VERSION 5.8 ;
BUSBITCHARS "[]" ;
DIVIDERCHAR "/" ;
UNITS
    DATABASE MICRONS 1000 ;
END UNITS

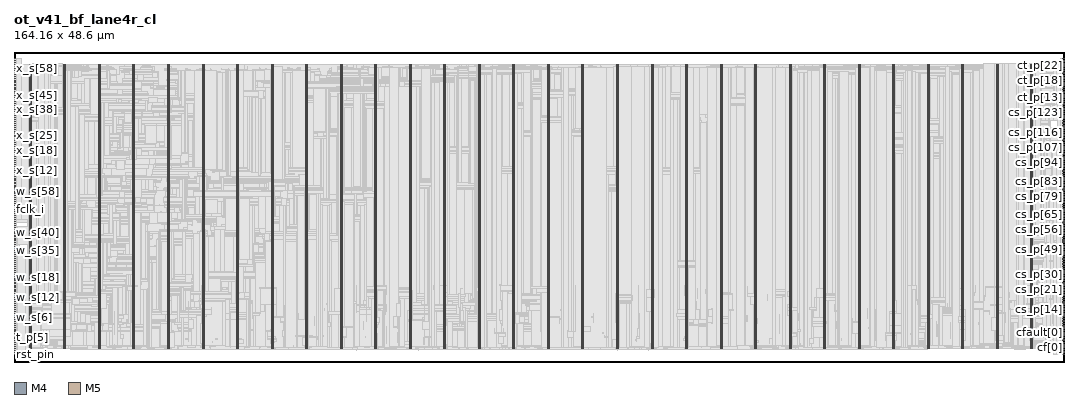
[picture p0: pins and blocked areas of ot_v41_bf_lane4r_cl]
MACRO ot_v41_bf_lane4r_cl
  FOREIGN ot_v41_bf_lane4r_cl 0 0 ;
  CLASS BLOCK ;
  SIZE 164.16 BY 48.6 ;
  PIN cf[0]
    DIRECTION OUTPUT ;
    USE SIGNAL ;
    PORT
      LAYER M4 ;
        RECT  163.968 2.208 164.16 2.232 ;
    END
  END cf[0]
  PIN cf[1]
    DIRECTION OUTPUT ;
    USE SIGNAL ;
    PORT
      LAYER M4 ;
        RECT  163.968 2.496 164.16 2.52 ;
    END
  END cf[1]
  PIN cf[2]
    DIRECTION OUTPUT ;
    USE SIGNAL ;
    PORT
      LAYER M4 ;
        RECT  163.968 2.784 164.16 2.808 ;
    END
  END cf[2]
  PIN cf[3]
    DIRECTION OUTPUT ;
    USE SIGNAL ;
    PORT
      LAYER M4 ;
        RECT  163.968 3.024 164.16 3.048 ;
    END
  END cf[3]
  PIN cfault[0]
    DIRECTION OUTPUT ;
    USE SIGNAL ;
    PORT
      LAYER M4 ;
        RECT  163.968 3.312 164.16 3.336 ;
    END
  END cfault[0]
  PIN cfault[1]
    DIRECTION OUTPUT ;
    USE SIGNAL ;
    PORT
      LAYER M4 ;
        RECT  163.968 3.552 164.16 3.576 ;
    END
  END cfault[1]
  PIN cfault[2]
    DIRECTION OUTPUT ;
    USE SIGNAL ;
    PORT
      LAYER M4 ;
        RECT  163.968 3.84 164.16 3.864 ;
    END
  END cfault[2]
  PIN cfault[3]
    DIRECTION OUTPUT ;
    USE SIGNAL ;
    PORT
      LAYER M4 ;
        RECT  163.968 4.128 164.16 4.152 ;
    END
  END cfault[3]
  PIN cs_p[0]
    DIRECTION OUTPUT ;
    USE SIGNAL ;
    PORT
      LAYER M4 ;
        RECT  163.968 4.368 164.16 4.392 ;
    END
  END cs_p[0]
  PIN cs_p[100]
    DIRECTION OUTPUT ;
    USE SIGNAL ;
    PORT
      LAYER M4 ;
        RECT  163.968 31.584 164.16 31.608 ;
    END
  END cs_p[100]
  PIN cs_p[101]
    DIRECTION OUTPUT ;
    USE SIGNAL ;
    PORT
      LAYER M4 ;
        RECT  163.968 31.872 164.16 31.896 ;
    END
  END cs_p[101]
  PIN cs_p[102]
    DIRECTION OUTPUT ;
    USE SIGNAL ;
    PORT
      LAYER M4 ;
        RECT  163.968 32.112 164.16 32.136 ;
    END
  END cs_p[102]
  PIN cs_p[103]
    DIRECTION OUTPUT ;
    USE SIGNAL ;
    PORT
      LAYER M4 ;
        RECT  163.968 32.4 164.16 32.424 ;
    END
  END cs_p[103]
  PIN cs_p[104]
    DIRECTION OUTPUT ;
    USE SIGNAL ;
    PORT
      LAYER M4 ;
        RECT  163.968 32.64 164.16 32.664 ;
    END
  END cs_p[104]
  PIN cs_p[105]
    DIRECTION OUTPUT ;
    USE SIGNAL ;
    PORT
      LAYER M4 ;
        RECT  163.968 32.928 164.16 32.952 ;
    END
  END cs_p[105]
  PIN cs_p[106]
    DIRECTION OUTPUT ;
    USE SIGNAL ;
    PORT
      LAYER M4 ;
        RECT  163.968 33.216 164.16 33.24 ;
    END
  END cs_p[106]
  PIN cs_p[107]
    DIRECTION OUTPUT ;
    USE SIGNAL ;
    PORT
      LAYER M4 ;
        RECT  163.968 33.456 164.16 33.48 ;
    END
  END cs_p[107]
  PIN cs_p[108]
    DIRECTION OUTPUT ;
    USE SIGNAL ;
    PORT
      LAYER M4 ;
        RECT  163.968 33.744 164.16 33.768 ;
    END
  END cs_p[108]
  PIN cs_p[109]
    DIRECTION OUTPUT ;
    USE SIGNAL ;
    PORT
      LAYER M4 ;
        RECT  163.968 34.032 164.16 34.056 ;
    END
  END cs_p[109]
  PIN cs_p[10]
    DIRECTION OUTPUT ;
    USE SIGNAL ;
    PORT
      LAYER M4 ;
        RECT  163.968 7.056 164.16 7.08 ;
    END
  END cs_p[10]
  PIN cs_p[110]
    DIRECTION OUTPUT ;
    USE SIGNAL ;
    PORT
      LAYER M4 ;
        RECT  163.968 34.272 164.16 34.296 ;
    END
  END cs_p[110]
  PIN cs_p[111]
    DIRECTION OUTPUT ;
    USE SIGNAL ;
    PORT
      LAYER M4 ;
        RECT  163.968 34.56 164.16 34.584 ;
    END
  END cs_p[111]
  PIN cs_p[112]
    DIRECTION OUTPUT ;
    USE SIGNAL ;
    PORT
      LAYER M4 ;
        RECT  163.968 34.8 164.16 34.824 ;
    END
  END cs_p[112]
  PIN cs_p[113]
    DIRECTION OUTPUT ;
    USE SIGNAL ;
    PORT
      LAYER M4 ;
        RECT  163.968 35.088 164.16 35.112 ;
    END
  END cs_p[113]
  PIN cs_p[114]
    DIRECTION OUTPUT ;
    USE SIGNAL ;
    PORT
      LAYER M4 ;
        RECT  163.968 35.376 164.16 35.4 ;
    END
  END cs_p[114]
  PIN cs_p[115]
    DIRECTION OUTPUT ;
    USE SIGNAL ;
    PORT
      LAYER M4 ;
        RECT  163.968 35.616 164.16 35.64 ;
    END
  END cs_p[115]
  PIN cs_p[116]
    DIRECTION OUTPUT ;
    USE SIGNAL ;
    PORT
      LAYER M4 ;
        RECT  163.968 35.904 164.16 35.928 ;
    END
  END cs_p[116]
  PIN cs_p[117]
    DIRECTION OUTPUT ;
    USE SIGNAL ;
    PORT
      LAYER M4 ;
        RECT  163.968 36.144 164.16 36.168 ;
    END
  END cs_p[117]
  PIN cs_p[118]
    DIRECTION OUTPUT ;
    USE SIGNAL ;
    PORT
      LAYER M4 ;
        RECT  163.968 36.432 164.16 36.456 ;
    END
  END cs_p[118]
  PIN cs_p[119]
    DIRECTION OUTPUT ;
    USE SIGNAL ;
    PORT
      LAYER M4 ;
        RECT  163.968 36.72 164.16 36.744 ;
    END
  END cs_p[119]
  PIN cs_p[11]
    DIRECTION OUTPUT ;
    USE SIGNAL ;
    PORT
      LAYER M4 ;
        RECT  163.968 7.344 164.16 7.368 ;
    END
  END cs_p[11]
  PIN cs_p[120]
    DIRECTION OUTPUT ;
    USE SIGNAL ;
    PORT
      LAYER M4 ;
        RECT  163.968 36.96 164.16 36.984 ;
    END
  END cs_p[120]
  PIN cs_p[121]
    DIRECTION OUTPUT ;
    USE SIGNAL ;
    PORT
      LAYER M4 ;
        RECT  163.968 37.248 164.16 37.272 ;
    END
  END cs_p[121]
  PIN cs_p[122]
    DIRECTION OUTPUT ;
    USE SIGNAL ;
    PORT
      LAYER M4 ;
        RECT  163.968 37.488 164.16 37.512 ;
    END
  END cs_p[122]
  PIN cs_p[123]
    DIRECTION OUTPUT ;
    USE SIGNAL ;
    PORT
      LAYER M4 ;
        RECT  163.968 37.776 164.16 37.8 ;
    END
  END cs_p[123]
  PIN cs_p[124]
    DIRECTION OUTPUT ;
    USE SIGNAL ;
    PORT
      LAYER M4 ;
        RECT  163.968 38.064 164.16 38.088 ;
    END
  END cs_p[124]
  PIN cs_p[125]
    DIRECTION OUTPUT ;
    USE SIGNAL ;
    PORT
      LAYER M4 ;
        RECT  163.968 38.304 164.16 38.328 ;
    END
  END cs_p[125]
  PIN cs_p[126]
    DIRECTION OUTPUT ;
    USE SIGNAL ;
    PORT
      LAYER M4 ;
        RECT  163.968 38.592 164.16 38.616 ;
    END
  END cs_p[126]
  PIN cs_p[127]
    DIRECTION OUTPUT ;
    USE SIGNAL ;
    PORT
      LAYER M4 ;
        RECT  163.968 38.88 164.16 38.904 ;
    END
  END cs_p[127]
  PIN cs_p[12]
    DIRECTION OUTPUT ;
    USE SIGNAL ;
    PORT
      LAYER M4 ;
        RECT  163.968 7.632 164.16 7.656 ;
    END
  END cs_p[12]
  PIN cs_p[13]
    DIRECTION OUTPUT ;
    USE SIGNAL ;
    PORT
      LAYER M4 ;
        RECT  163.968 7.872 164.16 7.896 ;
    END
  END cs_p[13]
  PIN cs_p[14]
    DIRECTION OUTPUT ;
    USE SIGNAL ;
    PORT
      LAYER M4 ;
        RECT  163.968 8.16 164.16 8.184 ;
    END
  END cs_p[14]
  PIN cs_p[15]
    DIRECTION OUTPUT ;
    USE SIGNAL ;
    PORT
      LAYER M4 ;
        RECT  163.968 8.4 164.16 8.424 ;
    END
  END cs_p[15]
  PIN cs_p[16]
    DIRECTION OUTPUT ;
    USE SIGNAL ;
    PORT
      LAYER M4 ;
        RECT  163.968 8.688 164.16 8.712 ;
    END
  END cs_p[16]
  PIN cs_p[17]
    DIRECTION OUTPUT ;
    USE SIGNAL ;
    PORT
      LAYER M4 ;
        RECT  163.968 8.976 164.16 9 ;
    END
  END cs_p[17]
  PIN cs_p[18]
    DIRECTION OUTPUT ;
    USE SIGNAL ;
    PORT
      LAYER M4 ;
        RECT  163.968 9.216 164.16 9.24 ;
    END
  END cs_p[18]
  PIN cs_p[19]
    DIRECTION OUTPUT ;
    USE SIGNAL ;
    PORT
      LAYER M4 ;
        RECT  163.968 9.504 164.16 9.528 ;
    END
  END cs_p[19]
  PIN cs_p[1]
    DIRECTION OUTPUT ;
    USE SIGNAL ;
    PORT
      LAYER M4 ;
        RECT  163.968 4.656 164.16 4.68 ;
    END
  END cs_p[1]
  PIN cs_p[20]
    DIRECTION OUTPUT ;
    USE SIGNAL ;
    PORT
      LAYER M4 ;
        RECT  163.968 9.744 164.16 9.768 ;
    END
  END cs_p[20]
  PIN cs_p[21]
    DIRECTION OUTPUT ;
    USE SIGNAL ;
    PORT
      LAYER M4 ;
        RECT  163.968 10.032 164.16 10.056 ;
    END
  END cs_p[21]
  PIN cs_p[22]
    DIRECTION OUTPUT ;
    USE SIGNAL ;
    PORT
      LAYER M4 ;
        RECT  163.968 10.32 164.16 10.344 ;
    END
  END cs_p[22]
  PIN cs_p[23]
    DIRECTION OUTPUT ;
    USE SIGNAL ;
    PORT
      LAYER M4 ;
        RECT  163.968 10.56 164.16 10.584 ;
    END
  END cs_p[23]
  PIN cs_p[24]
    DIRECTION OUTPUT ;
    USE SIGNAL ;
    PORT
      LAYER M4 ;
        RECT  163.968 10.848 164.16 10.872 ;
    END
  END cs_p[24]
  PIN cs_p[25]
    DIRECTION OUTPUT ;
    USE SIGNAL ;
    PORT
      LAYER M4 ;
        RECT  163.968 11.136 164.16 11.16 ;
    END
  END cs_p[25]
  PIN cs_p[26]
    DIRECTION OUTPUT ;
    USE SIGNAL ;
    PORT
      LAYER M4 ;
        RECT  163.968 11.376 164.16 11.4 ;
    END
  END cs_p[26]
  PIN cs_p[27]
    DIRECTION OUTPUT ;
    USE SIGNAL ;
    PORT
      LAYER M4 ;
        RECT  163.968 11.664 164.16 11.688 ;
    END
  END cs_p[27]
  PIN cs_p[28]
    DIRECTION OUTPUT ;
    USE SIGNAL ;
    PORT
      LAYER M4 ;
        RECT  163.968 11.904 164.16 11.928 ;
    END
  END cs_p[28]
  PIN cs_p[29]
    DIRECTION OUTPUT ;
    USE SIGNAL ;
    PORT
      LAYER M4 ;
        RECT  163.968 12.192 164.16 12.216 ;
    END
  END cs_p[29]
  PIN cs_p[2]
    DIRECTION OUTPUT ;
    USE SIGNAL ;
    PORT
      LAYER M4 ;
        RECT  163.968 4.896 164.16 4.92 ;
    END
  END cs_p[2]
  PIN cs_p[30]
    DIRECTION OUTPUT ;
    USE SIGNAL ;
    PORT
      LAYER M4 ;
        RECT  163.968 12.48 164.16 12.504 ;
    END
  END cs_p[30]
  PIN cs_p[31]
    DIRECTION OUTPUT ;
    USE SIGNAL ;
    PORT
      LAYER M4 ;
        RECT  163.968 12.72 164.16 12.744 ;
    END
  END cs_p[31]
  PIN cs_p[32]
    DIRECTION OUTPUT ;
    USE SIGNAL ;
    PORT
      LAYER M4 ;
        RECT  163.968 13.008 164.16 13.032 ;
    END
  END cs_p[32]
  PIN cs_p[33]
    DIRECTION OUTPUT ;
    USE SIGNAL ;
    PORT
      LAYER M4 ;
        RECT  163.968 13.248 164.16 13.272 ;
    END
  END cs_p[33]
  PIN cs_p[34]
    DIRECTION OUTPUT ;
    USE SIGNAL ;
    PORT
      LAYER M4 ;
        RECT  163.968 13.536 164.16 13.56 ;
    END
  END cs_p[34]
  PIN cs_p[35]
    DIRECTION OUTPUT ;
    USE SIGNAL ;
    PORT
      LAYER M4 ;
        RECT  163.968 13.824 164.16 13.848 ;
    END
  END cs_p[35]
  PIN cs_p[36]
    DIRECTION OUTPUT ;
    USE SIGNAL ;
    PORT
      LAYER M4 ;
        RECT  163.968 14.064 164.16 14.088 ;
    END
  END cs_p[36]
  PIN cs_p[37]
    DIRECTION OUTPUT ;
    USE SIGNAL ;
    PORT
      LAYER M4 ;
        RECT  163.968 14.352 164.16 14.376 ;
    END
  END cs_p[37]
  PIN cs_p[38]
    DIRECTION OUTPUT ;
    USE SIGNAL ;
    PORT
      LAYER M4 ;
        RECT  163.968 14.592 164.16 14.616 ;
    END
  END cs_p[38]
  PIN cs_p[39]
    DIRECTION OUTPUT ;
    USE SIGNAL ;
    PORT
      LAYER M4 ;
        RECT  163.968 14.88 164.16 14.904 ;
    END
  END cs_p[39]
  PIN cs_p[3]
    DIRECTION OUTPUT ;
    USE SIGNAL ;
    PORT
      LAYER M4 ;
        RECT  163.968 5.184 164.16 5.208 ;
    END
  END cs_p[3]
  PIN cs_p[40]
    DIRECTION OUTPUT ;
    USE SIGNAL ;
    PORT
      LAYER M4 ;
        RECT  163.968 15.168 164.16 15.192 ;
    END
  END cs_p[40]
  PIN cs_p[41]
    DIRECTION OUTPUT ;
    USE SIGNAL ;
    PORT
      LAYER M4 ;
        RECT  163.968 15.408 164.16 15.432 ;
    END
  END cs_p[41]
  PIN cs_p[42]
    DIRECTION OUTPUT ;
    USE SIGNAL ;
    PORT
      LAYER M4 ;
        RECT  163.968 15.696 164.16 15.72 ;
    END
  END cs_p[42]
  PIN cs_p[43]
    DIRECTION OUTPUT ;
    USE SIGNAL ;
    PORT
      LAYER M4 ;
        RECT  163.968 15.984 164.16 16.008 ;
    END
  END cs_p[43]
  PIN cs_p[44]
    DIRECTION OUTPUT ;
    USE SIGNAL ;
    PORT
      LAYER M4 ;
        RECT  163.968 16.224 164.16 16.248 ;
    END
  END cs_p[44]
  PIN cs_p[45]
    DIRECTION OUTPUT ;
    USE SIGNAL ;
    PORT
      LAYER M4 ;
        RECT  163.968 16.512 164.16 16.536 ;
    END
  END cs_p[45]
  PIN cs_p[46]
    DIRECTION OUTPUT ;
    USE SIGNAL ;
    PORT
      LAYER M4 ;
        RECT  163.968 16.752 164.16 16.776 ;
    END
  END cs_p[46]
  PIN cs_p[47]
    DIRECTION OUTPUT ;
    USE SIGNAL ;
    PORT
      LAYER M4 ;
        RECT  163.968 17.04 164.16 17.064 ;
    END
  END cs_p[47]
  PIN cs_p[48]
    DIRECTION OUTPUT ;
    USE SIGNAL ;
    PORT
      LAYER M4 ;
        RECT  163.968 17.328 164.16 17.352 ;
    END
  END cs_p[48]
  PIN cs_p[49]
    DIRECTION OUTPUT ;
    USE SIGNAL ;
    PORT
      LAYER M4 ;
        RECT  163.968 17.568 164.16 17.592 ;
    END
  END cs_p[49]
  PIN cs_p[4]
    DIRECTION OUTPUT ;
    USE SIGNAL ;
    PORT
      LAYER M4 ;
        RECT  163.968 5.472 164.16 5.496 ;
    END
  END cs_p[4]
  PIN cs_p[50]
    DIRECTION OUTPUT ;
    USE SIGNAL ;
    PORT
      LAYER M4 ;
        RECT  163.968 17.856 164.16 17.88 ;
    END
  END cs_p[50]
  PIN cs_p[51]
    DIRECTION OUTPUT ;
    USE SIGNAL ;
    PORT
      LAYER M4 ;
        RECT  163.968 18.096 164.16 18.12 ;
    END
  END cs_p[51]
  PIN cs_p[52]
    DIRECTION OUTPUT ;
    USE SIGNAL ;
    PORT
      LAYER M4 ;
        RECT  163.968 18.384 164.16 18.408 ;
    END
  END cs_p[52]
  PIN cs_p[53]
    DIRECTION OUTPUT ;
    USE SIGNAL ;
    PORT
      LAYER M4 ;
        RECT  163.968 18.672 164.16 18.696 ;
    END
  END cs_p[53]
  PIN cs_p[54]
    DIRECTION OUTPUT ;
    USE SIGNAL ;
    PORT
      LAYER M4 ;
        RECT  163.968 18.912 164.16 18.936 ;
    END
  END cs_p[54]
  PIN cs_p[55]
    DIRECTION OUTPUT ;
    USE SIGNAL ;
    PORT
      LAYER M4 ;
        RECT  163.968 19.2 164.16 19.224 ;
    END
  END cs_p[55]
  PIN cs_p[56]
    DIRECTION OUTPUT ;
    USE SIGNAL ;
    PORT
      LAYER M4 ;
        RECT  163.968 19.44 164.16 19.464 ;
    END
  END cs_p[56]
  PIN cs_p[57]
    DIRECTION OUTPUT ;
    USE SIGNAL ;
    PORT
      LAYER M4 ;
        RECT  163.968 19.728 164.16 19.752 ;
    END
  END cs_p[57]
  PIN cs_p[58]
    DIRECTION OUTPUT ;
    USE SIGNAL ;
    PORT
      LAYER M4 ;
        RECT  163.968 20.016 164.16 20.04 ;
    END
  END cs_p[58]
  PIN cs_p[59]
    DIRECTION OUTPUT ;
    USE SIGNAL ;
    PORT
      LAYER M4 ;
        RECT  163.968 20.256 164.16 20.28 ;
    END
  END cs_p[59]
  PIN cs_p[5]
    DIRECTION OUTPUT ;
    USE SIGNAL ;
    PORT
      LAYER M4 ;
        RECT  163.968 5.712 164.16 5.736 ;
    END
  END cs_p[5]
  PIN cs_p[60]
    DIRECTION OUTPUT ;
    USE SIGNAL ;
    PORT
      LAYER M4 ;
        RECT  163.968 20.544 164.16 20.568 ;
    END
  END cs_p[60]
  PIN cs_p[61]
    DIRECTION OUTPUT ;
    USE SIGNAL ;
    PORT
      LAYER M4 ;
        RECT  163.968 20.832 164.16 20.856 ;
    END
  END cs_p[61]
  PIN cs_p[62]
    DIRECTION OUTPUT ;
    USE SIGNAL ;
    PORT
      LAYER M4 ;
        RECT  163.968 21.072 164.16 21.096 ;
    END
  END cs_p[62]
  PIN cs_p[63]
    DIRECTION OUTPUT ;
    USE SIGNAL ;
    PORT
      LAYER M4 ;
        RECT  163.968 21.36 164.16 21.384 ;
    END
  END cs_p[63]
  PIN cs_p[64]
    DIRECTION OUTPUT ;
    USE SIGNAL ;
    PORT
      LAYER M4 ;
        RECT  163.968 21.6 164.16 21.624 ;
    END
  END cs_p[64]
  PIN cs_p[65]
    DIRECTION OUTPUT ;
    USE SIGNAL ;
    PORT
      LAYER M4 ;
        RECT  163.968 21.888 164.16 21.912 ;
    END
  END cs_p[65]
  PIN cs_p[66]
    DIRECTION OUTPUT ;
    USE SIGNAL ;
    PORT
      LAYER M4 ;
        RECT  163.968 22.176 164.16 22.2 ;
    END
  END cs_p[66]
  PIN cs_p[67]
    DIRECTION OUTPUT ;
    USE SIGNAL ;
    PORT
      LAYER M4 ;
        RECT  163.968 22.416 164.16 22.44 ;
    END
  END cs_p[67]
  PIN cs_p[68]
    DIRECTION OUTPUT ;
    USE SIGNAL ;
    PORT
      LAYER M4 ;
        RECT  163.968 22.704 164.16 22.728 ;
    END
  END cs_p[68]
  PIN cs_p[69]
    DIRECTION OUTPUT ;
    USE SIGNAL ;
    PORT
      LAYER M4 ;
        RECT  163.968 22.944 164.16 22.968 ;
    END
  END cs_p[69]
  PIN cs_p[6]
    DIRECTION OUTPUT ;
    USE SIGNAL ;
    PORT
      LAYER M4 ;
        RECT  163.968 6 164.16 6.024 ;
    END
  END cs_p[6]
  PIN cs_p[70]
    DIRECTION OUTPUT ;
    USE SIGNAL ;
    PORT
      LAYER M4 ;
        RECT  163.968 23.232 164.16 23.256 ;
    END
  END cs_p[70]
  PIN cs_p[71]
    DIRECTION OUTPUT ;
    USE SIGNAL ;
    PORT
      LAYER M4 ;
        RECT  163.968 23.52 164.16 23.544 ;
    END
  END cs_p[71]
  PIN cs_p[72]
    DIRECTION OUTPUT ;
    USE SIGNAL ;
    PORT
      LAYER M4 ;
        RECT  163.968 23.76 164.16 23.784 ;
    END
  END cs_p[72]
  PIN cs_p[73]
    DIRECTION OUTPUT ;
    USE SIGNAL ;
    PORT
      LAYER M4 ;
        RECT  163.968 24.048 164.16 24.072 ;
    END
  END cs_p[73]
  PIN cs_p[74]
    DIRECTION OUTPUT ;
    USE SIGNAL ;
    PORT
      LAYER M4 ;
        RECT  163.968 24.576 164.16 24.6 ;
    END
  END cs_p[74]
  PIN cs_p[75]
    DIRECTION OUTPUT ;
    USE SIGNAL ;
    PORT
      LAYER M4 ;
        RECT  163.968 24.864 164.16 24.888 ;
    END
  END cs_p[75]
  PIN cs_p[76]
    DIRECTION OUTPUT ;
    USE SIGNAL ;
    PORT
      LAYER M4 ;
        RECT  163.968 25.104 164.16 25.128 ;
    END
  END cs_p[76]
  PIN cs_p[77]
    DIRECTION OUTPUT ;
    USE SIGNAL ;
    PORT
      LAYER M4 ;
        RECT  163.968 25.392 164.16 25.416 ;
    END
  END cs_p[77]
  PIN cs_p[78]
    DIRECTION OUTPUT ;
    USE SIGNAL ;
    PORT
      LAYER M4 ;
        RECT  163.968 25.68 164.16 25.704 ;
    END
  END cs_p[78]
  PIN cs_p[79]
    DIRECTION OUTPUT ;
    USE SIGNAL ;
    PORT
      LAYER M4 ;
        RECT  163.968 25.92 164.16 25.944 ;
    END
  END cs_p[79]
  PIN cs_p[7]
    DIRECTION OUTPUT ;
    USE SIGNAL ;
    PORT
      LAYER M4 ;
        RECT  163.968 6.288 164.16 6.312 ;
    END
  END cs_p[7]
  PIN cs_p[80]
    DIRECTION OUTPUT ;
    USE SIGNAL ;
    PORT
      LAYER M4 ;
        RECT  163.968 26.208 164.16 26.232 ;
    END
  END cs_p[80]
  PIN cs_p[81]
    DIRECTION OUTPUT ;
    USE SIGNAL ;
    PORT
      LAYER M4 ;
        RECT  163.968 26.448 164.16 26.472 ;
    END
  END cs_p[81]
  PIN cs_p[82]
    DIRECTION OUTPUT ;
    USE SIGNAL ;
    PORT
      LAYER M4 ;
        RECT  163.968 26.736 164.16 26.76 ;
    END
  END cs_p[82]
  PIN cs_p[83]
    DIRECTION OUTPUT ;
    USE SIGNAL ;
    PORT
      LAYER M4 ;
        RECT  163.968 27.024 164.16 27.048 ;
    END
  END cs_p[83]
  PIN cs_p[84]
    DIRECTION OUTPUT ;
    USE SIGNAL ;
    PORT
      LAYER M4 ;
        RECT  163.968 27.264 164.16 27.288 ;
    END
  END cs_p[84]
  PIN cs_p[85]
    DIRECTION OUTPUT ;
    USE SIGNAL ;
    PORT
      LAYER M4 ;
        RECT  163.968 27.552 164.16 27.576 ;
    END
  END cs_p[85]
  PIN cs_p[86]
    DIRECTION OUTPUT ;
    USE SIGNAL ;
    PORT
      LAYER M4 ;
        RECT  163.968 27.792 164.16 27.816 ;
    END
  END cs_p[86]
  PIN cs_p[87]
    DIRECTION OUTPUT ;
    USE SIGNAL ;
    PORT
      LAYER M4 ;
        RECT  163.968 28.08 164.16 28.104 ;
    END
  END cs_p[87]
  PIN cs_p[88]
    DIRECTION OUTPUT ;
    USE SIGNAL ;
    PORT
      LAYER M4 ;
        RECT  163.968 28.368 164.16 28.392 ;
    END
  END cs_p[88]
  PIN cs_p[89]
    DIRECTION OUTPUT ;
    USE SIGNAL ;
    PORT
      LAYER M4 ;
        RECT  163.968 28.608 164.16 28.632 ;
    END
  END cs_p[89]
  PIN cs_p[8]
    DIRECTION OUTPUT ;
    USE SIGNAL ;
    PORT
      LAYER M4 ;
        RECT  163.968 6.528 164.16 6.552 ;
    END
  END cs_p[8]
  PIN cs_p[90]
    DIRECTION OUTPUT ;
    USE SIGNAL ;
    PORT
      LAYER M4 ;
        RECT  163.968 28.896 164.16 28.92 ;
    END
  END cs_p[90]
  PIN cs_p[91]
    DIRECTION OUTPUT ;
    USE SIGNAL ;
    PORT
      LAYER M4 ;
        RECT  163.968 29.184 164.16 29.208 ;
    END
  END cs_p[91]
  PIN cs_p[92]
    DIRECTION OUTPUT ;
    USE SIGNAL ;
    PORT
      LAYER M4 ;
        RECT  163.968 29.424 164.16 29.448 ;
    END
  END cs_p[92]
  PIN cs_p[93]
    DIRECTION OUTPUT ;
    USE SIGNAL ;
    PORT
      LAYER M4 ;
        RECT  163.968 29.712 164.16 29.736 ;
    END
  END cs_p[93]
  PIN cs_p[94]
    DIRECTION OUTPUT ;
    USE SIGNAL ;
    PORT
      LAYER M4 ;
        RECT  163.968 29.952 164.16 29.976 ;
    END
  END cs_p[94]
  PIN cs_p[95]
    DIRECTION OUTPUT ;
    USE SIGNAL ;
    PORT
      LAYER M4 ;
        RECT  163.968 30.24 164.16 30.264 ;
    END
  END cs_p[95]
  PIN cs_p[96]
    DIRECTION OUTPUT ;
    USE SIGNAL ;
    PORT
      LAYER M4 ;
        RECT  163.968 30.528 164.16 30.552 ;
    END
  END cs_p[96]
  PIN cs_p[97]
    DIRECTION OUTPUT ;
    USE SIGNAL ;
    PORT
      LAYER M4 ;
        RECT  163.968 30.768 164.16 30.792 ;
    END
  END cs_p[97]
  PIN cs_p[98]
    DIRECTION OUTPUT ;
    USE SIGNAL ;
    PORT
      LAYER M4 ;
        RECT  163.968 31.056 164.16 31.08 ;
    END
  END cs_p[98]
  PIN cs_p[99]
    DIRECTION OUTPUT ;
    USE SIGNAL ;
    PORT
      LAYER M4 ;
        RECT  163.968 31.296 164.16 31.32 ;
    END
  END cs_p[99]
  PIN cs_p[9]
    DIRECTION OUTPUT ;
    USE SIGNAL ;
    PORT
      LAYER M4 ;
        RECT  163.968 6.816 164.16 6.84 ;
    END
  END cs_p[9]
  PIN ct_p[0]
    DIRECTION OUTPUT ;
    USE SIGNAL ;
    PORT
      LAYER M4 ;
        RECT  163.968 39.12 164.16 39.144 ;
    END
  END ct_p[0]
  PIN ct_p[10]
    DIRECTION OUTPUT ;
    USE SIGNAL ;
    PORT
      LAYER M4 ;
        RECT  163.968 41.808 164.16 41.832 ;
    END
  END ct_p[10]
  PIN ct_p[11]
    DIRECTION OUTPUT ;
    USE SIGNAL ;
    PORT
      LAYER M4 ;
        RECT  163.968 42.096 164.16 42.12 ;
    END
  END ct_p[11]
  PIN ct_p[12]
    DIRECTION OUTPUT ;
    USE SIGNAL ;
    PORT
      LAYER M4 ;
        RECT  163.968 42.336 164.16 42.36 ;
    END
  END ct_p[12]
  PIN ct_p[13]
    DIRECTION OUTPUT ;
    USE SIGNAL ;
    PORT
      LAYER M4 ;
        RECT  163.968 42.624 164.16 42.648 ;
    END
  END ct_p[13]
  PIN ct_p[14]
    DIRECTION OUTPUT ;
    USE SIGNAL ;
    PORT
      LAYER M4 ;
        RECT  163.968 42.912 164.16 42.936 ;
    END
  END ct_p[14]
  PIN ct_p[15]
    DIRECTION OUTPUT ;
    USE SIGNAL ;
    PORT
      LAYER M4 ;
        RECT  163.968 43.152 164.16 43.176 ;
    END
  END ct_p[15]
  PIN ct_p[16]
    DIRECTION OUTPUT ;
    USE SIGNAL ;
    PORT
      LAYER M4 ;
        RECT  163.968 43.44 164.16 43.464 ;
    END
  END ct_p[16]
  PIN ct_p[17]
    DIRECTION OUTPUT ;
    USE SIGNAL ;
    PORT
      LAYER M4 ;
        RECT  163.968 43.728 164.16 43.752 ;
    END
  END ct_p[17]
  PIN ct_p[18]
    DIRECTION OUTPUT ;
    USE SIGNAL ;
    PORT
      LAYER M4 ;
        RECT  163.968 43.968 164.16 43.992 ;
    END
  END ct_p[18]
  PIN ct_p[19]
    DIRECTION OUTPUT ;
    USE SIGNAL ;
    PORT
      LAYER M4 ;
        RECT  163.968 44.256 164.16 44.28 ;
    END
  END ct_p[19]
  PIN ct_p[1]
    DIRECTION OUTPUT ;
    USE SIGNAL ;
    PORT
      LAYER M4 ;
        RECT  163.968 39.408 164.16 39.432 ;
    END
  END ct_p[1]
  PIN ct_p[20]
    DIRECTION OUTPUT ;
    USE SIGNAL ;
    PORT
      LAYER M4 ;
        RECT  163.968 44.496 164.16 44.52 ;
    END
  END ct_p[20]
  PIN ct_p[21]
    DIRECTION OUTPUT ;
    USE SIGNAL ;
    PORT
      LAYER M4 ;
        RECT  163.968 44.784 164.16 44.808 ;
    END
  END ct_p[21]
  PIN ct_p[22]
    DIRECTION OUTPUT ;
    USE SIGNAL ;
    PORT
      LAYER M4 ;
        RECT  163.968 45.072 164.16 45.096 ;
    END
  END ct_p[22]
  PIN ct_p[23]
    DIRECTION OUTPUT ;
    USE SIGNAL ;
    PORT
      LAYER M4 ;
        RECT  163.968 45.312 164.16 45.336 ;
    END
  END ct_p[23]
  PIN ct_p[24]
    DIRECTION OUTPUT ;
    USE SIGNAL ;
    PORT
      LAYER M4 ;
        RECT  163.968 45.6 164.16 45.624 ;
    END
  END ct_p[24]
  PIN ct_p[25]
    DIRECTION OUTPUT ;
    USE SIGNAL ;
    PORT
      LAYER M4 ;
        RECT  163.968 45.84 164.16 45.864 ;
    END
  END ct_p[25]
  PIN ct_p[26]
    DIRECTION OUTPUT ;
    USE SIGNAL ;
    PORT
      LAYER M4 ;
        RECT  163.968 46.128 164.16 46.152 ;
    END
  END ct_p[26]
  PIN ct_p[27]
    DIRECTION OUTPUT ;
    USE SIGNAL ;
    PORT
      LAYER M4 ;
        RECT  163.968 46.416 164.16 46.44 ;
    END
  END ct_p[27]
  PIN ct_p[28]
    DIRECTION OUTPUT ;
    USE SIGNAL ;
    PORT
      LAYER M4 ;
        RECT  163.968 46.656 164.16 46.68 ;
    END
  END ct_p[28]
  PIN ct_p[29]
    DIRECTION OUTPUT ;
    USE SIGNAL ;
    PORT
      LAYER M4 ;
        RECT  163.968 46.944 164.16 46.968 ;
    END
  END ct_p[29]
  PIN ct_p[2]
    DIRECTION OUTPUT ;
    USE SIGNAL ;
    PORT
      LAYER M4 ;
        RECT  163.968 39.648 164.16 39.672 ;
    END
  END ct_p[2]
  PIN ct_p[30]
    DIRECTION OUTPUT ;
    USE SIGNAL ;
    PORT
      LAYER M4 ;
        RECT  163.968 47.184 164.16 47.208 ;
    END
  END ct_p[30]
  PIN ct_p[31]
    DIRECTION OUTPUT ;
    USE SIGNAL ;
    PORT
      LAYER M4 ;
        RECT  163.968 47.472 164.16 47.496 ;
    END
  END ct_p[31]
  PIN ct_p[3]
    DIRECTION OUTPUT ;
    USE SIGNAL ;
    PORT
      LAYER M4 ;
        RECT  163.968 39.936 164.16 39.96 ;
    END
  END ct_p[3]
  PIN ct_p[4]
    DIRECTION OUTPUT ;
    USE SIGNAL ;
    PORT
      LAYER M4 ;
        RECT  163.968 40.224 164.16 40.248 ;
    END
  END ct_p[4]
  PIN ct_p[5]
    DIRECTION OUTPUT ;
    USE SIGNAL ;
    PORT
      LAYER M4 ;
        RECT  163.968 40.464 164.16 40.488 ;
    END
  END ct_p[5]
  PIN ct_p[6]
    DIRECTION OUTPUT ;
    USE SIGNAL ;
    PORT
      LAYER M4 ;
        RECT  163.968 40.752 164.16 40.776 ;
    END
  END ct_p[6]
  PIN ct_p[7]
    DIRECTION OUTPUT ;
    USE SIGNAL ;
    PORT
      LAYER M4 ;
        RECT  163.968 40.992 164.16 41.016 ;
    END
  END ct_p[7]
  PIN ct_p[8]
    DIRECTION OUTPUT ;
    USE SIGNAL ;
    PORT
      LAYER M4 ;
        RECT  163.968 41.28 164.16 41.304 ;
    END
  END ct_p[8]
  PIN ct_p[9]
    DIRECTION OUTPUT ;
    USE SIGNAL ;
    PORT
      LAYER M4 ;
        RECT  163.968 41.568 164.16 41.592 ;
    END
  END ct_p[9]
  PIN cv[0]
    DIRECTION OUTPUT ;
    USE SIGNAL ;
    PORT
      LAYER M4 ;
        RECT  163.968 1.152 164.16 1.176 ;
    END
  END cv[0]
  PIN cv[1]
    DIRECTION OUTPUT ;
    USE SIGNAL ;
    PORT
      LAYER M4 ;
        RECT  163.968 1.44 164.16 1.464 ;
    END
  END cv[1]
  PIN cv[2]
    DIRECTION OUTPUT ;
    USE SIGNAL ;
    PORT
      LAYER M4 ;
        RECT  163.968 1.68 164.16 1.704 ;
    END
  END cv[2]
  PIN cv[3]
    DIRECTION OUTPUT ;
    USE SIGNAL ;
    PORT
      LAYER M4 ;
        RECT  163.968 1.968 164.16 1.992 ;
    END
  END cv[3]
  PIN fclk
    DIRECTION INPUT ;
    USE SIGNAL ;
    PORT
      LAYER M4 ;
        RECT  0 24.144 0.192 24.168 ;
    END
  END fclk
  PIN fclk_i
    DIRECTION INPUT ;
    USE SIGNAL ;
    PORT
      LAYER M4 ;
        RECT  0 23.856 0.192 23.88 ;
    END
  END fclk_i
  PIN fclk_o
    DIRECTION INPUT ;
    USE SIGNAL ;
    PORT
      LAYER M4 ;
        RECT  163.968 24.336 164.16 24.36 ;
    END
  END fclk_o
  PIN rst_pin
    DIRECTION INPUT ;
    USE SIGNAL ;
    PORT
      LAYER M4 ;
        RECT  0 1.152 0.192 1.176 ;
    END
  END rst_pin
  PIN t_p[0]
    DIRECTION INPUT ;
    USE SIGNAL ;
    PORT
      LAYER M4 ;
        RECT  0 2.112 0.192 2.136 ;
    END
  END t_p[0]
  PIN t_p[10]
    DIRECTION INPUT ;
    USE SIGNAL ;
    PORT
      LAYER M4 ;
        RECT  0 5.328 0.192 5.352 ;
    END
  END t_p[10]
  PIN t_p[11]
    DIRECTION INPUT ;
    USE SIGNAL ;
    PORT
      LAYER M4 ;
        RECT  0 5.664 0.192 5.688 ;
    END
  END t_p[11]
  PIN t_p[12]
    DIRECTION INPUT ;
    USE SIGNAL ;
    PORT
      LAYER M4 ;
        RECT  0 5.952 0.192 5.976 ;
    END
  END t_p[12]
  PIN t_p[1]
    DIRECTION INPUT ;
    USE SIGNAL ;
    PORT
      LAYER M4 ;
        RECT  0 2.448 0.192 2.472 ;
    END
  END t_p[1]
  PIN t_p[2]
    DIRECTION INPUT ;
    USE SIGNAL ;
    PORT
      LAYER M4 ;
        RECT  0 2.784 0.192 2.808 ;
    END
  END t_p[2]
  PIN t_p[3]
    DIRECTION INPUT ;
    USE SIGNAL ;
    PORT
      LAYER M4 ;
        RECT  0 3.072 0.192 3.096 ;
    END
  END t_p[3]
  PIN t_p[4]
    DIRECTION INPUT ;
    USE SIGNAL ;
    PORT
      LAYER M4 ;
        RECT  0 3.408 0.192 3.432 ;
    END
  END t_p[4]
  PIN t_p[5]
    DIRECTION INPUT ;
    USE SIGNAL ;
    PORT
      LAYER M4 ;
        RECT  0 3.744 0.192 3.768 ;
    END
  END t_p[5]
  PIN t_p[6]
    DIRECTION INPUT ;
    USE SIGNAL ;
    PORT
      LAYER M4 ;
        RECT  0 4.032 0.192 4.056 ;
    END
  END t_p[6]
  PIN t_p[7]
    DIRECTION INPUT ;
    USE SIGNAL ;
    PORT
      LAYER M4 ;
        RECT  0 4.368 0.192 4.392 ;
    END
  END t_p[7]
  PIN t_p[8]
    DIRECTION INPUT ;
    USE SIGNAL ;
    PORT
      LAYER M4 ;
        RECT  0 4.704 0.192 4.728 ;
    END
  END t_p[8]
  PIN t_p[9]
    DIRECTION INPUT ;
    USE SIGNAL ;
    PORT
      LAYER M4 ;
        RECT  0 4.992 0.192 5.016 ;
    END
  END t_p[9]
  PIN v_s
    DIRECTION INPUT ;
    USE SIGNAL ;
    PORT
      LAYER M4 ;
        RECT  0 1.824 0.192 1.848 ;
    END
  END v_s
  PIN w_s[0]
    DIRECTION INPUT ;
    USE SIGNAL ;
    PORT
      LAYER M4 ;
        RECT  0 6.288 0.192 6.312 ;
    END
  END w_s[0]
  PIN w_s[10]
    DIRECTION INPUT ;
    USE SIGNAL ;
    PORT
      LAYER M4 ;
        RECT  0 9.456 0.192 9.48 ;
    END
  END w_s[10]
  PIN w_s[11]
    DIRECTION INPUT ;
    USE SIGNAL ;
    PORT
      LAYER M4 ;
        RECT  0 9.792 0.192 9.816 ;
    END
  END w_s[11]
  PIN w_s[12]
    DIRECTION INPUT ;
    USE SIGNAL ;
    PORT
      LAYER M4 ;
        RECT  0 10.128 0.192 10.152 ;
    END
  END w_s[12]
  PIN w_s[13]
    DIRECTION INPUT ;
    USE SIGNAL ;
    PORT
      LAYER M4 ;
        RECT  0 10.416 0.192 10.44 ;
    END
  END w_s[13]
  PIN w_s[14]
    DIRECTION INPUT ;
    USE SIGNAL ;
    PORT
      LAYER M4 ;
        RECT  0 10.752 0.192 10.776 ;
    END
  END w_s[14]
  PIN w_s[15]
    DIRECTION INPUT ;
    USE SIGNAL ;
    PORT
      LAYER M4 ;
        RECT  0 11.088 0.192 11.112 ;
    END
  END w_s[15]
  PIN w_s[16]
    DIRECTION INPUT ;
    USE SIGNAL ;
    PORT
      LAYER M4 ;
        RECT  0 11.376 0.192 11.4 ;
    END
  END w_s[16]
  PIN w_s[17]
    DIRECTION INPUT ;
    USE SIGNAL ;
    PORT
      LAYER M4 ;
        RECT  0 11.712 0.192 11.736 ;
    END
  END w_s[17]
  PIN w_s[18]
    DIRECTION INPUT ;
    USE SIGNAL ;
    PORT
      LAYER M4 ;
        RECT  0 12 0.192 12.024 ;
    END
  END w_s[18]
  PIN w_s[19]
    DIRECTION INPUT ;
    USE SIGNAL ;
    PORT
      LAYER M4 ;
        RECT  0 12.336 0.192 12.36 ;
    END
  END w_s[19]
  PIN w_s[1]
    DIRECTION INPUT ;
    USE SIGNAL ;
    PORT
      LAYER M4 ;
        RECT  0 6.576 0.192 6.6 ;
    END
  END w_s[1]
  PIN w_s[20]
    DIRECTION INPUT ;
    USE SIGNAL ;
    PORT
      LAYER M4 ;
        RECT  0 12.672 0.192 12.696 ;
    END
  END w_s[20]
  PIN w_s[21]
    DIRECTION INPUT ;
    USE SIGNAL ;
    PORT
      LAYER M4 ;
        RECT  0 12.96 0.192 12.984 ;
    END
  END w_s[21]
  PIN w_s[22]
    DIRECTION INPUT ;
    USE SIGNAL ;
    PORT
      LAYER M4 ;
        RECT  0 13.296 0.192 13.32 ;
    END
  END w_s[22]
  PIN w_s[23]
    DIRECTION INPUT ;
    USE SIGNAL ;
    PORT
      LAYER M4 ;
        RECT  0 13.632 0.192 13.656 ;
    END
  END w_s[23]
  PIN w_s[24]
    DIRECTION INPUT ;
    USE SIGNAL ;
    PORT
      LAYER M4 ;
        RECT  0 13.92 0.192 13.944 ;
    END
  END w_s[24]
  PIN w_s[25]
    DIRECTION INPUT ;
    USE SIGNAL ;
    PORT
      LAYER M4 ;
        RECT  0 14.256 0.192 14.28 ;
    END
  END w_s[25]
  PIN w_s[26]
    DIRECTION INPUT ;
    USE SIGNAL ;
    PORT
      LAYER M4 ;
        RECT  0 14.592 0.192 14.616 ;
    END
  END w_s[26]
  PIN w_s[27]
    DIRECTION INPUT ;
    USE SIGNAL ;
    PORT
      LAYER M4 ;
        RECT  0 14.88 0.192 14.904 ;
    END
  END w_s[27]
  PIN w_s[28]
    DIRECTION INPUT ;
    USE SIGNAL ;
    PORT
      LAYER M4 ;
        RECT  0 15.216 0.192 15.24 ;
    END
  END w_s[28]
  PIN w_s[29]
    DIRECTION INPUT ;
    USE SIGNAL ;
    PORT
      LAYER M4 ;
        RECT  0 15.552 0.192 15.576 ;
    END
  END w_s[29]
  PIN w_s[2]
    DIRECTION INPUT ;
    USE SIGNAL ;
    PORT
      LAYER M4 ;
        RECT  0 6.912 0.192 6.936 ;
    END
  END w_s[2]
  PIN w_s[30]
    DIRECTION INPUT ;
    USE SIGNAL ;
    PORT
      LAYER M4 ;
        RECT  0 15.84 0.192 15.864 ;
    END
  END w_s[30]
  PIN w_s[31]
    DIRECTION INPUT ;
    USE SIGNAL ;
    PORT
      LAYER M4 ;
        RECT  0 16.176 0.192 16.2 ;
    END
  END w_s[31]
  PIN w_s[32]
    DIRECTION INPUT ;
    USE SIGNAL ;
    PORT
      LAYER M4 ;
        RECT  0 16.512 0.192 16.536 ;
    END
  END w_s[32]
  PIN w_s[33]
    DIRECTION INPUT ;
    USE SIGNAL ;
    PORT
      LAYER M4 ;
        RECT  0 16.8 0.192 16.824 ;
    END
  END w_s[33]
  PIN w_s[34]
    DIRECTION INPUT ;
    USE SIGNAL ;
    PORT
      LAYER M4 ;
        RECT  0 17.136 0.192 17.16 ;
    END
  END w_s[34]
  PIN w_s[35]
    DIRECTION INPUT ;
    USE SIGNAL ;
    PORT
      LAYER M4 ;
        RECT  0 17.472 0.192 17.496 ;
    END
  END w_s[35]
  PIN w_s[36]
    DIRECTION INPUT ;
    USE SIGNAL ;
    PORT
      LAYER M4 ;
        RECT  0 17.76 0.192 17.784 ;
    END
  END w_s[36]
  PIN w_s[37]
    DIRECTION INPUT ;
    USE SIGNAL ;
    PORT
      LAYER M4 ;
        RECT  0 18.096 0.192 18.12 ;
    END
  END w_s[37]
  PIN w_s[38]
    DIRECTION INPUT ;
    USE SIGNAL ;
    PORT
      LAYER M4 ;
        RECT  0 18.384 0.192 18.408 ;
    END
  END w_s[38]
  PIN w_s[39]
    DIRECTION INPUT ;
    USE SIGNAL ;
    PORT
      LAYER M4 ;
        RECT  0 18.72 0.192 18.744 ;
    END
  END w_s[39]
  PIN w_s[3]
    DIRECTION INPUT ;
    USE SIGNAL ;
    PORT
      LAYER M4 ;
        RECT  0 7.248 0.192 7.272 ;
    END
  END w_s[3]
  PIN w_s[40]
    DIRECTION INPUT ;
    USE SIGNAL ;
    PORT
      LAYER M4 ;
        RECT  0 19.056 0.192 19.08 ;
    END
  END w_s[40]
  PIN w_s[41]
    DIRECTION INPUT ;
    USE SIGNAL ;
    PORT
      LAYER M4 ;
        RECT  0 19.344 0.192 19.368 ;
    END
  END w_s[41]
  PIN w_s[42]
    DIRECTION INPUT ;
    USE SIGNAL ;
    PORT
      LAYER M4 ;
        RECT  0 19.68 0.192 19.704 ;
    END
  END w_s[42]
  PIN w_s[43]
    DIRECTION INPUT ;
    USE SIGNAL ;
    PORT
      LAYER M4 ;
        RECT  0 20.016 0.192 20.04 ;
    END
  END w_s[43]
  PIN w_s[44]
    DIRECTION INPUT ;
    USE SIGNAL ;
    PORT
      LAYER M4 ;
        RECT  0 20.304 0.192 20.328 ;
    END
  END w_s[44]
  PIN w_s[45]
    DIRECTION INPUT ;
    USE SIGNAL ;
    PORT
      LAYER M4 ;
        RECT  0 20.64 0.192 20.664 ;
    END
  END w_s[45]
  PIN w_s[46]
    DIRECTION INPUT ;
    USE SIGNAL ;
    PORT
      LAYER M4 ;
        RECT  0 20.976 0.192 21 ;
    END
  END w_s[46]
  PIN w_s[47]
    DIRECTION INPUT ;
    USE SIGNAL ;
    PORT
      LAYER M4 ;
        RECT  0 21.264 0.192 21.288 ;
    END
  END w_s[47]
  PIN w_s[48]
    DIRECTION INPUT ;
    USE SIGNAL ;
    PORT
      LAYER M4 ;
        RECT  0 21.6 0.192 21.624 ;
    END
  END w_s[48]
  PIN w_s[49]
    DIRECTION INPUT ;
    USE SIGNAL ;
    PORT
      LAYER M4 ;
        RECT  0 21.936 0.192 21.96 ;
    END
  END w_s[49]
  PIN w_s[4]
    DIRECTION INPUT ;
    USE SIGNAL ;
    PORT
      LAYER M4 ;
        RECT  0 7.536 0.192 7.56 ;
    END
  END w_s[4]
  PIN w_s[50]
    DIRECTION INPUT ;
    USE SIGNAL ;
    PORT
      LAYER M4 ;
        RECT  0 22.224 0.192 22.248 ;
    END
  END w_s[50]
  PIN w_s[51]
    DIRECTION INPUT ;
    USE SIGNAL ;
    PORT
      LAYER M4 ;
        RECT  0 22.56 0.192 22.584 ;
    END
  END w_s[51]
  PIN w_s[52]
    DIRECTION INPUT ;
    USE SIGNAL ;
    PORT
      LAYER M4 ;
        RECT  0 22.896 0.192 22.92 ;
    END
  END w_s[52]
  PIN w_s[53]
    DIRECTION INPUT ;
    USE SIGNAL ;
    PORT
      LAYER M4 ;
        RECT  0 23.184 0.192 23.208 ;
    END
  END w_s[53]
  PIN w_s[54]
    DIRECTION INPUT ;
    USE SIGNAL ;
    PORT
      LAYER M4 ;
        RECT  0 23.52 0.192 23.544 ;
    END
  END w_s[54]
  PIN w_s[55]
    DIRECTION INPUT ;
    USE SIGNAL ;
    PORT
      LAYER M4 ;
        RECT  0 24.48 0.192 24.504 ;
    END
  END w_s[55]
  PIN w_s[56]
    DIRECTION INPUT ;
    USE SIGNAL ;
    PORT
      LAYER M4 ;
        RECT  0 24.768 0.192 24.792 ;
    END
  END w_s[56]
  PIN w_s[57]
    DIRECTION INPUT ;
    USE SIGNAL ;
    PORT
      LAYER M4 ;
        RECT  0 25.104 0.192 25.128 ;
    END
  END w_s[57]
  PIN w_s[58]
    DIRECTION INPUT ;
    USE SIGNAL ;
    PORT
      LAYER M4 ;
        RECT  0 25.44 0.192 25.464 ;
    END
  END w_s[58]
  PIN w_s[59]
    DIRECTION INPUT ;
    USE SIGNAL ;
    PORT
      LAYER M4 ;
        RECT  0 25.728 0.192 25.752 ;
    END
  END w_s[59]
  PIN w_s[5]
    DIRECTION INPUT ;
    USE SIGNAL ;
    PORT
      LAYER M4 ;
        RECT  0 7.872 0.192 7.896 ;
    END
  END w_s[5]
  PIN w_s[60]
    DIRECTION INPUT ;
    USE SIGNAL ;
    PORT
      LAYER M4 ;
        RECT  0 26.064 0.192 26.088 ;
    END
  END w_s[60]
  PIN w_s[61]
    DIRECTION INPUT ;
    USE SIGNAL ;
    PORT
      LAYER M4 ;
        RECT  0 26.4 0.192 26.424 ;
    END
  END w_s[61]
  PIN w_s[62]
    DIRECTION INPUT ;
    USE SIGNAL ;
    PORT
      LAYER M4 ;
        RECT  0 26.688 0.192 26.712 ;
    END
  END w_s[62]
  PIN w_s[63]
    DIRECTION INPUT ;
    USE SIGNAL ;
    PORT
      LAYER M4 ;
        RECT  0 27.024 0.192 27.048 ;
    END
  END w_s[63]
  PIN w_s[6]
    DIRECTION INPUT ;
    USE SIGNAL ;
    PORT
      LAYER M4 ;
        RECT  0 8.208 0.192 8.232 ;
    END
  END w_s[6]
  PIN w_s[7]
    DIRECTION INPUT ;
    USE SIGNAL ;
    PORT
      LAYER M4 ;
        RECT  0 8.496 0.192 8.52 ;
    END
  END w_s[7]
  PIN w_s[8]
    DIRECTION INPUT ;
    USE SIGNAL ;
    PORT
      LAYER M4 ;
        RECT  0 8.832 0.192 8.856 ;
    END
  END w_s[8]
  PIN w_s[9]
    DIRECTION INPUT ;
    USE SIGNAL ;
    PORT
      LAYER M4 ;
        RECT  0 9.168 0.192 9.192 ;
    END
  END w_s[9]
  PIN x_s[0]
    DIRECTION INPUT ;
    USE SIGNAL ;
    PORT
      LAYER M4 ;
        RECT  0 27.36 0.192 27.384 ;
    END
  END x_s[0]
  PIN x_s[10]
    DIRECTION INPUT ;
    USE SIGNAL ;
    PORT
      LAYER M4 ;
        RECT  0 30.528 0.192 30.552 ;
    END
  END x_s[10]
  PIN x_s[11]
    DIRECTION INPUT ;
    USE SIGNAL ;
    PORT
      LAYER M4 ;
        RECT  0 30.864 0.192 30.888 ;
    END
  END x_s[11]
  PIN x_s[12]
    DIRECTION INPUT ;
    USE SIGNAL ;
    PORT
      LAYER M4 ;
        RECT  0 31.152 0.192 31.176 ;
    END
  END x_s[12]
  PIN x_s[13]
    DIRECTION INPUT ;
    USE SIGNAL ;
    PORT
      LAYER M4 ;
        RECT  0 31.488 0.192 31.512 ;
    END
  END x_s[13]
  PIN x_s[14]
    DIRECTION INPUT ;
    USE SIGNAL ;
    PORT
      LAYER M4 ;
        RECT  0 31.824 0.192 31.848 ;
    END
  END x_s[14]
  PIN x_s[15]
    DIRECTION INPUT ;
    USE SIGNAL ;
    PORT
      LAYER M4 ;
        RECT  0 32.112 0.192 32.136 ;
    END
  END x_s[15]
  PIN x_s[16]
    DIRECTION INPUT ;
    USE SIGNAL ;
    PORT
      LAYER M4 ;
        RECT  0 32.448 0.192 32.472 ;
    END
  END x_s[16]
  PIN x_s[17]
    DIRECTION INPUT ;
    USE SIGNAL ;
    PORT
      LAYER M4 ;
        RECT  0 32.784 0.192 32.808 ;
    END
  END x_s[17]
  PIN x_s[18]
    DIRECTION INPUT ;
    USE SIGNAL ;
    PORT
      LAYER M4 ;
        RECT  0 33.072 0.192 33.096 ;
    END
  END x_s[18]
  PIN x_s[19]
    DIRECTION INPUT ;
    USE SIGNAL ;
    PORT
      LAYER M4 ;
        RECT  0 33.408 0.192 33.432 ;
    END
  END x_s[19]
  PIN x_s[1]
    DIRECTION INPUT ;
    USE SIGNAL ;
    PORT
      LAYER M4 ;
        RECT  0 27.648 0.192 27.672 ;
    END
  END x_s[1]
  PIN x_s[20]
    DIRECTION INPUT ;
    USE SIGNAL ;
    PORT
      LAYER M4 ;
        RECT  0 33.744 0.192 33.768 ;
    END
  END x_s[20]
  PIN x_s[21]
    DIRECTION INPUT ;
    USE SIGNAL ;
    PORT
      LAYER M4 ;
        RECT  0 34.032 0.192 34.056 ;
    END
  END x_s[21]
  PIN x_s[22]
    DIRECTION INPUT ;
    USE SIGNAL ;
    PORT
      LAYER M4 ;
        RECT  0 34.368 0.192 34.392 ;
    END
  END x_s[22]
  PIN x_s[23]
    DIRECTION INPUT ;
    USE SIGNAL ;
    PORT
      LAYER M4 ;
        RECT  0 34.704 0.192 34.728 ;
    END
  END x_s[23]
  PIN x_s[24]
    DIRECTION INPUT ;
    USE SIGNAL ;
    PORT
      LAYER M4 ;
        RECT  0 34.992 0.192 35.016 ;
    END
  END x_s[24]
  PIN x_s[25]
    DIRECTION INPUT ;
    USE SIGNAL ;
    PORT
      LAYER M4 ;
        RECT  0 35.328 0.192 35.352 ;
    END
  END x_s[25]
  PIN x_s[26]
    DIRECTION INPUT ;
    USE SIGNAL ;
    PORT
      LAYER M4 ;
        RECT  0 35.664 0.192 35.688 ;
    END
  END x_s[26]
  PIN x_s[27]
    DIRECTION INPUT ;
    USE SIGNAL ;
    PORT
      LAYER M4 ;
        RECT  0 35.952 0.192 35.976 ;
    END
  END x_s[27]
  PIN x_s[28]
    DIRECTION INPUT ;
    USE SIGNAL ;
    PORT
      LAYER M4 ;
        RECT  0 36.288 0.192 36.312 ;
    END
  END x_s[28]
  PIN x_s[29]
    DIRECTION INPUT ;
    USE SIGNAL ;
    PORT
      LAYER M4 ;
        RECT  0 36.624 0.192 36.648 ;
    END
  END x_s[29]
  PIN x_s[2]
    DIRECTION INPUT ;
    USE SIGNAL ;
    PORT
      LAYER M4 ;
        RECT  0 27.984 0.192 28.008 ;
    END
  END x_s[2]
  PIN x_s[30]
    DIRECTION INPUT ;
    USE SIGNAL ;
    PORT
      LAYER M4 ;
        RECT  0 36.912 0.192 36.936 ;
    END
  END x_s[30]
  PIN x_s[31]
    DIRECTION INPUT ;
    USE SIGNAL ;
    PORT
      LAYER M4 ;
        RECT  0 37.248 0.192 37.272 ;
    END
  END x_s[31]
  PIN x_s[32]
    DIRECTION INPUT ;
    USE SIGNAL ;
    PORT
      LAYER M4 ;
        RECT  0 37.536 0.192 37.56 ;
    END
  END x_s[32]
  PIN x_s[33]
    DIRECTION INPUT ;
    USE SIGNAL ;
    PORT
      LAYER M4 ;
        RECT  0 37.872 0.192 37.896 ;
    END
  END x_s[33]
  PIN x_s[34]
    DIRECTION INPUT ;
    USE SIGNAL ;
    PORT
      LAYER M4 ;
        RECT  0 38.208 0.192 38.232 ;
    END
  END x_s[34]
  PIN x_s[35]
    DIRECTION INPUT ;
    USE SIGNAL ;
    PORT
      LAYER M4 ;
        RECT  0 38.496 0.192 38.52 ;
    END
  END x_s[35]
  PIN x_s[36]
    DIRECTION INPUT ;
    USE SIGNAL ;
    PORT
      LAYER M4 ;
        RECT  0 38.832 0.192 38.856 ;
    END
  END x_s[36]
  PIN x_s[37]
    DIRECTION INPUT ;
    USE SIGNAL ;
    PORT
      LAYER M4 ;
        RECT  0 39.168 0.192 39.192 ;
    END
  END x_s[37]
  PIN x_s[38]
    DIRECTION INPUT ;
    USE SIGNAL ;
    PORT
      LAYER M4 ;
        RECT  0 39.456 0.192 39.48 ;
    END
  END x_s[38]
  PIN x_s[39]
    DIRECTION INPUT ;
    USE SIGNAL ;
    PORT
      LAYER M4 ;
        RECT  0 39.792 0.192 39.816 ;
    END
  END x_s[39]
  PIN x_s[3]
    DIRECTION INPUT ;
    USE SIGNAL ;
    PORT
      LAYER M4 ;
        RECT  0 28.32 0.192 28.344 ;
    END
  END x_s[3]
  PIN x_s[40]
    DIRECTION INPUT ;
    USE SIGNAL ;
    PORT
      LAYER M4 ;
        RECT  0 40.128 0.192 40.152 ;
    END
  END x_s[40]
  PIN x_s[41]
    DIRECTION INPUT ;
    USE SIGNAL ;
    PORT
      LAYER M4 ;
        RECT  0 40.416 0.192 40.44 ;
    END
  END x_s[41]
  PIN x_s[42]
    DIRECTION INPUT ;
    USE SIGNAL ;
    PORT
      LAYER M4 ;
        RECT  0 40.752 0.192 40.776 ;
    END
  END x_s[42]
  PIN x_s[43]
    DIRECTION INPUT ;
    USE SIGNAL ;
    PORT
      LAYER M4 ;
        RECT  0 41.088 0.192 41.112 ;
    END
  END x_s[43]
  PIN x_s[44]
    DIRECTION INPUT ;
    USE SIGNAL ;
    PORT
      LAYER M4 ;
        RECT  0 41.376 0.192 41.4 ;
    END
  END x_s[44]
  PIN x_s[45]
    DIRECTION INPUT ;
    USE SIGNAL ;
    PORT
      LAYER M4 ;
        RECT  0 41.712 0.192 41.736 ;
    END
  END x_s[45]
  PIN x_s[46]
    DIRECTION INPUT ;
    USE SIGNAL ;
    PORT
      LAYER M4 ;
        RECT  0 42.048 0.192 42.072 ;
    END
  END x_s[46]
  PIN x_s[47]
    DIRECTION INPUT ;
    USE SIGNAL ;
    PORT
      LAYER M4 ;
        RECT  0 42.336 0.192 42.36 ;
    END
  END x_s[47]
  PIN x_s[48]
    DIRECTION INPUT ;
    USE SIGNAL ;
    PORT
      LAYER M4 ;
        RECT  0 42.672 0.192 42.696 ;
    END
  END x_s[48]
  PIN x_s[49]
    DIRECTION INPUT ;
    USE SIGNAL ;
    PORT
      LAYER M4 ;
        RECT  0 42.96 0.192 42.984 ;
    END
  END x_s[49]
  PIN x_s[4]
    DIRECTION INPUT ;
    USE SIGNAL ;
    PORT
      LAYER M4 ;
        RECT  0 28.608 0.192 28.632 ;
    END
  END x_s[4]
  PIN x_s[50]
    DIRECTION INPUT ;
    USE SIGNAL ;
    PORT
      LAYER M4 ;
        RECT  0 43.296 0.192 43.32 ;
    END
  END x_s[50]
  PIN x_s[51]
    DIRECTION INPUT ;
    USE SIGNAL ;
    PORT
      LAYER M4 ;
        RECT  0 43.632 0.192 43.656 ;
    END
  END x_s[51]
  PIN x_s[52]
    DIRECTION INPUT ;
    USE SIGNAL ;
    PORT
      LAYER M4 ;
        RECT  0 43.92 0.192 43.944 ;
    END
  END x_s[52]
  PIN x_s[53]
    DIRECTION INPUT ;
    USE SIGNAL ;
    PORT
      LAYER M4 ;
        RECT  0 44.256 0.192 44.28 ;
    END
  END x_s[53]
  PIN x_s[54]
    DIRECTION INPUT ;
    USE SIGNAL ;
    PORT
      LAYER M4 ;
        RECT  0 44.592 0.192 44.616 ;
    END
  END x_s[54]
  PIN x_s[55]
    DIRECTION INPUT ;
    USE SIGNAL ;
    PORT
      LAYER M4 ;
        RECT  0 44.88 0.192 44.904 ;
    END
  END x_s[55]
  PIN x_s[56]
    DIRECTION INPUT ;
    USE SIGNAL ;
    PORT
      LAYER M4 ;
        RECT  0 45.216 0.192 45.24 ;
    END
  END x_s[56]
  PIN x_s[57]
    DIRECTION INPUT ;
    USE SIGNAL ;
    PORT
      LAYER M4 ;
        RECT  0 45.552 0.192 45.576 ;
    END
  END x_s[57]
  PIN x_s[58]
    DIRECTION INPUT ;
    USE SIGNAL ;
    PORT
      LAYER M4 ;
        RECT  0 45.84 0.192 45.864 ;
    END
  END x_s[58]
  PIN x_s[59]
    DIRECTION INPUT ;
    USE SIGNAL ;
    PORT
      LAYER M4 ;
        RECT  0 46.176 0.192 46.2 ;
    END
  END x_s[59]
  PIN x_s[5]
    DIRECTION INPUT ;
    USE SIGNAL ;
    PORT
      LAYER M4 ;
        RECT  0 28.944 0.192 28.968 ;
    END
  END x_s[5]
  PIN x_s[60]
    DIRECTION INPUT ;
    USE SIGNAL ;
    PORT
      LAYER M4 ;
        RECT  0 46.512 0.192 46.536 ;
    END
  END x_s[60]
  PIN x_s[61]
    DIRECTION INPUT ;
    USE SIGNAL ;
    PORT
      LAYER M4 ;
        RECT  0 46.8 0.192 46.824 ;
    END
  END x_s[61]
  PIN x_s[62]
    DIRECTION INPUT ;
    USE SIGNAL ;
    PORT
      LAYER M4 ;
        RECT  0 47.136 0.192 47.16 ;
    END
  END x_s[62]
  PIN x_s[63]
    DIRECTION INPUT ;
    USE SIGNAL ;
    PORT
      LAYER M4 ;
        RECT  0 47.472 0.192 47.496 ;
    END
  END x_s[63]
  PIN x_s[6]
    DIRECTION INPUT ;
    USE SIGNAL ;
    PORT
      LAYER M4 ;
        RECT  0 29.28 0.192 29.304 ;
    END
  END x_s[6]
  PIN x_s[7]
    DIRECTION INPUT ;
    USE SIGNAL ;
    PORT
      LAYER M4 ;
        RECT  0 29.568 0.192 29.592 ;
    END
  END x_s[7]
  PIN x_s[8]
    DIRECTION INPUT ;
    USE SIGNAL ;
    PORT
      LAYER M4 ;
        RECT  0 29.904 0.192 29.928 ;
    END
  END x_s[8]
  PIN x_s[9]
    DIRECTION INPUT ;
    USE SIGNAL ;
    PORT
      LAYER M4 ;
        RECT  0 30.24 0.192 30.264 ;
    END
  END x_s[9]
  PIN ze_d
    DIRECTION INPUT ;
    USE SIGNAL ;
    PORT
      LAYER M4 ;
        RECT  0 1.488 0.192 1.512 ;
    END
  END ze_d
  PIN VSS
    DIRECTION INOUT ;
    USE GROUND ;
    PORT
      LAYER M5 ;
        RECT  159 2.137 159.12 46.463 ;
        RECT  153.6 2.137 153.72 46.463 ;
        RECT  148.2 2.137 148.32 46.463 ;
        RECT  142.8 2.137 142.92 46.463 ;
        RECT  137.4 2.137 137.52 46.463 ;
        RECT  132 2.137 132.12 46.463 ;
        RECT  126.6 2.137 126.72 46.463 ;
        RECT  121.2 2.137 121.32 46.463 ;
        RECT  115.8 2.137 115.92 46.463 ;
        RECT  110.4 2.137 110.52 46.463 ;
        RECT  105 2.137 105.12 46.463 ;
        RECT  99.6 2.137 99.72 46.463 ;
        RECT  94.2 2.137 94.32 46.463 ;
        RECT  88.8 2.137 88.92 46.463 ;
        RECT  83.4 2.137 83.52 46.463 ;
        RECT  78 2.137 78.12 46.463 ;
        RECT  72.6 2.137 72.72 46.463 ;
        RECT  67.2 2.137 67.32 46.463 ;
        RECT  61.8 2.137 61.92 46.463 ;
        RECT  56.4 2.137 56.52 46.463 ;
        RECT  51 2.137 51.12 46.463 ;
        RECT  45.6 2.137 45.72 46.463 ;
        RECT  40.2 2.137 40.32 46.463 ;
        RECT  34.8 2.137 34.92 46.463 ;
        RECT  29.4 2.137 29.52 46.463 ;
        RECT  24 2.137 24.12 46.463 ;
        RECT  18.6 2.137 18.72 46.463 ;
        RECT  13.2 2.137 13.32 46.463 ;
        RECT  7.8 2.137 7.92 46.463 ;
        RECT  2.4 2.137 2.52 46.463 ;
    END
  END VSS
  PIN VDD
    DIRECTION INOUT ;
    USE POWER ;
    PORT
      LAYER M5 ;
        RECT  159.192 2.151 159.312 46.449 ;
        RECT  153.792 2.151 153.912 46.449 ;
        RECT  148.392 2.151 148.512 46.449 ;
        RECT  142.992 2.151 143.112 46.449 ;
        RECT  137.592 2.151 137.712 46.449 ;
        RECT  132.192 2.151 132.312 46.449 ;
        RECT  126.792 2.151 126.912 46.449 ;
        RECT  121.392 2.151 121.512 46.449 ;
        RECT  115.992 2.151 116.112 46.449 ;
        RECT  110.592 2.151 110.712 46.449 ;
        RECT  105.192 2.151 105.312 46.449 ;
        RECT  99.792 2.151 99.912 46.449 ;
        RECT  94.392 2.151 94.512 46.449 ;
        RECT  88.992 2.151 89.112 46.449 ;
        RECT  83.592 2.151 83.712 46.449 ;
        RECT  78.192 2.151 78.312 46.449 ;
        RECT  72.792 2.151 72.912 46.449 ;
        RECT  67.392 2.151 67.512 46.449 ;
        RECT  61.992 2.151 62.112 46.449 ;
        RECT  56.592 2.151 56.712 46.449 ;
        RECT  51.192 2.151 51.312 46.449 ;
        RECT  45.792 2.151 45.912 46.449 ;
        RECT  40.392 2.151 40.512 46.449 ;
        RECT  34.992 2.151 35.112 46.449 ;
        RECT  29.592 2.151 29.712 46.449 ;
        RECT  24.192 2.151 24.312 46.449 ;
        RECT  18.792 2.151 18.912 46.449 ;
        RECT  13.392 2.151 13.512 46.449 ;
        RECT  7.992 2.151 8.112 46.449 ;
        RECT  2.592 2.151 2.712 46.449 ;
    END
  END VDD
  OBS
    LAYER RVTN ;
     RECT  2.16 2.16 162 2.295 ;
     RECT  2.16 2.565 162 2.835 ;
     RECT  2.16 3.105 162 3.375 ;
     RECT  2.16 3.645 162 3.915 ;
     RECT  2.16 4.185 162 4.455 ;
     RECT  2.16 4.725 162 4.995 ;
     RECT  2.16 5.265 162 5.535 ;
     RECT  2.16 5.805 162 6.075 ;
     RECT  2.16 6.345 162 6.615 ;
     RECT  2.16 6.885 162 7.155 ;
     RECT  2.16 7.425 162 7.695 ;
     RECT  2.16 7.965 162 8.235 ;
     RECT  2.16 8.505 162 8.775 ;
     RECT  2.16 9.045 162 9.315 ;
     RECT  2.16 9.585 162 9.855 ;
     RECT  2.16 10.125 162 10.395 ;
     RECT  2.16 10.665 162 10.935 ;
     RECT  2.16 11.205 162 11.475 ;
     RECT  2.16 11.745 162 12.015 ;
     RECT  2.16 12.285 162 12.555 ;
     RECT  2.16 12.825 162 13.095 ;
     RECT  2.16 13.365 162 13.635 ;
     RECT  2.16 13.905 162 14.175 ;
     RECT  2.16 14.445 162 14.715 ;
     RECT  2.16 14.985 162 15.255 ;
     RECT  2.16 15.525 162 15.795 ;
     RECT  2.16 16.065 162 16.335 ;
     RECT  2.16 16.605 162 16.875 ;
     RECT  2.16 17.145 162 17.415 ;
     RECT  2.16 17.685 162 17.955 ;
     RECT  2.16 18.225 162 18.495 ;
     RECT  2.16 18.765 162 19.035 ;
     RECT  2.16 19.305 162 19.575 ;
     RECT  2.16 19.845 162 20.115 ;
     RECT  2.16 20.385 162 20.655 ;
     RECT  2.16 20.925 162 21.195 ;
     RECT  2.16 21.465 162 21.735 ;
     RECT  2.16 22.005 162 22.275 ;
     RECT  2.16 22.545 162 22.815 ;
     RECT  2.16 23.085 162 23.355 ;
     RECT  2.16 23.625 162 23.895 ;
     RECT  2.16 24.165 162 24.435 ;
     RECT  2.16 24.705 162 24.975 ;
     RECT  2.16 25.245 162 25.515 ;
     RECT  2.16 25.785 162 26.055 ;
     RECT  2.16 26.325 162 26.595 ;
     RECT  2.16 26.865 162 27.135 ;
     RECT  2.16 27.405 162 27.675 ;
     RECT  2.16 27.945 162 28.215 ;
     RECT  2.16 28.485 162 28.755 ;
     RECT  2.16 29.025 162 29.295 ;
     RECT  2.16 29.565 162 29.835 ;
     RECT  2.16 30.105 162 30.375 ;
     RECT  2.16 30.645 162 30.915 ;
     RECT  2.16 31.185 162 31.455 ;
     RECT  2.16 31.725 162 31.995 ;
     RECT  2.16 32.265 162 32.535 ;
     RECT  2.16 32.805 162 33.075 ;
     RECT  2.16 33.345 162 33.615 ;
     RECT  2.16 33.885 162 34.155 ;
     RECT  2.16 34.425 162 34.695 ;
     RECT  2.16 34.965 162 35.235 ;
     RECT  2.16 35.505 162 35.775 ;
     RECT  2.16 36.045 162 36.315 ;
     RECT  2.16 36.585 162 36.855 ;
     RECT  2.16 37.125 162 37.395 ;
     RECT  2.16 37.665 162 37.935 ;
     RECT  2.16 38.205 162 38.475 ;
     RECT  2.16 38.745 162 39.015 ;
     RECT  2.16 39.285 162 39.555 ;
     RECT  2.16 39.825 162 40.095 ;
     RECT  2.16 40.365 162 40.635 ;
     RECT  2.16 40.905 162 41.175 ;
     RECT  2.16 41.445 162 41.715 ;
     RECT  2.16 41.985 162 42.255 ;
     RECT  2.16 42.525 162 42.795 ;
     RECT  2.16 43.065 162 43.335 ;
     RECT  2.16 43.605 162 43.875 ;
     RECT  2.16 44.145 162 44.415 ;
     RECT  2.16 44.685 162 44.955 ;
     RECT  2.16 45.225 162 45.495 ;
     RECT  2.16 45.765 162 46.035 ;
     RECT  2.16 46.305 162 46.44 ;
    LAYER RVTP ;
     RECT  2.16 2.295 162 2.565 ;
     RECT  2.16 2.835 162 3.105 ;
     RECT  2.16 3.375 162 3.645 ;
     RECT  2.16 3.915 162 4.185 ;
     RECT  2.16 4.455 162 4.725 ;
     RECT  2.16 4.995 162 5.265 ;
     RECT  2.16 5.535 162 5.805 ;
     RECT  2.16 6.075 162 6.345 ;
     RECT  2.16 6.615 162 6.885 ;
     RECT  2.16 7.155 162 7.425 ;
     RECT  2.16 7.695 162 7.965 ;
     RECT  2.16 8.235 162 8.505 ;
     RECT  2.16 8.775 162 9.045 ;
     RECT  2.16 9.315 162 9.585 ;
     RECT  2.16 9.855 162 10.125 ;
     RECT  2.16 10.395 162 10.665 ;
     RECT  2.16 10.935 162 11.205 ;
     RECT  2.16 11.475 162 11.745 ;
     RECT  2.16 12.015 162 12.285 ;
     RECT  2.16 12.555 162 12.825 ;
     RECT  2.16 13.095 162 13.365 ;
     RECT  2.16 13.635 162 13.905 ;
     RECT  2.16 14.175 162 14.445 ;
     RECT  2.16 14.715 162 14.985 ;
     RECT  2.16 15.255 162 15.525 ;
     RECT  2.16 15.795 162 16.065 ;
     RECT  2.16 16.335 162 16.605 ;
     RECT  2.16 16.875 162 17.145 ;
     RECT  2.16 17.415 162 17.685 ;
     RECT  2.16 17.955 162 18.225 ;
     RECT  2.16 18.495 162 18.765 ;
     RECT  2.16 19.035 162 19.305 ;
     RECT  2.16 19.575 162 19.845 ;
     RECT  2.16 20.115 162 20.385 ;
     RECT  2.16 20.655 162 20.925 ;
     RECT  2.16 21.195 162 21.465 ;
     RECT  2.16 21.735 162 22.005 ;
     RECT  2.16 22.275 162 22.545 ;
     RECT  2.16 22.815 162 23.085 ;
     RECT  2.16 23.355 162 23.625 ;
     RECT  2.16 23.895 162 24.165 ;
     RECT  2.16 24.435 162 24.705 ;
     RECT  2.16 24.975 162 25.245 ;
     RECT  2.16 25.515 162 25.785 ;
     RECT  2.16 26.055 162 26.325 ;
     RECT  2.16 26.595 162 26.865 ;
     RECT  2.16 27.135 162 27.405 ;
     RECT  2.16 27.675 162 27.945 ;
     RECT  2.16 28.215 162 28.485 ;
     RECT  2.16 28.755 162 29.025 ;
     RECT  2.16 29.295 162 29.565 ;
     RECT  2.16 29.835 162 30.105 ;
     RECT  2.16 30.375 162 30.645 ;
     RECT  2.16 30.915 162 31.185 ;
     RECT  2.16 31.455 162 31.725 ;
     RECT  2.16 31.995 162 32.265 ;
     RECT  2.16 32.535 162 32.805 ;
     RECT  2.16 33.075 162 33.345 ;
     RECT  2.16 33.615 162 33.885 ;
     RECT  2.16 34.155 162 34.425 ;
     RECT  2.16 34.695 162 34.965 ;
     RECT  2.16 35.235 162 35.505 ;
     RECT  2.16 35.775 162 36.045 ;
     RECT  2.16 36.315 162 36.585 ;
     RECT  2.16 36.855 162 37.125 ;
     RECT  2.16 37.395 162 37.665 ;
     RECT  2.16 37.935 162 38.205 ;
     RECT  2.16 38.475 162 38.745 ;
     RECT  2.16 39.015 162 39.285 ;
     RECT  2.16 39.555 162 39.825 ;
     RECT  2.16 40.095 162 40.365 ;
     RECT  2.16 40.635 162 40.905 ;
     RECT  2.16 41.175 162 41.445 ;
     RECT  2.16 41.715 162 41.985 ;
     RECT  2.16 42.255 162 42.525 ;
     RECT  2.16 42.795 162 43.065 ;
     RECT  2.16 43.335 162 43.605 ;
     RECT  2.16 43.875 162 44.145 ;
     RECT  2.16 44.415 162 44.685 ;
     RECT  2.16 44.955 162 45.225 ;
     RECT  2.16 45.495 162 45.765 ;
     RECT  2.16 46.035 162 46.305 ;
    LAYER M1 ;
     RECT  2.16 2.151 162 46.449 ;
    LAYER M2 ;
     RECT  0.211 20.052 0.247 20.07 ;
     RECT  0.211 25.524 0.247 25.542 ;
     RECT  0.211 46.35 0.247 46.368 ;
     RECT  0.247 16.11 0.283 16.128 ;
     RECT  0.211 21.744 0.283 21.762 ;
     RECT  0.211 22.626 0.283 23.148 ;
     RECT  0.283 21.744 0.311 23.148 ;
     RECT  0.283 15.732 0.499 16.128 ;
     RECT  0.499 15.732 0.535 16.668 ;
     RECT  0.247 38.52 0.535 38.538 ;
     RECT  0.211 39.87 0.535 39.888 ;
     RECT  0.535 15.732 0.823 16.794 ;
     RECT  0.535 43.812 1.147 43.83 ;
     RECT  0.247 46.242 1.147 46.368 ;
     RECT  1.147 43.416 1.175 43.83 ;
     RECT  0.247 2.61 1.723 2.628 ;
     RECT  1.723 2.232 2.16 2.628 ;
     RECT  0.211 4.392 2.16 4.41 ;
     RECT  0.211 6.822 2.16 6.84 ;
     RECT  0.535 7.902 2.16 7.92 ;
     RECT  0.535 9.054 2.16 9.072 ;
     RECT  0.211 11.79 2.16 13.05 ;
     RECT  0.211 14.76 2.16 14.778 ;
     RECT  0.823 15.732 2.16 16.83 ;
     RECT  0.211 18.738 2.16 18.756 ;
     RECT  0.247 19.854 2.16 20.07 ;
     RECT  0.311 21.744 2.16 22.23 ;
     RECT  0.311 23.13 2.16 23.148 ;
     RECT  0.211 24.102 2.16 24.12 ;
     RECT  0.247 25.29 2.16 25.542 ;
     RECT  0.535 27.342 2.16 27.36 ;
     RECT  0.535 38.178 2.16 38.538 ;
     RECT  0.535 39.294 2.16 39.888 ;
     RECT  2.155 41.922 2.16 41.94 ;
     RECT  1.175 43.416 2.16 43.434 ;
     RECT  1.147 45.702 2.16 46.368 ;
     RECT  2.16 2.151 2.767 46.449 ;
     RECT  2.767 2.151 2.839 46.494 ;
     RECT  2.839 2.151 4.747 46.602 ;
     RECT  4.747 2.07 7.655 46.602 ;
     RECT  7.655 2.07 8.527 46.449 ;
     RECT  8.527 2.07 8.887 46.494 ;
     RECT  8.887 1.926 8.951 46.494 ;
     RECT  8.951 1.926 10.859 46.449 ;
     RECT  10.859 1.998 36.067 46.449 ;
     RECT  36.067 1.926 53.563 46.449 ;
     RECT  53.563 1.881 62.815 46.449 ;
     RECT  62.815 1.881 62.923 46.494 ;
     RECT  62.923 1.881 63.203 46.566 ;
     RECT  63.203 1.962 64.147 46.566 ;
     RECT  64.147 1.926 66.479 46.566 ;
     RECT  66.479 1.926 69.683 46.53 ;
     RECT  69.683 1.962 71.051 46.53 ;
     RECT  71.051 1.962 73.175 46.494 ;
     RECT  73.175 1.998 73.607 46.494 ;
     RECT  73.607 1.998 76.387 46.449 ;
     RECT  76.387 1.998 76.891 46.494 ;
     RECT  76.891 1.998 77.351 46.53 ;
     RECT  77.351 1.998 77.459 46.494 ;
     RECT  77.459 1.998 78.475 46.449 ;
     RECT  78.475 1.962 89.887 46.449 ;
     RECT  89.887 1.962 91.651 46.494 ;
     RECT  91.651 1.926 94.027 46.494 ;
     RECT  94.027 1.926 94.387 46.53 ;
     RECT  94.387 1.881 99.275 46.53 ;
     RECT  99.275 1.926 99.599 46.53 ;
     RECT  99.599 1.998 100.399 46.53 ;
     RECT  100.399 1.962 102.119 46.566 ;
     RECT  102.119 1.998 108.959 46.566 ;
     RECT  108.959 1.998 113.071 46.449 ;
     RECT  113.071 1.962 119.507 46.449 ;
     RECT  119.507 1.998 122.107 46.449 ;
     RECT  122.107 1.962 122.639 46.449 ;
     RECT  122.639 1.998 124.843 46.449 ;
     RECT  124.843 1.926 132.791 46.449 ;
     RECT  132.791 1.998 135.391 46.449 ;
     RECT  135.391 1.998 135.815 46.494 ;
     RECT  135.815 1.998 138.235 46.449 ;
     RECT  138.235 1.926 142.763 46.449 ;
     RECT  142.763 2.034 148.531 46.449 ;
     RECT  148.531 2.034 149.647 46.494 ;
     RECT  149.647 2.034 154.607 46.566 ;
     RECT  154.607 2.034 156.487 46.494 ;
     RECT  156.487 1.998 157.711 46.494 ;
     RECT  157.711 1.998 158.063 46.53 ;
     RECT  158.063 2.07 158.603 46.53 ;
     RECT  158.603 2.07 160.799 46.494 ;
     RECT  160.799 2.106 161.447 46.494 ;
     RECT  161.447 2.106 162 46.449 ;
     RECT  162 37.746 162.419 41.202 ;
     RECT  162 2.106 162.455 21.222 ;
     RECT  162 24.75 162.455 26.784 ;
     RECT  162.455 2.106 162.491 3.33 ;
     RECT  162.455 4.086 162.491 8.19 ;
     RECT  162.455 8.982 162.491 13.662 ;
     RECT  162.455 14.886 162.491 20.034 ;
     RECT  162.455 21.096 162.491 21.222 ;
     RECT  162 22.086 162.491 23.184 ;
     RECT  162 30.006 162.491 30.564 ;
     RECT  162 31.356 162.491 32.994 ;
     RECT  162.419 38.016 162.491 41.202 ;
     RECT  162 42.03 162.491 42.714 ;
     RECT  162.491 4.194 162.527 4.212 ;
     RECT  162.491 21.204 162.527 21.222 ;
     RECT  162.491 42.534 162.527 42.714 ;
     RECT  162 43.776 162.527 46.224 ;
     RECT  162.491 2.196 162.563 3.024 ;
     RECT  162.563 2.196 162.599 2.214 ;
     RECT  162.563 3.006 163.031 3.024 ;
     RECT  162.491 17.316 163.031 20.034 ;
     RECT  162 27.576 163.031 29.214 ;
     RECT  162.455 26.568 163.067 26.784 ;
     RECT  163.031 28.026 163.067 29.214 ;
     RECT  162.491 38.016 163.067 40.356 ;
     RECT  162 33.93 163.139 36.684 ;
     RECT  162.527 42.534 163.571 42.552 ;
     RECT  162.491 10.476 163.607 10.494 ;
     RECT  162.491 11.556 163.607 12.618 ;
     RECT  162.491 13.644 163.607 13.662 ;
     RECT  162.491 15.156 163.607 15.174 ;
     RECT  163.031 17.496 163.607 17.514 ;
     RECT  163.031 18.504 163.607 18.522 ;
     RECT  163.031 20.016 163.607 20.034 ;
     RECT  162.491 22.086 163.607 23.004 ;
     RECT  162.455 24.75 163.607 25.614 ;
     RECT  163.067 26.568 163.607 26.586 ;
     RECT  162.491 30.456 163.607 30.474 ;
     RECT  162.491 31.356 163.607 32.364 ;
     RECT  163.139 33.93 163.607 35.064 ;
     RECT  163.139 36.054 163.607 36.684 ;
     RECT  163.067 38.106 163.607 40.356 ;
     RECT  162.527 43.776 163.607 46.026 ;
     RECT  163.607 24.75 163.643 25.074 ;
     RECT  163.067 28.026 163.643 28.044 ;
     RECT  163.067 29.196 163.643 29.214 ;
     RECT  163.607 32.346 163.643 32.364 ;
     RECT  163.607 36.054 163.643 36.378 ;
     RECT  163.607 39.726 163.643 39.744 ;
     RECT  163.607 43.776 163.643 44.064 ;
     RECT  163.607 22.788 163.679 23.004 ;
     RECT  163.607 33.93 163.679 33.948 ;
     RECT  163.607 34.776 163.679 35.064 ;
     RECT  163.643 36.36 163.679 36.378 ;
     RECT  163.643 44.046 163.679 44.064 ;
     RECT  163.607 38.106 163.715 38.772 ;
     RECT  163.607 44.856 163.715 45.558 ;
     RECT  163.679 34.776 163.751 34.794 ;
     RECT  163.715 45.54 163.751 45.558 ;
     RECT  163.651 46.512 163.751 46.53 ;
     RECT  163.679 22.788 163.967 22.806 ;
     RECT  163.715 38.142 164.003 38.772 ;
    LAYER M3 ;
     RECT  162.504 1.147 162.522 1.435 ;
     RECT  1.728 1.147 1.746 1.483 ;
     RECT  162.504 1.435 162.558 1.675 ;
     RECT  1.728 1.483 2.322 1.819 ;
     RECT  99.252 1.876 99.27 1.921 ;
     RECT  53.568 1.876 53.586 1.957 ;
     RECT  99.252 1.921 99.594 1.957 ;
     RECT  124.848 1.921 124.866 1.957 ;
     RECT  162.468 1.675 162.558 1.963 ;
     RECT  52.92 1.957 53.586 1.993 ;
     RECT  63.18 1.876 63.198 1.993 ;
     RECT  94.392 1.876 94.41 1.993 ;
     RECT  10.836 1.921 10.854 2.029 ;
     RECT  119.484 1.957 119.502 2.029 ;
     RECT  142.74 1.921 142.758 2.029 ;
     RECT  156.492 1.993 156.51 2.029 ;
     RECT  58.392 1.921 59.382 2.065 ;
     RECT  69.66 1.921 69.678 2.065 ;
     RECT  81.828 2.029 81.846 2.065 ;
     RECT  102.096 1.957 102.114 2.065 ;
     RECT  131.94 1.957 131.958 2.065 ;
     RECT  132.768 1.921 132.786 2.065 ;
     RECT  158.04 1.993 158.058 2.065 ;
     RECT  8.892 1.921 8.91 2.101 ;
     RECT  9.648 2.029 11.466 2.101 ;
     RECT  19.836 2.065 19.854 2.101 ;
     RECT  20.88 2.065 20.898 2.101 ;
     RECT  38.304 2.065 38.322 2.101 ;
     RECT  63.108 1.993 63.198 2.101 ;
     RECT  74.412 2.065 74.43 2.101 ;
     RECT  75.96 2.065 75.978 2.101 ;
     RECT  99.18 1.957 99.594 2.101 ;
     RECT  100.404 1.957 100.422 2.101 ;
     RECT  116.604 2.029 116.622 2.101 ;
     RECT  118.62 2.029 118.638 2.101 ;
     RECT  119.412 2.029 119.502 2.101 ;
     RECT  138.24 1.921 138.258 2.101 ;
     RECT  140.112 1.993 140.13 2.101 ;
     RECT  156.42 2.029 156.51 2.101 ;
     RECT  157.536 2.065 158.058 2.101 ;
     RECT  160.776 2.065 160.794 2.101 ;
     RECT  1.728 1.819 2.574 2.107 ;
     RECT  19.116 2.101 19.854 2.143 ;
     RECT  23.508 2.101 23.742 2.143 ;
     RECT  24.588 2.029 24.606 2.143 ;
     RECT  40.788 2.101 40.806 2.143 ;
     RECT  46.152 2.065 46.17 2.143 ;
     RECT  57.024 2.101 57.042 2.143 ;
     RECT  61.344 2.065 61.362 2.143 ;
     RECT  67.68 2.101 67.698 2.143 ;
     RECT  73.152 1.957 73.17 2.143 ;
     RECT  78.48 1.957 78.498 2.143 ;
     RECT  94.392 1.993 94.482 2.143 ;
     RECT  104.832 2.101 104.85 2.143 ;
     RECT  115.164 2.101 115.794 2.143 ;
     RECT  116.604 2.101 116.874 2.143 ;
     RECT  120.564 2.101 120.582 2.143 ;
     RECT  137.556 2.101 138.438 2.143 ;
     RECT  142.344 2.029 142.758 2.143 ;
     RECT  159.588 2.101 159.606 2.143 ;
     RECT  15.408 2.101 15.858 2.191 ;
     RECT  20.88 2.101 21.906 2.191 ;
     RECT  30.744 2.029 30.762 2.191 ;
     RECT  42.912 2.101 42.93 2.191 ;
     RECT  57.96 2.065 59.85 2.191 ;
     RECT  61.344 2.143 61.905 2.191 ;
     RECT  69.516 2.065 69.678 2.191 ;
     RECT  70.812 2.029 70.83 2.191 ;
     RECT  78.015 2.143 78.498 2.191 ;
     RECT  91.656 1.921 91.674 2.191 ;
     RECT  94.215 2.143 94.482 2.191 ;
     RECT  97.02 1.993 97.038 2.191 ;
     RECT  97.812 1.921 98.046 2.191 ;
     RECT  98.964 2.101 100.422 2.191 ;
     RECT  115.164 2.143 116.874 2.191 ;
     RECT  124.848 1.957 124.902 2.191 ;
     RECT  126.615 2.143 126.705 2.191 ;
     RECT  128.916 2.101 129.366 2.191 ;
     RECT  135.936 2.101 135.954 2.191 ;
     RECT  137.415 2.143 138.438 2.191 ;
     RECT  148.215 2.143 148.305 2.191 ;
     RECT  95.976 1.921 96.102 2.203 ;
     RECT  124.308 2.191 124.902 2.203 ;
     RECT  162.468 1.963 162.594 2.203 ;
     RECT  8.892 2.101 11.466 2.219 ;
     RECT  118.62 2.101 119.502 2.219 ;
     RECT  1.152 2.107 2.574 2.227 ;
     RECT  4.752 2.065 4.77 2.227 ;
     RECT  14.724 2.191 15.858 2.227 ;
     RECT  16.776 2.191 16.794 2.227 ;
     RECT  20.88 2.191 22.302 2.227 ;
     RECT  29.415 2.143 29.505 2.227 ;
     RECT  40.215 2.143 40.806 2.227 ;
     RECT  42.912 2.191 43.11 2.227 ;
     RECT  64.152 1.921 64.17 2.227 ;
     RECT  67.215 2.143 67.698 2.227 ;
     RECT  93.672 2.191 94.482 2.227 ;
     RECT  95.724 2.203 96.174 2.227 ;
     RECT  128.916 2.191 130.374 2.227 ;
     RECT  131.94 2.065 132.786 2.227 ;
     RECT  135.144 2.191 135.162 2.227 ;
     RECT  135.936 2.191 136.026 2.227 ;
     RECT  139.86 2.101 140.13 2.227 ;
     RECT  142.344 2.143 142.905 2.227 ;
     RECT  145.764 2.191 145.782 2.227 ;
     RECT  146.664 2.191 146.682 2.227 ;
     RECT  148.215 2.191 148.842 2.227 ;
     RECT  4.752 2.227 5.022 2.251 ;
     RECT  6.3 2.227 6.318 2.251 ;
     RECT  23.508 2.143 24.606 2.251 ;
     RECT  57.96 2.191 61.905 2.251 ;
     RECT  74.304 2.101 74.43 2.251 ;
     RECT  77.328 2.191 78.498 2.251 ;
     RECT  93.672 2.227 96.174 2.251 ;
     RECT  97.02 2.191 100.422 2.251 ;
     RECT  104.832 2.143 105.105 2.251 ;
     RECT  126.615 2.191 127.746 2.251 ;
     RECT  131.94 2.227 133.182 2.251 ;
     RECT  135.144 2.227 136.458 2.251 ;
     RECT  137.415 2.191 138.582 2.251 ;
     RECT  139.86 2.227 140.238 2.251 ;
     RECT  156.42 2.101 158.058 2.251 ;
     RECT  1.152 2.227 3.15 2.255 ;
     RECT  4.5 2.251 5.022 2.263 ;
     RECT  6.3 2.251 6.57 2.263 ;
     RECT  8.892 2.219 11.43 2.263 ;
     RECT  13.215 2.143 13.305 2.263 ;
     RECT  18.615 2.143 19.854 2.263 ;
     RECT  20.88 2.227 22.59 2.263 ;
     RECT  23.508 2.251 24.714 2.263 ;
     RECT  28.332 2.191 28.35 2.263 ;
     RECT  44.172 2.227 44.262 2.263 ;
     RECT  45.615 2.143 46.17 2.263 ;
     RECT  55.368 2.227 55.386 2.263 ;
     RECT  63.972 2.227 64.242 2.263 ;
     RECT  65.484 2.065 65.502 2.263 ;
     RECT  66.276 2.101 66.294 2.263 ;
     RECT  77.184 2.251 78.534 2.263 ;
     RECT  79.884 2.101 79.902 2.263 ;
     RECT  86.688 2.227 86.706 2.263 ;
     RECT  93.492 2.251 96.174 2.263 ;
     RECT  97.02 2.251 100.746 2.263 ;
     RECT  101.556 2.065 102.114 2.263 ;
     RECT  103.068 2.227 103.086 2.263 ;
     RECT  104.796 2.251 105.498 2.263 ;
     RECT  115.164 2.191 117.414 2.263 ;
     RECT  118.62 2.219 119.286 2.263 ;
     RECT  120.564 2.143 121.305 2.263 ;
     RECT  122.112 1.957 122.634 2.263 ;
     RECT  125.892 2.251 127.746 2.263 ;
     RECT  128.664 2.227 130.95 2.263 ;
     RECT  131.688 2.251 133.182 2.263 ;
     RECT  134.1 2.191 134.118 2.263 ;
     RECT  134.856 2.251 136.458 2.263 ;
     RECT  137.415 2.251 138.762 2.263 ;
     RECT  151.668 2.191 151.686 2.263 ;
     RECT  1.152 2.255 1.17 2.285 ;
     RECT  20.808 2.263 24.714 2.291 ;
     RECT  20.808 2.291 24.606 2.293 ;
     RECT  74.052 2.251 74.43 2.293 ;
     RECT  110.415 2.143 110.505 2.293 ;
     RECT  4.5 2.263 5.166 2.299 ;
     RECT  7.815 2.143 7.905 2.299 ;
     RECT  36.072 1.921 36.09 2.299 ;
     RECT  38.304 2.101 38.358 2.299 ;
     RECT  39.888 2.227 40.806 2.299 ;
     RECT  42.912 2.227 43.326 2.299 ;
     RECT  44.172 2.263 46.17 2.299 ;
     RECT  52.92 1.993 53.694 2.299 ;
     RECT  56.415 2.143 57.042 2.299 ;
     RECT  57.96 2.251 62.01 2.299 ;
     RECT  63.036 2.101 63.198 2.299 ;
     RECT  63.972 2.263 66.294 2.299 ;
     RECT  70.524 2.191 70.83 2.299 ;
     RECT  72.615 2.143 73.17 2.299 ;
     RECT  75.888 2.101 75.978 2.299 ;
     RECT  76.716 2.263 78.534 2.299 ;
     RECT  79.884 2.263 80.55 2.299 ;
     RECT  81.828 2.065 82.602 2.299 ;
     RECT  86.688 2.263 87.426 2.299 ;
     RECT  88.815 2.143 88.905 2.299 ;
     RECT  90 2.191 90.018 2.299 ;
     RECT  90.792 2.263 90.81 2.299 ;
     RECT  93.492 2.263 100.746 2.299 ;
     RECT  109.404 2.191 109.422 2.299 ;
     RECT  110.415 2.293 110.574 2.299 ;
     RECT  123.588 2.203 124.902 2.299 ;
     RECT  125.892 2.263 134.118 2.299 ;
     RECT  150.408 2.065 150.426 2.299 ;
     RECT  151.596 2.263 151.686 2.299 ;
     RECT  153.615 2.143 153.705 2.299 ;
     RECT  156.24 2.251 158.058 2.299 ;
     RECT  159.015 2.143 159.606 2.299 ;
     RECT  2.304 2.255 3.15 2.335 ;
     RECT  4.392 2.299 5.166 2.335 ;
     RECT  7.524 2.299 7.905 2.335 ;
     RECT  14.724 2.227 16.794 2.335 ;
     RECT  18.615 2.263 19.962 2.335 ;
     RECT  25.632 2.101 25.65 2.335 ;
     RECT  27.756 2.263 28.35 2.335 ;
     RECT  42.876 2.299 46.17 2.335 ;
     RECT  49.032 2.299 49.05 2.335 ;
     RECT  52.632 2.299 53.694 2.335 ;
     RECT  63.036 2.299 66.294 2.335 ;
     RECT  68.616 2.191 69.678 2.335 ;
     RECT  70.524 2.299 71.118 2.335 ;
     RECT  72.504 2.299 73.17 2.335 ;
     RECT  74.052 2.293 75.042 2.335 ;
     RECT  75.888 2.299 78.534 2.335 ;
     RECT  79.38 2.299 80.55 2.335 ;
     RECT  81.504 2.299 82.602 2.335 ;
     RECT  83.415 2.143 83.505 2.335 ;
     RECT  85.14 2.299 85.374 2.335 ;
     RECT  86.688 2.299 87.642 2.335 ;
     RECT  88.815 2.299 89.154 2.335 ;
     RECT  108.828 2.299 110.754 2.335 ;
     RECT  144.54 2.191 144.558 2.335 ;
     RECT  156.096 2.299 158.058 2.335 ;
     RECT  158.832 2.299 160.002 2.335 ;
     RECT  160.776 2.101 161.55 2.335 ;
     RECT  36.072 2.299 36.846 2.347 ;
     RECT  42.876 2.335 46.53 2.347 ;
     RECT  113.076 1.957 113.094 2.347 ;
     RECT  6.228 2.263 6.57 2.371 ;
     RECT  7.416 2.335 7.905 2.371 ;
     RECT  14.616 2.335 16.83 2.371 ;
     RECT  17.748 2.029 17.766 2.371 ;
     RECT  18.504 2.335 19.962 2.371 ;
     RECT  20.772 2.293 24.606 2.371 ;
     RECT  25.632 2.335 25.794 2.371 ;
     RECT  29.124 2.227 29.505 2.371 ;
     RECT  30.492 2.191 30.762 2.371 ;
     RECT  34.815 2.143 34.905 2.371 ;
     RECT  36.072 2.347 37.062 2.371 ;
     RECT  38.304 2.299 38.574 2.371 ;
     RECT  42.876 2.347 47.214 2.371 ;
     RECT  63.036 2.335 66.33 2.371 ;
     RECT  67.176 2.227 67.698 2.371 ;
     RECT  68.616 2.335 71.118 2.371 ;
     RECT  72.36 2.335 73.17 2.371 ;
     RECT  74.052 2.335 78.534 2.371 ;
     RECT  79.308 2.335 80.55 2.371 ;
     RECT  81.324 2.335 83.79 2.371 ;
     RECT  84.888 2.335 85.374 2.371 ;
     RECT  86.688 2.335 89.154 2.371 ;
     RECT  104.472 2.263 105.498 2.371 ;
     RECT  108.828 2.335 110.826 2.371 ;
     RECT  112.896 2.347 113.094 2.371 ;
     RECT  115.164 2.263 119.286 2.371 ;
     RECT  120.564 2.263 122.634 2.371 ;
     RECT  123.444 2.299 134.118 2.371 ;
     RECT  134.856 2.263 138.762 2.371 ;
     RECT  139.644 2.251 140.238 2.371 ;
     RECT  141.336 2.227 141.354 2.371 ;
     RECT  142.128 2.227 142.905 2.371 ;
     RECT  145.764 2.227 146.682 2.371 ;
     RECT  147.996 2.227 149.382 2.371 ;
     RECT  150.408 2.299 151.686 2.371 ;
     RECT  152.568 2.299 154.458 2.371 ;
     RECT  155.952 2.335 161.55 2.371 ;
     RECT  42.552 2.371 47.214 2.395 ;
     RECT  74.052 2.371 85.446 2.395 ;
     RECT  86.364 2.371 89.154 2.395 ;
     RECT  162.432 2.203 162.594 2.399 ;
     RECT  6.12 2.371 7.905 2.413 ;
     RECT  12.348 2.263 13.305 2.413 ;
     RECT  29.088 2.371 29.505 2.413 ;
     RECT  51.015 2.143 51.105 2.413 ;
     RECT  51.84 2.335 53.694 2.413 ;
     RECT  56.415 2.299 62.01 2.413 ;
     RECT  123.444 2.371 142.905 2.413 ;
     RECT  14.616 2.371 17.766 2.443 ;
     RECT  30.492 2.371 30.906 2.461 ;
     RECT  34.815 2.371 37.062 2.461 ;
     RECT  38.304 2.371 38.754 2.461 ;
     RECT  39.564 2.299 41.094 2.461 ;
     RECT  42.3 2.395 47.214 2.461 ;
     RECT  74.052 2.395 89.154 2.461 ;
     RECT  90 2.299 90.81 2.461 ;
     RECT  93.024 2.299 100.746 2.461 ;
     RECT  101.556 2.263 103.23 2.461 ;
     RECT  104.112 2.371 106.182 2.461 ;
     RECT  107.424 2.299 107.442 2.461 ;
     RECT  108.828 2.371 113.094 2.461 ;
     RECT  120.024 2.371 122.634 2.461 ;
     RECT  123.444 2.413 143.097 2.461 ;
     RECT  145.512 2.371 146.682 2.488 ;
     RECT  18.504 2.371 24.606 2.489 ;
     RECT  63 2.371 73.17 2.491 ;
     RECT  74.052 2.461 90.81 2.491 ;
     RECT  14.508 2.443 17.766 2.497 ;
     RECT  18.504 2.489 24.57 2.497 ;
     RECT  91.656 2.191 92.142 2.497 ;
     RECT  92.988 2.461 106.182 2.497 ;
     RECT  2.304 2.335 5.166 2.525 ;
     RECT  30.492 2.461 31.554 2.533 ;
     RECT  49.032 2.335 49.158 2.533 ;
     RECT  91.656 2.497 106.182 2.533 ;
     RECT  107.424 2.461 113.094 2.533 ;
     RECT  114.948 2.371 119.286 2.533 ;
     RECT  147.996 2.371 151.686 2.533 ;
     RECT  152.568 2.371 161.55 2.533 ;
     RECT  2.34 2.525 5.166 2.539 ;
     RECT  6.12 2.413 8.097 2.539 ;
     RECT  33.084 2.491 33.102 2.539 ;
     RECT  33.876 2.299 33.894 2.539 ;
     RECT  63 2.491 90.81 2.539 ;
     RECT  91.656 2.533 113.094 2.539 ;
     RECT  14.508 2.497 24.57 2.561 ;
     RECT  34.815 2.461 37.53 2.569 ;
     RECT  38.304 2.461 41.094 2.569 ;
     RECT  54.864 2.263 55.566 2.569 ;
     RECT  56.415 2.413 62.097 2.569 ;
     RECT  147.996 2.533 161.55 2.569 ;
     RECT  0.216 2.443 0.234 2.573 ;
     RECT  54.864 2.569 62.097 2.587 ;
     RECT  63 2.539 113.094 2.597 ;
     RECT  14.508 2.561 19.926 2.605 ;
     RECT  25.632 2.371 26.298 2.605 ;
     RECT  30.492 2.533 31.914 2.605 ;
     RECT  33.084 2.539 33.894 2.605 ;
     RECT  34.815 2.569 41.094 2.605 ;
     RECT  54.864 2.587 62.19 2.605 ;
     RECT  145.512 2.488 146.718 2.605 ;
     RECT  147.996 2.569 161.586 2.635 ;
     RECT  25.38 2.605 26.298 2.641 ;
     RECT  27.072 2.335 28.35 2.641 ;
     RECT  29.088 2.413 29.697 2.641 ;
     RECT  104.076 2.597 113.094 2.641 ;
     RECT  120.024 2.461 143.19 2.641 ;
     RECT  144.54 2.335 144.594 2.641 ;
     RECT  145.368 2.605 146.718 2.641 ;
     RECT  147.924 2.635 161.586 2.641 ;
     RECT  147.708 2.641 161.586 2.669 ;
     RECT  12.348 2.413 13.497 2.731 ;
     RECT  14.328 2.605 19.926 2.731 ;
     RECT  34.632 2.605 41.094 2.731 ;
     RECT  48.42 2.533 49.158 2.731 ;
     RECT  8.82 2.263 11.43 2.759 ;
     RECT  54.684 2.605 62.19 2.767 ;
     RECT  120.024 2.641 143.622 2.767 ;
     RECT  144.504 2.641 144.594 2.767 ;
     RECT  145.368 2.641 146.862 2.767 ;
     RECT  162.468 2.399 162.594 2.779 ;
     RECT  12.348 2.731 19.926 2.795 ;
     RECT  2.34 2.539 8.097 2.803 ;
     RECT  8.82 2.759 11.322 2.803 ;
     RECT  48.42 2.731 49.194 2.803 ;
     RECT  51.015 2.413 53.694 2.803 ;
     RECT  30.492 2.605 33.894 2.827 ;
     RECT  34.632 2.731 41.166 2.827 ;
     RECT  120.024 2.767 146.862 2.827 ;
     RECT  147.708 2.669 161.262 2.827 ;
     RECT  30.492 2.827 41.166 2.839 ;
     RECT  2.34 2.803 11.322 2.867 ;
     RECT  30.492 2.839 41.31 2.875 ;
     RECT  42.156 2.461 47.286 2.875 ;
     RECT  48.42 2.803 49.338 2.875 ;
     RECT  50.796 2.803 53.694 2.875 ;
     RECT  54.432 2.767 62.19 2.875 ;
     RECT  12.348 2.795 17.226 2.903 ;
     RECT  20.808 2.561 24.57 2.903 ;
     RECT  104.076 2.641 113.382 2.911 ;
     RECT  114.804 2.533 119.286 2.911 ;
     RECT  42.156 2.875 49.338 2.923 ;
     RECT  30.492 2.875 41.418 2.971 ;
     RECT  42.156 2.923 49.374 2.971 ;
     RECT  30.492 2.971 49.374 3.001 ;
     RECT  104.076 2.911 113.418 3.001 ;
     RECT  114.732 2.911 119.286 3.001 ;
     RECT  30.492 3.001 49.554 3.019 ;
     RECT  50.796 2.875 62.19 3.019 ;
     RECT  162.468 2.779 163.026 3.029 ;
     RECT  30.492 3.019 62.19 3.073 ;
     RECT  63 2.597 103.23 3.073 ;
     RECT  0.252 2.605 0.27 3.101 ;
     RECT  104.076 3.001 119.286 3.115 ;
     RECT  120.024 2.827 161.262 3.115 ;
     RECT  104.076 3.115 161.262 3.137 ;
     RECT  25.38 2.641 29.697 3.181 ;
     RECT  30.492 3.073 103.23 3.181 ;
     RECT  20.808 2.903 24.354 3.335 ;
     RECT  25.38 3.181 103.23 3.335 ;
     RECT  18.54 2.795 19.926 3.343 ;
     RECT  104.076 3.137 161.19 3.343 ;
     RECT  104.04 3.343 161.19 3.355 ;
     RECT  25.38 3.335 87.354 3.371 ;
     RECT  88.164 3.335 103.23 3.379 ;
     RECT  104.004 3.355 161.19 3.379 ;
     RECT  18.54 3.343 19.962 3.403 ;
     RECT  12.348 2.903 16.866 3.451 ;
     RECT  18.54 3.403 20.394 3.533 ;
     RECT  162.468 3.029 162.486 3.541 ;
     RECT  25.38 3.371 53.154 3.547 ;
     RECT  162.432 3.541 162.486 3.581 ;
     RECT  25.308 3.547 53.154 3.605 ;
     RECT  12.276 3.451 16.866 3.683 ;
     RECT  18.54 3.533 20.142 3.685 ;
     RECT  12.348 3.683 16.866 3.721 ;
     RECT  17.928 3.685 20.142 3.721 ;
     RECT  88.164 3.379 161.19 3.773 ;
     RECT  88.164 3.773 118.818 3.839 ;
     RECT  2.34 2.867 10.998 3.847 ;
     RECT  25.38 3.605 53.154 3.917 ;
     RECT  54.216 3.371 87.354 3.947 ;
     RECT  2.34 3.847 11.394 3.965 ;
     RECT  21.276 3.335 24.354 3.991 ;
     RECT  25.38 3.917 28.494 4.019 ;
     RECT  69.444 3.947 87.354 4.081 ;
     RECT  162.468 3.581 162.486 4.108 ;
     RECT  25.38 4.019 28.458 4.109 ;
     RECT  21.276 3.991 24.462 4.117 ;
     RECT  54.216 3.947 68.526 4.123 ;
     RECT  69.444 4.081 87.426 4.216 ;
     RECT  88.164 3.839 102.222 4.216 ;
     RECT  29.415 3.917 53.082 4.217 ;
     RECT  162.468 4.108 162.522 4.217 ;
     RECT  21.24 4.117 24.462 4.289 ;
     RECT  102.96 3.839 118.818 4.289 ;
     RECT  2.34 3.965 8.694 4.363 ;
     RECT  21.528 4.289 24.462 4.379 ;
     RECT  102.96 4.289 106.578 4.415 ;
     RECT  119.592 3.773 161.19 4.415 ;
     RECT  9.432 3.965 11.394 4.423 ;
     RECT  12.348 3.721 20.142 4.423 ;
     RECT  2.304 4.363 8.694 4.487 ;
     RECT  9.432 4.423 20.142 4.495 ;
     RECT  107.712 4.289 118.818 4.531 ;
     RECT  119.592 4.415 160.542 4.531 ;
     RECT  161.316 4.495 161.334 4.531 ;
     RECT  9.432 4.495 20.79 4.541 ;
     RECT  54.072 4.123 68.526 4.559 ;
     RECT  21.996 4.379 24.462 4.603 ;
     RECT  56.304 4.559 58.734 4.649 ;
     RECT  161.316 4.531 161.478 4.651 ;
     RECT  162.468 4.217 162.486 4.651 ;
     RECT  59.472 4.559 68.526 4.699 ;
     RECT  69.444 4.216 102.222 4.699 ;
     RECT  0.216 3.739 0.234 4.733 ;
     RECT  161.316 4.651 162.486 4.757 ;
     RECT  2.415 4.487 8.694 4.765 ;
     RECT  9.432 4.541 20.466 4.765 ;
     RECT  48.312 4.217 53.082 4.765 ;
     RECT  2.415 4.765 20.466 4.829 ;
     RECT  25.776 4.109 28.458 4.891 ;
     RECT  29.415 4.217 47.574 4.891 ;
     RECT  21.996 4.603 24.966 4.919 ;
     RECT  2.415 4.829 11.43 4.955 ;
     RECT  12.168 4.829 20.466 4.955 ;
     RECT  48.312 4.765 53.118 4.987 ;
     RECT  54.072 4.559 55.458 4.987 ;
     RECT  48.312 4.987 55.458 5.027 ;
     RECT  9.684 4.955 11.43 5.063 ;
     RECT  59.472 4.699 102.222 5.071 ;
     RECT  103.536 4.415 106.578 5.071 ;
     RECT  107.712 4.531 160.542 5.071 ;
     RECT  161.316 4.757 161.406 5.099 ;
     RECT  21.996 4.919 24.678 5.131 ;
     RECT  25.776 4.891 47.574 5.161 ;
     RECT  48.312 5.027 52.182 5.161 ;
     RECT  25.776 5.161 52.182 5.197 ;
     RECT  25.524 5.197 52.182 5.213 ;
     RECT  39.024 5.213 52.182 5.297 ;
     RECT  2.415 4.955 8.874 5.305 ;
     RECT  53.028 5.027 55.458 5.305 ;
     RECT  56.34 4.649 58.734 5.305 ;
     RECT  59.472 5.071 102.69 5.305 ;
     RECT  103.536 5.071 160.542 5.305 ;
     RECT  2.376 5.305 8.874 5.323 ;
     RECT  14.796 4.955 20.466 5.333 ;
     RECT  17.568 5.333 20.466 5.341 ;
     RECT  21.636 5.131 24.678 5.341 ;
     RECT  53.028 5.305 55.494 5.341 ;
     RECT  25.524 5.213 38.286 5.453 ;
     RECT  14.796 5.333 16.506 5.459 ;
     RECT  17.568 5.341 24.678 5.495 ;
     RECT  56.34 5.305 102.69 5.495 ;
     RECT  103.536 5.305 161.19 5.495 ;
     RECT  40.176 5.297 52.182 5.531 ;
     RECT  53.028 5.341 55.566 5.611 ;
     RECT  56.34 5.495 69.282 5.611 ;
     RECT  0.216 5.563 0.234 5.693 ;
     RECT  12.168 4.955 13.914 5.701 ;
     RECT  103.536 5.495 160.938 5.729 ;
     RECT  25.524 5.453 38.25 5.845 ;
     RECT  40.215 5.531 52.182 5.845 ;
     RECT  53.028 5.611 69.282 5.845 ;
     RECT  70.02 5.495 102.69 5.845 ;
     RECT  103.536 5.729 160.866 5.845 ;
     RECT  2.304 5.323 8.874 5.881 ;
     RECT  9.792 5.063 11.43 5.881 ;
     RECT  12.168 5.701 13.986 5.881 ;
     RECT  70.02 5.845 160.866 5.909 ;
     RECT  162.468 4.757 162.486 5.971 ;
     RECT  17.568 5.495 24.39 5.999 ;
     RECT  106.956 5.909 160.866 5.999 ;
     RECT  2.304 5.881 13.986 6.007 ;
     RECT  14.796 5.459 16.47 6.007 ;
     RECT  70.02 5.909 106.218 6.071 ;
     RECT  79.02 6.071 106.218 6.143 ;
     RECT  2.304 6.007 16.47 6.277 ;
     RECT  2.304 6.277 16.794 6.305 ;
     RECT  40.215 5.845 69.282 6.313 ;
     RECT  70.02 6.071 78.297 6.313 ;
     RECT  39.024 5.297 39.042 6.379 ;
     RECT  17.604 5.999 24.39 6.385 ;
     RECT  25.164 5.845 38.25 6.385 ;
     RECT  39.024 6.379 39.222 6.421 ;
     RECT  17.604 6.385 38.25 6.539 ;
     RECT  162.432 5.971 162.486 6.557 ;
     RECT  17.604 6.539 34.074 6.575 ;
     RECT  79.812 6.143 106.218 6.575 ;
     RECT  34.815 6.539 38.25 6.691 ;
     RECT  39.024 6.421 39.402 6.691 ;
     RECT  79.812 6.575 102.546 6.701 ;
     RECT  17.856 6.575 34.074 6.719 ;
     RECT  103.32 6.575 106.218 6.763 ;
     RECT  106.956 5.999 160.758 6.763 ;
     RECT  2.376 6.305 16.794 6.817 ;
     RECT  34.815 6.691 39.402 6.817 ;
     RECT  40.215 6.313 78.297 6.817 ;
     RECT  96.264 6.701 102.546 6.845 ;
     RECT  0.216 6.817 0.234 6.941 ;
     RECT  96.804 6.845 102.546 6.989 ;
     RECT  103.32 6.763 160.758 7.079 ;
     RECT  79.02 6.143 79.038 7.123 ;
     RECT  79.812 6.701 95.526 7.123 ;
     RECT  34.815 6.817 78.297 7.187 ;
     RECT  79.02 7.123 95.526 7.232 ;
     RECT  2.376 6.817 17.046 7.243 ;
     RECT  103.32 7.079 160.686 7.259 ;
     RECT  162.468 6.557 162.486 7.321 ;
     RECT  2.304 7.243 17.046 7.387 ;
     RECT  2.304 7.387 17.118 7.393 ;
     RECT  17.856 6.719 33.858 7.393 ;
     RECT  60.876 7.187 78.297 7.393 ;
     RECT  79.02 7.232 95.49 7.393 ;
     RECT  34.815 7.187 60.102 7.421 ;
     RECT  34.815 7.421 49.878 7.501 ;
     RECT  60.876 7.393 95.49 7.529 ;
     RECT  96.984 6.989 102.546 7.627 ;
     RECT  103.32 7.259 160.506 7.627 ;
     RECT  71.964 7.529 95.49 7.727 ;
     RECT  2.304 7.393 33.858 7.763 ;
     RECT  71.964 7.727 81.198 7.763 ;
     RECT  82.26 7.727 95.49 7.763 ;
     RECT  2.34 7.763 33.858 7.771 ;
     RECT  34.776 7.501 49.878 7.771 ;
     RECT  96.984 7.627 160.506 7.771 ;
     RECT  71.964 7.763 80.622 7.853 ;
     RECT  96.948 7.771 160.506 7.853 ;
     RECT  72.036 7.853 80.622 7.889 ;
     RECT  2.34 7.771 49.878 7.901 ;
     RECT  72.144 7.889 80.622 7.925 ;
     RECT  58.104 7.421 60.102 8.041 ;
     RECT  60.876 7.529 71.226 8.041 ;
     RECT  96.948 7.853 155.898 8.041 ;
     RECT  156.744 7.853 160.506 8.041 ;
     RECT  82.332 7.763 95.49 8.059 ;
     RECT  2.415 7.901 49.878 8.159 ;
     RECT  28.476 8.159 49.878 8.167 ;
     RECT  50.652 7.421 57.294 8.167 ;
     RECT  82.332 8.059 95.778 8.167 ;
     RECT  96.912 8.041 155.898 8.167 ;
     RECT  28.476 8.167 57.294 8.195 ;
     RECT  162.432 7.321 162.486 8.195 ;
     RECT  82.332 8.167 155.898 8.267 ;
     RECT  56.376 8.195 57.294 8.311 ;
     RECT  58.104 8.041 71.226 8.311 ;
     RECT  82.332 8.267 155.718 8.339 ;
     RECT  2.415 8.159 27.738 8.429 ;
     RECT  82.332 8.339 155.574 8.429 ;
     RECT  28.476 8.195 55.602 8.477 ;
     RECT  72.216 7.925 80.622 8.671 ;
     RECT  28.476 8.477 28.494 8.699 ;
     RECT  72.18 8.671 80.622 8.707 ;
     RECT  72.108 8.707 80.622 8.743 ;
     RECT  2.415 8.429 20.682 8.807 ;
     RECT  2.415 8.807 9.198 8.827 ;
     RECT  56.376 8.311 71.298 8.851 ;
     RECT  72.036 8.743 80.622 8.851 ;
     RECT  156.744 8.041 160.938 8.851 ;
     RECT  162.432 8.195 162.45 8.879 ;
     RECT  2.304 8.827 9.198 9.005 ;
     RECT  21.42 8.429 27.738 9.049 ;
     RECT  156.744 8.851 161.37 9.085 ;
     RECT  0.54 7.897 0.558 9.197 ;
     RECT  10.188 8.807 20.682 9.239 ;
     RECT  156.744 9.085 161.586 9.239 ;
     RECT  12.24 9.239 20.682 9.247 ;
     RECT  21.42 9.049 27.954 9.247 ;
     RECT  56.376 8.851 80.622 9.275 ;
     RECT  156.744 9.239 161.01 9.275 ;
     RECT  29.376 8.477 55.602 9.283 ;
     RECT  56.376 9.275 70.398 9.283 ;
     RECT  82.476 8.429 155.574 9.283 ;
     RECT  82.476 9.283 155.754 9.355 ;
     RECT  12.24 9.247 27.954 9.499 ;
     RECT  82.476 9.355 155.898 9.509 ;
     RECT  71.28 9.275 80.622 9.517 ;
     RECT  81.648 9.391 81.666 9.517 ;
     RECT  71.28 9.517 81.666 9.545 ;
     RECT  12.24 9.499 28.134 9.581 ;
     RECT  29.376 9.283 70.398 9.589 ;
     RECT  92.88 9.509 155.898 9.589 ;
     RECT  156.744 9.275 160.146 9.589 ;
     RECT  18.324 9.581 28.134 9.653 ;
     RECT  18.324 9.653 20.178 9.689 ;
     RECT  20.952 9.653 28.134 9.689 ;
     RECT  28.908 9.589 70.398 9.689 ;
     RECT  162.468 8.971 162.486 9.739 ;
     RECT  18.324 9.689 20.106 9.779 ;
     RECT  161.892 9.739 162.486 9.779 ;
     RECT  71.388 9.545 81.666 9.787 ;
     RECT  82.476 9.509 92.142 9.787 ;
     RECT  21.096 9.689 28.134 9.815 ;
     RECT  161.892 9.779 162.45 9.887 ;
     RECT  2.412 9.005 9.198 9.895 ;
     RECT  10.188 9.239 11.502 9.895 ;
     RECT  29.016 9.689 70.398 9.959 ;
     RECT  160.992 9.275 161.01 10.049 ;
     RECT  2.412 9.895 11.502 10.057 ;
     RECT  2.304 10.057 11.502 10.093 ;
     RECT  12.24 9.581 17.478 10.093 ;
     RECT  92.88 9.589 160.146 10.129 ;
     RECT  160.956 10.093 160.974 10.129 ;
     RECT  36.036 9.959 70.398 10.291 ;
     RECT  92.88 10.129 160.974 10.319 ;
     RECT  71.388 9.787 92.142 10.327 ;
     RECT  92.88 10.319 160.866 10.327 ;
     RECT  71.388 10.327 160.866 10.355 ;
     RECT  2.304 10.093 17.478 10.363 ;
     RECT  18.324 9.779 20.07 10.363 ;
     RECT  2.304 10.363 20.07 10.561 ;
     RECT  21.096 9.815 27.99 10.561 ;
     RECT  29.016 9.959 35.154 10.561 ;
     RECT  162.432 9.887 162.45 10.589 ;
     RECT  71.388 10.355 160.362 10.625 ;
     RECT  2.304 10.561 35.154 10.741 ;
     RECT  36.036 10.291 70.614 10.843 ;
     RECT  71.388 10.625 94.914 10.843 ;
     RECT  95.688 10.625 160.362 10.967 ;
     RECT  2.304 10.741 35.262 11.011 ;
     RECT  36.036 10.843 94.914 11.011 ;
     RECT  2.304 11.011 94.914 11.021 ;
     RECT  2.304 11.021 27.99 11.171 ;
     RECT  20.772 11.171 27.99 11.273 ;
     RECT  29.088 11.021 94.914 11.273 ;
     RECT  95.724 10.967 160.362 11.281 ;
     RECT  2.304 11.171 19.782 11.435 ;
     RECT  33.264 11.273 94.914 11.471 ;
     RECT  95.724 11.281 161.19 11.471 ;
     RECT  47.916 11.471 94.914 11.507 ;
     RECT  131.904 11.471 161.19 11.543 ;
     RECT  20.916 11.273 27.99 11.549 ;
     RECT  131.94 11.543 161.19 11.551 ;
     RECT  33.264 11.471 47.106 11.579 ;
     RECT  131.94 11.551 161.262 11.579 ;
     RECT  131.976 11.579 161.262 11.659 ;
     RECT  162.468 10.843 162.486 11.659 ;
     RECT  131.976 11.659 162.486 11.669 ;
     RECT  161.064 11.669 161.082 11.705 ;
     RECT  20.952 11.549 27.99 11.749 ;
     RECT  53.028 11.507 94.914 11.749 ;
     RECT  95.724 11.471 131.166 11.749 ;
     RECT  29.088 11.273 32.526 11.785 ;
     RECT  161.892 11.669 162.486 11.849 ;
     RECT  2.376 11.435 19.782 11.939 ;
     RECT  162.468 11.849 162.486 11.939 ;
     RECT  2.415 11.939 19.782 12.091 ;
     RECT  53.028 11.749 131.166 12.209 ;
     RECT  20.952 11.749 28.026 12.253 ;
     RECT  29.016 11.785 32.526 12.253 ;
     RECT  47.916 11.507 52.218 12.28 ;
     RECT  53.028 12.209 95.454 12.28 ;
     RECT  33.552 11.579 47.106 12.289 ;
     RECT  33.552 12.289 47.178 12.361 ;
     RECT  47.916 12.28 95.454 12.361 ;
     RECT  20.952 12.253 32.526 12.389 ;
     RECT  131.976 11.669 159.966 12.451 ;
     RECT  27.828 12.389 32.526 12.487 ;
     RECT  33.552 12.361 95.454 12.487 ;
     RECT  2.415 12.091 19.89 12.523 ;
     RECT  96.228 12.209 131.166 12.523 ;
     RECT  131.94 12.451 160.362 12.523 ;
     RECT  96.228 12.523 160.686 12.557 ;
     RECT  20.952 12.389 26.766 12.559 ;
     RECT  2.415 12.523 19.962 12.595 ;
     RECT  20.772 12.559 26.766 12.595 ;
     RECT  156.024 12.557 160.686 12.595 ;
     RECT  27.828 12.487 95.454 12.623 ;
     RECT  163.584 10.315 163.602 12.623 ;
     RECT  27.828 12.623 53.046 12.845 ;
     RECT  2.415 12.595 26.766 12.901 ;
     RECT  2.376 12.901 26.766 12.955 ;
     RECT  53.82 12.623 95.454 12.991 ;
     RECT  96.228 12.557 155.286 12.991 ;
     RECT  53.82 12.991 155.286 13.019 ;
     RECT  156.024 12.595 161.154 13.063 ;
     RECT  27.828 12.845 53.01 13.091 ;
     RECT  27.936 13.091 52.902 13.289 ;
     RECT  156.024 13.063 161.442 13.289 ;
     RECT  162.468 12.715 162.486 13.289 ;
     RECT  53.928 13.019 155.286 13.297 ;
     RECT  156.024 13.289 160.974 13.297 ;
     RECT  0.216 11.785 0.234 13.325 ;
     RECT  27.936 13.289 52.686 13.325 ;
     RECT  2.304 12.955 26.766 13.369 ;
     RECT  2.304 13.369 26.802 13.433 ;
     RECT  2.304 13.433 20.898 13.559 ;
     RECT  53.928 13.297 160.974 13.559 ;
     RECT  163.584 13.531 163.602 13.667 ;
     RECT  53.928 13.559 160.794 13.709 ;
     RECT  20.088 13.559 20.898 13.829 ;
     RECT  21.672 13.433 26.802 13.853 ;
     RECT  25.56 13.853 26.802 13.945 ;
     RECT  27.936 13.325 52.65 13.945 ;
     RECT  21.672 13.853 24.822 14.099 ;
     RECT  25.56 13.945 52.65 14.099 ;
     RECT  25.56 14.099 26.874 14.135 ;
     RECT  54.072 13.709 160.794 14.135 ;
     RECT  2.304 13.559 19.134 14.341 ;
     RECT  20.088 13.829 20.862 14.341 ;
     RECT  27.612 14.099 52.65 14.341 ;
     RECT  155.916 14.135 160.794 14.369 ;
     RECT  27.612 14.341 52.83 14.413 ;
     RECT  155.916 14.369 160.218 14.441 ;
     RECT  2.304 14.341 20.862 14.483 ;
     RECT  27.612 14.413 53.154 14.485 ;
     RECT  54.072 14.135 155.178 14.485 ;
     RECT  2.304 14.483 20.754 14.513 ;
     RECT  27.612 14.485 155.178 14.513 ;
     RECT  2.304 14.513 20.682 14.521 ;
     RECT  2.268 14.521 20.682 14.621 ;
     RECT  2.304 14.621 20.682 14.639 ;
     RECT  27.612 14.513 155.106 14.639 ;
     RECT  162.432 13.819 162.45 14.639 ;
     RECT  21.672 14.099 24.786 14.675 ;
     RECT  27.612 14.639 155.07 14.765 ;
     RECT  21.672 14.675 24.297 14.791 ;
     RECT  25.848 14.135 26.874 14.881 ;
     RECT  27.612 14.765 155.034 14.881 ;
     RECT  0.216 14.755 0.234 14.909 ;
     RECT  25.812 14.881 155.034 14.909 ;
     RECT  25.812 14.909 102.366 14.917 ;
     RECT  25.56 14.917 102.366 14.953 ;
     RECT  103.176 14.909 155.034 15.017 ;
     RECT  163.584 15.151 163.602 15.197 ;
     RECT  21.492 14.791 24.297 15.215 ;
     RECT  25.524 14.953 102.366 15.287 ;
     RECT  25.524 15.287 36.558 15.295 ;
     RECT  156.204 14.441 160.218 15.295 ;
     RECT  2.304 14.639 20.646 15.359 ;
     RECT  156.204 15.295 160.794 15.403 ;
     RECT  11.916 15.359 20.646 15.421 ;
     RECT  21.492 15.215 21.546 15.421 ;
     RECT  22.284 15.215 24.297 15.421 ;
     RECT  25.344 15.295 36.558 15.421 ;
     RECT  11.916 15.421 21.546 15.593 ;
     RECT  156.096 15.403 160.794 15.691 ;
     RECT  162.468 14.875 162.486 15.691 ;
     RECT  156.096 15.691 161.01 15.727 ;
     RECT  103.176 15.017 154.962 15.763 ;
     RECT  155.88 15.727 161.01 15.763 ;
     RECT  161.892 15.691 162.486 15.827 ;
     RECT  37.332 15.287 102.366 15.871 ;
     RECT  103.176 15.763 161.01 15.871 ;
     RECT  16.02 15.593 21.546 16.033 ;
     RECT  22.284 15.421 36.558 16.033 ;
     RECT  0.288 15.727 0.306 16.105 ;
     RECT  2.304 15.359 10.818 16.105 ;
     RECT  16.02 16.033 36.558 16.133 ;
     RECT  2.304 16.105 11.142 16.141 ;
     RECT  11.916 15.593 14.994 16.141 ;
     RECT  0.252 16.105 0.306 16.171 ;
     RECT  16.128 16.133 36.558 16.219 ;
     RECT  37.332 15.871 161.01 16.219 ;
     RECT  16.128 16.219 161.01 16.267 ;
     RECT  0.216 16.171 0.306 16.349 ;
     RECT  16.128 16.267 161.046 16.375 ;
     RECT  2.304 16.141 14.994 16.411 ;
     RECT  16.128 16.375 161.298 16.529 ;
     RECT  16.128 16.529 161.046 16.565 ;
     RECT  0.252 16.349 0.306 16.645 ;
     RECT  0.252 16.645 0.522 16.771 ;
     RECT  16.128 16.565 155.178 16.799 ;
     RECT  162.468 15.827 162.486 16.799 ;
     RECT  0.252 16.771 0.558 16.807 ;
     RECT  16.128 16.799 37.53 16.829 ;
     RECT  2.304 16.411 15.246 16.915 ;
     RECT  16.128 16.829 37.494 16.915 ;
     RECT  2.304 16.915 37.494 16.943 ;
     RECT  155.916 16.565 161.046 17.069 ;
     RECT  21.996 16.943 37.494 17.105 ;
     RECT  38.268 16.799 155.178 17.105 ;
     RECT  26.028 17.105 37.494 17.141 ;
     RECT  0.252 16.807 0.846 17.165 ;
     RECT  163.584 17.035 163.602 17.311 ;
     RECT  163.008 17.311 163.602 17.563 ;
     RECT  162.432 17.563 163.602 17.609 ;
     RECT  40.032 17.105 155.178 17.645 ;
     RECT  92.16 17.645 155.178 17.653 ;
     RECT  155.916 17.069 161.01 17.653 ;
     RECT  26.028 17.141 37.422 17.681 ;
     RECT  21.996 17.105 25.11 17.725 ;
     RECT  21.888 17.725 25.11 17.761 ;
     RECT  2.304 16.943 20.97 17.851 ;
     RECT  21.816 17.761 25.11 17.851 ;
     RECT  38.268 17.105 39.258 17.851 ;
     RECT  2.304 17.851 25.182 17.915 ;
     RECT  21.888 17.915 25.182 17.923 ;
     RECT  92.16 17.653 161.01 17.951 ;
     RECT  21.888 17.923 25.254 17.959 ;
     RECT  26.028 17.681 32.994 17.959 ;
     RECT  21.888 17.959 32.994 17.996 ;
     RECT  2.304 17.915 21.114 18.029 ;
     RECT  38.268 17.851 39.294 18.059 ;
     RECT  2.304 18.029 21.078 18.149 ;
     RECT  21.924 17.996 32.994 18.149 ;
     RECT  40.032 17.645 91.17 18.149 ;
     RECT  22.248 18.149 32.994 18.221 ;
     RECT  33.732 17.681 37.422 18.301 ;
     RECT  38.268 18.059 39.15 18.301 ;
     RECT  2.304 18.149 11.07 18.379 ;
     RECT  33.732 18.301 39.15 18.419 ;
     RECT  22.428 18.221 32.994 18.427 ;
     RECT  33.732 18.419 38.214 18.427 ;
     RECT  40.032 18.149 40.842 18.455 ;
     RECT  163.008 17.609 163.602 18.527 ;
     RECT  41.796 18.149 91.17 18.535 ;
     RECT  92.16 17.951 119.394 18.535 ;
     RECT  120.24 17.951 161.01 18.571 ;
     RECT  161.784 18.535 161.802 18.571 ;
     RECT  40.032 18.455 40.662 18.661 ;
     RECT  163.008 18.527 163.026 18.667 ;
     RECT  120.24 18.571 161.802 18.689 ;
     RECT  2.268 18.379 11.07 18.697 ;
     RECT  41.796 18.535 119.394 18.715 ;
     RECT  120.24 18.689 161.154 18.715 ;
     RECT  22.428 18.427 38.214 18.725 ;
     RECT  0.288 17.165 0.846 18.733 ;
     RECT  2.196 18.697 11.07 18.749 ;
     RECT  41.796 18.715 161.154 18.803 ;
     RECT  38.988 18.419 39.15 18.811 ;
     RECT  39.924 18.661 40.662 18.811 ;
     RECT  22.428 18.725 37.818 18.833 ;
     RECT  11.808 18.149 21.078 18.859 ;
     RECT  2.268 18.749 11.07 18.931 ;
     RECT  11.808 18.859 21.186 18.931 ;
     RECT  38.988 18.811 40.662 18.995 ;
     RECT  162.684 18.667 163.026 19.067 ;
     RECT  22.428 18.833 37.782 19.099 ;
     RECT  22.356 19.099 37.782 19.139 ;
     RECT  39.924 18.995 40.662 19.195 ;
     RECT  41.796 18.803 130.518 19.195 ;
     RECT  2.268 18.931 21.186 19.201 ;
     RECT  131.436 18.803 161.154 19.229 ;
     RECT  22.428 19.139 37.782 19.265 ;
     RECT  22.572 19.265 37.782 19.337 ;
     RECT  2.268 19.201 21.438 19.381 ;
     RECT  38.988 18.995 39.114 19.381 ;
     RECT  22.608 19.337 37.782 19.627 ;
     RECT  163.008 19.067 163.026 19.769 ;
     RECT  2.268 19.381 21.618 19.805 ;
     RECT  22.608 19.627 38.178 19.841 ;
     RECT  39.924 19.195 130.518 19.849 ;
     RECT  131.436 19.229 161.082 19.849 ;
     RECT  30.924 19.841 38.178 19.921 ;
     RECT  38.916 19.381 39.114 19.921 ;
     RECT  0.216 18.733 0.846 20.045 ;
     RECT  163.584 20.005 163.602 20.045 ;
     RECT  30.924 19.921 39.114 20.047 ;
     RECT  39.924 19.849 161.082 20.047 ;
     RECT  30.924 20.047 161.082 20.075 ;
     RECT  22.608 19.841 30.186 20.141 ;
     RECT  22.716 20.141 30.186 20.147 ;
     RECT  39.276 20.075 161.082 20.147 ;
     RECT  2.304 19.805 21.618 20.299 ;
     RECT  30.924 20.075 38.502 20.309 ;
     RECT  104.724 20.147 161.082 20.333 ;
     RECT  2.304 20.299 21.69 20.345 ;
     RECT  22.716 20.147 27.918 20.381 ;
     RECT  2.304 20.345 21.618 20.387 ;
     RECT  2.304 20.387 21.474 20.453 ;
     RECT  28.656 20.147 30.186 20.453 ;
     RECT  39.276 20.147 103.986 20.477 ;
     RECT  22.716 20.381 27.882 20.489 ;
     RECT  29.088 20.453 30.186 20.489 ;
     RECT  27.864 20.489 27.882 20.579 ;
     RECT  29.376 20.489 30.186 20.579 ;
     RECT  162.432 20.251 162.45 20.579 ;
     RECT  30.924 20.309 38.358 20.587 ;
     RECT  29.376 20.579 30.006 20.621 ;
     RECT  29.376 20.621 29.862 20.651 ;
     RECT  22.716 20.489 27.09 20.687 ;
     RECT  23.508 20.687 27.09 20.759 ;
     RECT  39.276 20.477 92.322 20.885 ;
     RECT  93.132 20.477 103.986 20.893 ;
     RECT  104.724 20.333 145.782 20.893 ;
     RECT  39.276 20.885 92.286 20.957 ;
     RECT  39.276 20.957 92.25 20.971 ;
     RECT  26.568 20.759 27.09 20.993 ;
     RECT  162.468 20.827 162.486 21.067 ;
     RECT  93.132 20.893 145.782 21.091 ;
     RECT  146.52 20.333 161.082 21.091 ;
     RECT  30.78 20.587 38.358 21.119 ;
     RECT  0.216 20.045 0.27 21.211 ;
     RECT  162.468 21.067 162.522 21.227 ;
     RECT  32.508 21.119 38.358 21.235 ;
     RECT  39.204 20.971 92.25 21.235 ;
     RECT  29.376 20.651 29.697 21.271 ;
     RECT  27.072 20.993 27.09 21.505 ;
     RECT  27.828 21.361 27.846 21.505 ;
     RECT  30.78 21.119 31.734 21.505 ;
     RECT  32.508 21.235 92.25 21.533 ;
     RECT  2.304 20.453 20.826 21.541 ;
     RECT  23.508 20.759 25.794 21.541 ;
     RECT  29.34 21.271 29.697 21.541 ;
     RECT  30.6 21.505 31.734 21.541 ;
     RECT  93.132 21.091 161.082 21.541 ;
     RECT  161.892 21.355 161.91 21.541 ;
     RECT  33.048 21.533 92.25 21.569 ;
     RECT  2.304 21.541 21.006 21.631 ;
     RECT  2.304 21.631 21.69 21.643 ;
     RECT  23.076 21.541 25.794 21.643 ;
     RECT  2.304 21.643 25.794 21.703 ;
     RECT  33.084 21.569 92.25 21.739 ;
     RECT  93.132 21.541 161.91 21.739 ;
     RECT  29.34 21.541 31.734 21.811 ;
     RECT  28.656 21.811 31.734 21.929 ;
     RECT  2.304 21.703 26.046 21.937 ;
     RECT  27.072 21.505 27.846 21.937 ;
     RECT  33.084 21.739 161.91 22.001 ;
     RECT  2.304 21.937 27.846 22.157 ;
     RECT  28.656 21.929 31.626 22.171 ;
     RECT  2.376 22.157 27.846 22.199 ;
     RECT  33.084 22.001 161.658 22.235 ;
     RECT  25.092 22.199 27.846 22.279 ;
     RECT  28.584 22.171 31.626 22.279 ;
     RECT  2.376 22.199 24.354 22.505 ;
     RECT  25.092 22.279 31.626 22.505 ;
     RECT  33.084 22.235 37.314 22.549 ;
     RECT  162.468 22.411 162.486 22.549 ;
     RECT  163.584 22.081 163.602 22.549 ;
     RECT  32.58 22.549 37.314 22.577 ;
     RECT  2.376 22.505 24.297 22.649 ;
     RECT  32.58 22.577 33.966 22.711 ;
     RECT  25.092 22.505 25.362 22.733 ;
     RECT  39.492 22.235 161.658 22.733 ;
     RECT  39.528 22.733 161.658 22.739 ;
     RECT  25.092 22.733 25.29 22.775 ;
     RECT  26.1 22.505 31.626 22.775 ;
     RECT  22.644 22.649 24.297 22.781 ;
     RECT  25.092 22.775 25.254 22.781 ;
     RECT  162.468 22.549 163.602 22.783 ;
     RECT  25.092 22.781 25.218 22.811 ;
     RECT  38.088 22.235 38.718 22.811 ;
     RECT  39.528 22.739 86.202 22.811 ;
     RECT  30.816 22.775 31.626 22.819 ;
     RECT  32.436 22.711 33.966 22.819 ;
     RECT  86.94 22.739 161.658 22.855 ;
     RECT  162.468 22.783 163.962 22.855 ;
     RECT  40.215 22.811 86.202 22.883 ;
     RECT  42.012 22.883 86.202 22.919 ;
     RECT  0.216 21.211 0.306 23.035 ;
     RECT  23.724 22.781 24.297 23.045 ;
     RECT  42.084 22.919 86.202 23.045 ;
     RECT  42.12 23.045 86.202 23.081 ;
     RECT  86.94 22.855 163.962 23.081 ;
     RECT  42.264 23.081 86.202 23.117 ;
     RECT  34.704 22.577 37.314 23.161 ;
     RECT  38.088 22.811 38.538 23.161 ;
     RECT  34.704 23.161 38.538 23.189 ;
     RECT  87.012 23.081 163.962 23.189 ;
     RECT  0.216 23.035 0.342 23.213 ;
     RECT  2.376 22.649 21.906 23.227 ;
     RECT  26.1 22.775 29.898 23.227 ;
     RECT  163.044 23.189 163.962 23.261 ;
     RECT  2.304 23.227 21.906 23.279 ;
     RECT  22.824 22.781 22.986 23.279 ;
     RECT  30.816 22.819 33.966 23.323 ;
     RECT  34.704 23.189 38.466 23.323 ;
     RECT  30.816 23.323 38.466 23.423 ;
     RECT  22.968 23.279 22.986 23.549 ;
     RECT  40.215 22.883 41.238 23.549 ;
     RECT  163.584 23.261 163.962 23.549 ;
     RECT  42.264 23.117 71.586 23.585 ;
     RECT  87.012 23.189 162.162 23.585 ;
     RECT  2.415 23.279 21.906 23.657 ;
     RECT  40.215 23.549 41.166 23.657 ;
     RECT  26.028 23.227 29.898 23.665 ;
     RECT  25.92 23.665 29.898 23.701 ;
     RECT  87.012 23.585 143.097 23.741 ;
     RECT  25.92 23.701 30.042 23.827 ;
     RECT  23.868 23.045 24.297 23.899 ;
     RECT  25.092 22.811 25.11 23.899 ;
     RECT  72.36 23.117 86.202 23.899 ;
     RECT  87.012 23.741 104.058 23.899 ;
     RECT  40.215 23.657 41.13 23.935 ;
     RECT  31.104 23.423 38.466 23.971 ;
     RECT  31.104 23.971 38.754 24.043 ;
     RECT  42.372 23.585 71.586 24.061 ;
     RECT  72.36 23.899 104.058 24.061 ;
     RECT  163.656 23.549 163.962 24.077 ;
     RECT  2.415 23.657 20.862 24.089 ;
     RECT  42.372 24.061 104.058 24.089 ;
     RECT  23.868 23.899 25.11 24.097 ;
     RECT  2.415 24.089 12.006 24.133 ;
     RECT  31.104 24.043 38.826 24.133 ;
     RECT  39.636 23.935 41.13 24.133 ;
     RECT  2.376 24.133 12.006 24.169 ;
     RECT  23.58 24.097 25.11 24.169 ;
     RECT  25.92 23.827 30.186 24.169 ;
     RECT  2.304 24.169 12.006 24.197 ;
     RECT  23.58 24.169 30.186 24.205 ;
     RECT  31.104 24.133 41.13 24.205 ;
     RECT  2.304 24.197 11.43 24.379 ;
     RECT  12.744 24.089 20.862 24.379 ;
     RECT  104.904 23.741 143.097 24.427 ;
     RECT  143.82 23.585 162.162 24.427 ;
     RECT  2.196 24.379 11.43 24.431 ;
     RECT  12.744 24.379 20.934 24.439 ;
     RECT  21.744 23.657 21.906 24.439 ;
     RECT  23.58 24.205 41.13 24.475 ;
     RECT  2.196 24.431 11.286 24.509 ;
     RECT  12.744 24.439 21.906 24.509 ;
     RECT  42.66 24.089 104.058 24.511 ;
     RECT  104.904 24.427 162.162 24.511 ;
     RECT  163.656 24.077 163.674 24.571 ;
     RECT  22.68 24.511 22.698 24.629 ;
     RECT  23.508 24.475 41.13 24.637 ;
     RECT  2.268 24.509 11.286 24.797 ;
     RECT  12.744 24.509 20.718 24.809 ;
     RECT  12.744 24.809 16.29 24.899 ;
     RECT  17.208 24.809 20.718 24.935 ;
     RECT  23.508 24.637 41.778 24.943 ;
     RECT  42.66 24.511 162.162 24.943 ;
     RECT  23.436 24.943 41.778 25.141 ;
     RECT  42.624 24.943 162.162 25.241 ;
     RECT  12.744 24.899 16.146 25.249 ;
     RECT  0.216 23.213 0.234 25.285 ;
     RECT  2.304 24.797 11.286 25.285 ;
     RECT  12.312 25.249 16.146 25.285 ;
     RECT  42.624 25.241 67.59 25.439 ;
     RECT  21.744 24.509 21.906 25.447 ;
     RECT  19.836 24.935 20.718 25.519 ;
     RECT  21.744 25.447 21.978 25.519 ;
     RECT  163.584 24.571 163.674 25.619 ;
     RECT  2.304 25.285 16.146 25.627 ;
     RECT  17.208 24.935 19.062 25.627 ;
     RECT  2.304 25.627 19.062 25.661 ;
     RECT  17.352 25.661 19.062 25.675 ;
     RECT  19.836 25.519 21.978 25.675 ;
     RECT  23.364 25.141 41.778 25.717 ;
     RECT  23.364 25.717 42.03 25.745 ;
     RECT  23.508 25.745 42.03 25.757 ;
     RECT  23.508 25.757 41.634 25.853 ;
     RECT  68.364 25.241 162.162 25.915 ;
     RECT  65.412 25.439 67.59 26.023 ;
     RECT  68.364 25.915 162.45 26.023 ;
     RECT  65.412 26.023 162.45 26.087 ;
     RECT  0.216 25.285 0.27 26.093 ;
     RECT  134.244 26.087 162.45 26.123 ;
     RECT  17.352 25.675 21.978 26.131 ;
     RECT  2.304 25.661 16.542 26.249 ;
     RECT  134.352 26.123 162.45 26.249 ;
     RECT  42.768 25.439 64.53 26.365 ;
     RECT  65.412 26.087 133.47 26.365 ;
     RECT  0.252 26.093 0.27 26.429 ;
     RECT  163.62 25.619 163.674 26.477 ;
     RECT  17.352 26.131 22.122 26.563 ;
     RECT  23.616 25.853 41.634 26.627 ;
     RECT  2.34 26.249 16.542 26.671 ;
     RECT  17.352 26.563 22.266 26.671 ;
     RECT  41.58 26.627 41.634 26.671 ;
     RECT  134.82 26.249 162.45 26.731 ;
     RECT  41.58 26.671 41.994 26.761 ;
     RECT  42.768 26.365 133.47 26.761 ;
     RECT  134.82 26.731 162.486 26.761 ;
     RECT  163.584 26.563 163.602 26.761 ;
     RECT  2.34 26.671 22.266 26.933 ;
     RECT  23.616 26.627 40.806 26.941 ;
     RECT  41.58 26.761 133.47 26.941 ;
     RECT  21.096 26.933 22.266 26.957 ;
     RECT  2.34 26.933 20.358 27.019 ;
     RECT  41.58 26.941 134.082 27.031 ;
     RECT  134.82 26.761 163.602 27.031 ;
     RECT  41.58 27.031 163.602 27.053 ;
     RECT  23.436 26.941 40.806 27.059 ;
     RECT  23.58 27.059 40.806 27.167 ;
     RECT  21.276 26.957 22.266 27.211 ;
     RECT  31.176 27.167 40.806 27.239 ;
     RECT  41.58 27.053 163.062 27.293 ;
     RECT  21.276 27.211 22.662 27.329 ;
     RECT  23.58 27.167 30.366 27.329 ;
     RECT  39.24 27.239 40.806 27.329 ;
     RECT  2.268 27.019 20.358 27.337 ;
     RECT  40.215 27.329 40.806 27.355 ;
     RECT  41.58 27.293 163.026 27.355 ;
     RECT  21.276 27.329 22.266 27.389 ;
     RECT  2.232 27.337 20.358 27.437 ;
     RECT  40.215 27.355 163.026 27.599 ;
     RECT  2.268 27.437 20.358 27.635 ;
     RECT  2.268 27.635 16.722 27.905 ;
     RECT  17.532 27.635 20.358 27.913 ;
     RECT  23.94 27.329 30.366 27.985 ;
     RECT  31.176 27.239 38.358 27.985 ;
     RECT  39.24 27.329 39.474 27.985 ;
     RECT  0.54 27.337 0.558 28.013 ;
     RECT  21.276 27.389 22.158 28.111 ;
     RECT  23.94 27.985 39.474 28.123 ;
     RECT  40.215 27.599 162.486 28.123 ;
     RECT  23.94 28.123 162.486 28.147 ;
     RECT  17.532 27.913 20.502 28.267 ;
     RECT  17.532 28.267 20.538 28.291 ;
     RECT  21.276 28.111 22.878 28.291 ;
     RECT  23.868 28.147 162.486 28.319 ;
     RECT  163.62 28.021 163.638 28.363 ;
     RECT  17.532 28.291 22.878 28.381 ;
     RECT  23.868 28.319 31.302 28.409 ;
     RECT  32.04 28.319 162.486 28.409 ;
     RECT  32.112 28.409 162.486 28.412 ;
     RECT  32.148 28.412 162.486 28.481 ;
     RECT  32.184 28.481 162.486 28.637 ;
     RECT  23.868 28.409 30.726 28.715 ;
     RECT  163.584 28.363 163.638 28.723 ;
     RECT  0.216 28.603 0.234 28.733 ;
     RECT  2.304 27.905 16.722 28.831 ;
     RECT  17.532 28.381 23.058 28.831 ;
     RECT  23.868 28.715 27.45 28.831 ;
     RECT  28.26 28.715 30.726 28.859 ;
     RECT  2.304 28.831 27.45 28.949 ;
     RECT  32.184 28.637 162.198 28.949 ;
     RECT  2.304 28.949 20.646 28.985 ;
     RECT  21.456 28.949 27.45 28.985 ;
     RECT  28.296 28.859 30.726 29.021 ;
     RECT  28.692 29.021 30.726 29.057 ;
     RECT  28.692 29.057 30.294 29.093 ;
     RECT  2.34 28.985 20.646 29.129 ;
     RECT  15.048 29.129 20.646 29.219 ;
     RECT  21.456 28.985 27.27 29.255 ;
     RECT  2.34 29.129 14.13 29.399 ;
     RECT  28.692 29.093 30.078 29.489 ;
     RECT  80.46 28.949 162.198 29.707 ;
     RECT  163.044 28.723 163.638 29.707 ;
     RECT  31.032 29.641 31.302 29.767 ;
     RECT  32.184 28.949 79.722 29.767 ;
     RECT  2.34 29.399 13.842 29.794 ;
     RECT  21.672 29.255 27.27 29.803 ;
     RECT  28.692 29.489 29.934 29.803 ;
     RECT  31.032 29.767 79.722 29.875 ;
     RECT  80.46 29.707 163.638 29.875 ;
     RECT  31.032 29.875 163.638 29.981 ;
     RECT  31.032 29.981 162.486 30.001 ;
     RECT  21.672 29.803 29.934 30.029 ;
     RECT  15.192 29.219 20.646 30.181 ;
     RECT  2.304 29.794 13.842 30.235 ;
     RECT  14.796 30.181 21.078 30.235 ;
     RECT  30.672 30.001 162.486 30.299 ;
     RECT  21.852 30.029 29.934 30.343 ;
     RECT  30.672 30.299 38.898 30.343 ;
     RECT  163.584 29.981 163.638 30.479 ;
     RECT  39.672 30.299 162.486 30.569 ;
     RECT  163.62 30.479 163.638 30.763 ;
     RECT  2.304 30.235 21.078 30.811 ;
     RECT  21.852 30.343 38.898 30.811 ;
     RECT  2.304 30.811 38.898 30.875 ;
     RECT  163.62 30.763 163.962 30.893 ;
     RECT  2.304 30.875 21.186 30.911 ;
     RECT  21.96 30.875 38.898 31.109 ;
     RECT  26.82 31.109 38.898 31.117 ;
     RECT  39.672 30.569 162.198 31.117 ;
     RECT  26.82 31.117 162.198 31.415 ;
     RECT  32.256 31.415 162.198 31.451 ;
     RECT  106.884 31.451 162.198 31.579 ;
     RECT  2.304 30.911 21.114 31.801 ;
     RECT  2.304 31.801 21.258 31.891 ;
     RECT  22.176 31.109 26.046 31.891 ;
     RECT  32.256 31.451 106.146 31.919 ;
     RECT  27.252 31.415 31.518 32.161 ;
     RECT  32.256 31.919 51.678 32.161 ;
     RECT  106.884 31.579 162.522 32.161 ;
     RECT  163.584 31.291 163.602 32.161 ;
     RECT  52.452 31.919 106.146 32.197 ;
     RECT  106.884 32.161 163.602 32.197 ;
     RECT  52.452 32.197 163.602 32.237 ;
     RECT  2.304 31.891 26.046 32.296 ;
     RECT  107.028 32.237 163.602 32.341 ;
     RECT  0.216 31.723 0.234 32.477 ;
     RECT  52.452 32.237 106.038 32.495 ;
     RECT  2.304 32.296 26.154 32.503 ;
     RECT  2.304 32.503 26.19 32.539 ;
     RECT  2.304 32.539 26.298 32.575 ;
     RECT  27.252 32.161 51.678 32.575 ;
     RECT  107.028 32.341 163.638 32.669 ;
     RECT  2.304 32.575 51.678 32.729 ;
     RECT  15.768 32.729 51.678 32.881 ;
     RECT  15.768 32.881 51.894 32.909 ;
     RECT  52.776 32.495 106.038 32.971 ;
     RECT  17.856 32.909 51.894 32.999 ;
     RECT  107.028 32.669 162.486 32.999 ;
     RECT  52.776 32.971 106.182 33.043 ;
     RECT  107.028 32.999 161.874 33.043 ;
     RECT  15.768 32.909 17.046 33.053 ;
     RECT  2.304 32.729 14.886 33.403 ;
     RECT  17.964 32.999 51.894 33.499 ;
     RECT  52.776 33.043 161.874 33.499 ;
     RECT  17.964 33.499 161.874 33.539 ;
     RECT  15.876 33.053 17.046 33.575 ;
     RECT  22.824 33.539 161.874 33.683 ;
     RECT  2.268 33.403 14.886 33.781 ;
     RECT  22.824 33.683 161.802 33.809 ;
     RECT  163.584 32.669 163.638 33.925 ;
     RECT  16.164 33.575 17.046 33.961 ;
     RECT  17.964 33.539 22.05 33.961 ;
     RECT  163.584 33.925 163.674 33.961 ;
     RECT  2.268 33.781 15.426 34.027 ;
     RECT  163.044 33.961 163.674 34.301 ;
     RECT  16.164 33.961 22.05 34.321 ;
     RECT  22.824 33.809 124.146 34.321 ;
     RECT  2.232 34.027 15.426 34.457 ;
     RECT  0.216 33.739 0.234 34.493 ;
     RECT  2.268 34.457 15.426 34.501 ;
     RECT  16.164 34.321 124.146 34.501 ;
     RECT  124.884 33.809 161.802 34.501 ;
     RECT  124.884 34.501 162.486 34.589 ;
     RECT  2.268 34.501 124.146 34.591 ;
     RECT  124.884 34.589 161.874 34.591 ;
     RECT  2.268 34.591 161.874 34.655 ;
     RECT  163.584 34.301 163.674 34.771 ;
     RECT  2.268 34.655 112.122 34.925 ;
     RECT  113.04 34.655 161.874 34.997 ;
     RECT  2.268 34.925 29.697 35.033 ;
     RECT  113.328 34.997 161.874 35.159 ;
     RECT  30.564 34.925 112.122 35.195 ;
     RECT  48.348 35.195 112.122 35.401 ;
     RECT  163.584 34.771 163.746 35.545 ;
     RECT  2.304 35.033 29.697 35.573 ;
     RECT  163.116 35.545 163.746 35.581 ;
     RECT  163.044 35.581 163.746 35.645 ;
     RECT  30.564 35.195 47.466 35.671 ;
     RECT  16.74 35.573 29.697 35.707 ;
     RECT  30.456 35.671 47.466 35.707 ;
     RECT  0.216 35.323 0.234 35.837 ;
     RECT  16.74 35.707 47.466 35.879 ;
     RECT  30.96 35.879 47.466 35.941 ;
     RECT  48.348 35.401 112.266 35.941 ;
     RECT  113.328 35.159 161.802 35.941 ;
     RECT  2.304 35.573 16.002 35.947 ;
     RECT  30.96 35.941 112.266 36.113 ;
     RECT  37.944 36.113 112.266 36.239 ;
     RECT  113.112 35.941 161.802 36.247 ;
     RECT  113.004 36.247 161.802 36.283 ;
     RECT  163.044 35.645 163.674 36.283 ;
     RECT  37.944 36.239 87.678 36.311 ;
     RECT  2.268 35.947 16.002 36.391 ;
     RECT  16.74 35.879 30.042 36.391 ;
     RECT  113.004 36.283 163.674 36.461 ;
     RECT  88.416 36.239 112.266 36.481 ;
     RECT  113.004 36.461 161.874 36.481 ;
     RECT  2.268 36.391 30.042 36.661 ;
     RECT  30.96 36.113 37.206 36.661 ;
     RECT  163.044 36.461 163.674 36.749 ;
     RECT  2.268 36.661 37.206 36.931 ;
     RECT  163.116 36.749 163.674 36.989 ;
     RECT  38.196 36.311 87.678 37.093 ;
     RECT  88.416 36.481 161.874 37.093 ;
     RECT  163.584 36.989 163.674 37.277 ;
     RECT  38.196 37.093 161.874 37.355 ;
     RECT  2.268 36.931 37.422 37.363 ;
     RECT  38.196 37.355 107.514 37.363 ;
     RECT  0.216 37.243 0.234 37.373 ;
     RECT  2.268 37.363 107.514 37.733 ;
     RECT  108.396 37.355 161.874 37.741 ;
     RECT  108.396 37.741 162.414 38.011 ;
     RECT  163.62 37.277 163.674 38.011 ;
     RECT  108.396 38.011 163.674 38.092 ;
     RECT  108.396 38.092 163.71 38.137 ;
     RECT  2.268 37.733 107.406 38.173 ;
     RECT  2.232 38.173 107.406 38.201 ;
     RECT  108.396 38.137 163.998 38.245 ;
     RECT  2.232 38.201 107.154 38.273 ;
     RECT  2.268 38.273 107.154 38.399 ;
     RECT  0.54 38.173 0.558 38.515 ;
     RECT  0.252 38.515 0.558 38.525 ;
     RECT  22.68 38.399 107.154 38.543 ;
     RECT  108.144 38.245 163.998 38.621 ;
     RECT  163.584 38.621 163.998 38.777 ;
     RECT  108.144 38.621 162.486 38.813 ;
     RECT  2.268 38.399 21.834 38.861 ;
     RECT  103.176 38.543 107.154 38.947 ;
     RECT  108.144 38.813 113.31 38.947 ;
     RECT  114.084 38.813 162.486 38.975 ;
     RECT  114.084 38.975 161.658 39.011 ;
     RECT  162.432 38.975 162.486 39.011 ;
     RECT  114.12 39.011 161.658 39.047 ;
     RECT  114.12 39.047 161.586 39.083 ;
     RECT  162.468 39.011 162.486 39.149 ;
     RECT  2.376 38.861 21.834 39.181 ;
     RECT  22.68 38.543 102.258 39.181 ;
     RECT  2.376 39.181 102.258 39.245 ;
     RECT  0.252 38.525 0.27 39.289 ;
     RECT  28.512 39.245 102.258 39.289 ;
     RECT  103.176 38.947 113.31 39.289 ;
     RECT  2.376 39.245 27.738 39.341 ;
     RECT  0.252 39.289 0.558 39.451 ;
     RECT  2.376 39.341 20.826 39.479 ;
     RECT  28.512 39.289 113.31 39.479 ;
     RECT  30.528 39.479 113.31 39.533 ;
     RECT  38.376 39.533 113.31 39.581 ;
     RECT  30.528 39.533 37.35 39.749 ;
     RECT  21.564 39.341 27.738 39.821 ;
     RECT  114.156 39.083 161.586 39.865 ;
     RECT  38.376 39.581 38.934 39.893 ;
     RECT  21.564 39.821 25.11 39.917 ;
     RECT  163.584 38.777 163.926 39.965 ;
     RECT  30.528 39.749 37.098 40.019 ;
     RECT  21.564 39.917 24.786 40.055 ;
     RECT  2.376 39.479 20.79 40.063 ;
     RECT  25.848 39.821 27.738 40.099 ;
     RECT  28.512 39.479 29.697 40.099 ;
     RECT  32.112 40.019 37.098 40.127 ;
     RECT  0.216 39.451 0.558 40.157 ;
     RECT  34.236 40.127 37.098 40.163 ;
     RECT  39.924 39.581 113.31 40.171 ;
     RECT  114.156 39.865 161.766 40.171 ;
     RECT  39.924 40.171 161.874 40.219 ;
     RECT  162.72 39.631 162.738 40.219 ;
     RECT  25.848 40.099 29.697 40.261 ;
     RECT  30.528 40.019 31.374 40.261 ;
     RECT  32.112 40.127 33.246 40.325 ;
     RECT  39.924 40.219 162.738 40.397 ;
     RECT  2.34 40.063 20.79 40.405 ;
     RECT  38.772 39.893 38.934 40.441 ;
     RECT  39.924 40.397 90.162 40.441 ;
     RECT  163.584 39.965 163.638 40.493 ;
     RECT  34.74 40.163 37.098 40.567 ;
     RECT  32.256 40.325 33.246 40.829 ;
     RECT  25.848 40.261 31.374 40.909 ;
     RECT  38.772 40.441 90.162 40.937 ;
     RECT  2.34 40.405 20.97 40.945 ;
     RECT  25.668 40.909 31.374 41.071 ;
     RECT  32.256 40.829 32.994 41.071 ;
     RECT  21.708 40.055 24.786 41.107 ;
     RECT  25.668 41.071 32.994 41.107 ;
     RECT  0.216 40.157 0.234 41.213 ;
     RECT  2.268 40.945 20.97 41.215 ;
     RECT  21.708 41.107 32.994 41.215 ;
     RECT  38.988 40.937 90.162 41.227 ;
     RECT  90.936 40.397 162.738 41.227 ;
     RECT  34.74 40.567 37.89 41.251 ;
     RECT  38.988 41.227 162.738 41.405 ;
     RECT  34.74 41.251 38.214 41.485 ;
     RECT  38.988 41.405 62.097 41.513 ;
     RECT  34.416 41.485 38.214 41.521 ;
     RECT  2.268 41.215 32.994 41.639 ;
     RECT  2.268 41.639 24.426 41.675 ;
     RECT  2.268 41.675 21.078 41.707 ;
     RECT  62.856 41.405 162.738 41.789 ;
     RECT  2.16 41.707 21.078 41.819 ;
     RECT  163.584 40.493 163.602 41.837 ;
     RECT  16.92 41.819 21.078 41.909 ;
     RECT  2.16 41.819 16.182 41.945 ;
     RECT  25.2 41.639 32.994 42.025 ;
     RECT  16.92 41.909 20.934 42.215 ;
     RECT  62.856 41.789 117.45 42.215 ;
     RECT  16.92 42.215 20.466 42.251 ;
     RECT  38.988 41.513 57.258 42.259 ;
     RECT  58.104 41.513 62.097 42.259 ;
     RECT  62.856 42.215 117.342 42.259 ;
     RECT  25.2 42.025 33.462 42.295 ;
     RECT  34.236 41.521 38.214 42.295 ;
     RECT  38.988 42.259 117.342 42.421 ;
     RECT  38.952 42.421 117.342 42.557 ;
     RECT  25.2 42.295 38.214 42.571 ;
     RECT  38.952 42.557 57.33 42.571 ;
     RECT  58.104 42.557 117.342 42.593 ;
     RECT  2.304 41.945 16.182 42.601 ;
     RECT  16.92 42.251 19.998 42.601 ;
     RECT  21.816 41.675 24.297 42.601 ;
     RECT  25.2 42.571 57.33 42.601 ;
     RECT  21.816 42.601 57.33 42.691 ;
     RECT  21.348 42.691 57.33 42.719 ;
     RECT  118.188 41.789 162.738 42.719 ;
     RECT  21.348 42.719 57.294 42.863 ;
     RECT  38.88 42.863 57.294 42.899 ;
     RECT  38.952 42.899 57.294 42.989 ;
     RECT  58.14 42.593 117.342 43.025 ;
     RECT  0.216 42.955 0.234 43.085 ;
     RECT  58.14 43.025 113.346 43.133 ;
     RECT  114.264 43.025 117.342 43.141 ;
     RECT  118.188 42.719 161.946 43.141 ;
     RECT  114.264 43.141 161.946 43.181 ;
     RECT  21.348 42.863 37.998 43.259 ;
     RECT  2.304 42.601 19.998 43.267 ;
     RECT  2.304 43.267 20.358 43.291 ;
     RECT  21.348 43.259 22.878 43.291 ;
     RECT  21.312 43.291 22.878 43.295 ;
     RECT  61.092 43.133 113.346 43.367 ;
     RECT  162.72 42.719 162.738 43.469 ;
     RECT  2.196 43.291 20.358 43.501 ;
     RECT  21.312 43.295 22.662 43.501 ;
     RECT  2.196 43.501 22.662 43.529 ;
     RECT  114.264 43.181 161.73 43.529 ;
     RECT  2.196 43.529 16.182 43.565 ;
     RECT  39.024 42.989 57.294 43.573 ;
     RECT  58.14 43.133 60.318 43.573 ;
     RECT  16.92 43.529 22.662 43.601 ;
     RECT  61.092 43.367 87.246 43.613 ;
     RECT  88.164 43.367 113.346 43.709 ;
     RECT  39.024 43.573 60.318 43.771 ;
     RECT  163.548 42.529 163.566 43.771 ;
     RECT  2.268 43.565 16.182 43.799 ;
     RECT  17.028 43.601 22.662 43.799 ;
     RECT  109.512 43.709 113.346 43.799 ;
     RECT  1.152 43.411 1.17 43.807 ;
     RECT  109.656 43.799 113.346 43.807 ;
     RECT  114.264 43.529 161.694 43.807 ;
     RECT  0.54 43.807 1.17 43.835 ;
     RECT  2.268 43.799 16.038 43.835 ;
     RECT  109.656 43.807 161.694 43.835 ;
     RECT  24.015 43.259 37.998 43.843 ;
     RECT  38.736 43.771 60.318 43.843 ;
     RECT  163.548 43.771 163.638 43.843 ;
     RECT  24.015 43.843 60.318 43.879 ;
     RECT  61.092 43.613 87.21 43.879 ;
     RECT  163.044 43.843 163.638 43.997 ;
     RECT  163.584 43.997 163.638 44.041 ;
     RECT  17.028 43.799 22.518 44.069 ;
     RECT  24.015 43.879 87.21 44.077 ;
     RECT  23.868 44.077 87.21 44.141 ;
     RECT  88.164 43.709 108.774 44.177 ;
     RECT  23.868 44.141 27.774 44.213 ;
     RECT  23.94 44.213 27.774 44.222 ;
     RECT  109.728 43.835 161.694 44.249 ;
     RECT  163.584 44.041 163.674 44.285 ;
     RECT  17.028 44.069 19.386 44.339 ;
     RECT  28.512 44.141 87.21 44.339 ;
     RECT  97.992 44.177 108.774 44.339 ;
     RECT  119.124 44.249 161.694 44.347 ;
     RECT  28.512 44.339 32.49 44.411 ;
     RECT  33.444 44.339 87.21 44.429 ;
     RECT  20.232 44.069 22.518 44.477 ;
     RECT  39.528 44.429 87.21 44.491 ;
     RECT  88.164 44.177 97.254 44.491 ;
     RECT  106.884 44.339 108.774 44.581 ;
     RECT  109.728 44.249 118.35 44.581 ;
     RECT  39.528 44.491 97.254 44.717 ;
     RECT  22.5 44.477 22.518 44.725 ;
     RECT  2.268 43.835 16.002 44.761 ;
     RECT  119.124 44.347 161.766 44.761 ;
     RECT  162.504 44.491 162.522 44.761 ;
     RECT  39.528 44.717 48.042 44.789 ;
     RECT  39.528 44.789 48.006 44.813 ;
     RECT  163.62 44.285 163.674 44.851 ;
     RECT  0.54 43.835 0.558 44.875 ;
     RECT  23.94 44.222 27.738 44.879 ;
     RECT  45.615 44.813 48.006 44.879 ;
     RECT  20.232 44.477 21.69 44.923 ;
     RECT  26.676 44.879 27.738 44.951 ;
     RECT  28.512 44.411 32.31 44.987 ;
     RECT  17.244 44.339 19.386 44.995 ;
     RECT  20.124 44.923 21.69 44.995 ;
     RECT  0.216 44.875 0.558 45.005 ;
     RECT  2.268 44.761 16.038 45.005 ;
     RECT  23.94 44.879 25.902 45.023 ;
     RECT  106.884 44.581 118.35 45.031 ;
     RECT  119.124 44.761 162.522 45.031 ;
     RECT  23.94 45.023 25.83 45.053 ;
     RECT  48.96 44.717 97.254 45.121 ;
     RECT  97.992 44.339 106.038 45.121 ;
     RECT  106.884 45.031 162.522 45.121 ;
     RECT  48.96 45.121 162.522 45.149 ;
     RECT  26.784 44.951 27.738 45.157 ;
     RECT  28.512 44.987 32.238 45.157 ;
     RECT  33.444 44.429 38.754 45.163 ;
     RECT  163.62 44.851 163.71 45.193 ;
     RECT  26.784 45.157 32.238 45.197 ;
     RECT  49.032 45.149 162.522 45.221 ;
     RECT  28.512 45.197 32.238 45.257 ;
     RECT  39.528 44.813 44.838 45.257 ;
     RECT  50.328 45.221 162.522 45.257 ;
     RECT  17.244 44.995 21.69 45.265 ;
     RECT  33.084 45.163 38.754 45.265 ;
     RECT  28.584 45.257 32.238 45.293 ;
     RECT  16.74 45.265 21.69 45.301 ;
     RECT  22.5 44.725 22.662 45.301 ;
     RECT  16.74 45.301 22.662 45.419 ;
     RECT  23.94 45.053 25.542 45.419 ;
     RECT  45.615 44.879 47.898 45.419 ;
     RECT  49.032 45.221 49.59 45.455 ;
     RECT  16.74 45.419 22.014 45.491 ;
     RECT  30.744 45.293 32.238 45.491 ;
     RECT  23.94 45.419 25.506 45.527 ;
     RECT  33.084 45.265 39.438 45.527 ;
     RECT  40.215 45.257 44.838 45.535 ;
     RECT  163.584 45.193 163.71 45.535 ;
     RECT  30.744 45.491 31.626 45.581 ;
     RECT  40.215 45.535 44.874 45.581 ;
     RECT  23.94 45.527 25.434 45.595 ;
     RECT  30.744 45.581 30.978 45.599 ;
     RECT  33.084 45.527 36.486 45.599 ;
     RECT  37.224 45.527 39.438 45.599 ;
     RECT  49.212 45.455 49.59 45.599 ;
     RECT  23.616 45.595 25.434 45.689 ;
     RECT  26.784 45.197 27.594 45.689 ;
     RECT  28.584 45.293 30.006 45.689 ;
     RECT  34.524 45.599 36.486 45.689 ;
     RECT  37.296 45.599 39.438 45.689 ;
     RECT  50.58 45.257 162.486 45.689 ;
     RECT  0.54 45.005 0.558 45.697 ;
     RECT  28.584 45.689 29.79 45.725 ;
     RECT  30.744 45.599 30.87 45.725 ;
     RECT  33.084 45.599 33.678 45.725 ;
     RECT  34.524 45.689 35.586 45.725 ;
     RECT  37.62 45.689 39.438 45.725 ;
     RECT  40.215 45.581 44.838 45.725 ;
     RECT  45.615 45.419 47.754 45.725 ;
     RECT  85.032 45.689 162.486 45.725 ;
     RECT  33.084 45.725 33.57 45.733 ;
     RECT  28.584 45.725 29.754 45.761 ;
     RECT  32.364 45.733 33.57 45.761 ;
     RECT  40.215 45.725 43.47 45.761 ;
     RECT  96.084 45.725 110.754 45.761 ;
     RECT  23.616 45.689 25.398 45.769 ;
     RECT  2.268 45.005 15.966 45.797 ;
     RECT  16.74 45.491 21.69 45.797 ;
     RECT  29.016 45.761 29.754 45.797 ;
     RECT  33.48 45.761 33.57 45.797 ;
     RECT  34.524 45.725 35.298 45.797 ;
     RECT  38.232 45.725 38.502 45.797 ;
     RECT  39.24 45.725 39.438 45.797 ;
     RECT  45.615 45.725 46.386 45.797 ;
     RECT  104.94 45.761 110.754 45.797 ;
     RECT  23.508 45.769 25.398 45.833 ;
     RECT  26.784 45.689 27.054 45.833 ;
     RECT  33.552 45.797 33.57 45.833 ;
     RECT  42.804 45.761 43.47 45.833 ;
     RECT  44.208 45.725 44.838 45.833 ;
     RECT  49.32 45.599 49.59 45.833 ;
     RECT  111.78 45.725 162.486 45.833 ;
     RECT  2.268 45.797 15.75 45.869 ;
     RECT  23.508 45.833 24.75 45.869 ;
     RECT  29.016 45.797 29.697 45.869 ;
     RECT  30.744 45.725 30.762 45.869 ;
     RECT  32.364 45.761 32.382 45.869 ;
     RECT  38.376 45.797 38.466 45.869 ;
     RECT  47.52 45.725 47.754 45.869 ;
     RECT  50.58 45.689 68.058 45.869 ;
     RECT  118.692 45.833 120.222 45.869 ;
     RECT  16.74 45.797 18.897 45.931 ;
     RECT  2.304 45.869 15.75 45.959 ;
     RECT  23.76 45.869 24.642 45.959 ;
     RECT  34.524 45.797 35.097 45.959 ;
     RECT  39.348 45.797 39.438 45.959 ;
     RECT  42.804 45.833 43.038 45.959 ;
     RECT  47.736 45.869 47.754 45.959 ;
     RECT  54.252 45.869 68.058 45.959 ;
     RECT  68.832 45.689 84.186 45.959 ;
     RECT  104.94 45.797 110.697 45.959 ;
     RECT  111.78 45.833 117.918 45.959 ;
     RECT  118.692 45.869 119.286 45.959 ;
     RECT  120.024 45.869 120.222 45.959 ;
     RECT  121.14 45.833 162.486 45.959 ;
     RECT  13.215 45.959 15.606 45.995 ;
     RECT  19.728 45.797 21.69 45.995 ;
     RECT  45.615 45.797 46.278 45.995 ;
     RECT  49.572 45.833 49.59 45.995 ;
     RECT  54.252 45.959 66.474 45.995 ;
     RECT  68.832 45.959 84.078 45.995 ;
     RECT  85.032 45.725 95.346 45.995 ;
     RECT  104.976 45.959 110.697 45.995 ;
     RECT  111.78 45.959 117.774 45.995 ;
     RECT  119.016 45.959 119.286 45.995 ;
     RECT  122.796 45.959 156.978 45.995 ;
     RECT  111.852 45.995 117.198 46.013 ;
     RECT  2.304 45.959 11.862 46.031 ;
     RECT  38.376 45.869 38.394 46.031 ;
     RECT  40.215 45.761 41.994 46.031 ;
     RECT  42.804 45.959 43.002 46.031 ;
     RECT  44.316 45.833 44.838 46.031 ;
     RECT  54.252 45.995 62.097 46.031 ;
     RECT  74.448 45.995 84.078 46.031 ;
     RECT  85.032 45.995 92.682 46.031 ;
     RECT  93.456 45.995 95.094 46.031 ;
     RECT  96.084 45.761 104.202 46.031 ;
     RECT  104.976 45.995 105.498 46.031 ;
     RECT  106.38 45.995 110.697 46.031 ;
     RECT  111.852 46.013 114.822 46.031 ;
     RECT  92.664 46.031 92.682 46.061 ;
     RECT  93.492 46.031 95.094 46.061 ;
     RECT  50.58 45.869 53.046 46.067 ;
     RECT  54.324 46.031 62.097 46.067 ;
     RECT  86.148 46.031 91.89 46.067 ;
     RECT  93.528 46.061 95.094 46.067 ;
     RECT  96.084 46.031 98.658 46.067 ;
     RECT  99.576 46.031 104.202 46.067 ;
     RECT  115.815 46.013 117.198 46.067 ;
     RECT  2.304 46.031 11.718 46.103 ;
     RECT  42.804 46.031 42.822 46.103 ;
     RECT  44.316 46.031 44.334 46.103 ;
     RECT  54.324 46.067 59.166 46.103 ;
     RECT  60.12 46.067 60.462 46.103 ;
     RECT  85.032 46.031 85.122 46.103 ;
     RECT  86.436 46.067 89.097 46.103 ;
     RECT  96.228 46.067 98.658 46.103 ;
     RECT  106.38 46.031 106.398 46.103 ;
     RECT  107.64 46.031 110.697 46.103 ;
     RECT  112.284 46.031 113.958 46.103 ;
     RECT  114.732 46.031 114.822 46.103 ;
     RECT  117.18 46.067 117.198 46.103 ;
     RECT  56.415 46.103 59.166 46.109 ;
     RECT  60.3 46.103 60.318 46.109 ;
     RECT  99.576 46.067 103.266 46.109 ;
     RECT  108.288 46.103 110.697 46.109 ;
     RECT  162.468 45.959 162.486 46.123 ;
     RECT  2.304 46.103 11.682 46.139 ;
     RECT  36.468 45.689 36.486 46.139 ;
     RECT  54.324 46.103 55.602 46.139 ;
     RECT  57.672 46.109 59.166 46.139 ;
     RECT  61.272 46.067 62.097 46.139 ;
     RECT  62.82 45.995 66.474 46.139 ;
     RECT  67.215 45.959 67.842 46.139 ;
     RECT  74.448 46.031 82.494 46.139 ;
     RECT  88.2 46.103 89.097 46.139 ;
     RECT  89.892 46.067 91.098 46.139 ;
     RECT  91.872 46.067 91.89 46.139 ;
     RECT  99.615 46.109 103.266 46.139 ;
     RECT  104.004 46.067 104.202 46.139 ;
     RECT  108.324 46.109 110.697 46.139 ;
     RECT  112.752 46.103 113.886 46.139 ;
     RECT  115.815 46.067 116.406 46.139 ;
     RECT  119.16 45.995 119.286 46.139 ;
     RECT  120.204 45.959 120.222 46.139 ;
     RECT  122.796 45.995 156.906 46.139 ;
     RECT  157.716 45.959 161.622 46.139 ;
     RECT  162.468 46.123 162.522 46.139 ;
     RECT  41.472 46.031 41.994 46.157 ;
     RECT  93.708 46.067 95.094 46.157 ;
     RECT  96.408 46.103 98.658 46.157 ;
     RECT  99.615 46.139 101.862 46.157 ;
     RECT  16.524 45.931 18.897 46.187 ;
     RECT  29.415 45.869 29.697 46.187 ;
     RECT  34.815 45.959 35.097 46.187 ;
     RECT  40.215 46.031 40.497 46.187 ;
     RECT  45.615 45.995 45.897 46.187 ;
     RECT  56.415 46.109 56.697 46.187 ;
     RECT  61.815 46.139 62.097 46.187 ;
     RECT  67.215 46.139 67.497 46.187 ;
     RECT  88.776 46.139 89.097 46.187 ;
     RECT  94.032 46.157 94.497 46.187 ;
     RECT  108.936 46.139 110.697 46.187 ;
     RECT  115.815 46.139 116.097 46.187 ;
     RECT  0.54 45.697 1.17 46.205 ;
     RECT  19.908 45.995 21.69 46.219 ;
     RECT  2.304 46.139 10.602 46.229 ;
     RECT  13.215 45.995 15.282 46.229 ;
     RECT  16.524 46.187 18.705 46.229 ;
     RECT  19.908 46.219 21.978 46.229 ;
     RECT  24.015 45.959 24.642 46.229 ;
     RECT  50.58 46.067 52.074 46.229 ;
     RECT  54.648 46.139 55.602 46.229 ;
     RECT  64.404 46.139 66.474 46.229 ;
     RECT  69.372 45.995 71.046 46.229 ;
     RECT  80.712 46.139 82.386 46.229 ;
     RECT  83.268 46.031 84.078 46.229 ;
     RECT  85.104 46.103 85.122 46.229 ;
     RECT  96.408 46.157 97.974 46.229 ;
     RECT  99.615 46.157 101.466 46.229 ;
     RECT  102.672 46.139 103.266 46.229 ;
     RECT  105.015 46.031 105.498 46.229 ;
     RECT  112.752 46.139 112.77 46.229 ;
     RECT  121.215 45.959 122.058 46.229 ;
     RECT  122.796 46.139 133.974 46.229 ;
     RECT  134.892 46.139 143.514 46.229 ;
     RECT  144.432 46.139 156.906 46.229 ;
     RECT  162.504 46.139 162.522 46.229 ;
     RECT  157.716 46.139 161.442 46.253 ;
     RECT  2.304 46.229 3.438 46.265 ;
     RECT  4.212 46.229 10.602 46.265 ;
     RECT  14.4 46.229 14.886 46.265 ;
     RECT  16.524 46.229 17.766 46.265 ;
     RECT  20.088 46.229 21.978 46.265 ;
     RECT  50.58 46.229 51.105 46.265 ;
     RECT  51.84 46.229 52.074 46.265 ;
     RECT  58.464 46.139 58.734 46.265 ;
     RECT  74.448 46.139 79.902 46.265 ;
     RECT  80.712 46.229 82.242 46.265 ;
     RECT  124.308 46.229 124.326 46.265 ;
     RECT  125.172 46.229 133.974 46.265 ;
     RECT  134.892 46.229 137.505 46.265 ;
     RECT  138.528 46.229 140.67 46.265 ;
     RECT  141.444 46.229 143.154 46.265 ;
     RECT  145.872 46.229 156.726 46.265 ;
     RECT  4.212 46.265 4.986 46.301 ;
     RECT  5.94 46.265 10.602 46.301 ;
     RECT  11.376 46.139 11.682 46.301 ;
     RECT  20.124 46.265 21.402 46.301 ;
     RECT  54.648 46.229 54.666 46.301 ;
     RECT  58.5 46.265 58.734 46.301 ;
     RECT  64.98 46.229 66.474 46.301 ;
     RECT  72 45.995 73.602 46.301 ;
     RECT  75.708 46.265 79.902 46.301 ;
     RECT  96.408 46.229 96.426 46.301 ;
     RECT  97.452 46.229 97.47 46.301 ;
     RECT  108.936 46.187 110.505 46.301 ;
     RECT  125.964 46.265 126.954 46.301 ;
     RECT  129.636 46.265 132.966 46.301 ;
     RECT  138.528 46.265 138.942 46.301 ;
     RECT  141.516 46.265 143.154 46.301 ;
     RECT  147.132 46.265 156.726 46.301 ;
     RECT  17.244 46.265 17.262 46.337 ;
     RECT  20.124 46.301 21.366 46.337 ;
     RECT  52.056 46.265 52.074 46.337 ;
     RECT  74.736 46.265 74.79 46.337 ;
     RECT  79.416 46.301 79.794 46.337 ;
     RECT  80.712 46.265 81.882 46.337 ;
     RECT  99.615 46.229 100.854 46.337 ;
     RECT  108.936 46.301 109.458 46.337 ;
     RECT  129.996 46.301 132.822 46.337 ;
     RECT  139.716 46.265 140.454 46.337 ;
     RECT  147.132 46.301 153.774 46.337 ;
     RECT  160.02 46.253 161.442 46.337 ;
     RECT  0.252 46.237 0.27 46.345 ;
     RECT  2.304 46.265 3.402 46.373 ;
     RECT  10.584 46.301 10.602 46.373 ;
     RECT  14.4 46.265 14.814 46.373 ;
     RECT  18.576 46.229 18.705 46.373 ;
     RECT  53.028 46.067 53.046 46.373 ;
     RECT  66.132 46.301 66.474 46.373 ;
     RECT  72.18 46.301 73.602 46.373 ;
     RECT  75.708 46.301 78.426 46.373 ;
     RECT  79.776 46.337 79.794 46.373 ;
     RECT  80.712 46.337 81.45 46.373 ;
     RECT  88.776 46.187 88.905 46.373 ;
     RECT  104.184 46.139 104.202 46.373 ;
     RECT  121.215 46.229 121.59 46.373 ;
     RECT  129.996 46.337 132.39 46.373 ;
     RECT  133.92 46.265 133.938 46.373 ;
     RECT  134.892 46.265 136.242 46.373 ;
     RECT  141.516 46.301 142.038 46.373 ;
     RECT  142.815 46.301 143.154 46.373 ;
     RECT  145.944 46.265 145.962 46.373 ;
     RECT  153.54 46.337 153.774 46.373 ;
     RECT  156.708 46.301 156.726 46.373 ;
     RECT  2.304 46.373 3.258 46.409 ;
     RECT  4.392 46.301 4.986 46.409 ;
     RECT  7.632 46.301 9.342 46.409 ;
     RECT  14.58 46.373 14.598 46.409 ;
     RECT  20.772 46.337 21.366 46.409 ;
     RECT  58.716 46.301 58.734 46.409 ;
     RECT  62.82 46.139 63.018 46.409 ;
     RECT  72.615 46.373 73.602 46.409 ;
     RECT  74.772 46.337 74.79 46.409 ;
     RECT  75.708 46.373 78.105 46.409 ;
     RECT  89.892 46.139 90.414 46.409 ;
     RECT  103.104 46.229 103.23 46.409 ;
     RECT  123.552 46.229 123.57 46.409 ;
     RECT  129.996 46.373 130.446 46.409 ;
     RECT  132.015 46.373 132.39 46.409 ;
     RECT  135.396 46.373 136.242 46.409 ;
     RECT  138.924 46.301 138.942 46.409 ;
     RECT  140.436 46.337 140.454 46.409 ;
     RECT  141.516 46.373 141.534 46.409 ;
     RECT  147.132 46.337 152.622 46.409 ;
     RECT  153.54 46.373 153.705 46.409 ;
     RECT  154.512 46.301 155.034 46.409 ;
     RECT  157.716 46.253 159.105 46.409 ;
     RECT  160.236 46.337 161.442 46.409 ;
     RECT  7.632 46.409 8.946 46.457 ;
     RECT  13.215 46.229 13.305 46.457 ;
     RECT  18.615 46.373 18.705 46.457 ;
     RECT  24.015 46.229 24.105 46.457 ;
     RECT  29.415 46.187 29.505 46.457 ;
     RECT  34.815 46.187 34.905 46.457 ;
     RECT  40.215 46.187 40.305 46.457 ;
     RECT  45.615 46.187 45.705 46.457 ;
     RECT  51.015 46.265 51.105 46.457 ;
     RECT  56.415 46.187 56.505 46.457 ;
     RECT  61.815 46.187 61.905 46.457 ;
     RECT  67.215 46.187 67.305 46.457 ;
     RECT  72.615 46.409 72.705 46.457 ;
     RECT  76.392 46.409 78.105 46.457 ;
     RECT  83.415 46.229 83.505 46.457 ;
     RECT  88.815 46.373 88.905 46.457 ;
     RECT  94.032 46.187 94.305 46.457 ;
     RECT  99.615 46.337 100.422 46.457 ;
     RECT  105.015 46.229 105.462 46.457 ;
     RECT  110.415 46.301 110.505 46.457 ;
     RECT  115.815 46.187 115.905 46.457 ;
     RECT  121.215 46.373 121.305 46.457 ;
     RECT  126.615 46.301 126.705 46.457 ;
     RECT  132.015 46.409 132.105 46.457 ;
     RECT  137.415 46.265 137.505 46.457 ;
     RECT  142.815 46.373 142.905 46.457 ;
     RECT  148.215 46.409 148.554 46.457 ;
     RECT  153.576 46.409 153.705 46.457 ;
     RECT  158.58 46.409 159.105 46.457 ;
     RECT  5.94 46.301 6.57 46.499 ;
     RECT  8.532 46.457 8.946 46.499 ;
     RECT  62.82 46.409 62.946 46.499 ;
     RECT  66.384 46.373 66.474 46.499 ;
     RECT  69.948 46.229 69.966 46.499 ;
     RECT  70.74 46.229 71.046 46.499 ;
     RECT  73.584 46.409 73.602 46.499 ;
     RECT  76.392 46.457 77.454 46.499 ;
     RECT  89.892 46.409 89.91 46.499 ;
     RECT  105.444 46.457 105.462 46.499 ;
     RECT  135.396 46.409 135.81 46.499 ;
     RECT  148.536 46.457 148.554 46.499 ;
     RECT  151.632 46.409 152.622 46.499 ;
     RECT  153.576 46.457 153.594 46.499 ;
     RECT  154.512 46.409 154.602 46.499 ;
     RECT  160.416 46.409 161.442 46.499 ;
     RECT  64.98 46.301 64.998 46.535 ;
     RECT  71.028 46.499 71.046 46.535 ;
     RECT  76.896 46.499 77.346 46.535 ;
     RECT  94.032 46.457 94.05 46.535 ;
     RECT  103.212 46.409 103.23 46.535 ;
     RECT  157.716 46.409 157.734 46.535 ;
     RECT  158.58 46.457 158.598 46.535 ;
     RECT  163.584 45.535 163.746 46.535 ;
     RECT  2.304 46.409 2.862 46.541 ;
     RECT  62.928 46.499 62.946 46.571 ;
     RECT  66.456 46.499 66.474 46.571 ;
     RECT  100.404 46.457 100.422 46.571 ;
     RECT  108.936 46.337 108.954 46.571 ;
     RECT  149.652 46.409 150.498 46.571 ;
     RECT  154.584 46.499 154.602 46.571 ;
     RECT  2.844 46.541 2.862 46.607 ;
     RECT  7.632 46.457 7.65 46.607 ;
     RECT  151.632 46.499 151.65 46.685 ;
     RECT  0.216 46.345 0.27 46.829 ;
     RECT  0.252 46.829 0.27 47.165 ;
     RECT  163.584 46.535 163.71 47.213 ;
     RECT  1.152 46.205 1.17 47.501 ;
     RECT  163.584 47.213 163.602 47.501 ;
    LAYER M4 ;
     RECT  0.156 1.152 0.317 47.496 ;
     RECT  0.317 1.152 0.569 21.24 ;
     RECT  0.317 22.224 1.181 47.496 ;
     RECT  0.569 1.152 1.757 16.824 ;
     RECT  0.569 18.384 2.252 21.24 ;
     RECT  1.181 22.224 2.252 46.536 ;
     RECT  1.757 1.488 2.333 16.824 ;
     RECT  2.252 18.384 2.333 46.536 ;
     RECT  2.333 18.384 2.365 46.452 ;
     RECT  2.333 1.824 2.408 16.824 ;
     RECT  2.365 18.144 2.408 46.452 ;
     RECT  2.408 1.824 2.512 46.452 ;
     RECT  2.512 1.824 2.585 46.182 ;
     RECT  2.585 2.256 2.704 46.182 ;
     RECT  2.704 8.496 3.443 37.608 ;
     RECT  2.704 39.072 3.701 45.96 ;
     RECT  3.443 9.12 3.841 37.608 ;
     RECT  3.701 39.072 3.841 45.912 ;
     RECT  2.704 2.256 4.201 7.416 ;
     RECT  4.201 2.256 4.493 7.896 ;
     RECT  3.841 9.12 4.709 45.912 ;
     RECT  4.493 2.256 5.033 7.464 ;
     RECT  4.709 9.168 5.321 45.912 ;
     RECT  5.033 2.544 5.497 7.464 ;
     RECT  5.497 2.544 5.501 7.848 ;
     RECT  5.321 9.936 5.692 45.912 ;
     RECT  5.501 2.832 6.181 7.848 ;
     RECT  5.692 9.936 6.325 43.608 ;
     RECT  6.181 2.832 6.469 7.992 ;
     RECT  6.469 2.64 6.524 7.992 ;
     RECT  6.325 9.12 6.565 43.608 ;
     RECT  6.524 2.256 6.577 7.992 ;
     RECT  6.565 8.976 6.577 43.608 ;
     RECT  6.577 2.256 6.611 43.608 ;
     RECT  6.611 2.64 6.833 43.608 ;
     RECT  5.692 44.88 6.901 45.912 ;
     RECT  6.833 39.744 7.513 43.608 ;
     RECT  6.901 44.736 7.513 46.2 ;
     RECT  6.833 2.64 7.808 38.712 ;
     RECT  7.513 39.744 7.808 46.2 ;
     RECT  7.808 2.148 7.912 46.452 ;
     RECT  7.912 2.418 8.104 46.182 ;
     RECT  8.104 6.288 8.381 45.576 ;
     RECT  8.381 6.288 8.435 23.928 ;
     RECT  8.435 10.992 8.531 23.928 ;
     RECT  8.381 25.056 8.885 45.576 ;
     RECT  8.885 41.088 8.921 45.576 ;
     RECT  8.921 41.184 8.957 45.576 ;
     RECT  8.435 6.288 9.065 9.864 ;
     RECT  8.531 10.992 9.065 23.88 ;
     RECT  8.104 2.64 9.133 4.776 ;
     RECT  8.957 44.544 9.205 45.576 ;
     RECT  9.065 18.192 9.209 23.88 ;
     RECT  9.209 18.24 9.281 23.88 ;
     RECT  9.065 10.992 9.317 17.064 ;
     RECT  9.065 6.288 9.461 9 ;
     RECT  9.205 44.544 9.533 45.624 ;
     RECT  9.281 18.72 9.569 23.88 ;
     RECT  9.317 10.992 9.601 15.624 ;
     RECT  9.601 10.848 9.637 15.624 ;
     RECT  9.569 20.736 9.673 23.88 ;
     RECT  8.885 25.056 9.673 39.912 ;
     RECT  9.637 10.224 9.785 15.624 ;
     RECT  8.957 41.184 9.889 43.56 ;
     RECT  9.461 6.288 9.925 7.848 ;
     RECT  9.533 44.544 10.037 45.528 ;
     RECT  9.673 20.736 10.115 39.912 ;
     RECT  9.785 10.848 10.145 15.624 ;
     RECT  10.115 20.736 10.145 39.048 ;
     RECT  9.317 16.848 10.213 17.064 ;
     RECT  10.145 20.736 10.289 38.712 ;
     RECT  10.289 20.736 10.361 25.128 ;
     RECT  9.925 6.144 10.433 7.848 ;
     RECT  10.361 24.816 10.541 25.128 ;
     RECT  10.037 44.592 10.541 45.528 ;
     RECT  9.889 41.04 10.549 43.56 ;
     RECT  9.461 8.976 10.573 9 ;
     RECT  10.145 10.848 10.577 15.384 ;
     RECT  9.569 18.72 10.645 19.416 ;
     RECT  10.361 20.736 10.645 23.784 ;
     RECT  10.577 10.848 10.685 15.336 ;
     RECT  10.541 25.104 10.721 25.128 ;
     RECT  10.213 16.848 10.748 17.736 ;
     RECT  9.133 2.592 10.825 4.776 ;
     RECT  10.573 8.88 10.901 9 ;
     RECT  10.289 26.16 10.973 38.712 ;
     RECT  10.645 18.72 11.045 23.784 ;
     RECT  10.973 30.048 11.075 38.712 ;
     RECT  10.549 40.368 11.077 43.56 ;
     RECT  10.748 16.8 11.081 17.736 ;
     RECT  11.075 30.048 11.081 37.656 ;
     RECT  11.081 16.8 11.113 17.112 ;
     RECT  10.433 6.144 11.173 7.656 ;
     RECT  10.825 2.544 11.269 4.776 ;
     RECT  11.173 6.048 11.269 7.656 ;
     RECT  11.269 2.544 11.356 7.656 ;
     RECT  10.541 45.36 11.513 45.528 ;
     RECT  10.973 26.16 11.549 28.776 ;
     RECT  11.081 30.096 11.585 37.656 ;
     RECT  11.113 16.56 11.657 17.112 ;
     RECT  11.513 45.456 11.693 45.528 ;
     RECT  11.356 6 11.729 7.656 ;
     RECT  11.077 40.368 11.797 44.328 ;
     RECT  11.729 6 11.939 7.512 ;
     RECT  11.075 38.688 11.941 38.712 ;
     RECT  11.797 39.744 11.941 44.328 ;
     RECT  10.685 12.576 12.035 14.712 ;
     RECT  11.693 45.504 12.053 45.528 ;
     RECT  10.901 8.976 12.085 9 ;
     RECT  11.045 19.92 12.161 23.784 ;
     RECT  12.161 22.656 12.197 23.784 ;
     RECT  10.685 10.848 12.409 11.448 ;
     RECT  11.356 2.544 12.517 4.776 ;
     RECT  11.939 6 12.517 6.168 ;
     RECT  11.585 30.912 12.553 37.656 ;
     RECT  12.409 10.848 12.661 11.496 ;
     RECT  12.035 12.576 12.661 13.08 ;
     RECT  12.661 10.848 12.757 13.08 ;
     RECT  12.757 10.752 12.769 13.08 ;
     RECT  11.549 26.208 12.769 28.776 ;
     RECT  12.769 26.208 12.913 28.824 ;
     RECT  11.045 18.72 12.949 18.744 ;
     RECT  12.035 14.208 13.021 14.712 ;
     RECT  13.021 14.208 13.052 15.384 ;
     RECT  11.657 16.896 13.052 17.112 ;
     RECT  12.769 10.32 13.057 13.08 ;
     RECT  13.052 14.208 13.057 17.112 ;
     RECT  11.939 7.488 13.093 7.512 ;
     RECT  13.057 10.32 13.093 17.112 ;
     RECT  12.949 18.096 13.093 18.744 ;
     RECT  12.085 8.736 13.129 9 ;
     RECT  12.913 25.68 13.165 28.824 ;
     RECT  12.517 2.544 13.208 6.168 ;
     RECT  13.093 7.488 13.208 7.656 ;
     RECT  13.129 8.736 13.208 9.288 ;
     RECT  13.093 10.32 13.208 18.744 ;
     RECT  12.161 19.92 13.208 21.528 ;
     RECT  12.197 22.656 13.208 23.352 ;
     RECT  13.165 25.68 13.208 29.64 ;
     RECT  12.553 30.864 13.208 37.656 ;
     RECT  11.941 38.688 13.208 44.328 ;
     RECT  13.208 2.148 13.312 46.452 ;
     RECT  13.312 2.418 13.504 46.182 ;
     RECT  13.504 6 13.619 10.056 ;
     RECT  13.504 26.016 13.667 40.584 ;
     RECT  13.504 11.376 13.817 18.744 ;
     RECT  13.667 26.016 13.889 28.92 ;
     RECT  13.817 12.96 13.997 18.744 ;
     RECT  13.504 19.968 13.997 21.672 ;
     RECT  13.667 30.24 14.069 40.584 ;
     RECT  14.069 32.208 14.105 40.584 ;
     RECT  13.889 26.736 14.141 28.92 ;
     RECT  14.141 26.736 14.284 28.776 ;
     RECT  13.817 11.376 14.321 11.976 ;
     RECT  13.997 13.632 14.435 18.744 ;
     RECT  14.069 30.24 14.465 30.984 ;
     RECT  13.504 2.64 14.497 4.776 ;
     RECT  14.321 11.424 14.531 11.976 ;
     RECT  13.504 44.4 14.533 45.48 ;
     RECT  14.284 26.784 14.537 28.776 ;
     RECT  14.537 26.784 14.573 28.296 ;
     RECT  14.435 14.832 14.579 18.744 ;
     RECT  13.504 23.328 14.641 23.88 ;
     RECT  13.504 42.768 14.641 43.368 ;
     RECT  14.533 44.4 14.641 45.96 ;
     RECT  14.641 23.136 14.677 23.88 ;
     RECT  14.641 42.768 14.681 45.96 ;
     RECT  14.105 38.16 14.717 40.584 ;
     RECT  13.619 6 14.785 9 ;
     RECT  13.997 20.064 14.785 21.672 ;
     RECT  14.497 2.448 14.861 4.776 ;
     RECT  14.435 13.632 14.861 13.848 ;
     RECT  14.785 5.808 14.893 9 ;
     RECT  13.619 10.032 14.893 10.056 ;
     RECT  14.105 32.208 14.897 37.032 ;
     RECT  14.785 20.064 14.929 21.96 ;
     RECT  14.681 42.768 14.969 45.528 ;
     RECT  14.929 20.064 15.001 22.008 ;
     RECT  14.677 23.136 15.001 24.648 ;
     RECT  14.969 43.296 15.005 45.528 ;
     RECT  14.579 16.512 15.041 18.744 ;
     RECT  14.897 32.208 15.041 34.488 ;
     RECT  14.893 5.808 15.073 10.056 ;
     RECT  15.041 33.024 15.077 34.488 ;
     RECT  15.005 43.296 15.077 45.144 ;
     RECT  14.573 26.784 15.113 27.48 ;
     RECT  15.077 44.976 15.113 45.144 ;
     RECT  15.073 5.808 15.181 10.296 ;
     RECT  14.465 30.816 15.289 30.984 ;
     RECT  14.861 2.544 15.325 4.776 ;
     RECT  15.181 5.808 15.325 10.392 ;
     RECT  14.897 35.664 15.349 37.032 ;
     RECT  14.717 38.16 15.349 39.288 ;
     RECT  15.325 2.544 15.361 10.392 ;
     RECT  14.531 11.424 15.361 11.688 ;
     RECT  15.001 20.064 15.437 24.648 ;
     RECT  15.349 35.664 15.545 39.288 ;
     RECT  15.041 18.432 15.613 18.744 ;
     RECT  15.437 20.064 15.613 22.2 ;
     RECT  15.037 12.768 15.617 12.792 ;
     RECT  15.289 30.816 15.793 31.512 ;
     RECT  15.437 23.328 15.797 24.648 ;
     RECT  13.504 41.712 15.833 41.736 ;
     RECT  14.579 14.832 15.901 15.288 ;
     RECT  15.793 30.624 15.937 31.512 ;
     RECT  15.545 35.664 16.013 38.424 ;
     RECT  14.717 40.512 16.021 40.584 ;
     RECT  15.901 14.832 16.049 15.384 ;
     RECT  15.613 18.432 16.049 22.2 ;
     RECT  15.937 30.576 16.081 31.512 ;
     RECT  15.797 23.328 16.085 23.88 ;
     RECT  15.077 43.296 16.093 43.416 ;
     RECT  15.361 2.544 16.121 11.688 ;
     RECT  15.077 33.024 16.121 33.48 ;
     RECT  16.121 5.808 16.157 11.688 ;
     RECT  15.041 16.512 16.157 17.448 ;
     RECT  16.069 25.296 16.157 25.32 ;
     RECT  16.013 37.152 16.265 38.424 ;
     RECT  16.021 40.512 16.265 41.256 ;
     RECT  16.157 5.904 16.373 11.688 ;
     RECT  16.121 33.36 16.46 33.48 ;
     RECT  15.077 34.464 16.46 34.488 ;
     RECT  16.46 33.36 16.501 34.488 ;
     RECT  16.013 35.664 16.501 35.928 ;
     RECT  15.113 44.976 16.501 45 ;
     RECT  16.501 44.976 16.547 45.96 ;
     RECT  16.049 19.584 16.549 22.2 ;
     RECT  16.085 23.328 16.549 23.352 ;
     RECT  16.501 33.36 16.589 35.928 ;
     RECT  16.549 19.584 16.595 23.352 ;
     RECT  16.589 33.456 16.661 35.928 ;
     RECT  15.113 26.832 16.789 27.48 ;
     RECT  16.789 26.832 16.835 28.968 ;
     RECT  16.265 40.512 16.841 41.016 ;
     RECT  16.835 28.272 16.981 28.968 ;
     RECT  16.373 7.392 17.017 11.688 ;
     RECT  16.661 33.552 17.017 35.928 ;
     RECT  16.265 37.152 17.017 37.944 ;
     RECT  14.861 13.824 17.021 13.848 ;
     RECT  16.373 5.904 17.075 6.168 ;
     RECT  16.873 38.928 17.089 38.952 ;
     RECT  17.017 33.552 17.093 37.944 ;
     RECT  16.547 45.6 17.129 45.96 ;
     RECT  16.157 16.944 17.161 17.448 ;
     RECT  17.093 33.552 17.165 36.456 ;
     RECT  16.513 25.632 17.237 25.656 ;
     RECT  17.089 38.928 17.237 39.048 ;
     RECT  17.093 37.44 17.269 37.944 ;
     RECT  17.237 38.928 17.269 38.952 ;
     RECT  16.081 30.096 17.273 31.512 ;
     RECT  17.269 37.44 17.309 38.952 ;
     RECT  17.197 24.528 17.341 24.552 ;
     RECT  16.981 28.272 17.413 29.112 ;
     RECT  17.273 30.96 17.417 31.512 ;
     RECT  17.017 7.392 17.449 11.736 ;
     RECT  17.341 12.72 17.449 12.744 ;
     RECT  17.161 16.8 17.449 17.448 ;
     RECT  16.049 18.432 17.449 18.456 ;
     RECT  17.413 28.272 17.453 29.64 ;
     RECT  17.449 7.392 17.593 12.744 ;
     RECT  16.049 14.832 17.593 15.288 ;
     RECT  16.595 22.8 17.701 23.352 ;
     RECT  17.341 24.384 17.701 24.552 ;
     RECT  17.075 6 17.881 6.168 ;
     RECT  17.593 7.392 17.881 13.704 ;
     RECT  16.841 40.512 17.881 40.584 ;
     RECT  16.595 19.584 17.941 21.528 ;
     RECT  17.701 22.752 17.941 24.552 ;
     RECT  17.941 19.584 17.989 24.552 ;
     RECT  17.129 45.6 17.989 45.624 ;
     RECT  17.165 33.552 18.025 35.448 ;
     RECT  17.881 40.512 18.061 40.92 ;
     RECT  17.449 16.8 18.085 18.456 ;
     RECT  17.989 19.536 18.085 24.552 ;
     RECT  17.521 31.728 18.133 31.944 ;
     RECT  16.121 2.544 18.169 4.776 ;
     RECT  17.881 6 18.169 13.704 ;
     RECT  16.835 26.832 18.181 27.096 ;
     RECT  17.453 28.272 18.181 28.488 ;
     RECT  18.133 31.728 18.325 32.376 ;
     RECT  18.025 33.504 18.325 35.448 ;
     RECT  17.309 37.44 18.373 38.856 ;
     RECT  17.989 45.024 18.529 45.624 ;
     RECT  18.169 2.544 18.608 13.704 ;
     RECT  17.593 14.784 18.608 15.288 ;
     RECT  18.085 16.8 18.608 24.552 ;
     RECT  18.181 26.832 18.608 28.488 ;
     RECT  17.453 29.616 18.608 29.64 ;
     RECT  18.325 31.728 18.608 35.448 ;
     RECT  18.373 37.44 18.608 39.096 ;
     RECT  18.061 40.416 18.608 40.92 ;
     RECT  16.093 43.296 18.608 43.368 ;
     RECT  18.529 45.024 18.608 46.008 ;
     RECT  18.608 2.148 18.712 46.452 ;
     RECT  18.712 2.418 18.904 46.182 ;
     RECT  18.904 31.728 19.109 33.384 ;
     RECT  18.904 34.464 19.427 37.992 ;
     RECT  18.904 40.56 19.427 41.016 ;
     RECT  19.427 40.752 19.475 41.016 ;
     RECT  18.904 5.808 19.757 23.352 ;
     RECT  19.757 5.808 19.793 11.784 ;
     RECT  19.757 12.768 19.829 23.352 ;
     RECT  19.829 13.056 19.865 23.352 ;
     RECT  19.109 32.208 19.865 33.384 ;
     RECT  19.475 40.848 19.868 41.016 ;
     RECT  18.904 24.384 19.909 24.504 ;
     RECT  19.427 35.712 19.933 37.992 ;
     RECT  18.904 39.216 19.933 39.288 ;
     RECT  18.904 42.768 19.937 43.896 ;
     RECT  18.904 25.68 19.955 28.488 ;
     RECT  19.868 40.848 19.955 41.256 ;
     RECT  19.937 43.152 19.973 43.896 ;
     RECT  19.933 35.712 20.003 39.288 ;
     RECT  20.003 38.16 20.017 39.288 ;
     RECT  18.904 2.64 20.245 4.776 ;
     RECT  19.793 5.808 20.245 11.4 ;
     RECT  19.427 34.464 20.424 34.488 ;
     RECT  20.003 35.712 20.477 37.128 ;
     RECT  19.865 13.056 20.483 21.816 ;
     RECT  20.424 34.176 20.485 34.488 ;
     RECT  20.477 35.712 20.485 37.032 ;
     RECT  20.017 39.216 20.545 39.288 ;
     RECT  19.955 40.848 20.545 40.872 ;
     RECT  19.955 26.928 20.617 28.488 ;
     RECT  20.245 2.64 20.761 11.4 ;
     RECT  20.483 13.056 20.869 20.424 ;
     RECT  20.761 2.304 20.905 11.4 ;
     RECT  20.545 39.216 20.915 40.872 ;
     RECT  19.909 24.384 20.945 24.648 ;
     RECT  20.915 39.216 20.956 39.336 ;
     RECT  20.905 2.304 21.049 11.544 ;
     RECT  20.869 12.768 21.049 20.424 ;
     RECT  19.865 32.208 21.049 32.856 ;
     RECT  20.915 40.608 21.049 40.872 ;
     RECT  20.617 26.928 21.085 28.536 ;
     RECT  20.017 38.16 21.125 38.184 ;
     RECT  20.483 21.648 21.193 21.816 ;
     RECT  19.865 22.8 21.193 23.352 ;
     RECT  21.049 2.304 21.197 20.424 ;
     RECT  21.197 2.304 21.233 18.024 ;
     RECT  21.197 19.824 21.233 20.424 ;
     RECT  20.956 39.216 21.233 39.24 ;
     RECT  21.233 2.304 21.449 15.576 ;
     RECT  21.449 6.144 21.557 15.576 ;
     RECT  21.557 7.728 21.629 15.576 ;
     RECT  20.945 24.432 21.773 24.648 ;
     RECT  19.973 43.152 21.781 43.32 ;
     RECT  21.781 42.768 21.797 43.32 ;
     RECT  21.085 26.832 21.827 28.536 ;
     RECT  21.049 32.208 21.836 33.096 ;
     RECT  21.827 28.464 21.845 28.536 ;
     RECT  21.797 42.768 21.881 43.944 ;
     RECT  21.836 32.208 21.923 33.144 ;
     RECT  21.481 45.6 21.925 45.624 ;
     RECT  21.925 45.6 21.971 46.248 ;
     RECT  21.971 46.224 22.012 46.248 ;
     RECT  21.781 30.432 22.165 30.456 ;
     RECT  21.629 8.16 22.201 15.576 ;
     RECT  21.233 16.56 22.201 18.024 ;
     RECT  21.923 32.208 22.211 33.096 ;
     RECT  20.485 34.176 22.229 37.032 ;
     RECT  22.201 8.16 22.237 18.024 ;
     RECT  21.881 42.768 22.259 43.176 ;
     RECT  21.827 26.832 22.277 27.384 ;
     RECT  21.845 28.464 22.277 28.488 ;
     RECT  22.193 44.448 22.277 44.472 ;
     RECT  22.229 34.176 22.307 37.08 ;
     RECT  22.307 34.464 22.313 37.08 ;
     RECT  22.237 8.16 22.345 18.216 ;
     RECT  22.259 42.768 22.349 43.128 ;
     RECT  21.193 21.648 22.385 23.352 ;
     RECT  21.049 40.608 22.493 41.352 ;
     RECT  22.211 33.072 22.529 33.096 ;
     RECT  22.345 8.16 22.597 19.128 ;
     RECT  21.233 20.112 22.597 20.424 ;
     RECT  22.597 8.16 22.777 20.424 ;
     RECT  21.449 2.304 22.817 5.16 ;
     RECT  22.817 2.544 22.844 5.16 ;
     RECT  21.557 6.144 22.844 6.264 ;
     RECT  22.777 7.92 22.889 20.424 ;
     RECT  22.889 19.776 22.957 20.424 ;
     RECT  22.889 7.92 22.988 18.792 ;
     RECT  22.313 34.464 23.461 36.936 ;
     RECT  22.493 40.608 23.497 41.256 ;
     RECT  22.349 43.104 23.516 43.128 ;
     RECT  22.844 2.544 24.008 6.264 ;
     RECT  22.988 7.392 24.008 18.792 ;
     RECT  22.957 19.776 24.008 20.472 ;
     RECT  22.385 21.744 24.008 23.352 ;
     RECT  21.773 24.432 24.008 24.456 ;
     RECT  22.277 26.832 24.008 26.856 ;
     RECT  22.165 30.432 24.008 30.648 ;
     RECT  23.461 33.552 24.008 36.936 ;
     RECT  23.785 37.968 24.008 37.992 ;
     RECT  21.625 39.072 24.008 39.096 ;
     RECT  23.497 40.08 24.008 41.256 ;
     RECT  23.516 42.624 24.008 43.128 ;
     RECT  23.557 45.6 24.008 45.624 ;
     RECT  24.008 2.148 24.112 46.452 ;
     RECT  24.112 2.256 24.304 46.182 ;
     RECT  24.304 26.112 24.419 27.912 ;
     RECT  24.304 39.024 24.419 41.4 ;
     RECT  24.304 28.992 24.509 29.016 ;
     RECT  24.304 31.728 24.515 37.992 ;
     RECT  24.419 41.232 24.545 41.4 ;
     RECT  24.304 7.44 24.563 10.392 ;
     RECT  24.304 21.984 24.563 23.352 ;
     RECT  24.563 7.44 24.581 10.344 ;
     RECT  24.304 12.48 24.581 20.424 ;
     RECT  24.419 39.024 24.581 40.152 ;
     RECT  24.515 31.728 24.611 36.936 ;
     RECT  24.304 30.192 24.652 30.744 ;
     RECT  24.304 2.256 24.689 6.264 ;
     RECT  24.419 26.112 24.761 27.144 ;
     RECT  24.581 13.008 25.013 20.424 ;
     RECT  25.013 13.008 25.036 18.168 ;
     RECT  24.689 2.256 25.091 4.776 ;
     RECT  24.515 37.968 25.121 37.992 ;
     RECT  24.581 39.888 25.121 40.152 ;
     RECT  24.689 6.144 25.297 6.264 ;
     RECT  24.304 43.776 25.297 44.088 ;
     RECT  24.761 26.112 25.369 27.096 ;
     RECT  25.297 6.144 25.585 6.84 ;
     RECT  24.581 7.968 25.585 10.344 ;
     RECT  25.297 43.536 25.585 44.088 ;
     RECT  24.563 22.464 25.621 23.352 ;
     RECT  24.545 41.376 25.621 41.4 ;
     RECT  25.585 42.672 25.621 44.088 ;
     RECT  25.621 41.376 25.693 44.088 ;
     RECT  24.304 45.552 25.693 45.576 ;
     RECT  25.405 28.56 25.729 28.584 ;
     RECT  25.369 25.728 25.945 27.096 ;
     RECT  25.729 28.464 25.945 28.584 ;
     RECT  25.585 6.144 25.949 10.344 ;
     RECT  25.949 8.016 25.957 10.344 ;
     RECT  25.801 11.616 25.957 11.64 ;
     RECT  25.693 41.376 26.017 45.576 ;
     RECT  24.652 30.432 26.101 30.744 ;
     RECT  25.091 2.64 26.125 4.776 ;
     RECT  25.949 6.144 26.125 6.984 ;
     RECT  25.957 8.016 26.125 11.64 ;
     RECT  24.611 32.304 26.125 36.936 ;
     RECT  25.765 38.784 26.125 38.808 ;
     RECT  25.121 39.984 26.125 40.152 ;
     RECT  26.017 41.328 26.125 45.576 ;
     RECT  26.125 32.304 26.165 38.808 ;
     RECT  26.101 30.336 26.188 31.08 ;
     RECT  25.621 22.224 26.197 23.352 ;
     RECT  24.304 24.336 26.197 24.36 ;
     RECT  26.125 8.016 26.237 11.784 ;
     RECT  26.197 22.224 26.269 24.36 ;
     RECT  25.036 13.632 26.341 18.168 ;
     RECT  25.013 19.248 26.341 20.424 ;
     RECT  26.269 22.224 26.341 24.648 ;
     RECT  25.945 25.728 26.341 28.584 ;
     RECT  26.125 2.64 26.489 6.984 ;
     RECT  26.237 8.016 26.525 11.64 ;
     RECT  26.165 32.688 26.629 38.808 ;
     RECT  26.125 39.984 26.629 45.576 ;
     RECT  26.341 22.224 26.701 28.68 ;
     RECT  26.525 8.016 26.777 11.16 ;
     RECT  26.341 13.632 26.777 20.424 ;
     RECT  26.701 22.224 26.813 28.728 ;
     RECT  26.629 32.688 26.849 45.576 ;
     RECT  26.813 22.224 26.885 28.68 ;
     RECT  26.885 23.088 26.957 28.68 ;
     RECT  26.957 25.824 27.065 28.68 ;
     RECT  26.849 32.688 27.065 40.44 ;
     RECT  26.957 23.088 27.137 24.552 ;
     RECT  27.065 27.888 27.137 28.632 ;
     RECT  27.137 23.088 27.173 24.36 ;
     RECT  27.065 32.688 27.241 37.704 ;
     RECT  26.188 30.336 27.301 30.456 ;
     RECT  27.301 30.336 27.317 31.416 ;
     RECT  27.173 23.088 27.353 24.168 ;
     RECT  26.777 20.4 27.389 20.424 ;
     RECT  26.777 8.448 27.605 11.16 ;
     RECT  26.489 2.64 27.74 4.776 ;
     RECT  27.74 2.64 27.743 5.112 ;
     RECT  26.489 6.144 27.743 6.984 ;
     RECT  26.777 13.632 27.745 19.272 ;
     RECT  27.605 10.992 27.781 11.16 ;
     RECT  27.781 10.992 27.853 11.688 ;
     RECT  27.317 30.432 27.961 31.416 ;
     RECT  27.241 32.496 27.961 37.704 ;
     RECT  27.961 30.432 28.033 37.704 ;
     RECT  27.065 38.784 28.033 40.44 ;
     RECT  27.065 25.824 28.073 26.904 ;
     RECT  27.745 13.632 28.105 19.368 ;
     RECT  27.853 10.992 28.141 11.976 ;
     RECT  28.105 13.632 28.141 20.088 ;
     RECT  27.605 8.448 28.145 9.528 ;
     RECT  27.353 23.136 28.177 24.168 ;
     RECT  28.033 30.432 28.177 40.44 ;
     RECT  26.849 41.952 28.177 45.576 ;
     RECT  28.073 25.824 28.249 25.848 ;
     RECT  28.177 23.136 28.393 24.456 ;
     RECT  28.249 25.776 28.393 25.848 ;
     RECT  27.743 2.64 28.465 6.984 ;
     RECT  27.137 27.888 28.501 27.912 ;
     RECT  28.285 28.992 28.501 29.016 ;
     RECT  28.145 8.448 29.036 9.384 ;
     RECT  28.141 10.992 29.077 20.088 ;
     RECT  28.393 23.136 29.077 25.848 ;
     RECT  28.073 26.832 29.077 26.904 ;
     RECT  28.501 27.888 29.077 29.016 ;
     RECT  29.036 8.352 29.269 9.384 ;
     RECT  28.465 2.64 29.329 7.32 ;
     RECT  29.269 8.352 29.329 9.624 ;
     RECT  29.329 2.64 29.408 9.624 ;
     RECT  29.077 10.992 29.408 20.424 ;
     RECT  29.257 21.984 29.408 22.008 ;
     RECT  29.077 23.04 29.408 25.848 ;
     RECT  29.077 26.832 29.408 29.016 ;
     RECT  28.177 30.432 29.408 45.576 ;
     RECT  29.408 2.148 29.512 46.452 ;
     RECT  29.512 2.418 29.704 46.182 ;
     RECT  29.704 21.648 29.873 22.008 ;
     RECT  29.704 23.136 29.873 25.464 ;
     RECT  29.704 10.992 30.017 20.616 ;
     RECT  29.704 26.784 30.161 29.016 ;
     RECT  30.161 26.832 30.305 29.016 ;
     RECT  30.017 10.992 30.413 19.656 ;
     RECT  30.305 28.176 30.413 29.016 ;
     RECT  30.413 28.176 30.521 28.776 ;
     RECT  29.873 21.648 30.949 21.816 ;
     RECT  30.949 21.216 31.241 21.816 ;
     RECT  30.413 14.16 31.273 19.656 ;
     RECT  31.241 21.216 31.273 21.24 ;
     RECT  31.273 14.16 31.349 21.24 ;
     RECT  29.704 30.096 31.637 45.576 ;
     RECT  29.873 23.232 31.817 25.464 ;
     RECT  31.637 30.096 31.817 45.48 ;
     RECT  30.521 28.176 32.137 28.2 ;
     RECT  32.137 28.176 32.245 28.44 ;
     RECT  30.413 10.992 32.249 13.08 ;
     RECT  31.349 14.16 32.317 20.664 ;
     RECT  30.305 26.832 32.425 27.144 ;
     RECT  32.245 28.176 32.425 28.776 ;
     RECT  32.249 10.992 32.429 12.648 ;
     RECT  31.817 23.232 32.497 25.032 ;
     RECT  29.704 2.64 32.605 9.384 ;
     RECT  31.817 30.096 32.605 45.192 ;
     RECT  32.425 26.832 32.753 28.776 ;
     RECT  32.497 22.848 32.821 25.032 ;
     RECT  32.317 14.16 32.897 20.76 ;
     RECT  32.821 22.8 32.965 25.512 ;
     RECT  32.605 2.64 33.013 9.48 ;
     RECT  32.897 20.592 33.037 20.76 ;
     RECT  33.013 2.64 33.073 9.768 ;
     RECT  33.037 20.592 33.073 21.144 ;
     RECT  32.965 22.752 33.073 25.512 ;
     RECT  32.605 30 33.073 45.192 ;
     RECT  33.073 30 33.217 45.288 ;
     RECT  33.217 30 33.289 45.48 ;
     RECT  33.289 29.088 33.397 45.48 ;
     RECT  33.397 29.088 33.505 45.528 ;
     RECT  32.429 11.664 33.613 12.648 ;
     RECT  33.073 2.496 33.653 9.768 ;
     RECT  33.653 2.496 33.779 7.704 ;
     RECT  33.505 29.088 33.797 45.576 ;
     RECT  33.653 9.072 34.009 9.768 ;
     RECT  33.613 10.944 34.009 12.648 ;
     RECT  32.897 14.16 34.333 19.56 ;
     RECT  34.009 9.072 34.693 12.648 ;
     RECT  33.073 20.592 34.729 25.512 ;
     RECT  32.753 26.832 34.729 27.624 ;
     RECT  34.693 9.072 34.765 12.744 ;
     RECT  34.333 13.92 34.765 19.56 ;
     RECT  33.779 2.496 34.808 6.696 ;
     RECT  33.779 7.68 34.808 7.704 ;
     RECT  34.765 9.072 34.808 19.56 ;
     RECT  34.729 20.592 34.808 27.624 ;
     RECT  34.189 28.752 34.808 28.776 ;
     RECT  33.797 29.856 34.808 45.576 ;
     RECT  34.808 2.148 34.912 46.452 ;
     RECT  34.912 2.418 35.104 46.182 ;
     RECT  35.104 30.048 35.165 45.576 ;
     RECT  35.104 15.984 35.309 27.912 ;
     RECT  35.309 26.832 35.813 27.912 ;
     RECT  35.165 30.336 35.885 45.576 ;
     RECT  35.104 10.944 35.891 14.952 ;
     RECT  35.885 42.432 35.957 45.576 ;
     RECT  35.891 10.944 36.169 13.08 ;
     RECT  35.891 14.16 36.205 14.952 ;
     RECT  35.813 26.832 36.353 27.144 ;
     RECT  35.104 2.496 36.421 6.696 ;
     RECT  35.104 7.68 36.421 9.72 ;
     RECT  35.885 30.336 36.529 41.448 ;
     RECT  36.421 2.496 36.637 9.72 ;
     RECT  36.353 26.832 36.641 26.952 ;
     RECT  36.637 2.496 36.817 9.768 ;
     RECT  36.169 10.848 36.817 13.08 ;
     RECT  35.309 15.984 36.821 25.512 ;
     RECT  36.529 30.144 36.889 41.448 ;
     RECT  36.817 2.496 37.033 13.08 ;
     RECT  36.889 29.808 37.141 41.448 ;
     RECT  36.821 25.488 37.249 25.512 ;
     RECT  35.957 42.432 37.249 45.528 ;
     RECT  37.141 29.616 37.289 41.448 ;
     RECT  36.821 15.984 37.331 24.456 ;
     RECT  37.249 42.432 37.397 45.576 ;
     RECT  36.205 14.16 37.429 15 ;
     RECT  37.331 15.984 37.429 17.16 ;
     RECT  37.429 14.16 37.541 17.16 ;
     RECT  37.541 14.16 37.577 16.008 ;
     RECT  37.331 18.48 37.577 24.456 ;
     RECT  37.577 19.632 37.649 24.456 ;
     RECT  37.033 2.352 37.681 13.08 ;
     RECT  37.577 14.16 37.681 15.48 ;
     RECT  37.289 29.616 37.724 41.4 ;
     RECT  37.397 42.432 37.793 45.528 ;
     RECT  37.724 29.568 38.149 41.4 ;
     RECT  37.649 20.88 38.221 24.456 ;
     RECT  37.249 25.488 38.221 25.848 ;
     RECT  38.149 29.184 38.225 41.4 ;
     RECT  38.225 29.184 38.513 41.16 ;
     RECT  38.513 29.472 38.621 41.16 ;
     RECT  36.641 26.928 38.761 26.952 ;
     RECT  37.541 17.04 38.941 17.16 ;
     RECT  37.577 18.48 38.941 18.504 ;
     RECT  37.649 19.632 38.945 19.656 ;
     RECT  38.941 17.04 38.977 18.504 ;
     RECT  38.977 17.04 39.229 18.84 ;
     RECT  37.793 44.064 39.229 45.528 ;
     RECT  38.221 20.88 39.265 25.848 ;
     RECT  38.621 29.664 39.301 41.16 ;
     RECT  37.793 42.432 39.301 42.84 ;
     RECT  37.681 2.352 39.329 15.48 ;
     RECT  39.229 16.608 39.329 18.84 ;
     RECT  38.761 26.832 39.409 26.952 ;
     RECT  39.409 26.832 39.74 27.192 ;
     RECT  39.301 29.664 40.129 42.84 ;
     RECT  39.229 44.064 40.129 45.768 ;
     RECT  39.329 2.352 40.208 18.84 ;
     RECT  39.265 20.4 40.208 25.848 ;
     RECT  39.74 26.832 40.208 28.152 ;
     RECT  40.129 29.52 40.208 45.768 ;
     RECT  40.208 2.148 40.312 46.452 ;
     RECT  40.312 2.304 40.504 46.182 ;
     RECT  40.504 22.752 40.673 27.384 ;
     RECT  40.673 22.752 40.889 25.8 ;
     RECT  40.889 25.488 41.213 25.8 ;
     RECT  40.504 20.4 41.533 21.672 ;
     RECT  40.889 22.752 41.533 24.456 ;
     RECT  40.504 28.464 42.005 46.152 ;
     RECT  41.213 25.488 42.041 25.752 ;
     RECT  40.504 2.304 42.133 19.224 ;
     RECT  41.533 20.4 42.133 24.456 ;
     RECT  42.005 28.464 42.221 45.336 ;
     RECT  42.221 28.464 42.293 33.288 ;
     RECT  40.673 26.832 42.373 27.384 ;
     RECT  42.133 2.304 42.412 24.456 ;
     RECT  42.293 29.184 42.437 33.288 ;
     RECT  42.221 34.272 42.437 45.336 ;
     RECT  42.412 20.016 42.617 24.456 ;
     RECT  42.373 26.832 42.757 27.912 ;
     RECT  42.757 26.736 42.841 27.912 ;
     RECT  42.617 20.016 42.869 20.04 ;
     RECT  42.437 29.376 42.905 33.288 ;
     RECT  42.617 21.168 43.081 24.456 ;
     RECT  42.041 25.488 43.081 25.512 ;
     RECT  43.081 21.168 43.121 25.512 ;
     RECT  42.905 30.384 43.261 33.288 ;
     RECT  42.437 34.272 43.261 45.24 ;
     RECT  42.841 26.736 43.468 27.864 ;
     RECT  43.261 30.384 43.549 45.24 ;
     RECT  43.121 21.504 43.621 25.512 ;
     RECT  43.468 26.736 43.621 27.672 ;
     RECT  42.905 29.376 43.841 29.4 ;
     RECT  43.621 21.504 43.907 27.672 ;
     RECT  42.412 2.304 44.197 18.792 ;
     RECT  43.907 21.504 44.197 26.088 ;
     RECT  44.197 2.304 44.341 20.184 ;
     RECT  44.197 21.456 44.341 26.088 ;
     RECT  44.413 28.944 44.588 29.352 ;
     RECT  43.907 27.648 44.629 27.672 ;
     RECT  44.588 28.656 44.629 29.352 ;
     RECT  44.341 2.304 45.493 26.088 ;
     RECT  45.493 2.304 45.608 26.664 ;
     RECT  44.629 27.648 45.608 29.352 ;
     RECT  43.549 30.384 45.608 45.576 ;
     RECT  45.608 2.148 45.712 46.452 ;
     RECT  45.712 2.304 45.904 46.182 ;
     RECT  45.904 2.304 46.001 19.08 ;
     RECT  45.904 20.4 46.019 26.376 ;
     RECT  46.019 20.64 46.253 26.376 ;
     RECT  45.904 43.92 46.289 45.576 ;
     RECT  45.904 27.648 46.876 40.632 ;
     RECT  46.876 36.096 46.897 40.632 ;
     RECT  45.904 41.712 46.897 42.744 ;
     RECT  46.289 43.92 46.973 45.24 ;
     RECT  46.973 43.92 47.027 45.144 ;
     RECT  46.001 2.352 47.324 19.08 ;
     RECT  46.253 20.64 47.324 26.232 ;
     RECT  47.324 2.352 47.329 26.232 ;
     RECT  47.329 2.352 47.545 26.28 ;
     RECT  47.027 43.92 47.837 44.76 ;
     RECT  46.876 27.648 47.852 34.872 ;
     RECT  47.545 2.352 47.945 26.328 ;
     RECT  47.852 27.312 48.037 34.872 ;
     RECT  47.945 2.352 48.275 24.552 ;
     RECT  47.945 25.584 48.337 26.328 ;
     RECT  48.037 27.312 48.337 34.92 ;
     RECT  46.897 36.096 48.769 42.744 ;
     RECT  48.337 25.584 48.805 34.92 ;
     RECT  48.769 36.096 48.805 42.792 ;
     RECT  47.837 44.4 48.809 44.76 ;
     RECT  48.275 2.352 49.021 24.504 ;
     RECT  48.805 25.584 49.133 42.792 ;
     RECT  49.021 2.304 49.313 24.504 ;
     RECT  49.133 25.584 49.313 42.744 ;
     RECT  49.313 25.584 49.349 35.208 ;
     RECT  49.313 20.112 49.381 24.504 ;
     RECT  49.313 36.528 49.457 41.976 ;
     RECT  48.809 44.448 49.465 44.76 ;
     RECT  49.381 20.112 49.561 24.6 ;
     RECT  49.465 44.736 49.561 44.76 ;
     RECT  49.313 2.304 49.565 18.936 ;
     RECT  49.561 20.112 50.461 24.936 ;
     RECT  50.461 19.776 50.485 24.936 ;
     RECT  49.349 26.208 50.485 35.208 ;
     RECT  49.457 36.528 50.533 41.448 ;
     RECT  50.485 19.776 50.605 35.208 ;
     RECT  50.533 36.528 50.605 42.024 ;
     RECT  49.565 2.304 50.677 18.792 ;
     RECT  50.605 19.776 50.677 42.024 ;
     RECT  50.677 2.304 51.008 42.024 ;
     RECT  50.497 43.056 51.008 43.08 ;
     RECT  49.561 44.736 51.008 44.904 ;
     RECT  51.008 2.148 51.112 46.452 ;
     RECT  51.112 2.304 51.304 46.182 ;
     RECT  51.304 26.208 51.581 42.024 ;
     RECT  51.581 26.208 51.689 39.768 ;
     RECT  51.304 2.304 51.725 25.128 ;
     RECT  51.581 40.896 52.013 42.024 ;
     RECT  51.689 26.208 52.741 26.232 ;
     RECT  51.689 27.312 52.741 39.768 ;
     RECT  52.741 26.208 52.801 39.768 ;
     RECT  52.801 26.208 52.828 39.816 ;
     RECT  51.725 2.304 53.017 24.6 ;
     RECT  53.017 2.304 53.021 24.984 ;
     RECT  52.828 27.312 53.053 39.816 ;
     RECT  53.053 27.312 53.093 39.912 ;
     RECT  53.093 27.504 53.125 39.912 ;
     RECT  52.013 41.184 53.125 42.024 ;
     RECT  53.021 2.352 53.161 24.984 ;
     RECT  52.828 26.208 53.161 26.28 ;
     RECT  53.161 2.352 53.201 26.28 ;
     RECT  53.201 23.088 53.561 26.28 ;
     RECT  53.561 23.088 53.669 24.984 ;
     RECT  51.304 45.696 53.881 45.72 ;
     RECT  53.881 44.928 54.061 45.72 ;
     RECT  53.201 2.352 54.083 22.008 ;
     RECT  54.061 44.352 54.101 45.72 ;
     RECT  54.083 8.544 54.169 22.008 ;
     RECT  53.669 23.088 54.169 24.504 ;
     RECT  53.125 27.504 54.205 42.024 ;
     RECT  51.304 43.056 54.205 43.32 ;
     RECT  54.101 44.352 54.205 44.376 ;
     RECT  53.561 26.256 54.457 26.28 ;
     RECT  54.205 27.36 54.457 42.024 ;
     RECT  54.101 45.696 54.529 45.72 ;
     RECT  54.457 26.256 54.565 42.024 ;
     RECT  54.205 43.056 54.569 44.376 ;
     RECT  54.565 25.632 54.605 42.024 ;
     RECT  54.529 45.696 54.709 46.008 ;
     RECT  54.169 8.544 54.757 24.504 ;
     RECT  54.605 26.64 54.857 42.024 ;
     RECT  54.857 26.64 54.965 39.864 ;
     RECT  54.757 8.544 55.033 24.648 ;
     RECT  54.605 25.632 55.033 25.656 ;
     RECT  55.033 8.544 55.073 25.656 ;
     RECT  54.857 40.848 55.109 42.024 ;
     RECT  54.965 26.64 55.145 39.624 ;
     RECT  54.709 45.696 55.249 46.056 ;
     RECT  55.249 45.648 55.357 46.056 ;
     RECT  55.073 8.544 55.361 10.248 ;
     RECT  54.083 2.352 55.897 7.464 ;
     RECT  55.361 8.544 55.897 9.864 ;
     RECT  55.145 27.216 56.113 39.624 ;
     RECT  54.569 43.056 56.113 43.56 ;
     RECT  55.073 11.232 56.149 25.656 ;
     RECT  56.113 43.056 56.149 43.752 ;
     RECT  56.149 43.056 56.329 43.848 ;
     RECT  55.897 2.352 56.408 9.864 ;
     RECT  56.149 10.992 56.408 25.656 ;
     RECT  56.113 26.64 56.408 39.624 ;
     RECT  55.109 41.184 56.408 42.024 ;
     RECT  56.329 43.056 56.408 43.896 ;
     RECT  55.357 44.88 56.408 46.056 ;
     RECT  56.408 2.148 56.512 46.452 ;
     RECT  56.512 2.352 56.704 46.182 ;
     RECT  56.704 40.704 56.909 46.104 ;
     RECT  56.909 44.16 57.449 46.104 ;
     RECT  56.704 2.352 57.661 7.992 ;
     RECT  57.661 2.304 57.733 7.992 ;
     RECT  56.704 9.024 57.733 39.624 ;
     RECT  57.733 2.304 57.949 39.624 ;
     RECT  56.909 40.704 57.949 43.08 ;
     RECT  57.949 2.304 58.669 43.08 ;
     RECT  57.449 44.592 58.669 46.104 ;
     RECT  58.669 2.304 58.709 46.104 ;
     RECT  58.709 2.352 60.113 46.104 ;
     RECT  60.113 11.664 60.149 46.104 ;
     RECT  60.113 2.352 60.293 10.296 ;
     RECT  60.149 44.352 60.329 46.104 ;
     RECT  60.329 44.352 60.473 46.008 ;
     RECT  60.473 44.496 60.797 46.008 ;
     RECT  60.293 2.352 61.009 9.912 ;
     RECT  60.797 44.496 61.441 45.96 ;
     RECT  61.441 44.448 61.549 45.96 ;
     RECT  61.009 2.256 61.808 9.912 ;
     RECT  60.149 11.664 61.808 43.08 ;
     RECT  61.549 44.064 61.808 45.96 ;
     RECT  61.808 2.148 61.912 46.452 ;
     RECT  61.912 2.256 62.021 46.182 ;
     RECT  62.021 2.352 62.104 46.182 ;
     RECT  62.104 9.312 62.201 43.08 ;
     RECT  62.201 9.312 62.993 43.032 ;
     RECT  62.993 10.704 63.389 43.032 ;
     RECT  63.389 10.704 63.425 27.336 ;
     RECT  63.389 28.368 63.461 43.032 ;
     RECT  63.461 28.512 63.569 43.032 ;
     RECT  62.993 9.312 63.709 9.624 ;
     RECT  63.569 28.656 63.781 43.032 ;
     RECT  62.104 44.064 63.781 45.96 ;
     RECT  63.709 8.976 64.249 9.624 ;
     RECT  63.425 10.704 64.249 27.192 ;
     RECT  64.249 8.976 64.645 27.192 ;
     RECT  62.104 2.352 64.861 7.416 ;
     RECT  64.645 8.784 64.861 27.192 ;
     RECT  64.861 2.352 64.897 27.192 ;
     RECT  63.781 28.656 65.189 45.96 ;
     RECT  64.897 2.352 65.221 27.384 ;
     RECT  65.189 28.656 65.221 43.656 ;
     RECT  65.189 44.784 65.477 45.96 ;
     RECT  65.477 44.784 65.513 45.816 ;
     RECT  65.221 2.352 65.729 43.656 ;
     RECT  65.513 44.88 65.945 45.816 ;
     RECT  65.729 2.352 65.981 7.944 ;
     RECT  65.729 8.976 66.565 43.656 ;
     RECT  65.981 2.352 67.208 4.776 ;
     RECT  65.981 5.856 67.208 7.944 ;
     RECT  66.565 8.976 67.208 43.896 ;
     RECT  65.945 44.88 67.208 45.768 ;
     RECT  67.208 2.148 67.312 46.452 ;
     RECT  67.312 2.256 67.504 46.182 ;
     RECT  67.504 2.256 67.529 7.224 ;
     RECT  67.529 2.256 67.619 6.792 ;
     RECT  67.619 2.352 67.781 6.792 ;
     RECT  67.504 9.024 67.811 43.656 ;
     RECT  67.504 44.832 67.853 44.904 ;
     RECT  67.811 10.608 68.147 43.656 ;
     RECT  67.811 9.024 68.501 9.528 ;
     RECT  67.781 2.352 68.537 6.312 ;
     RECT  68.147 33.648 68.929 43.656 ;
     RECT  67.853 44.832 68.929 44.856 ;
     RECT  68.147 10.608 69.217 32.616 ;
     RECT  68.929 33.648 69.217 44.856 ;
     RECT  68.497 7.44 69.253 7.464 ;
     RECT  68.501 9.024 69.253 9.048 ;
     RECT  69.217 10.608 69.257 44.856 ;
     RECT  68.537 2.352 69.325 4.872 ;
     RECT  69.257 28.08 69.349 44.856 ;
     RECT  69.349 28.08 69.361 45 ;
     RECT  69.361 28.08 69.436 45.864 ;
     RECT  68.537 6.048 69.649 6.312 ;
     RECT  69.253 7.44 69.649 9.048 ;
     RECT  69.649 6.048 69.781 9.048 ;
     RECT  69.436 28.08 69.941 44.376 ;
     RECT  69.781 6.048 70.049 9.096 ;
     RECT  70.049 6.048 70.157 9.048 ;
     RECT  69.257 10.608 70.373 26.952 ;
     RECT  69.325 2.304 70.441 4.872 ;
     RECT  70.157 6.048 70.517 8.52 ;
     RECT  70.441 2.304 70.549 4.92 ;
     RECT  70.517 6.048 70.549 8.328 ;
     RECT  70.549 2.304 70.589 8.328 ;
     RECT  70.589 2.304 70.841 7.992 ;
     RECT  69.436 45.6 70.873 45.864 ;
     RECT  70.841 2.304 70.877 6.744 ;
     RECT  70.877 2.304 70.949 6.6 ;
     RECT  70.873 45.6 70.981 46.248 ;
     RECT  69.941 33.648 71.017 44.376 ;
     RECT  70.981 45.408 71.017 46.248 ;
     RECT  69.941 28.08 71.053 32.616 ;
     RECT  71.017 33.648 71.129 46.248 ;
     RECT  71.053 27.984 71.197 32.616 ;
     RECT  71.129 33.648 71.197 44.376 ;
     RECT  71.197 27.984 71.309 44.376 ;
     RECT  70.373 10.704 71.701 26.952 ;
     RECT  70.841 7.968 71.953 7.992 ;
     RECT  71.953 7.392 72.025 7.992 ;
     RECT  71.701 9.888 72.061 26.952 ;
     RECT  71.309 27.984 72.061 43.944 ;
     RECT  72.025 7.392 72.205 8.856 ;
     RECT  72.061 9.888 72.205 43.944 ;
     RECT  71.129 45.408 72.241 46.248 ;
     RECT  72.205 7.392 72.277 43.944 ;
     RECT  72.241 44.928 72.277 46.248 ;
     RECT  70.949 2.304 72.421 6.312 ;
     RECT  72.277 7.392 72.421 46.248 ;
     RECT  72.421 2.304 72.608 46.248 ;
     RECT  72.608 2.148 72.712 46.452 ;
     RECT  72.712 2.256 72.904 46.248 ;
     RECT  72.904 46.224 73.571 46.248 ;
     RECT  72.904 2.256 73.577 44.952 ;
     RECT  73.577 2.256 73.901 44.904 ;
     RECT  73.901 2.256 74.099 6.552 ;
     RECT  73.901 7.632 74.653 44.904 ;
     RECT  74.653 7.632 74.732 45.048 ;
     RECT  74.653 46.032 74.732 46.056 ;
     RECT  74.732 7.632 74.801 46.056 ;
     RECT  74.099 2.304 75.373 6.552 ;
     RECT  74.801 7.632 75.373 45.96 ;
     RECT  75.373 2.304 75.413 45.96 ;
     RECT  75.413 2.304 76.169 44.952 ;
     RECT  76.169 2.544 76.205 44.952 ;
     RECT  76.205 30.624 76.349 44.952 ;
     RECT  76.205 2.544 77.173 29.544 ;
     RECT  75.413 45.936 77.281 45.96 ;
     RECT  76.349 30.624 77.509 44.904 ;
     RECT  77.173 2.256 77.885 29.544 ;
     RECT  77.509 30.624 77.885 44.952 ;
     RECT  77.885 2.256 78.008 44.952 ;
     RECT  77.281 45.936 78.008 46.2 ;
     RECT  78.008 2.148 78.112 46.452 ;
     RECT  78.112 2.256 78.304 46.182 ;
     RECT  78.304 2.256 78.545 6.024 ;
     RECT  78.545 2.448 78.689 6.024 ;
     RECT  78.304 7.728 78.689 45.048 ;
     RECT  78.689 40.56 79.405 45.048 ;
     RECT  78.689 7.728 79.409 39.576 ;
     RECT  79.409 10.704 79.661 39.576 ;
     RECT  78.689 2.544 79.669 6.024 ;
     RECT  79.661 36.24 79.693 39.576 ;
     RECT  79.405 40.56 79.693 45.288 ;
     RECT  79.429 46.272 79.913 46.296 ;
     RECT  79.409 7.728 80.051 9.144 ;
     RECT  79.669 6 80.413 6.024 ;
     RECT  80.051 7.728 80.413 8.04 ;
     RECT  79.693 36.24 80.701 45.288 ;
     RECT  79.661 10.704 80.773 35.256 ;
     RECT  79.669 2.544 80.845 4.776 ;
     RECT  80.413 6 80.845 8.04 ;
     RECT  80.773 10.56 80.953 35.256 ;
     RECT  80.701 36.24 80.953 46.2 ;
     RECT  80.953 10.56 80.957 46.2 ;
     RECT  80.957 43.872 80.963 46.2 ;
     RECT  80.957 10.56 81.065 42.696 ;
     RECT  80.963 43.872 81.209 45.768 ;
     RECT  81.209 44.304 82.172 45.768 ;
     RECT  82.172 44.304 82.259 46.248 ;
     RECT  80.051 9.024 82.309 9.144 ;
     RECT  81.065 10.56 82.309 41.064 ;
     RECT  82.309 9.024 82.317 41.064 ;
     RECT  81.065 42.144 82.465 42.696 ;
     RECT  80.845 2.544 82.501 8.04 ;
     RECT  82.317 9.024 82.501 37.464 ;
     RECT  82.317 38.544 82.501 41.064 ;
     RECT  82.465 42.144 82.501 43.128 ;
     RECT  82.501 2.544 82.537 37.464 ;
     RECT  82.501 38.544 82.537 43.128 ;
     RECT  82.259 44.304 82.537 45.768 ;
     RECT  82.537 2.304 83.408 37.464 ;
     RECT  82.537 38.544 83.408 45.768 ;
     RECT  83.408 2.148 83.512 46.452 ;
     RECT  83.512 2.304 83.704 46.182 ;
     RECT  83.704 42.24 83.801 46.104 ;
     RECT  83.801 42.528 83.837 46.104 ;
     RECT  83.837 42.528 84.457 45.048 ;
     RECT  83.704 38.448 84.949 41.208 ;
     RECT  84.457 42.528 85.453 45 ;
     RECT  83.704 2.304 85.597 37.464 ;
     RECT  84.949 38.448 85.597 41.4 ;
     RECT  85.453 42.48 85.669 45 ;
     RECT  83.837 46.08 85.669 46.104 ;
     RECT  85.597 2.304 85.849 41.4 ;
     RECT  85.669 42.48 85.849 46.104 ;
     RECT  85.849 2.304 86.645 46.104 ;
     RECT  86.645 42.768 86.753 46.104 ;
     RECT  86.645 2.304 87.113 41.736 ;
     RECT  87.113 2.304 87.473 35.352 ;
     RECT  87.113 36.336 87.473 41.736 ;
     RECT  87.473 2.304 87.491 35.256 ;
     RECT  87.473 36.576 87.829 41.736 ;
     RECT  86.753 42.816 87.829 46.104 ;
     RECT  87.491 2.352 88.808 35.256 ;
     RECT  87.829 36.576 88.808 46.104 ;
     RECT  88.808 2.148 88.912 46.452 ;
     RECT  88.912 2.304 89.104 46.182 ;
     RECT  89.104 2.304 92.693 46.104 ;
     RECT  92.693 2.304 92.981 29.304 ;
     RECT  92.981 2.304 93.481 26.616 ;
     RECT  92.693 30.624 93.697 46.104 ;
     RECT  92.981 27.696 93.985 29.304 ;
     RECT  93.481 2.256 94.208 26.616 ;
     RECT  93.985 27.696 94.208 29.64 ;
     RECT  93.697 30.624 94.208 46.152 ;
     RECT  94.208 2.148 94.312 46.452 ;
     RECT  94.312 2.304 94.504 46.182 ;
     RECT  94.504 2.304 94.673 9.336 ;
     RECT  94.673 2.304 95.713 9.144 ;
     RECT  95.713 2.208 96.185 9.144 ;
     RECT  94.504 10.56 96.572 46.152 ;
     RECT  96.185 2.352 96.613 9.144 ;
     RECT  96.572 10.32 96.613 46.152 ;
     RECT  96.613 2.352 98.557 46.152 ;
     RECT  98.557 2.304 99.316 46.152 ;
     RECT  99.316 2.256 99.608 46.152 ;
     RECT  99.608 2.148 99.712 46.452 ;
     RECT  99.712 2.256 99.904 46.182 ;
     RECT  99.904 2.256 100.757 46.104 ;
     RECT  100.757 2.352 101.405 46.104 ;
     RECT  101.405 30.384 101.833 46.104 ;
     RECT  101.833 30.384 102.613 46.152 ;
     RECT  101.405 2.352 102.625 29.304 ;
     RECT  102.613 30.384 102.625 46.248 ;
     RECT  102.625 2.352 102.701 46.248 ;
     RECT  102.701 42.144 102.803 46.248 ;
     RECT  102.701 2.352 103.057 40.968 ;
     RECT  103.057 2.256 103.781 40.968 ;
     RECT  103.781 2.256 103.997 14.808 ;
     RECT  103.781 15.792 104.029 40.968 ;
     RECT  104.029 15.792 104.209 41.016 ;
     RECT  102.803 42.144 104.209 46.152 ;
     RECT  103.997 2.256 105.008 14.76 ;
     RECT  104.209 15.792 105.008 46.152 ;
     RECT  105.008 2.148 105.112 46.452 ;
     RECT  105.112 2.256 105.304 46.182 ;
     RECT  105.304 2.256 105.473 14.76 ;
     RECT  105.473 2.256 105.509 5.64 ;
     RECT  105.304 15.84 106.193 46.104 ;
     RECT  105.473 6.624 106.477 14.76 ;
     RECT  106.193 15.84 106.477 29.4 ;
     RECT  105.509 2.352 106.949 5.64 ;
     RECT  106.193 30.384 107.201 46.104 ;
     RECT  106.477 6.624 107.269 29.4 ;
     RECT  107.201 30.384 107.269 37.464 ;
     RECT  107.269 6.624 108.229 37.464 ;
     RECT  106.949 2.352 108.241 5.592 ;
     RECT  108.229 6.624 108.241 37.56 ;
     RECT  108.241 2.352 108.493 37.56 ;
     RECT  107.201 38.688 108.493 46.104 ;
     RECT  108.493 2.352 109.861 46.104 ;
     RECT  109.861 2.304 110.408 46.104 ;
     RECT  110.408 2.148 110.512 46.452 ;
     RECT  110.512 2.304 110.585 46.182 ;
     RECT  110.585 2.352 110.704 46.182 ;
     RECT  110.704 2.352 111.692 6.024 ;
     RECT  110.704 7.104 111.692 46.104 ;
     RECT  111.692 2.352 112.025 46.104 ;
     RECT  112.025 41.328 112.205 46.104 ;
     RECT  112.025 2.352 112.925 40.104 ;
     RECT  112.205 41.376 112.997 46.104 ;
     RECT  112.925 2.64 114.145 40.104 ;
     RECT  112.997 41.952 114.145 46.104 ;
     RECT  114.145 41.712 114.325 46.104 ;
     RECT  114.145 2.64 114.428 40.152 ;
     RECT  114.325 41.232 114.428 46.104 ;
     RECT  114.428 2.64 115.621 46.104 ;
     RECT  115.621 2.448 115.808 46.104 ;
     RECT  115.808 2.148 115.912 46.452 ;
     RECT  115.912 2.418 116.104 46.182 ;
     RECT  116.104 2.64 118.573 46.104 ;
     RECT  118.573 2.544 119.045 46.104 ;
     RECT  119.045 2.544 120.193 10.152 ;
     RECT  120.193 2.544 120.589 10.2 ;
     RECT  119.045 11.28 120.589 46.104 ;
     RECT  120.589 2.544 121.208 46.104 ;
     RECT  121.208 2.148 121.312 46.452 ;
     RECT  121.312 2.418 121.504 46.182 ;
     RECT  121.504 2.64 121.781 46.104 ;
     RECT  121.781 2.64 122.429 45.576 ;
     RECT  122.429 2.64 122.885 45.288 ;
     RECT  122.885 2.544 123.433 45.288 ;
     RECT  123.433 2.352 123.577 45.288 ;
     RECT  123.577 2.208 124.117 45.288 ;
     RECT  124.117 2.208 124.697 45.576 ;
     RECT  124.697 2.304 125.881 45.576 ;
     RECT  125.881 2.256 126.608 46.008 ;
     RECT  126.608 2.148 126.712 46.452 ;
     RECT  126.712 2.256 126.904 46.182 ;
     RECT  126.904 10.656 127.145 46.008 ;
     RECT  126.904 2.256 127.253 9.624 ;
     RECT  127.253 2.352 127.289 9.624 ;
     RECT  127.145 10.656 127.901 45.432 ;
     RECT  127.289 2.64 128.365 9.624 ;
     RECT  127.901 10.656 128.365 44.376 ;
     RECT  128.365 2.64 128.797 44.376 ;
     RECT  128.797 2.256 128.977 44.376 ;
     RECT  127.901 45.408 128.977 45.432 ;
     RECT  128.977 2.256 129.017 45.432 ;
     RECT  129.017 2.544 130.529 45.432 ;
     RECT  130.529 2.544 130.921 45 ;
     RECT  130.921 2.256 131.557 45 ;
     RECT  131.209 46.032 131.557 46.056 ;
     RECT  131.557 2.256 132.008 46.056 ;
     RECT  132.008 2.148 132.112 46.452 ;
     RECT  132.112 2.418 132.304 46.182 ;
     RECT  132.304 2.592 133.765 46.056 ;
     RECT  133.765 2.496 133.945 46.056 ;
     RECT  133.945 2.496 134.531 46.2 ;
     RECT  134.531 2.496 134.845 45.576 ;
     RECT  134.845 2.256 136.361 45.576 ;
     RECT  136.361 2.256 137.408 45.192 ;
     RECT  137.041 46.224 137.408 46.248 ;
     RECT  137.408 2.148 137.512 46.452 ;
     RECT  137.512 2.352 137.704 46.248 ;
     RECT  137.704 2.352 137.801 32.76 ;
     RECT  137.704 40.128 137.843 46.248 ;
     RECT  137.843 40.128 137.873 45.672 ;
     RECT  137.873 45.168 137.945 45.672 ;
     RECT  137.801 2.352 138.733 32.664 ;
     RECT  137.704 35.808 138.764 38.808 ;
     RECT  137.873 40.128 138.764 43.944 ;
     RECT  137.704 34.08 139.021 34.776 ;
     RECT  138.764 35.808 139.045 43.944 ;
     RECT  137.945 45.168 139.045 45.192 ;
     RECT  139.021 33.648 139.057 34.776 ;
     RECT  139.045 35.808 139.057 45.192 ;
     RECT  138.733 2.256 139.093 32.664 ;
     RECT  139.057 33.648 139.093 45.192 ;
     RECT  139.093 2.256 139.381 45.192 ;
     RECT  139.381 2.256 139.673 45.624 ;
     RECT  139.673 2.544 140.245 45.624 ;
     RECT  140.245 2.544 140.249 46.2 ;
     RECT  140.249 2.64 140.329 46.2 ;
     RECT  140.329 2.64 140.537 45.624 ;
     RECT  140.537 2.64 140.969 45.384 ;
     RECT  140.969 2.64 141.401 45.192 ;
     RECT  141.401 2.64 141.437 4.536 ;
     RECT  141.401 5.52 141.581 45.192 ;
     RECT  141.437 2.64 141.793 2.664 ;
     RECT  141.581 5.52 141.797 45.048 ;
     RECT  141.793 2.592 142.405 2.664 ;
     RECT  141.437 3.696 142.405 4.536 ;
     RECT  142.405 2.592 142.513 4.536 ;
     RECT  141.797 5.52 142.513 6.12 ;
     RECT  142.513 2.592 142.808 6.12 ;
     RECT  141.797 7.2 142.808 45.048 ;
     RECT  142.808 2.148 142.912 46.452 ;
     RECT  142.912 2.418 143.104 46.182 ;
     RECT  143.104 2.592 143.201 35.208 ;
     RECT  143.201 2.64 143.26 35.208 ;
     RECT  143.104 45.936 143.267 45.96 ;
     RECT  143.104 38.112 143.273 44.472 ;
     RECT  143.26 2.64 143.525 9.096 ;
     RECT  143.26 10.128 143.705 35.208 ;
     RECT  143.705 10.128 143.741 34.104 ;
     RECT  143.273 38.112 144.457 44.328 ;
     RECT  143.705 35.184 144.493 35.208 ;
     RECT  143.104 36.24 144.493 37.128 ;
     RECT  143.525 2.64 144.533 9 ;
     RECT  144.533 2.64 144.641 8.952 ;
     RECT  144.493 35.184 144.673 37.128 ;
     RECT  144.457 38.112 144.673 44.568 ;
     RECT  144.493 45.936 144.709 45.96 ;
     RECT  143.741 10.128 144.745 31.752 ;
     RECT  143.741 32.736 144.745 34.104 ;
     RECT  144.745 10.128 144.853 34.104 ;
     RECT  144.641 2.64 145.181 8.712 ;
     RECT  144.853 10.128 145.249 34.2 ;
     RECT  144.673 35.184 145.249 44.568 ;
     RECT  145.181 8.496 145.681 8.712 ;
     RECT  145.249 10.128 145.681 44.568 ;
     RECT  144.709 45.936 145.681 46.152 ;
     RECT  145.681 8.496 146.333 46.152 ;
     RECT  146.333 8.496 146.513 45.48 ;
     RECT  146.513 8.496 146.549 45.336 ;
     RECT  146.549 8.496 146.621 45 ;
     RECT  145.181 2.64 146.689 7.224 ;
     RECT  146.689 2.496 146.725 7.224 ;
     RECT  146.621 8.496 146.725 44.904 ;
     RECT  146.725 2.496 147.769 44.904 ;
     RECT  147.517 45.936 147.769 45.96 ;
     RECT  147.769 2.496 148.208 45.96 ;
     RECT  148.208 2.148 148.312 46.452 ;
     RECT  148.312 2.4 148.504 46.182 ;
     RECT  148.504 2.4 149.537 45.288 ;
     RECT  149.537 2.592 149.893 45.288 ;
     RECT  149.893 2.592 150.005 45.624 ;
     RECT  150.005 9.408 150.937 45.624 ;
     RECT  150.005 2.592 150.977 8.28 ;
     RECT  150.977 2.88 151.513 8.28 ;
     RECT  150.937 9.408 151.513 45.816 ;
     RECT  151.513 2.88 151.621 45.816 ;
     RECT  151.621 2.88 153.241 46.68 ;
     RECT  153.241 2.832 153.608 46.68 ;
     RECT  153.608 2.148 153.712 46.68 ;
     RECT  153.712 2.352 154.469 46.68 ;
     RECT  154.469 2.832 154.829 46.68 ;
     RECT  154.829 2.976 155.549 46.68 ;
     RECT  155.549 2.976 155.729 8.28 ;
     RECT  155.729 2.976 155.977 6.12 ;
     RECT  155.977 2.784 156.181 6.12 ;
     RECT  156.181 2.256 156.269 6.12 ;
     RECT  155.729 7.344 156.733 8.28 ;
     RECT  155.549 9.6 156.733 46.68 ;
     RECT  156.269 2.592 156.949 6.12 ;
     RECT  156.949 2.592 157.021 6.168 ;
     RECT  156.733 7.344 157.021 46.68 ;
     RECT  157.021 2.592 157.813 46.68 ;
     RECT  157.813 2.4 157.82 46.68 ;
     RECT  157.82 2.256 157.907 46.68 ;
     RECT  157.907 2.4 159.008 46.68 ;
     RECT  159.008 2.148 159.112 46.68 ;
     RECT  159.112 2.418 159.304 46.68 ;
     RECT  159.304 3.024 159.365 10.152 ;
     RECT  159.365 3.888 159.443 10.152 ;
     RECT  159.304 16.896 159.443 46.68 ;
     RECT  159.443 16.896 159.617 18.6 ;
     RECT  159.443 8.976 159.653 10.152 ;
     RECT  159.443 19.824 159.689 46.68 ;
     RECT  159.653 8.976 159.724 9 ;
     RECT  159.443 3.888 159.725 7.992 ;
     RECT  159.617 16.896 159.725 17.208 ;
     RECT  159.725 7.104 159.761 7.992 ;
     RECT  159.304 11.136 159.797 14.184 ;
     RECT  159.797 12.48 159.833 14.184 ;
     RECT  159.761 7.104 159.869 7.128 ;
     RECT  159.725 3.888 159.905 6.12 ;
     RECT  159.833 12.48 159.941 12.792 ;
     RECT  159.797 11.136 159.977 11.4 ;
     RECT  159.905 6.096 160.013 6.12 ;
     RECT  159.653 10.128 160.013 10.152 ;
     RECT  159.905 3.888 160.193 5.064 ;
     RECT  159.833 14.16 160.229 14.184 ;
     RECT  160.193 5.04 160.373 5.064 ;
     RECT  159.689 20.448 160.409 46.68 ;
     RECT  160.409 20.448 160.481 40.104 ;
     RECT  160.481 20.448 160.595 36.84 ;
     RECT  160.481 37.824 160.595 40.104 ;
     RECT  159.304 15.36 160.597 15.48 ;
     RECT  160.595 20.448 160.625 36.552 ;
     RECT  159.725 16.896 160.643 17.16 ;
     RECT  160.597 15.36 160.661 15.528 ;
     RECT  160.409 41.136 160.661 46.68 ;
     RECT  160.661 15.504 160.684 15.528 ;
     RECT  160.643 17.136 160.697 17.16 ;
     RECT  160.625 20.544 160.697 36.552 ;
     RECT  160.193 3.888 160.769 3.912 ;
     RECT  159.977 11.376 160.769 11.4 ;
     RECT  160.661 42.768 160.769 46.68 ;
     RECT  160.697 20.544 160.805 20.568 ;
     RECT  159.617 18.24 160.877 18.6 ;
     RECT  160.697 21.6 160.877 36.552 ;
     RECT  160.661 41.136 160.913 41.592 ;
     RECT  160.877 21.6 160.949 34.824 ;
     RECT  160.877 18.432 160.985 18.6 ;
     RECT  159.941 12.768 161.057 12.792 ;
     RECT  160.949 29.088 161.129 34.824 ;
     RECT  161.129 31.344 161.165 34.824 ;
     RECT  161.165 31.392 161.171 34.824 ;
     RECT  161.129 29.088 161.267 30.312 ;
     RECT  160.769 42.768 161.309 43.944 ;
     RECT  160.595 37.824 161.315 38.76 ;
     RECT  160.949 21.6 161.381 28.104 ;
     RECT  161.309 42.912 161.381 43.944 ;
     RECT  160.769 45.12 161.381 46.68 ;
     RECT  160.985 18.576 161.453 18.6 ;
     RECT  161.381 23.184 161.453 28.104 ;
     RECT  160.595 40.08 161.453 40.104 ;
     RECT  161.171 31.872 161.489 34.824 ;
     RECT  161.381 42.912 161.489 43.896 ;
     RECT  161.489 31.872 161.597 34.248 ;
     RECT  160.913 41.568 161.629 41.592 ;
     RECT  160.877 35.904 161.669 36.552 ;
     RECT  161.669 36.432 161.797 36.552 ;
     RECT  161.315 37.824 161.797 38.664 ;
     RECT  161.453 23.712 161.813 28.104 ;
     RECT  161.597 34.224 161.813 34.248 ;
     RECT  161.381 21.6 161.881 22.2 ;
     RECT  161.797 36.432 161.885 38.664 ;
     RECT  161.813 23.712 161.891 26.808 ;
     RECT  161.885 37.488 161.891 38.664 ;
     RECT  161.605 40.368 161.953 40.488 ;
     RECT  161.629 41.568 161.953 41.64 ;
     RECT  161.267 29.136 162.169 30.312 ;
     RECT  161.597 31.872 162.169 33.24 ;
     RECT  161.881 9.744 162.421 9.768 ;
     RECT  161.881 21.36 162.421 22.2 ;
     RECT  161.813 27.792 162.421 28.104 ;
     RECT  162.169 29.136 162.421 33.24 ;
     RECT  162.421 2.208 162.457 2.232 ;
     RECT  162.421 3.552 162.457 3.576 ;
     RECT  161.881 4.656 162.457 4.68 ;
     RECT  162.421 6 162.457 8.712 ;
     RECT  162.421 9.744 162.457 10.584 ;
     RECT  161.881 11.664 162.457 11.688 ;
     RECT  162.421 13.824 162.457 14.616 ;
     RECT  161.881 15.696 162.457 15.72 ;
     RECT  162.421 17.568 162.457 17.592 ;
     RECT  162.421 20.256 162.457 22.2 ;
     RECT  161.891 23.712 162.457 26.76 ;
     RECT  161.891 37.776 162.457 38.664 ;
     RECT  161.953 40.368 162.457 41.64 ;
     RECT  161.489 42.912 162.457 43.176 ;
     RECT  161.381 45.792 162.457 46.68 ;
     RECT  162.457 1.68 162.493 17.592 ;
     RECT  162.457 44.784 162.493 46.68 ;
     RECT  162.457 40.224 162.709 43.176 ;
     RECT  162.493 1.152 162.997 17.592 ;
     RECT  162.673 18.672 162.997 18.696 ;
     RECT  162.457 20.256 162.997 26.76 ;
     RECT  162.421 27.792 162.997 33.24 ;
     RECT  162.997 1.152 163.033 33.24 ;
     RECT  162.457 34.56 163.033 34.584 ;
     RECT  161.885 36.432 163.033 36.456 ;
     RECT  162.709 40.224 163.033 43.464 ;
     RECT  162.493 44.496 163.033 46.68 ;
     RECT  163.033 35.904 163.105 36.744 ;
     RECT  162.457 37.776 163.105 39.144 ;
     RECT  163.033 1.152 163.573 34.584 ;
     RECT  163.105 35.904 163.573 39.144 ;
     RECT  163.033 40.224 163.573 46.68 ;
     RECT  163.573 1.152 163.98 47.496 ;
    LAYER M5 ;
     RECT  2.4 2.137 2.52 2.151 ;
     RECT  7.8 2.137 7.92 2.151 ;
     RECT  13.2 2.137 13.32 2.151 ;
     RECT  18.6 2.137 18.72 2.151 ;
     RECT  24 2.137 24.12 2.151 ;
     RECT  29.4 2.137 29.52 2.151 ;
     RECT  34.8 2.137 34.92 2.151 ;
     RECT  40.2 2.137 40.32 2.151 ;
     RECT  45.6 2.137 45.72 2.151 ;
     RECT  51 2.137 51.12 2.151 ;
     RECT  56.4 2.137 56.52 2.151 ;
     RECT  61.8 2.137 61.92 2.151 ;
     RECT  67.2 2.137 67.32 2.151 ;
     RECT  72.6 2.137 72.72 2.151 ;
     RECT  78 2.137 78.12 2.151 ;
     RECT  83.4 2.137 83.52 2.151 ;
     RECT  88.8 2.137 88.92 2.151 ;
     RECT  94.2 2.137 94.32 2.151 ;
     RECT  99.6 2.137 99.72 2.151 ;
     RECT  105 2.137 105.12 2.151 ;
     RECT  110.4 2.137 110.52 2.151 ;
     RECT  115.8 2.137 115.92 2.151 ;
     RECT  121.2 2.137 121.32 2.151 ;
     RECT  126.6 2.137 126.72 2.151 ;
     RECT  132 2.137 132.12 2.151 ;
     RECT  137.4 2.137 137.52 2.151 ;
     RECT  142.8 2.137 142.92 2.151 ;
     RECT  148.2 2.137 148.32 2.151 ;
     RECT  153.6 2.137 153.72 2.151 ;
     RECT  159 2.137 159.12 2.151 ;
     RECT  24 2.151 24.312 2.245 ;
     RECT  67.2 2.151 67.512 2.245 ;
     RECT  94.2 2.151 94.512 2.245 ;
     RECT  99.6 2.151 99.912 2.293 ;
     RECT  110.4 2.151 110.712 2.437 ;
     RECT  99.408 2.293 99.912 2.483 ;
     RECT  56.4 2.151 56.712 2.485 ;
     RECT  43.728 2.389 43.752 2.531 ;
     RECT  4.896 2.245 4.92 2.533 ;
     RECT  109.968 2.437 110.712 2.579 ;
     RECT  45.6 2.151 45.912 2.629 ;
     RECT  88.8 2.151 89.112 2.629 ;
     RECT  61.8 2.151 62.112 2.677 ;
     RECT  74.064 2.245 74.088 2.677 ;
     RECT  67.2 2.245 67.608 2.725 ;
     RECT  15.648 2.629 15.672 2.771 ;
     RECT  73.968 2.677 74.088 2.771 ;
     RECT  6.576 2.245 6.6 2.773 ;
     RECT  29.4 2.151 29.712 2.821 ;
     RECT  34.8 2.151 35.112 2.821 ;
     RECT  124.32 2.533 124.344 2.821 ;
     RECT  153.6 2.151 153.912 2.821 ;
     RECT  122.928 2.533 122.952 2.867 ;
     RECT  99.504 2.483 99.912 2.963 ;
     RECT  40.2 2.151 40.512 2.965 ;
     RECT  157.872 2.245 157.896 3.059 ;
     RECT  4.272 2.533 4.92 3.061 ;
     RECT  6.48 2.773 6.6 3.061 ;
     RECT  40.08 2.965 40.512 3.109 ;
     RECT  115.8 2.151 116.112 3.109 ;
     RECT  61.008 2.677 62.112 3.155 ;
     RECT  31.056 3.013 31.08 3.203 ;
     RECT  4.272 3.061 6.6 3.253 ;
     RECT  40.08 3.109 40.728 3.253 ;
     RECT  4.272 3.253 6.792 3.301 ;
     RECT  7.8 2.151 8.112 3.301 ;
     RECT  97.344 3.157 97.368 3.301 ;
     RECT  153.6 2.821 154.68 3.301 ;
     RECT  115.8 3.109 116.472 3.347 ;
     RECT  137.4 2.151 137.712 3.349 ;
     RECT  148.2 2.151 148.512 3.349 ;
     RECT  4.272 3.301 8.112 3.397 ;
     RECT  105 2.151 105.312 3.397 ;
     RECT  148.2 3.349 148.728 3.397 ;
     RECT  159 2.151 159.312 3.397 ;
     RECT  88.704 2.629 89.112 3.443 ;
     RECT  97.2 3.301 97.368 3.443 ;
     RECT  31.488 3.445 31.608 3.493 ;
     RECT  3.984 3.397 8.112 3.539 ;
     RECT  93.504 2.245 94.512 3.539 ;
     RECT  95.712 2.293 95.736 3.539 ;
     RECT  121.2 2.151 121.512 3.541 ;
     RECT  34.8 2.821 35.88 3.587 ;
     RECT  27.312 3.157 27.336 3.589 ;
     RECT  40.08 3.253 41.064 3.589 ;
     RECT  47.568 3.541 47.592 3.589 ;
     RECT  16.944 2.629 16.968 3.637 ;
     RECT  31.488 3.493 31.848 3.683 ;
     RECT  39.648 3.589 41.064 3.683 ;
     RECT  104.64 3.397 105.312 3.683 ;
     RECT  124.32 2.821 125.016 3.683 ;
     RECT  129.36 3.349 129.384 3.683 ;
     RECT  134.544 3.397 134.76 3.683 ;
     RECT  97.344 3.443 97.368 3.685 ;
     RECT  118.08 2.821 118.104 3.685 ;
     RECT  26.784 3.589 27.336 3.731 ;
     RECT  31.488 3.683 31.608 3.731 ;
     RECT  34.8 3.587 35.544 3.731 ;
     RECT  118.08 3.685 118.536 3.731 ;
     RECT  16.704 3.637 16.968 3.733 ;
     RECT  49.056 3.685 49.08 3.827 ;
     RECT  64.08 2.773 64.104 3.827 ;
     RECT  45.168 2.629 45.912 3.829 ;
     RECT  47.424 3.589 47.592 3.829 ;
     RECT  51 2.151 51.312 3.829 ;
     RECT  92.928 3.781 92.952 3.829 ;
     RECT  124.992 3.683 125.016 3.829 ;
     RECT  126.6 2.151 126.912 3.829 ;
     RECT  87.456 2.293 87.48 3.877 ;
     RECT  158.688 3.397 159.312 3.877 ;
     RECT  55.008 3.781 55.032 3.923 ;
     RECT  92.304 3.829 92.952 3.923 ;
     RECT  104.88 3.683 105.312 3.923 ;
     RECT  5.616 3.539 8.112 3.925 ;
     RECT  42.336 2.341 42.36 3.925 ;
     RECT  45.168 3.829 47.592 3.925 ;
     RECT  75.792 2.821 76.488 3.925 ;
     RECT  121.2 3.541 121.608 3.925 ;
     RECT  44.352 3.925 47.592 3.971 ;
     RECT  64.176 3.829 65.064 3.971 ;
     RECT  97.344 3.685 97.848 3.971 ;
     RECT  39.648 3.683 40.872 4.019 ;
     RECT  51 3.829 52.056 4.019 ;
     RECT  44.352 3.971 46.728 4.021 ;
     RECT  153.504 3.301 154.68 4.115 ;
     RECT  158.688 3.877 159.432 4.117 ;
     RECT  44.016 4.021 46.728 4.163 ;
     RECT  48.336 3.973 48.456 4.163 ;
     RECT  136.272 3.397 136.296 4.165 ;
     RECT  137.4 3.349 138.024 4.165 ;
     RECT  44.352 4.163 46.728 4.211 ;
     RECT  48.432 4.163 48.456 4.211 ;
     RECT  92.304 3.923 92.328 4.211 ;
     RECT  16.704 3.733 17.112 4.307 ;
     RECT  56.4 2.485 56.808 4.451 ;
     RECT  136.272 4.165 138.024 4.453 ;
     RECT  73.968 2.771 73.992 4.499 ;
     RECT  140.16 4.357 140.184 4.499 ;
     RECT  75.792 3.925 76.92 4.501 ;
     RECT  92.112 4.405 92.136 4.501 ;
     RECT  121.2 3.925 122.376 4.501 ;
     RECT  132 2.151 132.312 4.501 ;
     RECT  157.728 4.117 159.432 4.501 ;
     RECT  92.016 4.501 92.136 4.547 ;
     RECT  121.2 4.501 122.568 4.547 ;
     RECT  136.272 4.453 138.744 4.547 ;
     RECT  60 3.109 60.024 4.595 ;
     RECT  75.168 4.501 76.92 4.595 ;
     RECT  24 2.245 25.08 4.643 ;
     RECT  76.464 4.595 76.92 4.643 ;
     RECT  3.984 3.539 4.536 4.691 ;
     RECT  86.544 3.877 87.48 4.693 ;
     RECT  134.736 3.683 134.76 4.693 ;
     RECT  157.728 4.501 159.576 4.693 ;
     RECT  86.544 4.693 87.768 4.739 ;
     RECT  39.648 4.019 40.512 4.741 ;
     RECT  122.544 4.547 122.568 4.741 ;
     RECT  88.8 3.443 89.112 4.789 ;
     RECT  39.552 4.741 40.512 4.883 ;
     RECT  37.392 2.629 37.416 4.885 ;
     RECT  153.504 4.115 153.912 4.933 ;
     RECT  41.952 3.925 42.36 4.979 ;
     RECT  86.544 4.739 86.712 4.979 ;
     RECT  2.4 2.151 2.712 5.029 ;
     RECT  148.2 3.397 148.824 5.029 ;
     RECT  156.192 2.245 156.216 5.029 ;
     RECT  36.816 4.885 37.416 5.075 ;
     RECT  40.08 4.883 40.512 5.075 ;
     RECT  27.312 3.731 27.336 5.077 ;
     RECT  64.176 3.971 64.968 5.077 ;
     RECT  144.288 3.925 144.312 5.077 ;
     RECT  122.544 4.741 122.904 5.123 ;
     RECT  147.84 5.029 148.824 5.123 ;
     RECT  4.272 4.691 4.536 5.125 ;
     RECT  5.616 3.925 8.856 5.125 ;
     RECT  76.464 4.643 76.488 5.171 ;
     RECT  79.632 4.405 79.656 5.171 ;
     RECT  97.488 3.971 97.848 5.171 ;
     RECT  157.728 4.693 159.864 5.171 ;
     RECT  72.6 2.151 72.912 5.173 ;
     RECT  75.168 4.595 75.192 5.219 ;
     RECT  155.808 5.029 156.216 5.219 ;
     RECT  27.312 5.077 27.816 5.221 ;
     RECT  51 4.019 51.96 5.317 ;
     RECT  53.04 5.221 53.064 5.317 ;
     RECT  59.904 5.173 59.928 5.317 ;
     RECT  133.584 5.173 133.608 5.411 ;
     RECT  56.4 4.451 56.712 5.413 ;
     RECT  20.256 3.397 20.28 5.459 ;
     RECT  157.728 5.171 159.576 5.459 ;
     RECT  88.8 4.789 90.072 5.507 ;
     RECT  59.376 5.317 59.928 5.509 ;
     RECT  51 5.317 53.064 5.555 ;
     RECT  58.176 2.869 58.2 5.555 ;
     RECT  49.008 5.173 49.032 5.557 ;
     RECT  99.6 2.963 99.912 5.557 ;
     RECT  124.992 3.829 126.912 5.605 ;
     RECT  118.512 3.731 118.536 5.699 ;
     RECT  136.896 4.547 138.744 5.701 ;
     RECT  67.2 2.725 67.704 5.747 ;
     RECT  56.4 5.413 56.808 5.797 ;
     RECT  86.688 4.979 86.712 5.843 ;
     RECT  144.24 5.077 144.312 5.891 ;
     RECT  15.648 4.261 15.672 5.893 ;
     RECT  16.704 4.307 16.728 5.893 ;
     RECT  16.704 5.893 17.064 5.939 ;
     RECT  11.28 2.821 11.304 5.989 ;
     RECT  115.8 3.347 116.112 5.989 ;
     RECT  124.848 5.605 126.912 5.989 ;
     RECT  15.6 5.893 15.672 6.035 ;
     RECT  17.04 5.939 17.064 6.035 ;
     RECT  29.184 2.821 29.712 6.035 ;
     RECT  11.28 5.989 11.928 6.037 ;
     RECT  70.368 2.533 70.392 6.037 ;
     RECT  76.32 5.701 76.344 6.037 ;
     RECT  155.808 5.219 155.832 6.083 ;
     RECT  22.896 5.269 22.92 6.085 ;
     RECT  24 4.643 24.312 6.085 ;
     RECT  49.008 5.557 49.56 6.131 ;
     RECT  69.888 6.037 70.392 6.133 ;
     RECT  131.088 4.501 132.312 6.133 ;
     RECT  150.864 5.845 150.888 6.179 ;
     RECT  56.4 5.797 57 6.181 ;
     RECT  146.448 3.685 146.472 6.227 ;
     RECT  18.6 2.151 18.912 6.229 ;
     RECT  42.336 4.979 42.36 6.229 ;
     RECT  94.2 3.539 94.512 6.229 ;
     RECT  109.104 5.989 109.128 6.229 ;
     RECT  147.84 5.123 148.728 6.229 ;
     RECT  22.896 6.085 24.312 6.275 ;
     RECT  51 5.555 51.432 6.275 ;
     RECT  124.848 5.989 127.032 6.275 ;
     RECT  130.992 6.133 132.312 6.275 ;
     RECT  144.24 5.891 144.264 6.275 ;
     RECT  41.616 6.229 42.36 6.323 ;
     RECT  54.672 5.125 54.696 6.323 ;
     RECT  63.792 5.077 64.968 6.323 ;
     RECT  69.792 6.133 70.392 6.323 ;
     RECT  99.6 5.557 100.008 6.323 ;
     RECT  128.592 5.173 128.616 6.323 ;
     RECT  61.536 3.155 62.112 6.371 ;
     RECT  147.6 6.229 148.728 6.421 ;
     RECT  61.584 6.371 62.112 6.469 ;
     RECT  63.792 6.323 64.2 6.469 ;
     RECT  75.984 6.037 76.344 6.517 ;
     RECT  122.544 5.123 122.568 6.565 ;
     RECT  27.312 5.221 28.104 6.611 ;
     RECT  94.032 6.229 94.512 6.613 ;
     RECT  33.024 2.821 33.048 6.661 ;
     RECT  72.48 5.173 72.912 6.661 ;
     RECT  44.352 4.211 45.912 6.707 ;
     RECT  53.04 6.565 53.064 6.707 ;
     RECT  61.584 6.469 64.2 6.707 ;
     RECT  85.296 5.989 85.32 6.709 ;
     RECT  103.776 4.453 103.8 6.709 ;
     RECT  105 3.923 105.312 6.709 ;
     RECT  49.008 6.131 49.128 6.755 ;
     RECT  2.304 5.029 2.712 6.805 ;
     RECT  4.272 5.125 8.856 6.805 ;
     RECT  37.392 5.075 37.416 6.805 ;
     RECT  142.8 2.151 143.112 6.805 ;
     RECT  157.728 5.459 159.312 6.805 ;
     RECT  85.296 6.709 85.656 6.851 ;
     RECT  94.032 6.613 94.68 6.851 ;
     RECT  115.8 5.989 116.232 6.851 ;
     RECT  130.992 6.275 131.016 6.851 ;
     RECT  132 6.275 132.312 6.853 ;
     RECT  2.304 6.805 8.856 6.899 ;
     RECT  56.4 6.181 57.144 6.899 ;
     RECT  63.792 6.707 64.2 6.899 ;
     RECT  152.832 4.933 153.912 6.899 ;
     RECT  83.4 2.151 83.712 6.901 ;
     RECT  85.296 6.851 85.32 6.901 ;
     RECT  90.576 6.181 90.648 6.901 ;
     RECT  124.848 6.275 126.912 6.947 ;
     RECT  40.2 5.075 40.512 6.997 ;
     RECT  41.616 6.323 42.216 6.997 ;
     RECT  59.28 5.509 59.928 7.043 ;
     RECT  90.288 6.901 90.648 7.043 ;
     RECT  40.2 6.997 42.216 7.091 ;
     RECT  46.944 5.653 46.968 7.091 ;
     RECT  108.432 6.229 109.128 7.091 ;
     RECT  147.6 6.421 148.776 7.091 ;
     RECT  29.4 6.035 29.712 7.093 ;
     RECT  103.776 6.709 105.312 7.141 ;
     RECT  128.784 6.613 128.808 7.141 ;
     RECT  83.4 6.901 85.32 7.187 ;
     RECT  59.808 7.043 59.928 7.189 ;
     RECT  114.576 6.325 114.6 7.331 ;
     RECT  134.736 4.693 134.808 7.331 ;
     RECT  157.728 6.805 159.432 7.331 ;
     RECT  13.2 2.151 13.512 7.333 ;
     RECT  37.296 6.805 37.416 7.333 ;
     RECT  121.2 4.547 121.512 7.333 ;
     RECT  11.184 6.037 11.928 7.379 ;
     RECT  128.784 7.141 128.856 7.379 ;
     RECT  142.8 6.805 143.592 7.379 ;
     RECT  23.664 6.275 24.312 7.381 ;
     RECT  29.4 7.093 30.072 7.381 ;
     RECT  49.104 6.755 49.128 7.381 ;
     RECT  51 6.275 51.312 7.381 ;
     RECT  2.4 6.899 8.856 7.427 ;
     RECT  119.712 4.501 119.736 7.427 ;
     RECT  4.272 7.427 8.856 7.475 ;
     RECT  13.2 7.333 13.656 7.477 ;
     RECT  5.808 7.475 8.856 7.523 ;
     RECT  44.352 6.707 44.472 7.523 ;
     RECT  90.624 7.043 90.648 7.523 ;
     RECT  97.632 5.171 97.848 7.571 ;
     RECT  33.024 6.661 33.768 7.619 ;
     RECT  44.448 7.523 44.472 7.619 ;
     RECT  103.584 7.141 105.312 7.619 ;
     RECT  122.544 6.565 122.616 7.619 ;
     RECT  136.8 5.701 138.744 7.619 ;
     RECT  37.296 7.333 38.328 7.621 ;
     RECT  153.6 6.899 153.912 7.621 ;
     RECT  155.04 6.229 155.064 7.621 ;
     RECT  13.104 7.477 13.656 7.667 ;
     RECT  153.6 7.621 155.064 7.667 ;
     RECT  34.8 3.731 35.112 7.669 ;
     RECT  37.296 7.621 38.568 7.715 ;
     RECT  15.648 6.035 15.672 7.859 ;
     RECT  23.04 7.381 24.312 7.859 ;
     RECT  152.448 7.381 152.472 7.861 ;
     RECT  53.472 7.669 53.496 7.909 ;
     RECT  49.104 7.381 51.312 7.955 ;
     RECT  136.8 7.619 137.976 7.955 ;
     RECT  13.2 7.667 13.656 7.957 ;
     RECT  38.544 7.715 38.568 7.957 ;
     RECT  58.128 7.381 58.152 7.957 ;
     RECT  99.6 6.323 99.912 7.957 ;
     RECT  128.784 7.379 128.808 7.957 ;
     RECT  158.4 7.331 159.432 7.957 ;
     RECT  61.584 6.707 62.28 8.003 ;
     RECT  69.792 6.323 70.2 8.003 ;
     RECT  151.584 7.861 152.472 8.003 ;
     RECT  153.6 7.667 154.44 8.003 ;
     RECT  111.744 6.181 111.768 8.005 ;
     RECT  124.848 6.947 125.016 8.005 ;
     RECT  128.256 7.957 128.808 8.051 ;
     RECT  132 6.853 132.408 8.051 ;
     RECT  120.864 7.333 121.512 8.053 ;
     RECT  122.544 7.619 122.568 8.053 ;
     RECT  75.84 6.517 76.344 8.147 ;
     RECT  85.488 8.005 85.512 8.147 ;
     RECT  103.776 7.619 105.312 8.147 ;
     RECT  108.528 7.091 109.128 8.147 ;
     RECT  107.136 6.757 107.16 8.149 ;
     RECT  29.4 7.381 30.936 8.195 ;
     RECT  106.656 8.149 107.16 8.195 ;
     RECT  111.744 8.005 112.536 8.195 ;
     RECT  134.736 7.331 134.76 8.195 ;
     RECT  103.776 8.147 103.8 8.243 ;
     RECT  140.88 7.237 140.904 8.243 ;
     RECT  147.792 7.091 148.776 8.243 ;
     RECT  124.848 8.005 125.448 8.245 ;
     RECT  48.48 8.005 48.504 8.291 ;
     RECT  109.104 8.147 109.128 8.291 ;
     RECT  13.2 7.957 13.704 8.293 ;
     RECT  158.4 7.957 159.672 8.293 ;
     RECT  29.4 8.195 29.712 8.341 ;
     RECT  133.392 6.757 133.416 8.435 ;
     RECT  2.4 7.427 2.808 8.485 ;
     RECT  4.272 7.475 4.44 8.485 ;
     RECT  69.792 8.003 69.816 8.485 ;
     RECT  30.912 8.195 30.936 8.531 ;
     RECT  120.864 8.053 122.568 8.531 ;
     RECT  124.368 8.245 125.448 8.531 ;
     RECT  120.96 8.531 122.568 8.579 ;
     RECT  147.792 8.243 148.512 8.771 ;
     RECT  53.472 7.909 54.072 8.821 ;
     RECT  55.056 6.325 55.08 8.821 ;
     RECT  153.6 8.003 153.912 8.821 ;
     RECT  42.192 7.091 42.216 8.867 ;
     RECT  58.128 7.957 58.2 8.915 ;
     RECT  53.472 8.821 55.08 8.963 ;
     RECT  97.632 7.571 97.656 8.963 ;
     RECT  128.256 8.051 128.28 8.963 ;
     RECT  152.736 8.821 153.912 8.963 ;
     RECT  29.088 8.341 29.712 9.011 ;
     RECT  120.96 8.579 121.512 9.011 ;
     RECT  158.304 8.293 159.672 9.011 ;
     RECT  67.2 5.747 67.512 9.013 ;
     RECT  80.016 8.821 80.04 9.059 ;
     RECT  156.768 7.333 156.792 9.059 ;
     RECT  38.544 7.957 39.192 9.061 ;
     RECT  40.2 7.091 41.112 9.061 ;
     RECT  115.8 6.851 116.112 9.061 ;
     RECT  142.8 7.379 143.112 9.061 ;
     RECT  153.6 8.963 153.912 9.061 ;
     RECT  48.864 8.965 48.888 9.107 ;
     RECT  59.808 7.189 60.408 9.107 ;
     RECT  56.4 6.899 56.808 9.109 ;
     RECT  145.968 8.485 145.992 9.155 ;
     RECT  2.4 8.485 4.44 9.157 ;
     RECT  37.296 7.715 37.32 9.157 ;
     RECT  2.4 9.157 4.728 9.203 ;
     RECT  158.304 9.011 159.312 9.203 ;
     RECT  53.472 8.963 53.592 9.205 ;
     RECT  5.808 7.523 8.616 9.301 ;
     RECT  45.6 6.707 45.912 9.301 ;
     RECT  27.312 6.611 27.336 9.395 ;
     RECT  53.04 9.205 53.592 9.395 ;
     RECT  106.656 8.195 106.68 9.395 ;
     RECT  2.4 9.203 2.808 9.397 ;
     RECT  45.504 9.301 45.912 9.443 ;
     RECT  5.808 9.301 8.952 9.541 ;
     RECT  56.4 9.109 56.856 9.541 ;
     RECT  37.056 9.157 37.32 9.587 ;
     RECT  60.384 9.107 60.408 9.587 ;
     RECT  3.888 9.203 4.728 9.589 ;
     RECT  5.808 9.541 9 9.589 ;
     RECT  24 7.859 24.312 9.589 ;
     RECT  137.4 7.955 137.976 9.589 ;
     RECT  54.672 8.963 55.08 9.635 ;
     RECT  76.32 8.147 76.344 9.637 ;
     RECT  141.312 9.061 141.336 9.637 ;
     RECT  3.888 9.589 9 9.731 ;
     RECT  82.32 4.837 82.344 9.731 ;
     RECT  33.024 7.619 33.048 9.779 ;
     RECT  141.024 9.637 141.336 9.779 ;
     RECT  133.824 9.013 133.848 10.067 ;
     RECT  126.6 6.947 126.912 10.069 ;
     RECT  125.136 8.531 125.448 10.115 ;
     RECT  153.6 9.061 154.488 10.115 ;
     RECT  98.928 7.957 99.912 10.117 ;
     RECT  125.424 10.115 125.448 10.117 ;
     RECT  126.48 10.069 126.912 10.117 ;
     RECT  7.584 9.731 9 10.213 ;
     RECT  24 9.589 24.552 10.213 ;
     RECT  67.104 9.013 67.512 10.213 ;
     RECT  115.152 9.061 116.112 10.213 ;
     RECT  121.2 9.011 121.512 10.213 ;
     RECT  151.776 9.637 151.8 10.213 ;
     RECT  96.624 9.637 96.648 10.355 ;
     RECT  151.776 10.213 151.944 10.355 ;
     RECT  2.304 9.397 2.808 10.405 ;
     RECT  105 8.147 105.312 10.405 ;
     RECT  104.784 10.405 105.312 10.453 ;
     RECT  3.888 9.731 6.504 10.499 ;
     RECT  104.784 10.453 105.528 10.547 ;
     RECT  117.744 9.637 117.768 10.595 ;
     RECT  58.128 8.915 58.152 10.597 ;
     RECT  110.4 2.579 110.712 10.597 ;
     RECT  111.744 8.195 112.296 10.597 ;
     RECT  110.4 10.597 112.296 10.643 ;
     RECT  114.72 10.213 116.112 10.643 ;
     RECT  94.032 6.851 94.512 10.645 ;
     RECT  69.552 8.485 69.816 10.691 ;
     RECT  2.304 10.405 2.856 10.741 ;
     RECT  3.888 10.499 5.976 10.741 ;
     RECT  13.2 8.293 14.52 10.741 ;
     RECT  78 2.151 78.312 10.741 ;
     RECT  7.584 10.213 9.672 10.789 ;
     RECT  81.648 10.741 81.672 10.837 ;
     RECT  83.4 7.187 83.712 10.837 ;
     RECT  6.96 10.789 9.672 10.883 ;
     RECT  67.104 10.213 67.8 10.883 ;
     RECT  155.664 10.069 155.688 10.883 ;
     RECT  150.192 10.357 150.216 10.885 ;
     RECT  150.192 10.885 150.36 10.931 ;
     RECT  110.4 10.643 112.008 10.933 ;
     RECT  6.96 10.883 9 11.027 ;
     RECT  72.432 6.661 72.912 11.029 ;
     RECT  76.032 9.637 76.344 11.029 ;
     RECT  77.328 10.741 78.312 11.029 ;
     RECT  120.864 10.213 121.512 11.075 ;
     RECT  151.872 10.355 151.944 11.123 ;
     RECT  18.432 6.229 18.912 11.125 ;
     RECT  121.2 11.075 121.512 11.125 ;
     RECT  122.544 8.579 122.568 11.125 ;
     RECT  56.4 9.541 56.904 11.173 ;
     RECT  58.128 10.597 58.2 11.173 ;
     RECT  61.8 8.003 62.28 11.219 ;
     RECT  76.032 11.029 78.312 11.221 ;
     RECT  118.56 10.741 118.584 11.315 ;
     RECT  142.8 9.061 143.208 11.363 ;
     RECT  144.624 10.501 144.648 11.363 ;
     RECT  55.056 9.635 55.08 11.365 ;
     RECT  56.4 11.173 58.2 11.365 ;
     RECT  108.048 10.741 108.072 11.365 ;
     RECT  141.024 9.779 141.048 11.365 ;
     RECT  98.928 10.117 100.2 11.413 ;
     RECT  50.064 7.955 51.312 11.459 ;
     RECT  125.424 10.117 126.912 11.459 ;
     RECT  69.792 10.691 69.816 11.461 ;
     RECT  147.84 8.771 148.512 11.461 ;
     RECT  69.792 11.461 70.104 11.507 ;
     RECT  106.848 9.925 106.872 11.507 ;
     RECT  126.48 11.459 126.912 11.507 ;
     RECT  81.648 10.837 83.712 11.509 ;
     RECT  38.544 9.061 41.112 11.557 ;
     RECT  38.304 11.557 41.112 11.603 ;
     RECT  104.88 10.547 105.528 11.605 ;
     RECT  60.144 10.261 60.168 11.653 ;
     RECT  126.6 11.507 126.912 11.653 ;
     RECT  151.92 11.123 151.944 11.653 ;
     RECT  153.6 10.115 153.912 11.653 ;
     RECT  72.384 11.029 72.912 11.699 ;
     RECT  151.92 11.653 154.344 11.701 ;
     RECT  114.72 10.643 114.744 11.747 ;
     RECT  55.056 11.365 58.2 11.795 ;
     RECT  80.784 11.509 83.712 11.795 ;
     RECT  150.288 10.931 150.36 11.795 ;
     RECT  151.92 11.701 154.44 11.795 ;
     RECT  153.6 11.795 154.44 11.843 ;
     RECT  17.76 11.125 18.912 11.845 ;
     RECT  17.76 11.845 19.32 11.893 ;
     RECT  67.2 10.883 67.8 11.893 ;
     RECT  27.792 11.029 27.816 11.941 ;
     RECT  29.28 9.011 29.712 11.941 ;
     RECT  56.4 11.795 58.2 11.941 ;
     RECT  64.176 6.899 64.2 11.941 ;
     RECT  65.568 11.365 65.592 11.941 ;
     RECT  66.672 11.893 67.8 11.941 ;
     RECT  158.4 9.203 159.312 11.941 ;
     RECT  53.568 9.395 53.592 11.987 ;
     RECT  104.784 11.605 105.528 11.987 ;
     RECT  75.984 11.221 78.312 11.989 ;
     RECT  140.256 11.365 141.048 11.989 ;
     RECT  150.336 11.795 150.36 11.989 ;
     RECT  75.84 11.989 78.312 12.035 ;
     RECT  87.744 4.739 87.768 12.035 ;
     RECT  139.68 11.989 141.048 12.035 ;
     RECT  97.68 9.013 97.704 12.037 ;
     RECT  75.84 12.035 76.008 12.085 ;
     RECT  130.416 10.453 130.44 12.085 ;
     RECT  105 11.987 105.528 12.131 ;
     RECT  121.2 11.125 122.568 12.181 ;
     RECT  34.176 7.669 35.112 12.227 ;
     RECT  70.08 11.507 70.104 12.275 ;
     RECT  98.928 11.413 100.872 12.277 ;
     RECT  120.864 12.181 122.568 12.323 ;
     RECT  12.768 10.741 14.52 12.371 ;
     RECT  96.96 12.037 97.704 12.371 ;
     RECT  106.896 11.989 106.92 12.371 ;
     RECT  120.864 12.323 122.328 12.371 ;
     RECT  139.68 12.035 139.704 12.371 ;
     RECT  31.104 11.653 31.128 12.373 ;
     RECT  93.84 10.645 94.512 12.373 ;
     RECT  95.76 11.749 95.784 12.373 ;
     RECT  64.176 11.941 67.8 12.467 ;
     RECT  98.928 12.277 101.448 12.467 ;
     RECT  130.416 12.085 130.872 12.467 ;
     RECT  2.304 10.741 5.976 12.469 ;
     RECT  6.96 11.027 8.952 12.469 ;
     RECT  61.8 11.219 62.112 12.469 ;
     RECT  110.016 10.933 112.008 12.469 ;
     RECT  158.4 11.941 159.768 12.469 ;
     RECT  92.016 4.547 92.04 12.515 ;
     RECT  150.336 11.989 150.456 12.515 ;
     RECT  158.256 12.469 159.768 12.515 ;
     RECT  81.648 11.795 83.712 12.517 ;
     RECT  88.8 5.507 89.112 12.517 ;
     RECT  130.56 12.467 130.872 12.517 ;
     RECT  132 8.051 132.312 12.517 ;
     RECT  17.76 11.893 19.464 12.563 ;
     RECT  93.84 12.373 95.784 12.563 ;
     RECT  98.928 12.467 100.872 12.563 ;
     RECT  125.424 11.459 125.448 12.563 ;
     RECT  151.92 11.795 152.232 12.563 ;
     RECT  2.304 12.469 8.952 12.611 ;
     RECT  126.6 11.653 127.032 12.611 ;
     RECT  141.024 12.035 141.048 12.611 ;
     RECT  108.048 11.365 108.552 12.659 ;
     RECT  155.856 12.517 155.88 12.659 ;
     RECT  121.008 12.371 122.328 12.707 ;
     RECT  34.704 12.227 35.112 12.755 ;
     RECT  56.4 11.941 58.488 12.755 ;
     RECT  108.528 12.659 108.552 12.755 ;
     RECT  121.104 12.707 122.328 12.755 ;
     RECT  150.336 12.515 150.36 12.755 ;
     RECT  61.584 12.469 62.112 12.757 ;
     RECT  147.84 11.461 148.728 12.757 ;
     RECT  135.984 11.989 136.008 12.853 ;
     RECT  147.84 12.757 149.016 12.899 ;
     RECT  75.792 12.085 76.008 12.995 ;
     RECT  147.84 12.899 148.728 12.995 ;
     RECT  24 10.213 24.984 13.043 ;
     RECT  75.84 12.995 76.008 13.043 ;
     RECT  85.2 10.645 85.224 13.045 ;
     RECT  93.84 12.563 95.016 13.045 ;
     RECT  37.296 9.587 37.32 13.091 ;
     RECT  135.696 12.853 136.008 13.091 ;
     RECT  64.176 12.467 64.68 13.093 ;
     RECT  93.216 13.045 95.016 13.093 ;
     RECT  81.648 12.517 84.168 13.139 ;
     RECT  146.832 12.709 146.856 13.139 ;
     RECT  152.208 12.563 152.232 13.139 ;
     RECT  93.12 13.093 95.016 13.187 ;
     RECT  136.08 13.093 136.104 13.285 ;
     RECT  137.4 9.589 138.696 13.285 ;
     RECT  79.488 11.461 79.512 13.331 ;
     RECT  50.832 11.459 51.312 13.333 ;
     RECT  72.432 11.699 72.912 13.333 ;
     RECT  136.08 13.285 138.696 13.333 ;
     RECT  60.144 11.653 60.408 13.379 ;
     RECT  130.56 12.517 132.312 13.379 ;
     RECT  38.304 11.603 40.68 13.477 ;
     RECT  105 12.131 105.432 13.477 ;
     RECT  107.136 13.045 107.16 13.477 ;
     RECT  61.536 12.757 62.112 13.523 ;
     RECT  81.648 13.139 81.672 13.523 ;
     RECT  121.104 12.755 121.512 13.571 ;
     RECT  83.4 13.139 84.168 13.573 ;
     RECT  50.832 13.333 52.248 13.619 ;
     RECT  61.584 13.523 62.112 13.619 ;
     RECT  18.432 12.563 19.464 13.621 ;
     RECT  99.6 12.563 100.056 13.621 ;
     RECT  115.8 10.643 116.112 13.621 ;
     RECT  140.208 13.333 140.232 13.621 ;
     RECT  142.8 11.363 143.112 13.621 ;
     RECT  27.792 11.941 29.712 13.667 ;
     RECT  136.08 13.333 139.128 13.667 ;
     RECT  115.8 13.621 116.232 13.669 ;
     RECT  123.984 11.989 124.008 13.669 ;
     RECT  125.376 13.381 125.4 13.669 ;
     RECT  25.968 9.637 25.992 13.715 ;
     RECT  28.512 13.667 29.712 13.715 ;
     RECT  38.304 13.477 40.968 13.715 ;
     RECT  97.68 12.371 97.704 13.715 ;
     RECT  134.64 13.429 134.664 13.717 ;
     RECT  128.928 13.621 128.952 13.811 ;
     RECT  134.448 13.717 134.664 13.811 ;
     RECT  136.176 13.667 139.128 13.811 ;
     RECT  115.8 13.669 116.328 13.813 ;
     RECT  87.6 13.093 87.624 13.859 ;
     RECT  134.448 13.811 134.472 13.859 ;
     RECT  40.2 13.715 40.968 13.861 ;
     RECT  105 13.477 107.16 13.861 ;
     RECT  34.8 12.755 35.112 13.909 ;
     RECT  66.48 12.467 67.8 13.909 ;
     RECT  99.6 13.621 100.872 13.909 ;
     RECT  38.4 13.715 38.808 13.955 ;
     RECT  123.984 13.669 125.4 13.955 ;
     RECT  104.88 13.861 107.16 14.003 ;
     RECT  40.2 13.861 41.016 14.099 ;
     RECT  109.776 12.469 112.008 14.099 ;
     RECT  136.32 13.811 139.128 14.099 ;
     RECT  156.096 13.045 156.12 14.099 ;
     RECT  55.056 11.795 55.08 14.101 ;
     RECT  99.504 13.909 100.872 14.101 ;
     RECT  38.4 13.955 38.424 14.147 ;
     RECT  118.56 14.053 118.584 14.195 ;
     RECT  83.4 13.573 84.216 14.197 ;
     RECT  85.2 13.045 86.184 14.197 ;
     RECT  93.12 13.187 94.512 14.197 ;
     RECT  147.84 12.995 148.512 14.197 ;
     RECT  56.4 12.755 57.144 14.243 ;
     RECT  115.8 13.813 116.616 14.243 ;
     RECT  10.464 13.861 10.488 14.245 ;
     RECT  31.104 12.373 32.04 14.245 ;
     RECT  60.288 13.379 60.408 14.291 ;
     RECT  70.752 12.901 70.776 14.291 ;
     RECT  77.328 12.035 78.312 14.291 ;
     RECT  110.4 14.099 112.008 14.291 ;
     RECT  125.376 13.955 125.4 14.291 ;
     RECT  128.16 14.149 128.184 14.291 ;
     RECT  145.68 12.325 145.704 14.291 ;
     RECT  158.256 12.515 159.312 14.291 ;
     RECT  83.4 14.197 86.184 14.339 ;
     RECT  10.464 14.245 10.632 14.341 ;
     RECT  10.464 14.341 10.824 14.387 ;
     RECT  12 13.381 12.024 14.387 ;
     RECT  34.8 13.909 35.88 14.387 ;
     RECT  40.2 14.099 40.968 14.387 ;
     RECT  2.304 12.611 8.904 14.389 ;
     RECT  140.208 13.621 140.376 14.389 ;
     RECT  136.32 14.099 136.344 14.435 ;
     RECT  63.84 13.093 64.68 14.437 ;
     RECT  71.808 13.333 72.912 14.437 ;
     RECT  131.472 13.379 132.312 14.437 ;
     RECT  98.448 14.101 100.872 14.483 ;
     RECT  140.208 14.389 140.808 14.483 ;
     RECT  126.6 12.611 126.912 14.485 ;
     RECT  140.352 14.483 140.808 14.485 ;
     RECT  88.608 12.517 89.112 14.533 ;
     RECT  63.84 14.437 65.16 14.579 ;
     RECT  63.84 14.579 64.68 14.627 ;
     RECT  81.168 13.621 81.192 14.629 ;
     RECT  88.608 14.533 89.208 14.629 ;
     RECT  88.464 14.629 89.208 14.677 ;
     RECT  140.352 14.485 140.904 14.723 ;
     RECT  115.8 14.243 116.376 14.725 ;
     RECT  147.648 14.197 148.512 14.725 ;
     RECT  52.368 14.341 52.392 14.771 ;
     RECT  18.432 13.621 19.896 14.773 ;
     RECT  54.768 14.101 55.08 14.773 ;
     RECT  56.4 14.243 57.048 14.773 ;
     RECT  91.584 14.197 91.608 14.773 ;
     RECT  66.48 13.909 68.424 14.819 ;
     RECT  13.2 12.371 14.52 14.821 ;
     RECT  80.832 14.629 81.192 14.821 ;
     RECT  88.464 14.677 89.88 14.821 ;
     RECT  147.648 14.725 148.728 14.821 ;
     RECT  119.616 13.861 119.64 14.867 ;
     RECT  66.528 14.819 68.424 14.915 ;
     RECT  80.592 14.821 81.192 14.915 ;
     RECT  105 14.003 107.16 14.915 ;
     RECT  29.4 13.715 29.712 14.917 ;
     RECT  30.72 14.245 32.04 14.963 ;
     RECT  80.592 14.915 80.952 14.963 ;
     RECT  99.504 14.483 100.872 14.963 ;
     RECT  103.68 14.773 103.704 14.963 ;
     RECT  75.84 13.043 75.864 14.965 ;
     RECT  78 14.291 78.312 14.965 ;
     RECT  29.184 14.917 29.712 15.059 ;
     RECT  50.832 13.619 51.312 15.061 ;
     RECT  80.592 14.963 80.904 15.109 ;
     RECT  123.984 13.955 124.008 15.109 ;
     RECT  75.12 14.965 75.864 15.155 ;
     RECT  123.984 15.109 124.248 15.155 ;
     RECT  60.384 14.291 60.408 15.157 ;
     RECT  61.68 13.619 62.112 15.157 ;
     RECT  75.84 15.155 75.864 15.157 ;
     RECT  85.92 14.339 86.184 15.203 ;
     RECT  147.648 14.821 148.824 15.203 ;
     RECT  115.632 14.725 116.376 15.205 ;
     RECT  121.2 13.571 121.512 15.205 ;
     RECT  91.584 14.773 91.896 15.251 ;
     RECT  128.928 14.917 128.952 15.251 ;
     RECT  17.616 14.773 19.896 15.253 ;
     RECT  78 14.965 78.696 15.253 ;
     RECT  124.224 15.155 124.248 15.253 ;
     RECT  13.2 14.821 14.808 15.299 ;
     RECT  115.632 15.205 116.664 15.299 ;
     RECT  158.4 14.291 159.312 15.301 ;
     RECT  27.984 15.205 28.008 15.347 ;
     RECT  50.832 15.061 52.248 15.347 ;
     RECT  114.336 13.909 114.36 15.347 ;
     RECT  115.8 15.299 116.664 15.347 ;
     RECT  13.2 15.299 13.512 15.349 ;
     RECT  110.4 14.291 110.712 15.349 ;
     RECT  142.8 13.621 143.688 15.349 ;
     RECT  26.16 14.053 26.184 15.443 ;
     RECT  75.84 15.157 76.584 15.443 ;
     RECT  86.064 15.203 86.184 15.443 ;
     RECT  93.12 14.197 94.776 15.443 ;
     RECT  140.352 14.723 140.712 15.443 ;
     RECT  98.448 14.483 98.472 15.491 ;
     RECT  117.792 14.917 117.912 15.541 ;
     RECT  83.4 14.339 84.216 15.589 ;
     RECT  135.936 15.445 135.96 15.589 ;
     RECT  137.4 14.099 139.128 15.589 ;
     RECT  78 15.253 78.984 15.637 ;
     RECT  43.488 12.517 43.512 15.683 ;
     RECT  68.928 15.397 68.952 15.683 ;
     RECT  80.352 15.109 80.904 15.731 ;
     RECT  96.288 15.013 96.312 15.731 ;
     RECT  117.792 15.541 117.96 15.731 ;
     RECT  99.6 14.963 100.872 15.781 ;
     RECT  54.768 14.773 57.048 15.827 ;
     RECT  45.6 9.443 45.912 15.829 ;
     RECT  78 15.637 79.224 15.829 ;
     RECT  83.4 15.589 84.936 15.829 ;
     RECT  142.272 15.349 143.688 15.829 ;
     RECT  80.88 15.731 80.904 15.923 ;
     RECT  135.936 15.589 139.128 15.923 ;
     RECT  40.2 14.387 40.68 15.925 ;
     RECT  103.728 15.877 103.752 15.925 ;
     RECT  105 14.915 106.296 15.925 ;
     RECT  156.144 14.821 156.168 15.925 ;
     RECT  66.528 14.915 67.704 15.973 ;
     RECT  126.6 14.485 127.08 15.973 ;
     RECT  13.104 15.349 13.512 16.019 ;
     RECT  14.544 15.299 14.808 16.019 ;
     RECT  50.832 15.347 51.312 16.019 ;
     RECT  54.768 15.827 55.08 16.019 ;
     RECT  142.272 15.829 144.36 16.019 ;
     RECT  58.176 12.755 58.488 16.021 ;
     RECT  126.6 15.973 127.128 16.021 ;
     RECT  111.744 14.291 112.008 16.067 ;
     RECT  103.728 15.925 106.296 16.069 ;
     RECT  93.168 15.443 94.776 16.165 ;
     RECT  58.176 16.021 59.016 16.211 ;
     RECT  103.392 16.069 106.296 16.211 ;
     RECT  103.728 16.211 106.296 16.259 ;
     RECT  109.488 15.349 110.712 16.259 ;
     RECT  71.712 14.437 72.912 16.261 ;
     RECT  91.68 15.251 91.896 16.261 ;
     RECT  126.6 16.021 128.04 16.261 ;
     RECT  142.8 16.019 144.36 16.261 ;
     RECT  83.04 15.829 84.936 16.355 ;
     RECT  60.384 15.157 62.112 16.357 ;
     RECT  131.472 14.437 132.792 16.357 ;
     RECT  153.6 11.843 153.912 16.357 ;
     RECT  48.864 16.261 48.888 16.405 ;
     RECT  88.368 14.821 89.88 16.405 ;
     RECT  104.304 16.259 106.296 16.405 ;
     RECT  131.472 16.357 133.224 16.499 ;
     RECT  29.28 15.059 29.712 16.501 ;
     RECT  30.72 14.963 31.128 16.501 ;
     RECT  48.864 16.405 48.936 16.501 ;
     RECT  111.984 16.067 112.008 16.547 ;
     RECT  34.8 14.387 35.112 16.549 ;
     RECT  84.72 16.355 84.936 16.549 ;
     RECT  86.208 15.637 86.424 16.549 ;
     RECT  29.28 16.501 31.128 16.595 ;
     RECT  131.472 16.499 132.936 16.597 ;
     RECT  39.36 15.925 40.68 16.643 ;
     RECT  48.864 16.501 48.984 16.645 ;
     RECT  52.8 16.597 52.824 16.645 ;
     RECT  83.04 16.355 83.712 16.645 ;
     RECT  120.864 15.205 121.512 16.645 ;
     RECT  84.72 16.549 86.424 16.691 ;
     RECT  65.76 15.973 67.704 16.739 ;
     RECT  147.648 15.203 148.512 16.741 ;
     RECT  126.6 16.261 128.808 16.787 ;
     RECT  56.4 15.827 57.048 16.789 ;
     RECT  120.672 16.645 121.512 16.789 ;
     RECT  17.616 15.253 19.992 16.835 ;
     RECT  52.8 16.645 52.92 16.835 ;
     RECT  81.36 16.693 81.384 16.835 ;
     RECT  26.784 16.597 26.808 16.883 ;
     RECT  146.928 16.741 148.512 16.883 ;
     RECT  13.2 16.019 13.512 16.885 ;
     RECT  115.8 15.347 116.112 16.885 ;
     RECT  128.448 16.787 128.808 16.885 ;
     RECT  135.936 15.923 138.12 16.931 ;
     RECT  160.608 15.493 160.632 16.931 ;
     RECT  124.224 15.253 124.872 16.933 ;
     RECT  126.6 16.787 127.272 16.933 ;
     RECT  18.096 16.835 19.992 16.979 ;
     RECT  76.56 15.443 76.584 16.981 ;
     RECT  93.168 16.165 95.064 16.981 ;
     RECT  108.48 16.501 108.504 16.981 ;
     RECT  56.4 16.789 57.144 17.029 ;
     RECT  58.176 16.211 58.632 17.029 ;
     RECT  71.52 16.261 72.912 17.029 ;
     RECT  112.752 16.549 112.776 17.029 ;
     RECT  113.808 16.885 113.832 17.029 ;
     RECT  117.936 15.731 117.96 17.029 ;
     RECT  130.8 16.597 132.936 17.029 ;
     RECT  2.304 14.389 9.672 17.075 ;
     RECT  71.52 17.029 73.032 17.075 ;
     RECT  142.8 16.261 145.272 17.075 ;
     RECT  150.816 15.829 150.84 17.075 ;
     RECT  13.2 16.885 13.704 17.077 ;
     RECT  63.84 14.627 63.864 17.077 ;
     RECT  76.032 16.981 76.584 17.077 ;
     RECT  123.696 16.933 124.872 17.077 ;
     RECT  142.8 17.075 143.112 17.077 ;
     RECT  153.6 16.357 154.008 17.077 ;
     RECT  108.48 16.981 108.888 17.123 ;
     RECT  126.048 16.933 127.272 17.123 ;
     RECT  130.56 17.029 132.936 17.123 ;
     RECT  144.336 17.075 145.272 17.123 ;
     RECT  155.616 15.925 156.168 17.123 ;
     RECT  48.864 16.645 49.032 17.125 ;
     RECT  137.4 16.931 138.12 17.125 ;
     RECT  139.104 15.923 139.128 17.125 ;
     RECT  59.904 16.357 62.112 17.171 ;
     RECT  63.84 17.077 64.92 17.171 ;
     RECT  145.248 17.123 145.272 17.171 ;
     RECT  153.024 17.077 154.008 17.173 ;
     RECT  155.616 17.123 155.736 17.173 ;
     RECT  68.928 16.885 68.952 17.219 ;
     RECT  99.6 15.781 101.496 17.219 ;
     RECT  112.752 17.029 113.832 17.219 ;
     RECT  115.8 16.885 116.856 17.219 ;
     RECT  130.56 17.123 130.968 17.219 ;
     RECT  137.4 17.125 139.128 17.219 ;
     RECT  42.72 16.981 42.744 17.221 ;
     RECT  76.032 17.077 76.968 17.267 ;
     RECT  91.44 16.261 91.896 17.267 ;
     RECT  112.752 17.219 112.872 17.267 ;
     RECT  137.4 17.219 138.696 17.267 ;
     RECT  63.936 17.171 64.92 17.315 ;
     RECT  137.4 17.267 138.6 17.363 ;
     RECT  76.848 17.267 76.968 17.411 ;
     RECT  128.448 16.885 129.384 17.411 ;
     RECT  115.8 17.219 116.232 17.413 ;
     RECT  82.848 16.645 83.712 17.459 ;
     RECT  130.704 17.219 130.968 17.459 ;
     RECT  137.4 17.363 138.504 17.459 ;
     RECT  60.384 17.171 62.112 17.461 ;
     RECT  142.272 17.077 143.112 17.509 ;
     RECT  83.088 17.459 83.712 17.555 ;
     RECT  45.6 15.829 46.152 17.557 ;
     RECT  53.04 17.269 53.064 17.557 ;
     RECT  71.952 17.075 73.032 17.557 ;
     RECT  74.736 16.213 74.76 17.557 ;
     RECT  96.864 16.981 96.888 17.557 ;
     RECT  60.384 17.461 62.712 17.603 ;
     RECT  76.848 17.411 76.872 17.603 ;
     RECT  130.704 17.459 130.824 17.603 ;
     RECT  48.768 17.125 49.032 17.605 ;
     RECT  55.056 16.019 55.08 17.605 ;
     RECT  78 15.829 79.848 17.605 ;
     RECT  34.176 16.549 35.112 17.651 ;
     RECT  44.832 17.557 46.152 17.651 ;
     RECT  126.432 17.123 127.272 17.651 ;
     RECT  128.448 17.411 128.952 17.651 ;
     RECT  130.704 17.603 130.728 17.651 ;
     RECT  48.768 17.605 49.08 17.653 ;
     RECT  153.024 17.173 154.056 17.653 ;
     RECT  155.184 17.173 155.736 17.653 ;
     RECT  123.696 17.077 124.92 17.699 ;
     RECT  115.68 17.413 116.232 17.747 ;
     RECT  119.616 17.077 119.64 17.747 ;
     RECT  123.696 17.699 123.72 17.749 ;
     RECT  56.4 17.029 58.632 17.795 ;
     RECT  83.232 17.555 83.712 17.795 ;
     RECT  128.832 17.651 128.952 17.795 ;
     RECT  71.952 17.557 74.76 17.843 ;
     RECT  115.68 17.747 116.112 17.843 ;
     RECT  84.72 16.691 85.32 17.845 ;
     RECT  86.4 16.691 86.424 17.845 ;
     RECT  123.504 17.749 123.72 17.891 ;
     RECT  124.848 17.699 124.872 17.939 ;
     RECT  48.768 17.653 49.896 17.941 ;
     RECT  51 16.019 51.312 17.941 ;
     RECT  53.04 17.557 53.256 17.941 ;
     RECT  66.528 16.739 67.704 17.941 ;
     RECT  56.4 17.795 56.712 17.989 ;
     RECT  120.672 16.789 122.04 18.035 ;
     RECT  71.952 17.843 73.8 18.037 ;
     RECT  83.4 17.795 83.712 18.037 ;
     RECT  84.72 17.845 86.424 18.037 ;
     RECT  104.304 16.405 106.392 18.037 ;
     RECT  157.92 15.301 159.312 18.037 ;
     RECT  60.384 17.603 62.112 18.083 ;
     RECT  13.104 17.077 13.704 18.131 ;
     RECT  65.28 17.989 65.304 18.131 ;
     RECT  78 17.605 80.376 18.131 ;
     RECT  87.744 16.405 89.88 18.131 ;
     RECT  153.024 17.653 155.736 18.133 ;
     RECT  83.4 18.037 86.424 18.179 ;
     RECT  104.304 18.037 106.632 18.179 ;
     RECT  60.384 18.083 60.408 18.181 ;
     RECT  69.552 17.221 69.576 18.181 ;
     RECT  93.168 16.981 95.208 18.181 ;
     RECT  153.024 18.133 155.88 18.181 ;
     RECT  152.208 18.181 155.88 18.227 ;
     RECT  157.728 18.037 159.312 18.229 ;
     RECT  18.096 16.979 19.56 18.275 ;
     RECT  40.2 16.643 40.68 18.275 ;
     RECT  71.568 18.037 73.8 18.275 ;
     RECT  93.168 18.181 95.544 18.275 ;
     RECT  96.816 17.557 96.888 18.275 ;
     RECT  105 18.179 106.632 18.277 ;
     RECT  132 17.123 132.792 18.277 ;
     RECT  52.704 17.941 53.256 18.325 ;
     RECT  52.656 18.325 53.256 18.371 ;
     RECT  54.288 17.605 55.08 18.371 ;
     RECT  69.552 18.181 70.056 18.371 ;
     RECT  87.744 18.131 87.768 18.371 ;
     RECT  47.376 16.405 47.4 18.421 ;
     RECT  48.768 17.941 51.312 18.421 ;
     RECT  42.144 17.221 42.744 18.467 ;
     RECT  44.832 17.651 46.008 18.467 ;
     RECT  80.352 18.131 80.376 18.469 ;
     RECT  78 18.131 79.08 18.515 ;
     RECT  96.864 18.275 96.888 18.563 ;
     RECT  117.936 17.029 118.536 18.563 ;
     RECT  147.84 16.883 148.512 18.563 ;
     RECT  118.512 18.563 118.536 18.611 ;
     RECT  47.376 18.421 51.312 18.659 ;
     RECT  54.288 18.371 54.312 18.659 ;
     RECT  145.968 17.509 145.992 18.661 ;
     RECT  126.432 17.651 127.128 18.707 ;
     RECT  145.872 18.661 145.992 18.707 ;
     RECT  142.08 17.509 143.112 18.709 ;
     RECT  18.096 18.275 19.32 18.755 ;
     RECT  50.736 18.659 51.312 18.755 ;
     RECT  75.12 18.469 75.144 18.755 ;
     RECT  80.352 18.469 80.952 18.755 ;
     RECT  52.656 18.371 52.728 18.757 ;
     RECT  108.48 17.123 108.504 18.757 ;
     RECT  144.528 18.661 144.552 18.803 ;
     RECT  142.032 18.709 143.112 18.805 ;
     RECT  57.888 17.795 58.632 18.851 ;
     RECT  105 18.277 106.68 18.851 ;
     RECT  140.688 15.443 140.712 18.851 ;
     RECT  155.184 18.227 155.88 18.853 ;
     RECT  157.728 18.229 159.432 18.853 ;
     RECT  152.208 18.227 153.912 18.899 ;
     RECT  121.2 18.035 122.04 18.901 ;
     RECT  123.696 17.891 123.72 18.901 ;
     RECT  121.2 18.901 123.72 18.947 ;
     RECT  50.784 18.755 51.312 18.949 ;
     RECT  52.416 18.757 52.728 18.949 ;
     RECT  110.4 16.259 110.712 18.949 ;
     RECT  93.168 18.275 94.512 18.995 ;
     RECT  108.48 18.757 108.6 19.043 ;
     RECT  99.6 17.219 100.92 19.045 ;
     RECT  44.832 18.467 45.912 19.093 ;
     RECT  148.2 18.563 148.512 19.093 ;
     RECT  112.752 17.267 112.776 19.139 ;
     RECT  60.288 18.181 60.408 19.141 ;
     RECT  61.584 18.083 62.112 19.141 ;
     RECT  131.904 18.277 132.792 19.187 ;
     RECT  84.72 18.179 84.984 19.189 ;
     RECT  86.4 18.179 86.424 19.189 ;
     RECT  93.168 18.995 93.192 19.189 ;
     RECT  99.6 19.045 100.968 19.189 ;
     RECT  152.736 18.899 153.912 19.189 ;
     RECT  31.872 18.709 31.896 19.235 ;
     RECT  47.376 18.659 49.416 19.235 ;
     RECT  155.184 18.853 159.432 19.235 ;
     RECT  93.072 19.189 93.192 19.237 ;
     RECT  66.528 17.941 68.232 19.285 ;
     RECT  148.2 19.093 148.68 19.285 ;
     RECT  70.032 18.371 70.056 19.331 ;
     RECT  2.304 17.075 8.952 19.379 ;
     RECT  92.928 19.237 93.192 19.379 ;
     RECT  128.832 17.795 128.856 19.379 ;
     RECT  152.736 19.189 154.008 19.379 ;
     RECT  155.184 19.235 156.792 19.379 ;
     RECT  137.4 17.459 138.12 19.429 ;
     RECT  98.304 17.077 98.328 19.475 ;
     RECT  121.2 18.947 122.76 19.477 ;
     RECT  132 19.187 132.792 19.525 ;
     RECT  121.104 19.477 122.76 19.571 ;
     RECT  137.4 19.429 138.312 19.571 ;
     RECT  121.104 19.571 122.136 19.619 ;
     RECT  148.2 19.285 148.776 19.619 ;
     RECT  132 19.525 132.84 19.621 ;
     RECT  60.288 19.141 62.112 19.667 ;
     RECT  64.992 19.525 65.016 19.667 ;
     RECT  137.4 19.571 138.216 19.667 ;
     RECT  76.56 19.573 76.968 19.715 ;
     RECT  132 19.621 133.416 19.763 ;
     RECT  152.736 19.379 153.912 19.763 ;
     RECT  47.376 19.235 47.4 19.811 ;
     RECT  58.176 18.851 58.632 19.811 ;
     RECT  99.6 19.189 101.16 19.859 ;
     RECT  54.96 19.765 54.984 19.909 ;
     RECT  56.304 17.989 56.712 19.909 ;
     RECT  76.56 19.715 76.584 19.955 ;
     RECT  81.984 18.997 82.008 19.955 ;
     RECT  71.568 18.275 73.704 20.003 ;
     RECT  91.44 17.267 91.464 20.003 ;
     RECT  157.92 19.235 159.432 20.003 ;
     RECT  88.8 18.131 89.88 20.099 ;
     RECT  126.6 18.707 127.128 20.101 ;
     RECT  14.784 16.019 14.808 20.147 ;
     RECT  142.032 18.805 143.208 20.195 ;
     RECT  95.52 18.275 95.544 20.243 ;
     RECT  93.072 19.379 93.192 20.291 ;
     RECT  145.872 18.707 145.896 20.291 ;
     RECT  148.2 19.619 148.68 20.339 ;
     RECT  105 18.851 106.632 20.341 ;
     RECT  107.856 19.333 107.88 20.341 ;
     RECT  44.352 19.093 45.912 20.389 ;
     RECT  66.528 19.285 68.952 20.389 ;
     RECT  80.352 18.755 80.472 20.485 ;
     RECT  83.4 18.179 83.712 20.485 ;
     RECT  84.72 19.189 86.424 20.485 ;
     RECT  155.184 19.379 155.736 20.485 ;
     RECT  156.768 19.379 156.792 20.485 ;
     RECT  157.92 20.003 159.312 20.485 ;
     RECT  48.432 19.235 49.416 20.531 ;
     RECT  48.432 20.531 49.128 20.579 ;
     RECT  83.4 20.485 86.424 20.579 ;
     RECT  142.032 20.195 143.112 20.579 ;
     RECT  147.072 18.757 147.096 20.579 ;
     RECT  152.208 20.149 152.232 20.579 ;
     RECT  44.352 20.389 46.008 20.627 ;
     RECT  50.784 18.949 52.728 20.627 ;
     RECT  108.864 19.861 108.888 20.627 ;
     RECT  66.192 20.389 68.952 20.629 ;
     RECT  52.56 20.627 52.728 20.675 ;
     RECT  153.6 19.763 153.912 20.677 ;
     RECT  121.2 19.619 122.136 20.723 ;
     RECT  124.848 20.581 124.872 20.723 ;
     RECT  66.192 20.629 69 20.725 ;
     RECT  72.384 20.003 73.704 20.725 ;
     RECT  66.192 20.725 69.528 20.771 ;
     RECT  72.384 20.725 74.088 20.771 ;
     RECT  110.4 18.949 111.432 20.773 ;
     RECT  115.8 17.843 116.112 20.773 ;
     RECT  117.552 19.813 117.576 20.773 ;
     RECT  58.608 19.811 58.632 20.821 ;
     RECT  60.288 19.667 60.408 20.821 ;
     RECT  99.6 19.859 99.912 20.821 ;
     RECT  18.6 18.755 19.32 20.869 ;
     RECT  20.448 18.709 20.472 20.869 ;
     RECT  78 18.515 78.696 20.915 ;
     RECT  110.4 20.773 111.528 20.915 ;
     RECT  58.608 20.821 60.408 20.917 ;
     RECT  61.8 19.667 62.112 20.917 ;
     RECT  99.6 20.821 100.104 20.917 ;
     RECT  121.2 20.723 121.992 20.963 ;
     RECT  101.136 19.859 101.16 21.061 ;
     RECT  115.8 20.773 117.576 21.061 ;
     RECT  135.936 16.931 135.96 21.061 ;
     RECT  137.4 19.667 138.12 21.061 ;
     RECT  105 20.341 107.88 21.109 ;
     RECT  121.2 20.963 121.704 21.109 ;
     RECT  13.2 18.131 13.704 21.155 ;
     RECT  47.904 21.013 47.928 21.155 ;
     RECT  49.104 20.579 49.128 21.155 ;
     RECT  93.168 20.291 93.192 21.155 ;
     RECT  133.392 19.763 133.416 21.155 ;
     RECT  115.104 21.061 117.768 21.157 ;
     RECT  126.48 20.101 127.128 21.157 ;
     RECT  140.208 21.013 140.232 21.157 ;
     RECT  18.6 20.869 20.472 21.203 ;
     RECT  54.96 19.909 56.712 21.203 ;
     RECT  80.352 20.485 80.616 21.205 ;
     RECT  126.48 21.157 127.176 21.205 ;
     RECT  145.536 21.109 145.56 21.251 ;
     RECT  2.304 19.379 8.808 21.253 ;
     RECT  10.8 14.387 10.824 21.299 ;
     RECT  139.632 21.157 140.232 21.299 ;
     RECT  74.064 20.771 74.088 21.301 ;
     RECT  80.112 21.205 80.616 21.301 ;
     RECT  115.008 21.157 117.768 21.347 ;
     RECT  126.48 21.205 127.704 21.347 ;
     RECT  104.784 21.109 107.88 21.395 ;
     RECT  121.104 21.109 121.704 21.397 ;
     RECT  15.84 20.725 15.864 21.443 ;
     RECT  79.584 21.301 80.616 21.443 ;
     RECT  110.4 20.915 111.288 21.445 ;
     RECT  42.144 18.467 42.36 21.491 ;
     RECT  104.784 21.395 106.392 21.539 ;
     RECT  153.6 20.677 154.008 21.541 ;
     RECT  155.184 20.485 159.312 21.541 ;
     RECT  139.728 21.299 140.232 21.587 ;
     RECT  107.856 21.395 107.88 21.589 ;
     RECT  148.2 20.339 148.512 21.589 ;
     RECT  153.36 21.541 159.312 21.589 ;
     RECT  101.136 21.061 102.024 21.635 ;
     RECT  110.112 21.445 111.288 21.635 ;
     RECT  120.384 21.397 121.704 21.635 ;
     RECT  56.4 21.203 56.712 21.637 ;
     RECT  94.2 18.995 94.512 21.637 ;
     RECT  152.736 21.589 159.312 21.637 ;
     RECT  160.56 21.589 160.584 21.637 ;
     RECT  29.28 16.595 30.648 21.683 ;
     RECT  37.296 17.605 37.32 21.683 ;
     RECT  42.336 21.491 42.36 21.683 ;
     RECT  123.648 21.541 123.672 21.683 ;
     RECT  132 19.763 132.408 21.683 ;
     RECT  135.936 21.061 138.12 21.683 ;
     RECT  140.208 21.587 140.232 21.683 ;
     RECT  112.56 19.573 112.584 21.685 ;
     RECT  74.064 21.301 74.52 21.731 ;
     RECT  102 21.635 102.024 21.731 ;
     RECT  104.784 21.539 106.296 21.731 ;
     RECT  110.112 21.635 110.808 21.731 ;
     RECT  115.8 21.347 117.768 21.731 ;
     RECT  142.8 20.579 143.112 21.733 ;
     RECT  83.4 20.579 85.512 21.779 ;
     RECT  66.192 20.771 67.512 21.781 ;
     RECT  93.408 21.637 94.512 21.781 ;
     RECT  99.168 20.917 100.104 21.781 ;
     RECT  104.784 21.731 105.432 21.781 ;
     RECT  115.8 21.731 117.576 21.827 ;
     RECT  120.528 21.635 121.704 21.827 ;
     RECT  142.08 21.733 143.112 21.875 ;
     RECT  66.192 21.781 67.608 21.923 ;
     RECT  2.304 21.253 9.672 21.971 ;
     RECT  38.688 20.965 38.712 21.971 ;
     RECT  93.408 21.781 95.736 21.971 ;
     RECT  112.272 21.685 112.584 21.971 ;
     RECT  24 13.043 24.312 21.973 ;
     RECT  56.4 21.637 57.624 21.973 ;
     RECT  58.608 20.917 62.112 21.973 ;
     RECT  78 20.915 78.312 21.973 ;
     RECT  123.984 21.829 124.008 22.019 ;
     RECT  50.88 20.627 51.432 22.069 ;
     RECT  77.712 21.973 79.08 22.115 ;
     RECT  152.736 21.637 160.584 22.117 ;
     RECT  72.384 20.771 72.912 22.163 ;
     RECT  75.888 22.021 75.912 22.163 ;
     RECT  77.712 22.115 78.312 22.163 ;
     RECT  136.224 21.683 138.12 22.163 ;
     RECT  18.6 21.203 19.992 22.165 ;
     RECT  45.024 20.627 46.008 22.165 ;
     RECT  99.168 21.781 100.296 22.165 ;
     RECT  104.64 21.781 105.432 22.165 ;
     RECT  132 21.683 132.312 22.165 ;
     RECT  11.952 20.677 11.976 22.211 ;
     RECT  44.64 22.165 46.008 22.259 ;
     RECT  56.4 21.973 62.112 22.259 ;
     RECT  2.304 21.971 9.144 22.307 ;
     RECT  76.896 22.165 76.92 22.307 ;
     RECT  107.856 21.589 108.312 22.307 ;
     RECT  60.384 22.259 62.112 22.355 ;
     RECT  108.288 22.307 108.312 22.357 ;
     RECT  56.4 22.259 58.632 22.403 ;
     RECT  66.192 21.923 67.512 22.403 ;
     RECT  115.8 21.827 116.112 22.453 ;
     RECT  137.232 22.163 138.12 22.453 ;
     RECT  80.256 21.443 80.616 22.499 ;
     RECT  146.352 21.541 146.376 22.499 ;
     RECT  126.48 21.347 126.912 22.547 ;
     RECT  108.288 22.357 108.36 22.595 ;
     RECT  63.936 17.315 63.96 22.693 ;
     RECT  17.952 22.165 19.992 22.741 ;
     RECT  48.24 21.781 48.264 22.741 ;
     RECT  142.8 21.875 143.112 22.741 ;
     RECT  24 21.973 24.552 22.787 ;
     RECT  50.736 22.069 51.432 22.787 ;
     RECT  16.56 22.165 16.584 22.835 ;
     RECT  17.712 22.741 19.992 22.835 ;
     RECT  49.584 21.637 49.608 22.835 ;
     RECT  52.56 20.675 52.584 22.835 ;
     RECT  54.96 21.203 55.272 22.835 ;
     RECT  151.68 22.165 151.704 22.837 ;
     RECT  142.8 22.741 143.976 22.885 ;
     RECT  95.712 21.971 95.736 22.931 ;
     RECT  115.008 22.453 116.112 22.933 ;
     RECT  117.552 21.827 117.576 22.933 ;
     RECT  83.4 21.779 85.032 22.979 ;
     RECT  85.008 22.979 85.032 23.027 ;
     RECT  142.8 22.885 144.84 23.027 ;
     RECT  98.64 22.165 100.296 23.029 ;
     RECT  110.4 21.731 110.808 23.029 ;
     RECT  126.6 22.547 126.912 23.029 ;
     RECT  32.976 22.741 33 23.077 ;
     RECT  44.64 22.259 45.912 23.123 ;
     RECT  124.848 22.789 124.872 23.123 ;
     RECT  29.28 21.683 29.712 23.125 ;
     RECT  151.632 22.837 151.704 23.125 ;
     RECT  152.736 22.117 160.728 23.125 ;
     RECT  22.8 22.837 22.824 23.171 ;
     RECT  66.24 22.403 67.512 23.171 ;
     RECT  151.632 23.125 161.256 23.171 ;
     RECT  112.56 21.971 112.584 23.173 ;
     RECT  120.96 21.827 121.704 23.173 ;
     RECT  32.976 23.077 33.432 23.219 ;
     RECT  114.864 22.933 117.576 23.219 ;
     RECT  83.4 22.979 83.712 23.221 ;
     RECT  75.696 22.213 75.72 23.267 ;
     RECT  123.216 23.077 123.24 23.267 ;
     RECT  112.56 23.173 112.968 23.269 ;
     RECT  108.288 22.595 108.312 23.315 ;
     RECT  110.4 23.029 111.576 23.315 ;
     RECT  115.2 23.219 117.576 23.315 ;
     RECT  150.576 21.637 150.6 23.315 ;
     RECT  153.36 23.171 161.256 23.315 ;
     RECT  11.184 23.173 11.208 23.363 ;
     RECT  29.184 23.125 29.712 23.363 ;
     RECT  68.976 20.771 69.528 23.411 ;
     RECT  93.408 21.971 94.512 23.411 ;
     RECT  136.224 22.163 136.248 23.411 ;
     RECT  141.552 22.741 141.576 23.411 ;
     RECT  112.56 23.269 113.112 23.459 ;
     RECT  153.36 23.315 155.736 23.459 ;
     RECT  137.232 22.453 138.36 23.461 ;
     RECT  56.4 22.403 58.2 23.507 ;
     RECT  68.976 23.411 69 23.507 ;
     RECT  131.184 22.165 132.312 23.555 ;
     RECT  142.8 23.027 143.976 23.555 ;
     RECT  29.28 23.363 29.712 23.557 ;
     RECT  74.064 21.731 74.088 23.603 ;
     RECT  104.16 22.165 105.432 23.747 ;
     RECT  120.528 23.173 121.704 23.797 ;
     RECT  156.768 23.315 161.256 23.845 ;
     RECT  70.704 23.797 70.728 23.893 ;
     RECT  47.616 22.741 48.264 23.939 ;
     RECT  120.528 23.797 122.568 23.939 ;
     RECT  156.768 23.845 161.88 23.939 ;
     RECT  60.384 22.355 60.456 23.941 ;
     RECT  17.712 22.835 19.32 23.987 ;
     RECT  44.928 23.123 45.912 23.987 ;
     RECT  63.744 22.693 63.96 23.987 ;
     RECT  76.944 23.173 76.968 23.987 ;
     RECT  97.872 23.029 100.296 23.987 ;
     RECT  150 23.317 150.024 23.989 ;
     RECT  136.848 23.461 138.36 24.035 ;
     RECT  80.256 22.499 80.28 24.083 ;
     RECT  115.2 23.315 116.232 24.083 ;
     RECT  140.352 23.941 140.376 24.083 ;
     RECT  54.144 23.077 54.168 24.131 ;
     RECT  66.144 23.797 66.168 24.131 ;
     RECT  126.6 23.029 127.08 24.131 ;
     RECT  0.192 23.317 0.216 24.179 ;
     RECT  50.88 22.787 51.432 24.181 ;
     RECT  112.56 23.459 112.776 24.181 ;
     RECT  82.992 23.221 83.712 24.227 ;
     RECT  112.224 24.181 112.776 24.227 ;
     RECT  119.04 24.181 119.064 24.323 ;
     RECT  44.496 24.229 44.52 24.371 ;
     RECT  50.64 24.181 51.432 24.419 ;
     RECT  17.904 23.987 19.32 24.467 ;
     RECT  70.704 23.893 71.304 24.469 ;
     RECT  129.456 22.741 129.48 24.469 ;
     RECT  2.304 22.307 8.808 24.515 ;
     RECT  63.744 23.987 63.768 24.515 ;
     RECT  124.704 23.701 124.728 24.515 ;
     RECT  48.24 23.939 48.264 24.563 ;
     RECT  58.176 23.507 58.2 24.563 ;
     RECT  60 23.941 60.456 24.563 ;
     RECT  61.536 22.355 62.112 24.563 ;
     RECT  49.392 24.277 49.416 24.611 ;
     RECT  50.64 24.419 51.312 24.611 ;
     RECT  149.904 23.989 150.024 24.613 ;
     RECT  54.768 24.373 54.792 24.659 ;
     RECT  117.408 23.315 117.576 24.659 ;
     RECT  131.904 23.555 132.312 24.659 ;
     RECT  98.64 23.987 100.296 24.707 ;
     RECT  104.88 23.747 105.432 24.709 ;
     RECT  120.528 23.939 121.512 24.755 ;
     RECT  70.416 24.469 71.304 24.899 ;
     RECT  85.92 24.133 85.944 24.947 ;
     RECT  148.2 21.589 148.824 24.949 ;
     RECT  149.904 24.613 150.168 24.949 ;
     RECT  139.776 24.901 139.8 25.043 ;
     RECT  91.68 24.133 91.704 25.045 ;
     RECT  153.504 23.459 155.736 25.045 ;
     RECT  112.224 24.227 112.248 25.091 ;
     RECT  148.2 24.949 150.168 25.139 ;
     RECT  78 22.163 78.312 25.189 ;
     RECT  70.416 24.899 70.728 25.235 ;
     RECT  76.368 24.661 76.392 25.235 ;
     RECT  128.928 24.469 129.48 25.235 ;
     RECT  137.4 24.035 138.36 25.237 ;
     RECT  122.544 23.939 122.568 25.283 ;
     RECT  83.4 24.227 83.712 25.285 ;
     RECT  157.056 23.939 161.88 25.333 ;
     RECT  78 25.189 78.6 25.523 ;
     RECT  91.68 25.045 92.376 25.619 ;
     RECT  45.6 23.987 45.912 25.621 ;
     RECT  56.4 23.507 56.712 25.621 ;
     RECT  83.232 25.285 83.712 25.621 ;
     RECT  87.792 24.517 87.816 25.621 ;
     RECT  88.8 20.099 89.112 25.621 ;
     RECT  132 24.659 132.312 25.621 ;
     RECT  136.752 25.237 138.36 25.621 ;
     RECT  131.328 25.621 132.312 25.669 ;
     RECT  92.352 25.619 92.376 25.715 ;
     RECT  129.408 25.235 129.48 25.715 ;
     RECT  61.8 24.563 62.112 25.717 ;
     RECT  50.88 24.611 51.312 25.765 ;
     RECT  117.552 24.659 117.576 25.765 ;
     RECT  136.224 25.621 138.36 25.765 ;
     RECT  131.328 25.669 132.84 25.859 ;
     RECT  135.888 25.765 138.36 25.907 ;
     RECT  87.792 25.621 89.112 25.957 ;
     RECT  103.68 24.469 103.704 26.003 ;
     RECT  148.2 25.139 149.928 26.005 ;
     RECT  45.504 25.621 45.912 26.051 ;
     RECT  117.552 25.765 117.768 26.051 ;
     RECT  121.2 24.755 121.512 26.053 ;
     RECT  141.312 25.045 141.336 26.147 ;
     RECT  61.632 25.717 62.112 26.197 ;
     RECT  120.96 26.053 121.512 26.197 ;
     RECT  83.232 25.621 83.832 26.243 ;
     RECT  86.976 25.957 89.112 26.243 ;
     RECT  148.08 26.005 149.928 26.243 ;
     RECT  19.92 24.613 19.944 26.291 ;
     RECT  73.968 26.101 73.992 26.291 ;
     RECT  61.632 26.197 62.232 26.293 ;
     RECT  63.84 26.245 64.488 26.387 ;
     RECT  26.64 23.941 26.664 26.531 ;
     RECT  61.008 26.293 62.232 26.531 ;
     RECT  4.272 24.515 8.808 26.629 ;
     RECT  156.768 25.333 161.88 26.675 ;
     RECT  4.272 26.629 9.096 26.725 ;
     RECT  13.2 21.155 13.512 26.725 ;
     RECT  112.704 26.197 112.728 26.725 ;
     RECT  114.048 26.293 114.072 26.725 ;
     RECT  129.408 25.715 129.432 26.725 ;
     RECT  153.504 25.045 155.784 26.725 ;
     RECT  68.496 26.581 68.52 26.771 ;
     RECT  87.936 26.243 89.112 26.771 ;
     RECT  120.576 26.197 121.512 26.771 ;
     RECT  2.304 24.515 2.712 26.773 ;
     RECT  43.872 26.053 43.896 26.773 ;
     RECT  78 25.523 78.312 26.773 ;
     RECT  142.8 23.555 143.112 26.773 ;
     RECT  158.112 26.675 161.88 26.819 ;
     RECT  151.632 23.171 152.232 26.867 ;
     RECT  3.84 26.725 9.336 26.869 ;
     RECT  104.784 24.709 105.432 26.915 ;
     RECT  108.96 26.197 108.984 26.915 ;
     RECT  13.2 26.725 14.232 26.917 ;
     RECT  78 26.773 78.648 26.963 ;
     RECT  24 22.787 24.312 27.109 ;
     RECT  117.552 26.051 117.72 27.109 ;
     RECT  106.608 26.101 106.632 27.155 ;
     RECT  115.2 24.083 116.112 27.155 ;
     RECT  16.08 25.285 16.104 27.157 ;
     RECT  40.2 18.275 40.512 27.157 ;
     RECT  104.88 26.915 105.432 27.157 ;
     RECT  120.96 26.771 121.512 27.157 ;
     RECT  3.84 26.869 9.672 27.203 ;
     RECT  13.008 26.917 14.232 27.203 ;
     RECT  88.368 26.771 89.112 27.203 ;
     RECT  98.64 24.707 99.912 27.203 ;
     RECT  131.328 25.859 132.312 27.203 ;
     RECT  86.016 26.725 86.04 27.205 ;
     RECT  117.408 27.109 117.72 27.205 ;
     RECT  152.16 26.867 152.232 27.251 ;
     RECT  2.304 26.773 2.808 27.253 ;
     RECT  3.84 27.203 9.528 27.253 ;
     RECT  136.224 25.907 138.36 27.299 ;
     RECT  16.08 27.157 16.536 27.301 ;
     RECT  112.704 26.725 114.072 27.301 ;
     RECT  117.408 27.205 118.104 27.301 ;
     RECT  129.408 26.725 130.008 27.301 ;
     RECT  133.392 27.253 133.416 27.301 ;
     RECT  112.704 27.301 114.456 27.347 ;
     RECT  115.584 27.155 116.112 27.349 ;
     RECT  29.28 23.557 30.12 27.395 ;
     RECT  43.392 26.773 43.896 27.395 ;
     RECT  52.752 26.629 52.776 27.443 ;
     RECT  10.8 27.205 10.824 27.445 ;
     RECT  61.8 26.531 62.232 27.445 ;
     RECT  13.2 27.203 14.232 27.491 ;
     RECT  16.08 27.301 16.824 27.491 ;
     RECT  10.8 27.445 11.4 27.587 ;
     RECT  56.4 25.621 57 27.635 ;
     RECT  148.08 26.243 149.016 27.733 ;
     RECT  67.2 23.171 67.512 27.781 ;
     RECT  153.408 26.725 155.784 27.781 ;
     RECT  156.768 26.675 156.888 27.781 ;
     RECT  82.224 27.733 82.248 27.829 ;
     RECT  43.392 27.395 43.416 27.875 ;
     RECT  120.96 27.157 121.704 27.875 ;
     RECT  142.176 26.773 143.112 27.875 ;
     RECT  45.6 26.051 45.912 27.877 ;
     RECT  50.496 25.765 51.312 27.877 ;
     RECT  56.4 27.635 56.712 27.877 ;
     RECT  61.8 27.445 62.472 27.877 ;
     RECT  94.2 23.411 94.512 27.877 ;
     RECT  153.408 27.781 156.888 27.877 ;
     RECT  24 27.109 24.408 27.923 ;
     RECT  88.56 27.203 89.112 27.923 ;
     RECT  115.584 27.349 116.28 27.923 ;
     RECT  129.408 27.301 130.056 27.923 ;
     RECT  136.368 27.299 138.36 27.973 ;
     RECT  82.128 27.829 82.248 28.019 ;
     RECT  136.368 27.973 139.128 28.115 ;
     RECT  112.704 27.347 113.16 28.163 ;
     RECT  115.584 27.923 116.112 28.163 ;
     RECT  61.68 27.877 62.472 28.165 ;
     RECT  158.112 26.819 161.736 28.211 ;
     RECT  140.784 27.973 140.808 28.259 ;
     RECT  20.352 27.301 20.376 28.307 ;
     RECT  47.904 26.293 47.928 28.405 ;
     RECT  17.904 24.467 18.912 28.451 ;
     RECT  47.616 28.405 47.928 28.451 ;
     RECT  130.032 27.923 130.056 28.451 ;
     RECT  86.016 27.205 86.76 28.453 ;
     RECT  153.36 27.877 156.888 28.453 ;
     RECT  83.4 26.243 83.832 28.499 ;
     RECT  86.016 28.453 87.336 28.499 ;
     RECT  2.304 27.253 9.528 28.547 ;
     RECT  92.928 27.733 92.952 28.547 ;
     RECT  153.36 28.453 157.032 28.547 ;
     RECT  49.968 27.877 51.312 28.595 ;
     RECT  104.88 27.157 106.056 28.595 ;
     RECT  131.376 27.203 132.312 28.597 ;
     RECT  152.16 27.251 152.184 28.643 ;
     RECT  44.64 27.877 45.912 28.691 ;
     RECT  74.112 27.349 74.136 28.691 ;
     RECT  82.224 28.019 82.248 28.691 ;
     RECT  131.376 28.597 132.408 28.741 ;
     RECT  133.392 27.301 133.8 28.741 ;
     RECT  84.96 28.453 84.984 28.789 ;
     RECT  86.016 28.499 86.04 28.789 ;
     RECT  10.8 27.587 10.824 28.837 ;
     RECT  72.6 22.163 72.912 28.885 ;
     RECT  110.4 23.315 110.712 28.885 ;
     RECT  84.96 28.789 86.04 28.931 ;
     RECT  148.08 27.733 149.112 28.933 ;
     RECT  16.512 27.491 16.824 28.979 ;
     RECT  103.728 27.301 103.752 28.979 ;
     RECT  117.408 27.301 118.296 28.979 ;
     RECT  131.376 28.741 133.8 29.027 ;
     RECT  114.432 27.347 114.456 29.029 ;
     RECT  147.888 28.933 149.112 29.029 ;
     RECT  2.4 28.547 9.528 29.075 ;
     RECT  10.704 28.837 10.824 29.075 ;
     RECT  155.424 28.547 157.032 29.075 ;
     RECT  47.616 28.451 47.64 29.123 ;
     RECT  87.312 28.499 87.336 29.123 ;
     RECT  91.056 27.109 91.08 29.123 ;
     RECT  101.424 27.301 101.448 29.123 ;
     RECT  139.488 28.453 139.512 29.123 ;
     RECT  80.448 28.501 80.472 29.171 ;
     RECT  55.584 27.877 56.712 29.173 ;
     RECT  155.424 29.075 156.84 29.219 ;
     RECT  60 24.563 60.024 29.221 ;
     RECT  78 26.963 78.408 29.267 ;
     RECT  55.584 29.173 56.952 29.269 ;
     RECT  65.616 28.453 65.64 29.315 ;
     RECT  136.368 28.115 138.36 29.411 ;
     RECT  59.328 29.221 60.024 29.459 ;
     RECT  78 29.267 78.312 29.461 ;
     RECT  118.08 28.979 118.296 29.507 ;
     RECT  145.824 28.453 145.848 29.509 ;
     RECT  147.888 29.029 149.88 29.555 ;
     RECT  50.496 28.595 51.312 29.557 ;
     RECT  55.584 29.269 57.528 29.557 ;
     RECT  84.96 28.931 84.984 29.557 ;
     RECT  13.2 27.491 13.608 29.605 ;
     RECT  37.776 29.557 37.8 29.605 ;
     RECT  67.2 27.781 68.472 29.651 ;
     RECT  39.792 27.157 40.512 29.699 ;
     RECT  109.728 28.885 110.712 29.701 ;
     RECT  50.16 29.557 51.312 29.749 ;
     RECT  113.136 28.163 113.16 29.795 ;
     RECT  109.008 29.701 110.712 29.843 ;
     RECT  40.2 29.699 40.512 29.845 ;
     RECT  72.6 28.885 73.032 29.845 ;
     RECT  126.6 24.131 126.912 29.845 ;
     RECT  55.584 29.557 57.96 29.891 ;
     RECT  4.368 29.075 9.528 29.893 ;
     RECT  158.256 28.211 161.736 29.893 ;
     RECT  72.48 29.845 73.032 29.941 ;
     RECT  94.2 27.877 95.016 29.987 ;
     RECT  40.2 29.845 40.92 30.037 ;
     RECT  42.384 27.877 42.792 30.037 ;
     RECT  72.48 29.941 73.08 30.037 ;
     RECT  131.376 29.027 132.744 30.083 ;
     RECT  126.6 29.845 127.56 30.131 ;
     RECT  121.2 27.875 121.704 30.133 ;
     RECT  40.2 30.037 42.792 30.179 ;
     RECT  56.4 29.891 57.96 30.179 ;
     RECT  24 27.923 24.312 30.181 ;
     RECT  88.8 27.923 89.112 30.181 ;
     RECT  131.376 30.083 132.312 30.181 ;
     RECT  153.36 28.547 153.912 30.181 ;
     RECT  50.16 29.749 51.432 30.227 ;
     RECT  105 28.595 106.056 30.229 ;
     RECT  155.424 29.219 156.792 30.229 ;
     RECT  157.968 29.893 161.736 30.229 ;
     RECT  13.2 29.605 13.656 30.275 ;
     RECT  104.88 30.229 106.056 30.275 ;
     RECT  153.36 30.181 154.008 30.275 ;
     RECT  114.432 29.029 114.6 30.323 ;
     RECT  40.2 30.179 42.408 30.371 ;
     RECT  77.904 29.461 78.312 30.371 ;
     RECT  84.816 29.557 84.984 30.371 ;
     RECT  88.56 30.181 89.112 30.421 ;
     RECT  21.792 27.589 21.816 30.467 ;
     RECT  30.72 30.181 30.744 30.467 ;
     RECT  115.68 28.163 116.112 30.467 ;
     RECT  136.512 29.411 138.36 30.467 ;
     RECT  61.632 28.165 62.472 30.565 ;
     RECT  147.888 29.555 149.016 30.565 ;
     RECT  121.104 30.133 121.704 30.611 ;
     RECT  121.2 30.611 121.704 30.707 ;
     RECT  74.064 29.941 74.088 30.709 ;
     RECT  147.6 30.565 149.016 30.755 ;
     RECT  34.8 17.651 35.112 30.757 ;
     RECT  70.416 25.235 70.44 30.757 ;
     RECT  74.064 30.709 75.048 30.757 ;
     RECT  76.032 25.477 76.056 30.757 ;
     RECT  133.776 29.027 133.8 30.757 ;
     RECT  54.192 30.181 54.216 30.803 ;
     RECT  74.064 30.757 76.056 30.803 ;
     RECT  109.008 29.843 109.032 30.803 ;
     RECT  121.2 30.707 121.608 30.851 ;
     RECT  147.888 30.755 149.016 30.851 ;
     RECT  88.56 30.421 89.208 30.899 ;
     RECT  27.744 30.421 27.768 30.947 ;
     RECT  145.584 29.509 145.848 30.949 ;
     RECT  136.56 30.467 138.36 30.995 ;
     RECT  26.112 28.405 26.136 31.091 ;
     RECT  61.632 30.565 62.52 31.139 ;
     RECT  153.456 30.275 154.008 31.139 ;
     RECT  53.04 31.045 53.064 31.187 ;
     RECT  145.584 30.949 146.136 31.187 ;
     RECT  61.632 31.139 62.472 31.189 ;
     RECT  145.584 31.187 145.848 31.189 ;
     RECT  44.304 31.141 44.328 31.283 ;
     RECT  140.976 31.093 141 31.283 ;
     RECT  147.888 30.851 148.632 31.283 ;
     RECT  4.368 29.893 9.72 31.285 ;
     RECT  29.28 27.395 29.712 31.285 ;
     RECT  45.6 28.691 45.912 31.285 ;
     RECT  74.64 30.803 76.056 31.285 ;
     RECT  96.912 30.181 96.936 31.285 ;
     RECT  155.424 30.229 161.736 31.285 ;
     RECT  55.248 31.189 55.272 31.331 ;
     RECT  72.432 30.037 73.08 31.331 ;
     RECT  61.056 31.189 62.472 31.333 ;
     RECT  130.848 30.181 132.312 31.333 ;
     RECT  142.8 27.875 143.112 31.333 ;
     RECT  34.512 30.757 35.112 31.379 ;
     RECT  96.912 31.285 97.512 31.379 ;
     RECT  150.864 30.229 150.888 31.379 ;
     RECT  118.08 29.507 118.104 31.381 ;
     RECT  119.136 30.997 119.16 31.381 ;
     RECT  118.08 31.381 119.16 31.427 ;
     RECT  4.032 31.285 9.72 31.429 ;
     RECT  10.704 29.075 10.728 31.429 ;
     RECT  115.8 30.467 116.112 31.429 ;
     RECT  56.4 30.179 57.624 31.523 ;
     RECT  145.344 31.189 145.848 31.523 ;
     RECT  67.2 29.651 67.512 31.525 ;
     RECT  48.192 31.381 48.216 31.571 ;
     RECT  74.64 31.285 76.392 31.621 ;
     RECT  102.432 30.757 102.456 31.667 ;
     RECT  115.8 31.429 116.856 31.667 ;
     RECT  130.272 31.333 132.312 31.667 ;
     RECT  13.2 30.275 13.512 31.669 ;
     RECT  74.64 31.621 77.016 31.717 ;
     RECT  78 30.371 78.312 31.717 ;
     RECT  24 30.181 24.6 31.763 ;
     RECT  47.856 31.621 47.976 31.763 ;
     RECT  74.64 31.717 78.312 31.763 ;
     RECT  44.688 31.285 45.912 31.765 ;
     RECT  72.48 31.331 73.08 31.813 ;
     RECT  112.416 31.717 112.44 31.859 ;
     RECT  130.848 31.667 132.312 31.859 ;
     RECT  140.928 31.717 140.952 31.859 ;
     RECT  2.4 29.075 2.808 31.861 ;
     RECT  4.032 31.429 10.728 31.861 ;
     RECT  50.88 30.227 51.432 31.861 ;
     RECT  76.032 31.763 78.312 31.861 ;
     RECT  37.152 29.605 37.8 31.907 ;
     RECT  67.2 31.525 68.136 31.909 ;
     RECT  2.4 31.861 10.728 31.955 ;
     RECT  70.416 30.757 70.728 31.955 ;
     RECT  74.64 31.763 75.048 31.955 ;
     RECT  100.944 30.757 100.968 31.955 ;
     RECT  124.992 29.029 125.016 31.955 ;
     RECT  154.992 31.285 161.736 31.955 ;
     RECT  37.152 31.907 37.176 32.147 ;
     RECT  97.488 31.379 97.512 32.195 ;
     RECT  133.776 30.757 134.712 32.195 ;
     RECT  22.176 30.613 22.2 32.197 ;
     RECT  103.728 31.285 103.752 32.197 ;
     RECT  153.6 31.139 154.008 32.197 ;
     RECT  13.104 31.669 13.512 32.243 ;
     RECT  21.888 32.197 22.2 32.243 ;
     RECT  61.008 31.333 62.472 32.293 ;
     RECT  80.304 32.197 80.328 32.339 ;
     RECT  131.568 31.859 132.312 32.341 ;
     RECT  133.776 32.195 134.616 32.341 ;
     RECT  18.144 28.451 18.912 32.387 ;
     RECT  72.48 31.813 73.656 32.437 ;
     RECT  152.736 32.197 154.008 32.437 ;
     RECT  56.4 31.523 57 32.483 ;
     RECT  131.568 32.341 134.616 32.483 ;
     RECT  152.448 32.437 154.008 32.485 ;
     RECT  44.688 31.765 46.728 32.531 ;
     RECT  88.8 30.899 89.208 32.531 ;
     RECT  157.632 31.955 161.736 32.531 ;
     RECT  61.008 32.293 62.616 32.579 ;
     RECT  67.2 31.909 69 32.579 ;
     RECT  61.008 32.579 62.424 32.675 ;
     RECT  65.568 31.621 65.592 32.675 ;
     RECT  39.024 31.285 39.048 32.723 ;
     RECT  152.16 32.485 154.008 32.725 ;
     RECT  76.032 31.861 79.272 32.771 ;
     RECT  98.784 27.203 99.912 32.771 ;
     RECT  142.8 31.333 143.784 32.771 ;
     RECT  152.112 32.725 154.008 32.771 ;
     RECT  154.992 31.955 155.976 32.771 ;
     RECT  64.992 32.677 65.016 32.773 ;
     RECT  21.888 32.243 21.912 32.821 ;
     RECT  56.4 32.483 56.712 32.821 ;
     RECT  64.128 32.773 65.016 32.869 ;
     RECT  104.88 30.275 105.432 32.869 ;
     RECT  153.6 32.771 154.008 32.869 ;
     RECT  154.992 32.771 155.304 32.869 ;
     RECT  157.632 32.531 161.688 32.917 ;
     RECT  5.04 31.955 10.728 32.965 ;
     RECT  11.952 32.869 11.976 32.965 ;
     RECT  60 29.459 60.024 32.965 ;
     RECT  84.816 30.371 84.84 33.011 ;
     RECT  18.24 32.387 18.912 33.013 ;
     RECT  59.28 32.965 60.024 33.013 ;
     RECT  61.008 32.675 62.28 33.013 ;
     RECT  94.2 29.987 94.512 33.013 ;
     RECT  115.8 31.667 116.112 33.013 ;
     RECT  50.88 31.861 51.816 33.155 ;
     RECT  90.672 32.341 90.696 33.155 ;
     RECT  100.896 33.109 100.92 33.251 ;
     RECT  104.88 32.869 105.528 33.253 ;
     RECT  114.432 30.323 114.456 33.253 ;
     RECT  63.984 32.869 65.016 33.299 ;
     RECT  96.912 32.485 96.936 33.299 ;
     RECT  66.192 32.869 66.216 33.301 ;
     RECT  67.2 32.579 68.136 33.301 ;
     RECT  93.504 33.013 94.512 33.349 ;
     RECT  110.4 29.843 110.712 33.349 ;
     RECT  142.8 32.771 143.112 33.349 ;
     RECT  93.504 33.349 94.68 33.395 ;
     RECT  63.984 33.299 64.872 33.443 ;
     RECT  114.432 33.253 114.552 33.445 ;
     RECT  115.536 33.013 116.112 33.445 ;
     RECT  76.032 32.771 78.312 33.491 ;
     RECT  110.256 33.349 110.712 33.491 ;
     RECT  114.432 33.445 116.112 33.491 ;
     RECT  2.4 31.955 4.056 33.541 ;
     RECT  47.904 31.763 47.976 33.541 ;
     RECT  103.152 32.197 103.752 33.541 ;
     RECT  109.2 32.821 109.224 33.541 ;
     RECT  131.568 32.483 132.312 33.541 ;
     RECT  145.344 31.523 145.368 33.541 ;
     RECT  40.2 30.371 41.784 33.587 ;
     RECT  47.904 33.541 48.072 33.587 ;
     RECT  59.28 33.013 62.28 33.587 ;
     RECT  115.152 33.491 116.112 33.587 ;
     RECT  120.192 33.013 120.216 33.635 ;
     RECT  44.256 32.965 44.28 33.637 ;
     RECT  102.576 33.541 103.848 33.637 ;
     RECT  104.88 33.253 105.96 33.637 ;
     RECT  74.64 31.955 74.856 33.683 ;
     RECT  87.216 32.149 87.24 33.683 ;
     RECT  98.832 32.771 99.912 33.685 ;
     RECT  28.464 31.285 29.712 33.733 ;
     RECT  30.816 32.437 30.84 33.779 ;
     RECT  77.376 33.491 78.312 33.779 ;
     RECT  102.576 33.637 105.96 33.779 ;
     RECT  83.4 28.499 83.712 33.781 ;
     RECT  145.344 33.541 145.608 33.781 ;
     RECT  5.04 32.965 11.976 33.827 ;
     RECT  44.16 33.637 44.328 33.827 ;
     RECT  59.28 33.587 60.024 33.829 ;
     RECT  61.008 33.587 62.28 33.829 ;
     RECT  104.208 33.779 105.96 33.829 ;
     RECT  147.888 31.283 148.512 33.829 ;
     RECT  2.304 33.541 4.056 33.875 ;
     RECT  91.2 33.637 91.224 33.875 ;
     RECT  74.64 33.683 74.664 33.923 ;
     RECT  83.184 33.781 83.712 33.923 ;
     RECT  144.768 33.781 145.608 33.923 ;
     RECT  45.6 32.531 46.728 33.971 ;
     RECT  5.04 33.827 11.88 34.019 ;
     RECT  47.952 33.587 48.072 34.067 ;
     RECT  77.472 33.779 78.312 34.115 ;
     RECT  13.2 32.243 13.512 34.117 ;
     RECT  153.6 32.869 155.304 34.117 ;
     RECT  156.912 32.917 161.688 34.117 ;
     RECT  40.2 33.587 41.64 34.163 ;
     RECT  21.408 32.821 21.912 34.165 ;
     RECT  118.608 31.427 119.16 34.165 ;
     RECT  104.208 33.829 106.008 34.211 ;
     RECT  115.536 33.587 116.112 34.211 ;
     RECT  145.584 33.923 145.608 34.211 ;
     RECT  2.304 33.875 2.952 34.259 ;
     RECT  44.304 33.827 44.328 34.259 ;
     RECT  61.008 33.829 62.808 34.259 ;
     RECT  98.832 33.685 100.584 34.259 ;
     RECT  102.576 33.779 103.032 34.259 ;
     RECT  152.112 32.771 152.568 34.259 ;
     RECT  153.6 34.117 161.688 34.259 ;
     RECT  45.6 33.971 45.912 34.261 ;
     RECT  61.008 34.259 62.112 34.307 ;
     RECT  104.208 34.211 105.96 34.307 ;
     RECT  118.608 34.165 119.64 34.307 ;
     RECT  71.808 32.437 73.656 34.355 ;
     RECT  152.16 34.259 152.568 34.355 ;
     RECT  94.2 33.395 94.68 34.357 ;
     RECT  118.608 34.307 119.16 34.357 ;
     RECT  2.304 34.259 2.856 34.403 ;
     RECT  44.64 34.261 45.912 34.403 ;
     RECT  108.288 33.541 109.224 34.451 ;
     RECT  5.04 34.019 5.832 34.499 ;
     RECT  32.16 34.357 32.184 34.499 ;
     RECT  71.808 34.355 73.032 34.499 ;
     RECT  104.208 34.307 105.312 34.595 ;
     RECT  24 31.763 24.312 34.645 ;
     RECT  6.864 34.019 11.88 34.691 ;
     RECT  76.032 33.491 76.056 34.693 ;
     RECT  55.152 33.973 55.176 34.739 ;
     RECT  56.304 32.821 56.712 34.741 ;
     RECT  137.4 30.995 138.36 34.741 ;
     RECT  66.192 33.301 68.136 34.787 ;
     RECT  50.88 33.155 51.312 34.789 ;
     RECT  64.848 33.443 64.872 34.835 ;
     RECT  113.76 34.213 113.784 34.835 ;
     RECT  139.632 34.213 139.656 34.835 ;
     RECT  150.384 34.117 150.408 34.835 ;
     RECT  110.4 33.491 110.712 34.837 ;
     RECT  27.312 31.381 27.336 34.883 ;
     RECT  118.272 34.357 119.16 34.883 ;
     RECT  4.032 33.875 4.056 34.885 ;
     RECT  5.04 34.499 5.688 34.885 ;
     RECT  83.4 33.923 83.712 34.885 ;
     RECT  48.048 34.067 48.072 34.931 ;
     RECT  152.448 34.355 152.568 34.931 ;
     RECT  142.704 33.349 143.112 34.979 ;
     RECT  2.304 34.403 2.808 35.027 ;
     RECT  6.96 34.691 11.88 35.027 ;
     RECT  40.2 34.163 41.592 35.027 ;
     RECT  69.36 34.165 69.384 35.123 ;
     RECT  124.848 33.061 124.872 35.123 ;
     RECT  6.96 35.027 11.064 35.267 ;
     RECT  61.68 34.307 62.112 35.267 ;
     RECT  45.12 34.403 45.912 35.269 ;
     RECT  153.6 34.259 159.672 35.269 ;
     RECT  50.688 34.789 51.312 35.315 ;
     RECT  18.24 33.013 19.368 35.363 ;
     RECT  20.496 34.165 22.296 35.363 ;
     RECT  118.272 34.883 118.296 35.363 ;
     RECT  18.336 35.363 19.368 35.411 ;
     RECT  18.6 35.411 19.368 35.413 ;
     RECT  103.008 34.259 103.032 35.413 ;
     RECT  16.512 28.979 16.536 35.459 ;
     RECT  94.2 34.357 95.16 35.507 ;
     RECT  98.88 34.259 100.584 35.509 ;
     RECT  133.776 32.483 134.616 35.555 ;
     RECT  77.904 34.115 78.312 35.557 ;
     RECT  75.456 34.693 76.056 35.605 ;
     RECT  131.136 33.541 132.312 35.699 ;
     RECT  108.768 34.451 109.224 35.701 ;
     RECT  2.304 35.027 2.712 35.747 ;
     RECT  23.904 34.645 24.312 35.747 ;
     RECT  98.88 35.509 100.872 35.843 ;
     RECT  74.928 35.605 76.056 35.845 ;
     RECT  86.016 28.931 86.04 35.845 ;
     RECT  98.88 35.843 99.912 35.845 ;
     RECT  71.952 34.499 73.032 35.939 ;
     RECT  103.008 35.413 103.752 35.939 ;
     RECT  160.992 34.259 161.4 35.939 ;
     RECT  152.544 34.931 152.568 35.941 ;
     RECT  153.6 35.269 159.72 35.941 ;
     RECT  83.4 34.885 84.312 35.987 ;
     RECT  160.992 35.939 161.016 35.987 ;
     RECT  13.2 34.117 13.704 35.989 ;
     RECT  40.2 35.027 40.872 35.989 ;
     RECT  12.528 35.989 13.704 36.035 ;
     RECT  28.464 33.733 29.832 36.035 ;
     RECT  68.976 35.269 69 36.035 ;
     RECT  147.888 33.829 148.632 36.035 ;
     RECT  74.112 35.845 76.056 36.037 ;
     RECT  106.56 35.317 106.584 36.083 ;
     RECT  110.4 34.837 110.808 36.083 ;
     RECT  85.584 35.845 86.04 36.085 ;
     RECT  39.408 35.989 40.872 36.131 ;
     RECT  45.12 35.269 46.824 36.131 ;
     RECT  55.632 34.741 56.712 36.131 ;
     RECT  7.056 35.267 11.064 36.229 ;
     RECT  12.528 36.035 13.512 36.229 ;
     RECT  56.304 36.131 56.712 36.229 ;
     RECT  58.32 33.829 60.024 36.229 ;
     RECT  61.8 35.267 62.112 36.229 ;
     RECT  28.896 36.035 29.832 36.275 ;
     RECT  4.032 34.885 5.688 36.277 ;
     RECT  7.056 36.229 13.512 36.277 ;
     RECT  85.584 36.085 86.232 36.371 ;
     RECT  61.68 36.229 62.112 36.373 ;
     RECT  115.632 34.211 116.112 36.373 ;
     RECT  74.112 36.037 76.104 36.419 ;
     RECT  98.112 35.845 99.912 36.467 ;
     RECT  26.736 35.989 26.76 36.469 ;
     RECT  77.616 35.557 78.312 36.469 ;
     RECT  58.128 36.229 60.024 36.515 ;
     RECT  136.656 34.741 138.36 36.515 ;
     RECT  152.544 35.941 159.72 36.515 ;
     RECT  15.36 35.845 15.384 36.517 ;
     RECT  79.872 36.373 79.896 36.517 ;
     RECT  103.008 35.939 103.032 36.563 ;
     RECT  152.544 36.515 156.36 36.659 ;
     RECT  70.416 31.955 70.44 36.661 ;
     RECT  4.032 36.277 13.512 36.803 ;
     RECT  58.128 36.515 59.448 36.803 ;
     RECT  26.304 36.469 26.76 36.805 ;
     RECT  79.872 36.517 79.944 36.805 ;
     RECT  133.776 35.555 133.8 36.805 ;
     RECT  140.784 33.829 140.808 36.805 ;
     RECT  157.488 36.515 159.72 36.805 ;
     RECT  21.456 35.363 22.296 36.851 ;
     RECT  25.776 36.805 26.76 36.851 ;
     RECT  140.784 36.805 141 36.851 ;
     RECT  18.6 35.413 19.416 36.853 ;
     RECT  79.872 36.805 80.04 36.853 ;
     RECT  77.616 36.469 78.408 36.901 ;
     RECT  136.656 36.515 137.712 36.947 ;
     RECT  147.888 36.035 148.512 36.947 ;
     RECT  34.8 31.379 35.112 36.949 ;
     RECT  72.24 35.939 73.032 36.949 ;
     RECT  146.304 36.517 146.328 36.949 ;
     RECT  66.192 34.787 67.512 36.995 ;
     RECT  79.776 36.853 80.04 36.995 ;
     RECT  50.88 35.315 51.312 36.997 ;
     RECT  14.928 36.517 15.384 37.043 ;
     RECT  56.304 36.229 57 37.043 ;
     RECT  133.776 36.805 133.944 37.043 ;
     RECT  131.568 35.699 132.312 37.045 ;
     RECT  133.776 37.043 133.8 37.045 ;
     RECT  22.272 36.851 22.296 37.091 ;
     RECT  56.304 37.043 56.808 37.091 ;
     RECT  66.672 36.995 67.512 37.091 ;
     RECT  79.776 36.995 79.944 37.091 ;
     RECT  123.84 36.085 123.864 37.187 ;
     RECT  149.904 36.853 149.928 37.187 ;
     RECT  61.68 36.373 62.376 37.235 ;
     RECT  72 36.949 73.032 37.235 ;
     RECT  2.4 35.747 2.712 37.237 ;
     RECT  4.032 36.803 11.4 37.237 ;
     RECT  151.152 36.757 151.176 37.427 ;
     RECT  2.4 37.237 11.4 37.475 ;
     RECT  29.4 36.275 29.832 37.477 ;
     RECT  48.96 36.853 48.984 37.477 ;
     RECT  49.968 36.997 51.312 37.477 ;
     RECT  59.424 36.803 59.448 37.477 ;
     RECT  81.168 35.701 81.192 37.477 ;
     RECT  82.224 36.421 82.248 37.477 ;
     RECT  161.808 36.997 161.832 37.477 ;
     RECT  45.6 36.131 45.912 37.525 ;
     RECT  110.4 36.083 110.712 37.525 ;
     RECT  28.464 37.477 29.832 37.571 ;
     RECT  108.24 35.701 109.224 37.571 ;
     RECT  24 35.747 24.312 37.573 ;
     RECT  64.512 35.797 64.536 37.573 ;
     RECT  77.232 36.901 78.408 37.573 ;
     RECT  79.776 37.091 79.896 37.573 ;
     RECT  12.528 36.803 13.512 37.619 ;
     RECT  59.424 37.477 59.88 37.619 ;
     RECT  4.32 37.475 11.4 37.667 ;
     RECT  104.88 34.595 105.312 37.667 ;
     RECT  39.888 36.131 40.872 37.715 ;
     RECT  48.96 37.477 51.312 37.715 ;
     RECT  42.72 36.373 42.744 37.765 ;
     RECT  59.424 37.619 59.784 37.859 ;
     RECT  42.72 37.765 42.792 37.861 ;
     RECT  152.544 36.659 156.216 37.909 ;
     RECT  15.36 37.043 15.384 37.955 ;
     RECT  42.48 37.861 42.792 37.955 ;
     RECT  38.784 37.861 38.808 37.957 ;
     RECT  38.784 37.957 38.904 38.003 ;
     RECT  42.48 37.955 42.504 38.003 ;
     RECT  131.568 37.045 133.8 38.003 ;
     RECT  18.6 36.853 19.992 38.005 ;
     RECT  67.2 37.091 67.512 38.005 ;
     RECT  68.928 37.861 68.952 38.005 ;
     RECT  152.544 37.909 156.408 38.005 ;
     RECT  157.488 36.805 160.584 38.005 ;
     RECT  115.248 36.373 116.112 38.051 ;
     RECT  38.88 38.003 38.904 38.147 ;
     RECT  67.2 38.005 68.952 38.147 ;
     RECT  96 37.957 96.024 38.147 ;
     RECT  145.632 36.949 146.328 38.147 ;
     RECT  72 37.235 72.912 38.149 ;
     RECT  146.304 38.147 146.328 38.149 ;
     RECT  74.112 36.419 75.912 38.195 ;
     RECT  110.4 37.525 111.192 38.195 ;
     RECT  31.92 36.133 31.944 38.197 ;
     RECT  4.32 37.667 11.064 38.243 ;
     RECT  39.888 37.715 40.512 38.243 ;
     RECT  45.6 37.525 46.728 38.243 ;
     RECT  58.128 36.803 58.152 38.243 ;
     RECT  61.68 37.235 62.112 38.243 ;
     RECT  47.952 37.237 47.976 38.293 ;
     RECT  48.96 37.715 49.032 38.293 ;
     RECT  152.544 38.005 160.584 38.293 ;
     RECT  161.808 37.477 161.88 38.293 ;
     RECT  45.6 38.243 46.152 38.339 ;
     RECT  109.2 37.571 109.224 38.387 ;
     RECT  61.8 38.243 62.112 38.485 ;
     RECT  63.696 37.573 64.536 38.485 ;
     RECT  41.712 38.149 42.264 38.531 ;
     RECT  152.544 38.293 161.88 38.579 ;
     RECT  53.04 38.485 53.064 38.675 ;
     RECT  47.952 38.293 49.032 38.677 ;
     RECT  50.16 37.715 51.312 38.677 ;
     RECT  47.952 38.677 51.312 38.723 ;
     RECT  77.232 37.573 79.896 38.723 ;
     RECT  31.296 38.197 31.944 38.725 ;
     RECT  137.4 36.947 137.712 38.725 ;
     RECT  4.32 38.243 10.584 38.771 ;
     RECT  155.376 38.579 161.88 38.771 ;
     RECT  124.224 37.861 124.248 38.773 ;
     RECT  18.384 38.005 19.992 38.819 ;
     RECT  25.776 36.851 26.328 38.819 ;
     RECT  61.8 38.485 64.536 38.819 ;
     RECT  77.232 38.723 79.8 38.819 ;
     RECT  81.168 37.477 82.248 38.819 ;
     RECT  61.8 38.819 63.72 38.915 ;
     RECT  146.304 38.149 146.808 38.915 ;
     RECT  45.6 38.339 45.912 38.965 ;
     RECT  90.624 38.917 90.648 39.013 ;
     RECT  24 37.573 24.504 39.059 ;
     RECT  67.2 38.147 68.088 39.107 ;
     RECT  81.168 38.819 81.192 39.107 ;
     RECT  92.736 35.845 92.76 39.109 ;
     RECT  92.736 39.109 92.904 39.155 ;
     RECT  28.464 37.571 29.712 39.203 ;
     RECT  70.416 36.661 70.728 39.203 ;
     RECT  45.12 38.965 45.912 39.205 ;
     RECT  82.224 38.819 82.248 39.205 ;
     RECT  83.4 35.987 83.712 39.205 ;
     RECT  82.224 39.205 83.712 39.251 ;
     RECT  61.8 38.915 63.672 39.253 ;
     RECT  142.8 34.979 143.112 39.253 ;
     RECT  18.384 38.819 19.896 39.299 ;
     RECT  49.968 38.723 51.312 39.299 ;
     RECT  144.144 38.677 144.168 39.299 ;
     RECT  34.704 36.949 35.112 39.301 ;
     RECT  118.704 38.101 118.728 39.301 ;
     RECT  152.544 38.579 154.344 39.301 ;
     RECT  45.024 39.205 45.912 39.347 ;
     RECT  70.416 39.203 70.44 39.349 ;
     RECT  30.768 38.725 31.944 39.395 ;
     RECT  33.072 38.149 33.096 39.395 ;
     RECT  70.272 39.349 70.44 39.395 ;
     RECT  54.384 38.773 54.408 39.443 ;
     RECT  117.936 39.301 118.728 39.491 ;
     RECT  133.776 38.003 133.8 39.493 ;
     RECT  50.4 39.299 51.312 39.539 ;
     RECT  133.776 39.493 133.944 39.635 ;
     RECT  41.712 38.531 41.736 39.637 ;
     RECT  42.816 39.301 42.936 39.637 ;
     RECT  152.208 39.301 154.344 39.683 ;
     RECT  2.4 37.475 2.712 39.733 ;
     RECT  41.712 39.637 42.984 39.827 ;
     RECT  59.76 37.859 59.784 39.829 ;
     RECT  41.712 39.827 41.736 39.875 ;
     RECT  90.624 39.013 91.176 39.875 ;
     RECT  61.536 39.253 63.672 39.877 ;
     RECT  70.272 39.395 70.296 39.877 ;
     RECT  136.224 38.149 136.248 39.877 ;
     RECT  20.88 39.301 20.904 39.923 ;
     RECT  31.296 39.395 31.944 39.923 ;
     RECT  59.76 39.829 60.36 39.923 ;
     RECT  61.536 39.877 64.296 39.923 ;
     RECT  115.44 38.051 116.112 39.923 ;
     RECT  135.696 39.877 136.248 39.923 ;
     RECT  140.976 36.851 141 39.923 ;
     RECT  155.376 38.771 160.584 39.923 ;
     RECT  131.568 38.003 132.312 39.925 ;
     RECT  42.72 39.827 42.984 39.971 ;
     RECT  133.872 39.635 133.944 39.971 ;
     RECT  31.296 39.923 31.32 40.019 ;
     RECT  34.224 39.301 35.112 40.019 ;
     RECT  135.696 39.923 136.2 40.019 ;
     RECT  42.816 39.971 42.84 40.067 ;
     RECT  142.512 39.253 143.112 40.067 ;
     RECT  82.608 39.251 83.712 40.069 ;
     RECT  146.304 38.915 146.328 40.165 ;
     RECT  103.344 40.069 103.368 40.211 ;
     RECT  47.952 38.723 48.504 40.259 ;
     RECT  124.224 38.773 125.016 40.259 ;
     RECT  117.936 39.491 117.96 40.307 ;
     RECT  4.416 38.771 10.584 40.355 ;
     RECT  137.28 38.725 137.712 40.355 ;
     RECT  161.808 38.771 161.88 40.357 ;
     RECT  2.4 39.733 2.808 40.405 ;
     RECT  130.704 39.925 132.312 40.451 ;
     RECT  4.416 40.355 5.784 40.453 ;
     RECT  50.88 39.539 51.312 40.499 ;
     RECT  74.88 38.195 75.912 40.499 ;
     RECT  60.144 39.923 60.36 40.547 ;
     RECT  61.8 39.923 64.296 40.547 ;
     RECT  71.808 38.149 72.912 40.549 ;
     RECT  77.232 38.819 79.368 40.549 ;
     RECT  60.288 40.547 60.36 40.595 ;
     RECT  69.696 39.877 70.296 40.597 ;
     RECT  71.76 40.549 72.912 40.597 ;
     RECT  131.568 40.451 132.312 40.597 ;
     RECT  24 39.059 24.408 40.643 ;
     RECT  85.584 36.371 85.608 40.643 ;
     RECT  138.816 38.773 138.84 40.835 ;
     RECT  38.88 40.741 38.904 40.883 ;
     RECT  74.88 40.499 75.864 40.883 ;
     RECT  18.384 39.299 19.464 40.885 ;
     RECT  61.8 40.547 63.672 40.931 ;
     RECT  24 40.643 24.312 40.933 ;
     RECT  2.304 40.405 2.808 40.979 ;
     RECT  60.288 40.595 60.312 40.979 ;
     RECT  18.096 40.885 19.464 40.981 ;
     RECT  121.2 30.851 121.512 40.981 ;
     RECT  148.2 36.947 148.512 40.981 ;
     RECT  155.376 39.923 157.512 40.981 ;
     RECT  158.64 39.923 160.584 40.981 ;
     RECT  75.696 40.883 75.864 41.027 ;
     RECT  82.608 40.069 84.408 41.029 ;
     RECT  124.224 40.259 124.728 41.029 ;
     RECT  131.568 40.597 132.408 41.029 ;
     RECT  133.872 39.971 133.896 41.029 ;
     RECT  149.904 39.925 149.928 41.029 ;
     RECT  63.648 40.931 63.672 41.075 ;
     RECT  67.2 39.107 67.608 41.075 ;
     RECT  77.232 40.549 80.328 41.075 ;
     RECT  81.792 41.029 84.408 41.075 ;
     RECT  48.48 40.259 48.504 41.173 ;
     RECT  56.4 37.091 56.808 41.173 ;
     RECT  121.2 40.981 121.992 41.173 ;
     RECT  21.84 40.597 21.864 41.221 ;
     RECT  69.696 40.597 72.912 41.267 ;
     RECT  92.88 39.155 92.904 41.267 ;
     RECT  3.888 40.453 5.784 41.317 ;
     RECT  6.912 40.355 10.584 41.317 ;
     RECT  149.856 41.029 149.928 41.317 ;
     RECT  70.176 41.267 72.912 41.365 ;
     RECT  152.304 39.683 154.344 41.411 ;
     RECT  145.296 39.877 145.32 41.459 ;
     RECT  149.856 41.317 150.456 41.461 ;
     RECT  136.176 40.019 136.2 41.509 ;
     RECT  56.4 41.173 56.904 41.603 ;
     RECT  86.64 41.029 86.664 41.605 ;
     RECT  3.888 41.317 10.584 41.651 ;
     RECT  56.4 41.603 56.808 41.651 ;
     RECT  66.144 39.877 66.168 41.651 ;
     RECT  70.176 41.365 73.848 41.651 ;
     RECT  77.232 41.075 80.088 41.651 ;
     RECT  86.64 41.605 87.144 41.651 ;
     RECT  123.744 41.029 124.728 41.651 ;
     RECT  155.376 40.981 160.584 41.651 ;
     RECT  161.616 40.357 161.88 41.651 ;
     RECT  136.08 41.509 136.2 41.653 ;
     RECT  9.648 41.651 10.584 41.699 ;
     RECT  106.608 40.885 106.632 41.747 ;
     RECT  149.856 41.461 150.504 41.747 ;
     RECT  115.632 39.923 116.112 41.749 ;
     RECT  120.528 41.173 121.992 41.795 ;
     RECT  135.312 41.653 136.2 41.795 ;
     RECT  10.08 41.699 10.584 41.843 ;
     RECT  112.8 38.437 112.824 41.843 ;
     RECT  75.696 41.027 75.816 41.939 ;
     RECT  129.168 41.653 129.192 41.941 ;
     RECT  78 41.651 80.088 41.987 ;
     RECT  105 37.667 105.312 41.989 ;
     RECT  129.168 41.941 129.288 41.989 ;
     RECT  131.568 41.029 133.896 41.989 ;
     RECT  3.888 41.651 8.112 42.131 ;
     RECT  70.176 41.651 71.4 42.131 ;
     RECT  98.88 36.467 99.912 42.133 ;
     RECT  3.888 42.131 5.352 42.179 ;
     RECT  48.48 41.173 49.416 42.179 ;
     RECT  58.704 41.509 58.728 42.179 ;
     RECT  130.752 41.989 133.896 42.179 ;
     RECT  152.736 41.411 154.344 42.179 ;
     RECT  64.08 41.557 64.104 42.227 ;
     RECT  70.176 42.131 71.256 42.227 ;
     RECT  2.304 40.979 2.712 42.229 ;
     RECT  3.888 42.179 5.016 42.229 ;
     RECT  120.528 41.795 121.608 42.229 ;
     RECT  98.592 42.133 99.912 42.275 ;
     RECT  128.832 41.989 129.288 42.275 ;
     RECT  2.304 42.229 5.016 42.323 ;
     RECT  129.264 42.275 129.288 42.323 ;
     RECT  109.152 41.221 109.176 42.325 ;
     RECT  146.304 40.165 147.096 42.371 ;
     RECT  119.616 42.229 121.608 42.419 ;
     RECT  141.264 41.557 141.288 42.419 ;
     RECT  148.2 40.981 148.824 42.421 ;
     RECT  136.08 41.795 136.2 42.467 ;
     RECT  67.2 41.075 67.512 42.469 ;
     RECT  129.408 42.325 129.576 42.515 ;
     RECT  114.48 40.981 114.504 42.517 ;
     RECT  115.632 41.749 117.096 42.517 ;
     RECT  131.424 42.179 133.896 42.563 ;
     RECT  148.2 42.421 148.872 42.563 ;
     RECT  146.304 42.371 146.328 42.565 ;
     RECT  142.8 40.067 143.112 42.613 ;
     RECT  114.48 42.517 117.096 42.659 ;
     RECT  27.456 40.405 27.48 42.707 ;
     RECT  75.696 41.939 75.72 42.707 ;
     RECT  155.712 41.651 160.584 42.707 ;
     RECT  95.76 41.413 95.784 42.709 ;
     RECT  136.176 42.467 136.2 42.709 ;
     RECT  137.4 40.355 137.712 42.709 ;
     RECT  145.44 42.565 146.328 42.709 ;
     RECT  149.952 41.747 150.504 42.755 ;
     RECT  158.688 42.707 160.584 42.755 ;
     RECT  21.84 41.221 22.248 42.757 ;
     RECT  10.128 41.843 10.584 42.803 ;
     RECT  18.096 40.981 19.944 42.803 ;
     RECT  115.8 42.659 117.096 42.803 ;
     RECT  87.12 41.651 87.144 42.805 ;
     RECT  78 41.987 79.944 42.851 ;
     RECT  115.8 42.803 116.904 42.851 ;
     RECT  136.176 42.709 137.712 42.851 ;
     RECT  10.128 42.803 10.152 42.899 ;
     RECT  98.64 42.275 99.912 42.899 ;
     RECT  56.4 41.651 56.712 42.949 ;
     RECT  79.44 42.851 79.944 42.997 ;
     RECT  81.792 41.075 81.816 42.997 ;
     RECT  95.616 42.709 95.784 42.997 ;
     RECT  61.8 40.931 62.568 43.043 ;
     RECT  79.44 42.997 81.816 43.043 ;
     RECT  95.616 42.997 95.832 43.043 ;
     RECT  123.744 41.651 123.768 43.043 ;
     RECT  86.64 42.805 87.144 43.091 ;
     RECT  161.616 41.651 161.64 43.091 ;
     RECT  148.2 42.563 148.824 43.141 ;
     RECT  153.264 42.179 154.344 43.141 ;
     RECT  155.712 42.707 156.936 43.141 ;
     RECT  36.528 43.045 36.552 43.187 ;
     RECT  142.8 42.613 143.208 43.285 ;
     RECT  21.792 42.757 22.248 43.331 ;
     RECT  108.816 42.325 109.176 43.331 ;
     RECT  72.432 41.651 73.848 43.333 ;
     RECT  91.152 39.875 91.176 43.379 ;
     RECT  95.76 43.043 95.832 43.379 ;
     RECT  109.152 43.331 109.176 43.379 ;
     RECT  153.264 43.141 156.936 43.379 ;
     RECT  6.912 42.131 8.112 43.381 ;
     RECT  2.304 42.323 4.44 43.427 ;
     RECT  16.032 41.221 16.056 43.427 ;
     RECT  19.92 42.803 19.944 43.427 ;
     RECT  131.424 42.563 132.84 43.475 ;
     RECT  72.432 43.333 74.136 43.571 ;
     RECT  153.264 43.379 154.152 43.571 ;
     RECT  155.136 43.379 156.936 43.571 ;
     RECT  6.912 43.381 8.904 43.619 ;
     RECT  153.264 43.571 154.008 43.619 ;
     RECT  99.168 42.899 99.912 43.667 ;
     RECT  147.552 43.141 148.824 43.715 ;
     RECT  129.408 42.515 129.432 43.717 ;
     RECT  148.2 43.715 148.824 43.763 ;
     RECT  158.736 42.755 159.768 43.813 ;
     RECT  56.4 42.949 56.808 43.859 ;
     RECT  67.104 42.469 67.512 43.861 ;
     RECT  70.176 42.227 70.296 43.861 ;
     RECT  78 42.851 78.312 43.861 ;
     RECT  80.88 43.043 81.816 43.861 ;
     RECT  83.4 41.075 84.408 43.861 ;
     RECT  145.296 42.709 146.328 43.861 ;
     RECT  158.736 43.813 160.152 43.861 ;
     RECT  105 41.989 105.576 43.907 ;
     RECT  69.36 43.861 70.296 43.909 ;
     RECT  2.304 43.427 3.768 43.955 ;
     RECT  21.84 43.331 22.248 43.955 ;
     RECT  69.36 43.909 70.68 43.955 ;
     RECT  87.12 43.091 87.144 43.955 ;
     RECT  120.528 42.419 121.608 43.955 ;
     RECT  133.872 42.563 133.896 43.955 ;
     RECT  136.944 42.851 137.712 43.955 ;
     RECT  145.248 43.861 146.328 43.955 ;
     RECT  153.504 43.619 154.008 43.955 ;
     RECT  126.6 30.131 126.912 43.957 ;
     RECT  129.408 43.717 129.912 44.003 ;
     RECT  149.952 42.755 150.456 44.051 ;
     RECT  7.8 43.619 8.904 44.099 ;
     RECT  153.6 43.955 154.008 44.099 ;
     RECT  101.424 43.285 101.448 44.101 ;
     RECT  101.424 44.101 102.216 44.243 ;
     RECT  142.704 43.285 143.208 44.293 ;
     RECT  80.88 43.861 84.408 44.339 ;
     RECT  103.392 42.709 103.416 44.339 ;
     RECT  139.056 43.285 139.08 44.339 ;
     RECT  149.952 44.051 149.976 44.341 ;
     RECT  95.808 43.379 95.832 44.387 ;
     RECT  158.496 43.861 160.152 44.389 ;
     RECT  2.304 43.955 3.432 44.435 ;
     RECT  77.52 43.861 78.312 44.437 ;
     RECT  80.88 44.339 80.952 44.437 ;
     RECT  142.704 44.293 143.256 44.437 ;
     RECT  2.304 44.435 2.712 44.483 ;
     RECT  22.224 43.955 22.248 44.483 ;
     RECT  48.768 42.179 49.416 44.483 ;
     RECT  131.568 43.475 132.84 44.483 ;
     RECT  155.136 43.571 156.792 44.483 ;
     RECT  48.768 44.483 48.792 44.531 ;
     RECT  145.248 43.955 146.232 44.579 ;
     RECT  158.016 44.389 160.152 44.581 ;
     RECT  72.6 43.571 74.136 44.723 ;
     RECT  7.8 44.099 8.232 44.725 ;
     RECT  26.112 42.661 26.136 44.867 ;
     RECT  155.136 44.483 156.024 44.915 ;
     RECT  146.208 44.579 146.232 44.963 ;
     RECT  69.36 43.955 69.384 45.011 ;
     RECT  80.832 44.437 80.952 45.011 ;
     RECT  149.904 44.341 149.976 45.011 ;
     RECT  158.016 44.581 160.536 45.011 ;
     RECT  18.096 42.803 18.912 45.059 ;
     RECT  82.224 44.339 84.408 45.059 ;
     RECT  142.56 44.437 143.256 45.059 ;
     RECT  158.016 45.011 160.152 45.059 ;
     RECT  46.992 40.981 47.016 45.155 ;
     RECT  131.568 44.483 132.312 45.203 ;
     RECT  158.496 45.059 160.152 45.203 ;
     RECT  153.6 44.099 153.912 45.301 ;
     RECT  5.616 43.237 5.64 45.443 ;
     RECT  129.888 44.003 129.912 45.443 ;
     RECT  108.816 45.109 108.84 45.491 ;
     RECT  6.912 44.725 8.232 45.587 ;
     RECT  125.952 43.957 126.912 45.587 ;
     RECT  23.568 40.933 24.312 45.635 ;
     RECT  70.656 43.955 70.68 45.635 ;
     RECT  117.984 44.725 118.008 45.635 ;
     RECT  149.904 45.011 149.928 45.635 ;
     RECT  137.4 43.955 137.712 45.637 ;
     RECT  82.224 45.059 83.712 45.731 ;
     RECT  66.576 43.861 67.512 45.779 ;
     RECT  120.528 43.955 121.512 45.779 ;
     RECT  101.088 45.685 101.112 45.827 ;
     RECT  6.912 45.587 8.112 45.923 ;
     RECT  158.496 45.203 159.576 45.923 ;
     RECT  108.48 45.829 108.504 45.925 ;
     RECT  16.512 44.965 16.536 45.971 ;
     RECT  74.784 45.013 74.808 45.971 ;
     RECT  77.472 44.437 78.312 45.971 ;
     RECT  142.8 45.059 143.256 45.971 ;
     RECT  108.384 45.925 108.504 46.019 ;
     RECT  108.384 46.019 108.408 46.115 ;
     RECT  102.624 45.637 102.648 46.117 ;
     RECT  80.928 45.011 80.952 46.211 ;
     RECT  134.496 45.541 134.52 46.211 ;
     RECT  140.256 43.909 140.28 46.211 ;
     RECT  155.136 44.915 155.16 46.211 ;
     RECT  158.496 45.923 159.312 46.211 ;
     RECT  21.936 45.589 21.96 46.259 ;
     RECT  72.6 44.723 73.56 46.259 ;
     RECT  82.224 45.731 82.248 46.259 ;
     RECT  102.624 46.117 102.792 46.259 ;
     RECT  137.4 45.637 137.832 46.259 ;
     RECT  153.6 45.301 154.104 46.259 ;
     RECT  79.44 43.043 79.464 46.307 ;
     RECT  2.4 44.483 2.712 46.449 ;
     RECT  7.8 45.923 8.112 46.449 ;
     RECT  13.2 37.619 13.512 46.449 ;
     RECT  18.6 45.059 18.912 46.449 ;
     RECT  24 45.635 24.312 46.449 ;
     RECT  29.4 39.203 29.712 46.449 ;
     RECT  34.8 40.019 35.112 46.449 ;
     RECT  40.2 38.243 40.512 46.449 ;
     RECT  45.6 39.347 45.912 46.449 ;
     RECT  51 40.499 51.312 46.449 ;
     RECT  56.4 43.859 56.712 46.449 ;
     RECT  61.8 43.043 62.112 46.449 ;
     RECT  67.2 45.779 67.512 46.449 ;
     RECT  72.6 46.259 72.912 46.449 ;
     RECT  78 45.971 78.312 46.449 ;
     RECT  83.4 45.731 83.712 46.449 ;
     RECT  88.8 32.531 89.112 46.449 ;
     RECT  94.2 35.507 94.512 46.449 ;
     RECT  99.6 43.667 99.912 46.449 ;
     RECT  105 43.907 105.312 46.449 ;
     RECT  110.4 38.195 110.712 46.449 ;
     RECT  115.8 42.851 116.112 46.449 ;
     RECT  121.2 45.779 121.512 46.449 ;
     RECT  126.6 45.587 126.912 46.449 ;
     RECT  132 45.203 132.312 46.449 ;
     RECT  137.4 46.259 137.712 46.449 ;
     RECT  142.8 45.971 143.112 46.449 ;
     RECT  148.2 43.763 148.512 46.449 ;
     RECT  153.6 46.259 153.912 46.449 ;
     RECT  159 46.211 159.312 46.449 ;
     RECT  2.4 46.449 2.52 46.463 ;
     RECT  7.8 46.449 7.92 46.463 ;
     RECT  13.2 46.449 13.32 46.463 ;
     RECT  18.6 46.449 18.72 46.463 ;
     RECT  24 46.449 24.12 46.463 ;
     RECT  29.4 46.449 29.52 46.463 ;
     RECT  34.8 46.449 34.92 46.463 ;
     RECT  40.2 46.449 40.32 46.463 ;
     RECT  45.6 46.449 45.72 46.463 ;
     RECT  51 46.449 51.12 46.463 ;
     RECT  56.4 46.449 56.52 46.463 ;
     RECT  61.8 46.449 61.92 46.463 ;
     RECT  67.2 46.449 67.32 46.463 ;
     RECT  72.6 46.449 72.72 46.463 ;
     RECT  78 46.449 78.12 46.463 ;
     RECT  83.4 46.449 83.52 46.463 ;
     RECT  88.8 46.449 88.92 46.463 ;
     RECT  94.2 46.449 94.32 46.463 ;
     RECT  99.6 46.449 99.72 46.463 ;
     RECT  105 46.449 105.12 46.463 ;
     RECT  110.4 46.449 110.52 46.463 ;
     RECT  115.8 46.449 115.92 46.463 ;
     RECT  121.2 46.449 121.32 46.463 ;
     RECT  126.6 46.449 126.72 46.463 ;
     RECT  132 46.449 132.12 46.463 ;
     RECT  137.4 46.449 137.52 46.463 ;
     RECT  142.8 46.449 142.92 46.463 ;
     RECT  148.2 46.449 148.32 46.463 ;
     RECT  153.6 46.449 153.72 46.463 ;
     RECT  159 46.449 159.12 46.463 ;
  END
END ot_v41_bf_lane4r_cl
END LIBRARY
